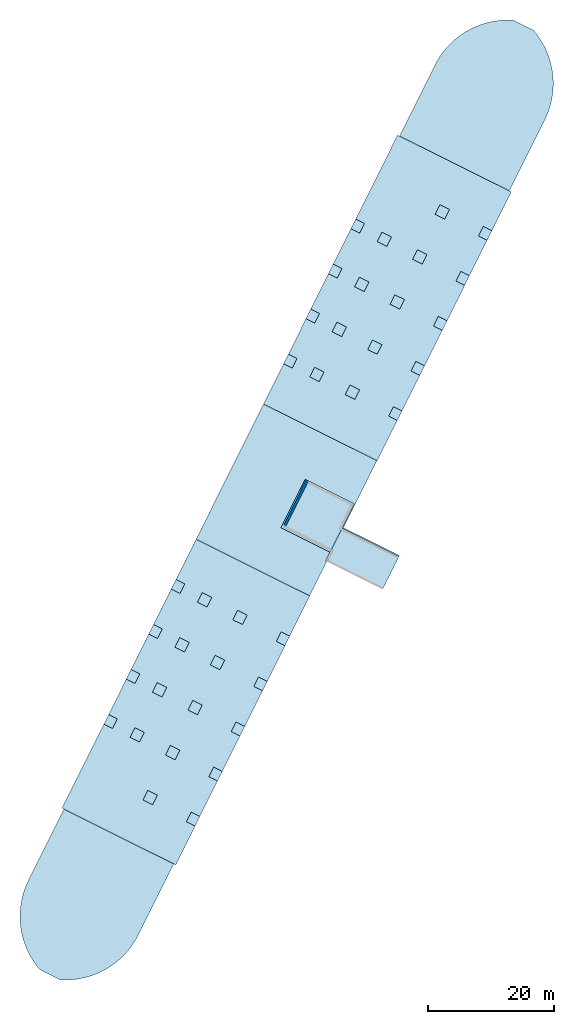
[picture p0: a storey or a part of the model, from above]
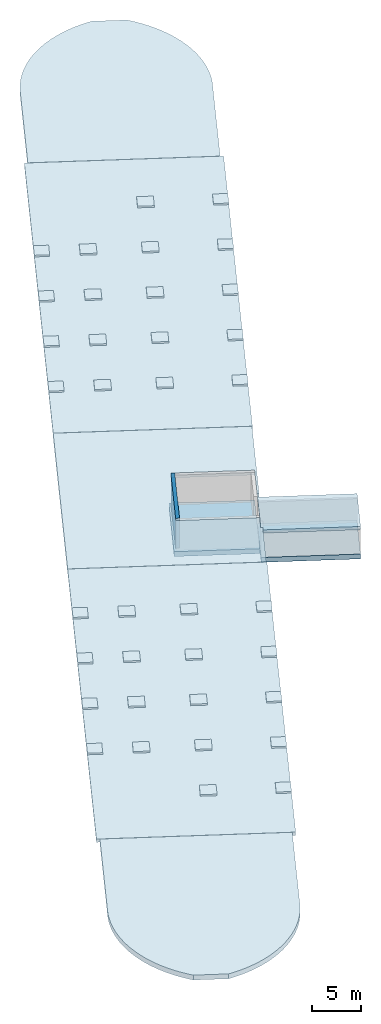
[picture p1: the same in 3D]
Properties of the parts of a building model (IFC2X3), part 1 of 7

# File
Description: ViewDefinition [CoordinationView]
Time: 2016-04-15T14:13:06
Written by: The EXPRESS Data Manager Version 5.02.0100.07 : 28 Aug 2013
Made in: 20140606_1530(x64) - Exporter 2015.0.2014.0606 - Default UI
Comment: STEP Physical File produced by: The EXPRESS Data Manager Version 5.02.0100.07 : 28 Aug 2013 * Module: EDMstepFileFactory/EDMstandAlone * Creation date: Fri Apr 15 14:13:06 2016 * Host: studiopc * Database: C:\Users\FRANCE~1\AppData\Local\Temp\{B8292BB7-F416-45F5-B67B-CA2B80A930D9}\ifc * Database version: 5507 * Database creation date: Fri Apr 15 14:12:46 2016 * Schema: IFC2X3 * Model: DataRepository.ifc * Model creation date: Fri Apr 15 14:12:46 2016 * Header model: DataRepository.ifc_HeaderModel * Header model creation date: Fri Apr 15 14:12:46 2016 * EDMuser: sdai-user * EDMgroup: sdai-group * License ID and type: 5605 : Permanent license. Expiry date: * EDMstepFileFactory options: 020000

# IfcProject
LongName: C:\Users\Francesco\Google Drive\GM Polito\04_APPALTO\IFC\000070_000_RVM_RIL.ifc

# IfcSite, Default
RefLatitude: 41, 53, 43, 677062; RefLongitude: 12, 28, 56, 368560; RefElevation: 250.6 m
Altro - Categoria: Informazioni sul progetto

# IfcBuilding
Pset_BuildingCommon - NumberOfStoreys: 5
Altro - Categoria: Informazioni sul progetto

# IfcBuildingStorey (5)
Altro - Categoria: Livelli; Famiglia: Livello: Livello; Famiglia e tipo: Livello: Livello; ID tipo: Livello: Livello; Tipo: Livello: Livello; Nome famiglia: Livello
Dati identità - Piano edificio: yes; Nome del tipo: Livello
Dimensioni - Altezza di calcolo: 0 m
Grafica - Colore: 0; Modello di linea: Tratto; Simbolo: Estremità Livello: Triangolo; Simbolo a estremità 1 per default: no; Simbolo a estremità 2 per default: yes; Spessore di linea: 1
Vincoli - Base quota altimetrica: Punto base progetto
Name | LongName = Nome | Elevation (m) = Quota altimetrica (m) | Strutturale
SF_STR_0100_XY- Fondazioni (-0,40) | SF_STR_0100_XY- Fondazioni (-0,40) | -0.4 | yes
0 - Piano Terra | 0 - Piano Terra | 0 | no
1 - Piano Primo | 1 - Piano Primo | 4.69 | no
2 - Piano Secondo | 2 - Piano Secondo | 8.61 | no
3 - Piano Copertura | 3 - Piano Copertura | 11.95 | no

# IfcSpace (42)
InteriorOrExteriorSpace: INTERNAL
Altro - Categoria: Locali; Id fase: Stato di Fatto
Analisi energetica - Area per persona: 28.5714 m2; Attiva carico di alimentazione di base: <Default>; Attiva carico luce di base: <Default>; Carico alimentazione effettivo: 0 W; Carico alimentazione effettivo per area: 0; Carico di alimentazione specificato: 0 W; Carico di alimentazione specificato per area: 13.9931; Carico luce effettivo: 0 W; Carico luce effettivo per area: 0; Carico luce specificato: 0 W; Carico luce specificato per area: 10.7639; Contributo di illuminazione vano tecnico: 0.2; Incremento calore latente per persona: 630.918; Incremento calore percepito per persona: 788.648; Incremento calore totale per persona: 1419.57; Numero di persone: 0; Unità carico di alimentazione: Densità alimentazione; Unità carico luce: Densità alimentazione; Valori carico di riscaldamento: <Default>
Dimensioni - Altezza di calcolo: 0 m
Fasi - Fase: Stato di Fatto
Name | In | LongName = Nome | GSA Space Areas (m2) = Area (m2) | Reference | Numero | Altezza non delimitata (m) | Perimetro (m) | Volume (m3) | Limite superiore | Livello | Offset base (m) | Offset limite (m)
3 | 0 - Piano Terra | Deposito oli | 36.2366 | Deposito oli 3 | 3 | 4.29 | 24.8514 | 155.455 | Livello: 0 - Piano Terra | Livello: 0 - Piano Terra | 0 | 4.29
4 | 0 - Piano Terra | Locale | 33.6215 | Locale 4 | 4 | 4.29 | 25.3135 | 143.98 | Livello: 0 - Piano Terra | Livello: 0 - Piano Terra | 0 | 4.29
5 | 0 - Piano Terra | Gruppo elettrogeno | 38.0065 | Gruppo elettrogeno 5 | 5 | 4.29 | 25.3081 | 163.048 | Livello: 0 - Piano Terra | Livello: 0 - Piano Terra | 0 | 4.29
6 | 0 - Piano Terra | Gruppo di pressurizzazione sprinkler-antincendio | 59.008 | Gruppo di pressurizzazione sprinkler-antincendio 6 | 6 | 4.29 | 31.8649 | 252.889 | Livello: 0 - Piano Terra | 0 - Piano Terra | 0 | 4.29
7 | 0 - Piano Terra | Centrale idrica | 48.9236 | Centrale idrica 7 | 7 | 4.29 | 29.2624 | 209.627 | Livello: 0 - Piano Terra | 0 - Piano Terra | 0 | 4.29
8 | 0 - Piano Terra | Consegna teleriscaldamento | 52.4322 | Consegna teleriscaldamento 8 | 8 | 4.29 | 30.1679 | 224.679 | Livello: 0 - Piano Terra | Livello: 0 - Piano Terra | 0 | 4.29
9 | 0 - Piano Terra | Carica batterie e deposito muletti | 45.5483 | Carica batterie e deposito muletti 9 | 9 | 4.29 | 28.3914 | 195.146 | Livello: 0 - Piano Terra | 0 - Piano Terra | 0 | 4.29
10 | 0 - Piano Terra | Barili diesel speciali | 36.6373 | Barili diesel speciali 10 | 10 | 4.29 | 24.9548 | 157.174 | Livello: 0 - Piano Terra | Livello: 0 - Piano Terra | 0 | 4.29
11 | 0 - Piano Terra | Locale quadri elettrici e apparecchiature di controllo autorimessa | 22.04 | Locale quadri elettrici e apparecchiature di controllo autorimessa 11 | 11 | 4.29 | 21 | 94.5516 | Livello: 0 - Piano Terra | 0 - Piano Terra | 0 | 4.29
12 | 0 - Piano Terra | Deposito | 11.0713 | Deposito 12 | 12 | 8.33 | 14.1212 | 92.2242 | Livello: 0 - Piano Terra | Livello: 0 - Piano Terra | 0 | 8.33
13 | 0 - Piano Terra | Locale bombole infiammabili | 11.7486 | Locale bombole infiammabili 13 | 13 | 10.85 | 14.6988 | 127.472 | Livello: 0 - Piano Terra | Livello: 0 - Piano Terra | 0 | 10.85
14 | 0 - Piano Terra | Locale | 10.7987 | Locale 14 | 14 | 8.33 | 14.3188 | 89.9532 | Livello: 0 - Piano Terra | 0 - Piano Terra | 0 | 8.33
15 | 0 - Piano Terra | Locale | 26.9342 | Locale 15 | 15 | 4.29 | 30.7972 | 115.263 | Livello: 0 - Piano Terra | Livello: 0 - Piano Terra | 0 | 4.29
21 | 0 - Piano Terra | Locale | 57.8451 | Locale 21 | 21 | 4.29 | 30.6352 | 248.029 | Livello: 0 - Piano Terra | Livello: 0 - Piano Terra | 0 | 4.29
17 | 0 - Piano Terra | Locale bombole gas di calibrazione | 48.9316 | Locale bombole gas di calibrazione 17 | 17 | 10.86 | 30.58 | 510.626 | Livello: 0 - Piano Terra | 0 - Piano Terra | 0 | 10.86
18 | 0 - Piano Terra | Locale | 8.6832 | Locale 18 | 18 | 8.33 | 12.36 | 72.3311 | Livello: 0 - Piano Terra | Livello: 0 - Piano Terra | 0 | 8.33
20 | 0 - Piano Terra | Locale biciclette | 62.6148 | Locale biciclette 20 | 20 | 4.29 | 31.5859 | 268.434 | Livello: 0 - Piano Terra | 0 - Piano Terra | 0 | 4.29
19 | 0 - Piano Terra | Deposito | 259.894 | Deposito 19 | 19 | 4.29 | 84.7233 | 1112.74 | Livello: 0 - Piano Terra | Livello: 0 - Piano Terra | 0 | 4.29
2 | 0 - Piano Terra | Deposito | 21.606 | Deposito 2 | 2 | 4.29 | 21.34 | 92.6898 | Livello: 0 - Piano Terra | 0 - Piano Terra | 0 | 4.29
1 | 0 - Piano Terra | Deposito | 12.9422 | Deposito 1 | 1 | 8.21 | 18.132 | 106.256 | Livello: 0 - Piano Terra | Livello: 0 - Piano Terra | 0 | 8.21
16 | 0 - Piano Terra | Locale tecnico analisi gas | 23.5989 | Locale tecnico analisi gas 16 | 16 | 4.29 | 19.8327 | 100.827 | Livello: 0 - Piano Terra | Livello: 0 - Piano Terra | 0 | 4.29
22 | 0 - Piano Terra | Garbage | 11.0261 | Garbage 22 | 22 | 8.95 | 15.0395 | 98.6767 | Livello: 0 - Piano Terra | 0 - Piano Terra | 0 | 8.95
23 | 0 - Piano Terra | Oli esausti | 11.4824 | Oli esausti 23 | 23 | 8.95 | 15.391 | 102.768 | Livello: 0 - Piano Terra | Livello: 0 - Piano Terra | 0 | 8.95
24 | 0 - Piano Terra | Deposito bombolo vuote | 11.1803 | Deposito bombolo vuote 24 | 24 | 8.95 | 15.2133 | 100.064 | Livello: 0 - Piano Terra | 0 - Piano Terra | 0 | 8.95
25 | 0 - Piano Terra | Deposito nitrogeno | 10.9086 | Deposito nitrogeno 25 | 25 | 12.2058 | 15.0733 | 97.8209 | Livello: 0 - Piano Terra | Livello: 0 - Piano Terra | -3.2558 | 8.95
26 | 0 - Piano Terra | Corpo scala | 34.0184 | Corpo scala 26 | 26 | 4.69635 | 31.47 | 153.895 | Livello: 0 - Piano Terra | 0 - Piano Terra | -0.00634704 | 4.69
27 | 0 - Piano Terra | Corpo scala | 36.312 | Corpo scala 27 | 27 | 4.69 | 32.41 | 163.528 | Livello: 0 - Piano Terra | 0 - Piano Terra | 0 | 4.69
28 | 0 - Piano Terra | Corpo scala | 34.0184 | Corpo scala 28 | 28 | 4.69 | 31.47 | 153.895 | Livello: 0 - Piano Terra | Livello: 0 - Piano Terra | 0 | 4.69
29 | 0 - Piano Terra | Locale tecnico | 66.511 | Locale tecnico 29 | 29 | 2 | 38.1145 | 132.968 | Livello: 0 - Piano Terra | 0 - Piano Terra | 0 | 2
30 | 0 - Piano Terra | Locale tecnico | 69.5618 | Locale tecnico 30 | 30 | 2 | 39.3326 | 139.124 | Livello: 0 - Piano Terra | 0 - Piano Terra | 0 | 2
31 | 0 - Piano Terra | Deposito gomme | 22.714 | Deposito gomme 31 | 31 | 4.29 | 22.14 | 97.3733 | Livello: 0 - Piano Terra | 0 - Piano Terra | 0 | 4.29
41 | 0 - Piano Terra | Vasca di accumulo sprinkler | 54.0422 | Vasca di accumulo sprinkler 41 | 41 | 11.26 | 27.3109 | 608.514 | Livello: 0 - Piano Terra | 0 - Piano Terra | 0 | 11.26
42 | 0 - Piano Terra | Vasca di accumulo sprinkler | 54.257 | Vasca di accumulo sprinkler 42 | 42 | 11.26 | 27.3699 | 610.564 | Livello: 0 - Piano Terra | 0 - Piano Terra | 0 | 11.26
32 | 1 - Piano Primo | Corpo scala | 35.1848 | Corpo scala 32 | 32 | 3.92 | 24.18 | 131.967 | Livello: 1 - Piano Primo | Livello: 1 - Piano Primo | 0 | 3.92
33 | 1 - Piano Primo | Corpo scala | 36.312 | Corpo scala 33 | 33 | 3.92 | 32.41 | 135.924 | Livello: 1 - Piano Primo | 1 - Piano Primo | 0 | 3.92
34 | 1 - Piano Primo | Corpo scala | 34.0184 | Corpo scala 34 | 34 | 3.92 | 31.47 | 127.873 | Livello: 1 - Piano Primo | Livello: 1 - Piano Primo | 0 | 3.92
35 | 2 - Piano Secondo | Locale | 35.1848 | Locale 35 | 35 | 2.7 | 24.18 | 94.999 | Livello: 2 - Piano Secondo | Livello: 2 - Piano Secondo | 0 | 2.7
36 | 2 - Piano Secondo | Locale | 37.4784 | Locale 36 | 36 | 2.7 | 25.12 | 101.192 | Livello: 2 - Piano Secondo | Livello: 2 - Piano Secondo | 0 | 2.7
37 | 2 - Piano Secondo | Locale | 35.1848 | Locale 37 | 37 | 2.7 | 24.18 | 94.999 | Livello: 2 - Piano Secondo | Livello: 2 - Piano Secondo | 0 | 2.7
38 | 2 - Piano Secondo | Locale | 15.656 | Locale 38 | 38 | 2.4384 | 19.32 | 38.1756 | Livello: 2 - Piano Secondo | Livello: 2 - Piano Secondo | 0 | 2.4384
39 | 2 - Piano Secondo | Locale | 15.4088 | Locale 39 | 39 | 2.4384 | 19.08 | 37.5728 | Livello: 2 - Piano Secondo | 2 - Piano Secondo | 0 | 2.4384
40 | 2 - Piano Secondo | Locale | 13.8422 | Locale 40 | 40 | 2.60145 | 16.5277 | 33.9135 | Livello: 2 - Piano Secondo | Livello: 2 - Piano Secondo | -0.05145 | 2.55

# IfcBeam: Prefabbricato - Trave rettangolare:TRave pref - 60 x 26:167918 (48)
Pset_BeamCommon - LoadBearing: yes; IsExternal: no; Reference: TRave pref - 60 x 26; Slope: 0 deg
Altro - Categoria: Telaio strutturale; Famiglia: Prefabbricato - Trave rettangolare: TRave pref - 60 x 26; Famiglia e tipo: Prefabbricato - Trave rettangolare: TRave pref - 60 x 26; ID tipo: Prefabbricato - Trave rettangolare: TRave pref - 60 x 26; Tipo: Prefabbricato - Trave rettangolare: TRave pref - 60 x 26; Nome famiglia: Prefabbricato - Trave rettangolare
Fasi - Fase di creazione: Stato di Fatto
Posizione geometrica - Giustificazione Y: Origine; Giustificazione YZ: Uniforme; Giustificazione Z: Parte superiore; Stato giunto: Entrambi i giunti attivati; Valore di offset Y: 0 m; Valore di offset Z: 0 m
Strutturale - Attiva modello analitico: yes; Copriferro armatura - Altre superfici: Impostazioni copriferro armatura: Copriferro armatura 1; Copriferro armatura - Superficie inferiore: Impostazioni copriferro armatura: Copriferro armatura 1; Copriferro armatura - Superficie superiore: Impostazioni copriferro armatura: Copriferro armatura 1; Forma sezione: 0
Vincoli - Offset livello finale: -0.4 m; Offset livello iniziale: -0.4 m; Rotazione trasversale: 0 deg
Dati identità - Nome del tipo: TRave pref - 60 x 26
Dimensioni - b: 0.6 m; h: 0.26 m
Name (Prefabbricato - Trave rettangolare:TRave pref - 60 x 26:...) | In | Span (m) = Lunghezza (m) | Area (m2) | Volume (m3) | Estensione finale (m) | Estensione iniziale (m) | Taglio giunto iniziale (m) | Lunghezza del taglio (m) | Utilizzo strutturale | Livello di riferimento
206021 | 1 - Piano Primo | 7.482 | 6.57332 | 1.16407 | 0 | 0 | -0.29 | 7.462 | Trave primaria | Livello: 1 - Piano Primo | Posizione geometrica - Taglio giunto terminale: -0.29 m; Strutturale - Tipo di associazione fine: Quota altimetrica estremità; Tipo di associazione inizio: Quota altimetrica estremità
206023 | 1 - Piano Primo | 8 | 6.67308 | 1.18217 | 0 | 0 | 0 | 7.578 | Trave primaria | Livello: 1 - Piano Primo | Posizione geometrica - Taglio giunto terminale: -0.29 m; Strutturale - Tipo di associazione fine: Quota altimetrica estremità
206025 | 1 - Piano Primo | 7.482 | 6.5759 | 1.16454 | 0 | 0 | -0.29 | 7.465 | Trave primaria | Livello: 1 - Piano Primo | Posizione geometrica - Taglio giunto terminale: -0.29 m; Strutturale - Tipo di associazione fine: Quota altimetrica estremità; Tipo di associazione inizio: Quota altimetrica estremità
206027 | 1 - Piano Primo | 7.482 | 6.57418 | 1.16423 | 0 | 0 | -0.29 | 7.463 | Trave primaria | Livello: 1 - Piano Primo | Posizione geometrica - Taglio giunto terminale: -0.29 m; Strutturale - Tipo di associazione fine: Quota altimetrica estremità; Tipo di associazione inizio: Quota altimetrica estremità
206029 | 1 - Piano Primo | 7.36 | 6.4899 | 1.14894 | 0 | 0 | -0.29 | 7.365 | Trave primaria | Livello: 1 - Piano Primo | Strutturale - Tipo di associazione inizio: Quota altimetrica estremità
206195 | 1 - Piano Primo | 7.482 | 6.57332 | 1.16407 | 0 | 0 | -0.29 | 7.462 | Trave primaria | Livello: 1 - Piano Primo | Posizione geometrica - Taglio giunto terminale: -0.29 m; Strutturale - Tipo di associazione fine: Quota altimetrica estremità; Tipo di associazione inizio: Quota altimetrica estremità
206197 | 1 - Piano Primo | 7.482 | 6.5759 | 1.16454 | 0 | 0 | -0.29 | 7.465 | Trave primaria | Livello: 1 - Piano Primo | Posizione geometrica - Taglio giunto terminale: -0.29 m; Strutturale - Tipo di associazione fine: Quota altimetrica estremità; Tipo di associazione inizio: Quota altimetrica estremità
206199 | 1 - Piano Primo | 7.482 | 6.57418 | 1.16423 | 0 | 0 | -0.29 | 7.463 | Trave primaria | Livello: 1 - Piano Primo | Posizione geometrica - Taglio giunto terminale: -0.29 m; Strutturale - Tipo di associazione fine: Quota altimetrica estremità; Tipo di associazione inizio: Quota altimetrica estremità
206201 | 1 - Piano Primo | 7.36 | 6.5071 | 1.15206 | 0 | 0 | -0.29 | 7.385 | Trave primaria | Livello: 1 - Piano Primo | Strutturale - Tipo di associazione inizio: Quota altimetrica estremità
206203 | 1 - Piano Primo | 8.183 | 6.56558 | 1.16267 | 0 | 0 | -0.29 | 7.453 | Trave primaria | Livello: 1 - Piano Primo | Posizione geometrica - Taglio giunto terminale: -0.29 m; Strutturale - Tipo di associazione fine: Quota altimetrica estremità; Tipo di associazione inizio: Quota altimetrica estremità
206205 | 1 - Piano Primo | 7.549 | 6.2749 | 1.10994 | 0 | 0 | -0.29 | 7.115 | Altro | Livello: 1 - Piano Primo | Strutturale - Tipo di associazione inizio: Quota altimetrica estremità
206209 | 1 - Piano Primo | 7.32 | 6.4512 | 1.14192 | 0 | 0 |  | 7.32 | Trave primaria | Livello: 1 - Piano Primo
206597 | 1 - Piano Primo | 7.4 | 6.53032 | 1.15627 | -0.4 | 0 |  | 7.412 | Altro | Livello: 1 - Piano Primo | Posizione geometrica - Taglio giunto terminale: -0.29 m; Strutturale - Tipo di associazione fine: Quota altimetrica estremità
206599 | 1 - Piano Primo | 7.473 | 6.56558 | 1.16267 | -0.4 | -0.4 | -0.29 | 7.453 | Trave primaria | Livello: 1 - Piano Primo | Posizione geometrica - Taglio giunto terminale: -0.29 m; Strutturale - Tipo di associazione fine: Quota altimetrica estremità; Tipo di associazione inizio: Quota altimetrica estremità
206601 | 1 - Piano Primo | 7.5 | 6.56902 | 1.16329 | -0.4 | -0.4 | -0.29 | 7.457 | Trave primaria | Livello: 1 - Piano Primo | Posizione geometrica - Taglio giunto terminale: -0.29 m; Strutturale - Tipo di associazione fine: Quota altimetrica estremità; Tipo di associazione inizio: Quota altimetrica estremità
206603 | 1 - Piano Primo | 7.473 | 6.56558 | 1.16267 | -0.4 | -0.4 | -0.29 | 7.453 | Trave primaria | Livello: 1 - Piano Primo | Posizione geometrica - Taglio giunto terminale: -0.29 m; Strutturale - Tipo di associazione fine: Quota altimetrica estremità; Tipo di associazione inizio: Quota altimetrica estremità
206605 | 1 - Piano Primo | 7.099 | 6.26028 | 1.10729 | -0.01 | -0.4 | -0.29 | 7.098 | Altro | Livello: 1 - Piano Primo | Strutturale - Tipo di associazione inizio: Quota altimetrica estremità
206607 | 1 - Piano Primo | 7.473 | 6.56988 | 1.16345 | -0.4 | -0.4 | -0.29 | 7.458 | Trave primaria | Livello: 1 - Piano Primo | Posizione geometrica - Taglio giunto terminale: -0.29 m; Strutturale - Tipo di associazione fine: Quota altimetrica estremità; Tipo di associazione inizio: Quota altimetrica estremità
206609 | 1 - Piano Primo | 7.4 | 6.53032 | 1.15627 | -0.4 | 0 |  | 7.412 | Altro | Livello: 1 - Piano Primo | Posizione geometrica - Taglio giunto terminale: -0.29 m; Strutturale - Tipo di associazione fine: Quota altimetrica estremità
206611 | 1 - Piano Primo | 7.473 | 6.56558 | 1.16267 | -0.4 | -0.4 | -0.29 | 7.453 | Trave primaria | Livello: 1 - Piano Primo | Posizione geometrica - Taglio giunto terminale: -0.29 m; Strutturale - Tipo di associazione fine: Quota altimetrica estremità; Tipo di associazione inizio: Quota altimetrica estremità
206613 | 1 - Piano Primo | 7.5 | 6.56816 | 1.16314 | -0.4 | -0.4 | -0.29 | 7.456 | Trave primaria | Livello: 1 - Piano Primo | Posizione geometrica - Taglio giunto terminale: -0.29 m; Strutturale - Tipo di associazione fine: Quota altimetrica estremità; Tipo di associazione inizio: Quota altimetrica estremità
206615 | 1 - Piano Primo | 7.473 | 6.56558 | 1.16267 | -0.4 | -0.4 | -0.29 | 7.453 | Trave primaria | Livello: 1 - Piano Primo | Posizione geometrica - Taglio giunto terminale: -0.29 m; Strutturale - Tipo di associazione fine: Quota altimetrica estremità; Tipo di associazione inizio: Quota altimetrica estremità
206617 | 1 - Piano Primo | 7.5 | 6.66276 | 1.1803 | -0.01 | -0.4 | -0.29 | 7.566 | Altro | Livello: 1 - Piano Primo | Strutturale - Tipo di associazione inizio: Quota altimetrica estremità
206763 | 2 - Piano Secondo | 8 | 6.90184 | 1.22366 | 0 | 0 | 0 | 7.844 | Trave primaria | Livello: 2 - Piano Secondo | Posizione geometrica - Taglio giunto terminale: 0 m
206765 | 1 - Piano Primo | 7.649 | 6.60084 | 1.16906 | 0 | 0 | 0 | 7.494 | Altro | Livello: 1 - Piano Primo
206767 | 2 - Piano Secondo | 7.746 | 7.04116 | 1.24894 | 0.26 | 0 | 0 | 8.006 | Trave primaria | Livello: 2 - Piano Secondo
206769 | 2 - Piano Secondo | 7.482 | 7.03772 | 1.24831 | 0.26 | 0.26 |  | 8.002 | Trave primaria | Livello: 2 - Piano Secondo
206771 | 2 - Piano Secondo | 7.482 | 7.03772 | 1.24831 | 0.26 | 0.26 |  | 8.002 | Trave primaria | Livello: 2 - Piano Secondo
206773 | 2 - Piano Secondo | 7.36 | 6.7092 | 1.18872 | 0 | 0.26 |  | 7.62 | Trave primaria | Livello: 2 - Piano Secondo
206835 | 2 - Piano Secondo | 7.4 | 6.7608 | 1.19808 | 0.28 | 0 |  | 7.68 | Altro | Livello: 2 - Piano Secondo
206837 | 2 - Piano Secondo | 7.473 | 7.02998 | 1.24691 | 0.26 | 0.26 |  | 7.993 | Trave primaria | Livello: 2 - Piano Secondo
206839 | 2 - Piano Secondo | 7.5 | 7.0446 | 1.24956 | 0.25 | 0.26 |  | 8.01 | Trave primaria | Livello: 2 - Piano Secondo
206841 | 2 - Piano Secondo | 7.473 | 7.01063 | 1.2434 | 0.25 | 0.25 |  | 7.9705 | Trave primaria | Livello: 2 - Piano Secondo
206843 | 2 - Piano Secondo | 7.584 | 6.90184 | 1.22366 | 0 | 0.26 |  | 7.844 | Altro | Livello: 2 - Piano Secondo
206845 | 2 - Piano Secondo | 7.649 | 6.60084 | 1.16906 | 0 | 0 | 0 | 7.494 | Altro | Livello: 2 - Piano Secondo
206873 | 2 - Piano Secondo | 7.679 | 6.75994 | 1.19792 | 0 | 0 |  | 7.679 | Altro | Livello: 2 - Piano Secondo | Posizione geometrica - Taglio giunto terminale: 0 m
206901 | 2 - Piano Secondo | 7.382 | 6.50452 | 1.15159 | 0 | 0 | 0 | 7.382 | Altro | Livello: 2 - Piano Secondo
206945 | 2 - Piano Secondo | 7.48 | 6.5888 | 1.16688 | 0 | 0 |  | 7.48 | Trave primaria | Livello: 2 - Piano Secondo
207009 | 2 - Piano Secondo | 7.399 | 6.74274 | 1.1948 | 0 | 0.26 |  | 7.659 | Altro | Livello: 2 - Piano Secondo
207083 | 2 - Piano Secondo | 8 | 7.03514 | 1.24784 | 0 | 0.26 | 0 | 7.999 | Altro | Livello: 2 - Piano Secondo
207085 | 2 - Piano Secondo | 8 | 7.036 | 1.248 | 0 | 0.26 | 0 | 8 | Altro | Livello: 2 - Piano Secondo
207087 | 2 - Piano Secondo | 8 | 7.036 | 1.248 | 0 | 0.26 | 0 | 8 | Altro | Livello: 2 - Piano Secondo
207089 | 2 - Piano Secondo | 7.999 | 7.03514 | 1.24784 | 0 | 0.26 | 0 | 7.999 | Altro | Livello: 2 - Piano Secondo
207091 | 2 - Piano Secondo | 7.1 | 6.5028 | 1.15128 | 0.28 | 0.26 | 0 | 7.38 | Altro | Livello: 2 - Piano Secondo
207101 | 2 - Piano Secondo | 7.999 | 7.03514 | 1.24784 | 0 | 0 |  | 7.999 | Altro | Livello: 2 - Piano Secondo | Posizione geometrica - Taglio giunto terminale: 0 m
207103 | 2 - Piano Secondo | 8 | 7.03514 | 1.24784 | 0 | 0 |  | 7.999 | Altro | Livello: 2 - Piano Secondo | Posizione geometrica - Taglio giunto terminale: 0 m
207105 | 2 - Piano Secondo | 8 | 7.03514 | 1.24784 | 0 | 0 |  | 7.999 | Altro | Livello: 2 - Piano Secondo | Posizione geometrica - Taglio giunto terminale: 0 m
207107 | 2 - Piano Secondo | 7.98 | 7.01794 | 1.24472 | 0 | 0 |  | 7.979 | Altro | Livello: 2 - Piano Secondo | Posizione geometrica - Taglio giunto terminale: 0 m

# IfcBeam: Prefabbricato - Trave rettangolare:TRave pref - 80 x 26:167920 (52)
Pset_BeamCommon - LoadBearing: yes; IsExternal: no; Slope: 0 deg; Reference: TRave pref - 80 x 26
Altro - Categoria: Telaio strutturale; Famiglia: Prefabbricato - Trave rettangolare: TRave pref - 80 x 26; Famiglia e tipo: Prefabbricato - Trave rettangolare: TRave pref - 80 x 26; ID tipo: Prefabbricato - Trave rettangolare: TRave pref - 80 x 26; Tipo: Prefabbricato - Trave rettangolare: TRave pref - 80 x 26; Nome famiglia: Prefabbricato - Trave rettangolare
Fasi - Fase di creazione: Stato di Fatto
Posizione geometrica - Giustificazione Y: Origine; Giustificazione YZ: Uniforme; Giustificazione Z: Parte superiore; Stato giunto: Entrambi i giunti attivati; Valore di offset Y: 0 m; Valore di offset Z: 0 m
Strutturale - Attiva modello analitico: yes; Copriferro armatura - Altre superfici: Impostazioni copriferro armatura: Copriferro armatura 1; Copriferro armatura - Superficie inferiore: Impostazioni copriferro armatura: Copriferro armatura 1; Copriferro armatura - Superficie superiore: Impostazioni copriferro armatura: Copriferro armatura 1; Forma sezione: 0
Vincoli - Rotazione trasversale: 0 deg; Offset livello finale: -0.4 m; Offset livello iniziale: -0.4 m
Dati identità - Nome del tipo: TRave pref - 80 x 26
Dimensioni - b: 0.8 m; h: 0.26 m
Name (Prefabbricato - Trave rettangolare:TRave pref - 80 x 26:...) | In | Span (m) = Lunghezza (m) | Area (m2) | Volume (m3) | Estensione finale (m) | Estensione iniziale (m) | Taglio giunto iniziale (m) | Taglio giunto terminale (m) | Utilizzo strutturale | Lunghezza del taglio (m) | Livello di riferimento
206175 | 1 - Piano Primo | 7.482 | 8.13892 | 1.55626 | 0 | 0 | -0.29 | -0.29 | Trave primaria | 7.482 | Livello: 1 - Piano Primo | Strutturale - Tipo di associazione fine: Quota altimetrica estremità; Tipo di associazione inizio: Quota altimetrica estremità
206177 | 1 - Piano Primo | 8.199 | 8.24916 | 1.57789 | 0 | 0 |  | -0.29 | Trave primaria | 7.586 | Livello: 1 - Piano Primo | Strutturale - Tipo di associazione fine: Quota altimetrica estremità
206179 | 1 - Piano Primo | 7.482 | 8.1421 | 1.55688 | 0 | 0 | -0.29 | -0.29 | Trave primaria | 7.485 | Livello: 1 - Piano Primo | Strutturale - Tipo di associazione fine: Quota altimetrica estremità; Tipo di associazione inizio: Quota altimetrica estremità
206181 | 1 - Piano Primo | 7.482 | 8.13998 | 1.55646 | 0 | 0 | -0.29 | -0.29 | Trave primaria | 7.483 | Livello: 1 - Piano Primo | Strutturale - Tipo di associazione fine: Quota altimetrica estremità; Tipo di associazione inizio: Quota altimetrica estremità
206183 | 1 - Piano Primo | 7.38 | 8.0467 | 1.53816 | 0 | 0 | -0.29 |  | Trave primaria | 7.395 | Livello: 1 - Piano Primo | Strutturale - Tipo di associazione inizio: Quota altimetrica estremità
206185 | 1 - Piano Primo | 7.482 | 8.13892 | 1.55626 | 0 | 0 | -0.29 | -0.29 | Trave primaria | 7.482 | Livello: 1 - Piano Primo | Strutturale - Tipo di associazione fine: Quota altimetrica estremità; Tipo di associazione inizio: Quota altimetrica estremità
206187 | 1 - Piano Primo | 8.183 | 8.12938 | 1.55438 | 0 | 0 | -0.29 | -0.29 | Trave primaria | 7.473 | Livello: 1 - Piano Primo | Strutturale - Tipo di associazione fine: Quota altimetrica estremità; Tipo di associazione inizio: Quota altimetrica estremità
206189 | 1 - Piano Primo | 8.525 | 8.1421 | 1.55688 | 0 | 0 | -0.29 | -0.29 | Trave primaria | 7.485 | Livello: 1 - Piano Primo | Strutturale - Tipo di associazione fine: Quota altimetrica estremità; Tipo di associazione inizio: Quota altimetrica estremità
206191 | 1 - Piano Primo | 7.482 | 8.14104 | 1.55667 | 0 | 0 | -0.29 | -0.29 | Trave primaria | 7.484 | Livello: 1 - Piano Primo | Strutturale - Tipo di associazione fine: Quota altimetrica estremità; Tipo di associazione inizio: Quota altimetrica estremità
206193 | 1 - Piano Primo | 7.36 | 8.0467 | 1.53816 | 0 | 0 | -0.29 |  | Trave primaria | 7.395 | Livello: 1 - Piano Primo | Strutturale - Tipo di associazione inizio: Quota altimetrica estremità
206207 | 1 - Piano Primo | 7.73 | 7.75096 | 1.48013 | 0 | 0 |  | -0.29 | Trave primaria | 7.116 | Livello: 1 - Piano Primo | Strutturale - Tipo di associazione fine: Quota altimetrica estremità
206211 | 1 - Piano Primo | 7.46 | 8.1156 | 1.55168 | 0 | 0 |  |  | Trave primaria | 7.46 | Livello: 1 - Piano Primo
206513 | 1 - Piano Primo | 7.898 | 8.26188 | 1.58038 | 0 | 0 | 0 | 0 | Trave primaria | 7.598 | Livello: 1 - Piano Primo
206515 | 1 - Piano Primo | 7.686 | 8.06896 | 1.54253 | -0.01 | -0.3 | -0.29 |  | Altro | 7.416 | Livello: 1 - Piano Primo | Strutturale - Tipo di associazione inizio: Quota altimetrica estremità
206517 | 1 - Piano Primo | 7.993 | 8.12938 | 1.55438 | -0.4 | -0.4 | -0.29 | -0.29 | Trave primaria | 7.473 | Livello: 1 - Piano Primo | Strutturale - Tipo di associazione fine: Quota altimetrica estremità; Tipo di associazione inizio: Quota altimetrica estremità
206519 | 1 - Piano Primo | 7.997 | 8.13362 | 1.55522 | -0.4 | -0.4 | -0.29 | -0.29 | Trave primaria | 7.477 | Livello: 1 - Piano Primo | Strutturale - Tipo di associazione fine: Quota altimetrica estremità; Tipo di associazione inizio: Quota altimetrica estremità
206521 | 1 - Piano Primo | 7.998 | 8.13468 | 1.55542 | -0.4 | -0.4 | -0.29 | -0.29 | Trave primaria | 7.478 | Livello: 1 - Piano Primo | Strutturale - Tipo di associazione fine: Quota altimetrica estremità; Tipo di associazione inizio: Quota altimetrica estremità
206523 | 1 - Piano Primo | 7.4 | 7.74354 | 1.47867 | -0.03 | -0.4 | -0.29 |  | Altro | 7.109 | Livello: 1 - Piano Primo | Strutturale - Tipo di associazione inizio: Quota altimetrica estremità
206525 | 1 - Piano Primo | 7.993 | 8.12938 | 1.55438 | -0.4 | -0.4 | -0.29 | -0.29 | Trave primaria | 7.473 | Livello: 1 - Piano Primo | Strutturale - Tipo di associazione fine: Quota altimetrica estremità; Tipo di associazione inizio: Quota altimetrica estremità
206563 | 1 - Piano Primo | 7.686 | 8.06896 | 1.54253 | -0.01 | -0.3 | -0.29 |  | Altro | 7.416 | Livello: 1 - Piano Primo | Strutturale - Tipo di associazione inizio: Quota altimetrica estremità
206565 | 1 - Piano Primo | 7.993 | 8.12938 | 1.55438 | -0.4 | -0.4 | -0.29 | -0.29 | Trave primaria | 7.473 | Livello: 1 - Piano Primo | Strutturale - Tipo di associazione fine: Quota altimetrica estremità; Tipo di associazione inizio: Quota altimetrica estremità
206567 | 1 - Piano Primo | 7.997 | 8.13362 | 1.55522 | -0.4 | -0.4 | -0.29 | -0.29 | Trave primaria | 7.477 | Livello: 1 - Piano Primo | Strutturale - Tipo di associazione fine: Quota altimetrica estremità; Tipo di associazione inizio: Quota altimetrica estremità
206569 | 1 - Piano Primo | 7.58 | 8.22796 | 1.57373 | -0.01 | -0.4 | -0.29 |  | Trave primaria | 7.566 | Livello: 1 - Piano Primo | Strutturale - Tipo di associazione inizio: Quota altimetrica estremità
206571 | 1 - Piano Primo | 7.993 | 8.12938 | 1.55438 | -0.4 | -0.4 | -0.29 | -0.29 | Trave primaria | 7.473 | Livello: 1 - Piano Primo | Strutturale - Tipo di associazione fine: Quota altimetrica estremità; Tipo di associazione inizio: Quota altimetrica estremità
206871 | 2 - Piano Secondo | 7.686 | 8.34456 | 1.59661 | -0.01 | 0 | 0 |  | Altro | 7.676 | Livello: 2 - Piano Secondo
206875 | 2 - Piano Secondo | 7.4 | 8.0272 | 1.53433 | -0.0224 | 0 | 0 |  | Altro | 7.3766 | Livello: 2 - Piano Secondo
206903 | 2 - Piano Secondo | 7.836 | 8.51416 | 1.62989 | 0 | 0 | 0 |  | Trave primaria | 7.836 | Livello: 2 - Piano Secondo
206917 | 2 - Piano Secondo | 7.654 | 8.32124 | 1.59203 | 0 | 0 | 0 |  | Trave primaria | 7.654 | Livello: 2 - Piano Secondo
206943 | 2 - Piano Secondo | 7.654 | 8.32124 | 1.59203 | 0 | 0 | 0 |  | Trave primaria | 7.654 | Livello: 2 - Piano Secondo
206947 | 2 - Piano Secondo | 7.5 | 8.15588 | 1.55958 | 0 | 0 |  | -0.153587 | Trave primaria | 7.498 | Livello: 2 - Piano Secondo
207011 | 2 - Piano Secondo | 7.38 | 8.02974 | 1.53483 | 0 | 0 |  | 0 | Trave primaria | 7.379 | Livello: 2 - Piano Secondo
207037 | 2 - Piano Secondo | 7.846 | 8.52476 | 1.63197 | 0 | 0 |  | 0 | Trave primaria | 7.846 | Livello: 2 - Piano Secondo
207051 | 2 - Piano Secondo | 7.6 | 8.2693 | 1.58184 | 0 | 0 |  | -0.155 | Trave primaria | 7.605 | Livello: 2 - Piano Secondo
207077 | 2 - Piano Secondo | 8.002 | 8.69012 | 1.66442 | 0 | 0 |  |  | Altro | 8.002 | Livello: 2 - Piano Secondo
207079 | 2 - Piano Secondo | 8.006 | 8.6933 | 1.66504 | 0 | -0.4 | 0 | 0 | Altro | 8.005 | Livello: 2 - Piano Secondo
207081 | 2 - Piano Secondo | 8.003 | 8.69118 | 1.66462 | 0 | 0 |  |  | Altro | 8.003 | Livello: 2 - Piano Secondo
207093 | 2 - Piano Secondo | 7.993 | 8.68058 | 1.66254 | 0 | 0 |  |  | Altro | 7.993 | Livello: 2 - Piano Secondo
207095 | 2 - Piano Secondo | 8.006 | 8.6933 | 1.66504 | -0.4 | 0 | 0 | 0 | Altro | 8.005 | Livello: 2 - Piano Secondo
207097 | 2 - Piano Secondo | 8.002 | 8.69012 | 1.66442 | 0 | 0 | 0 |  | Altro | 8.002 | Livello: 2 - Piano Secondo
207099 | 2 - Piano Secondo | 8.003 | 8.69118 | 1.66462 | 0 | 0 |  |  | Altro | 8.003 | Livello: 2 - Piano Secondo
207109 | 2 - Piano Secondo | 7.993 | 8.68058 | 1.66254 | 0 | 0 |  |  | Altro | 7.993 | Livello: 2 - Piano Secondo
207111 | 2 - Piano Secondo | 7.998 | 8.68482 | 1.66338 | 0 | 0 | 0 | 0 | Altro | 7.997 | Livello: 2 - Piano Secondo
207113 | 2 - Piano Secondo | 7.993 | 8.68058 | 1.66254 | 0 | 0 |  |  | Altro | 7.993 | Livello: 2 - Piano Secondo
207115 | 2 - Piano Secondo | 7.998 | 8.68588 | 1.66358 | 0 | 0 | 0 |  | Altro | 7.998 | Livello: 2 - Piano Secondo
207129 | 1 - Piano Primo | 7.649 | 8.15164 | 1.55875 | 0 | 0 | 0 |  | Altro | 7.494 | Livello: 1 - Piano Primo
207143 | 2 - Piano Secondo | 7.649 | 8.15164 | 1.55875 | 0 | 0 | 0 |  | Altro | 7.494 | Livello: 2 - Piano Secondo
207145 | 2 - Piano Secondo | 7.686 | 8.34456 | 1.59661 | -0.01 | 0 | 0 |  | Altro | 7.676 | Livello: 2 - Piano Secondo
207159 | 2 - Piano Secondo | 7.993 | 8.68058 | 1.66254 | 0 | 0 |  |  | Altro | 7.993 | Livello: 2 - Piano Secondo
207161 | 2 - Piano Secondo | 7.998 | 8.68482 | 1.66338 | 0 | -0.4 | 0 | 0 | Altro | 7.997 | Livello: 2 - Piano Secondo
207163 | 2 - Piano Secondo | 7.993 | 8.68058 | 1.66254 | 0 | 0 |  |  | Altro | 7.993 | Livello: 2 - Piano Secondo
207165 | 1 - Piano Primo | 7.899 | 8.26294 | 1.58059 | 0 | 0 | 0 | 0 | Trave primaria | 7.599 | Livello: 1 - Piano Primo
208148 | 2 - Piano Secondo | 7.898 | 8.26188 | 1.58038 | 0 | 0 | 0 | 0 | Trave primaria | 7.598 | Livello: 2 - Piano Secondo

# IfcBuildingElementProxy: Mensola C.A. (57)
Material: Calcestruzzo, gettato in opera
Pset_BuildingElementProxyCommon - Reference: Mensola C.A.
Altro - Categoria: Telaio strutturale
Fasi - Fase di creazione: Stato di Fatto
Strutturale - Copriferro armatura: Impostazioni copriferro armatura: Copriferro armatura 1; Utilizzo strutturale: Altro; Forma sezione: 0
Vincoli - Sposta con l'oggetto più vicino: no
Dati identità - Nome del tipo: Mensola C.A.
Name | In | Famiglia = Famiglia e tipo = ID tipo = Tipo | Area (m2) | Volume (m3) | Prospetto (m) | Nome famiglia
Mensola C.A.:Mensola C.A.:206224 | 0 - Piano Terra | Mensola C.A.: Mensola C.A. | 0.18 | 0.072 | 0 | Mensola C.A.
Mensola C.A.1:Mensola C.A.:206236 | 0 - Piano Terra | Mensola C.A.1: Mensola C.A. | 0.18 | 0.072 | 0 | Mensola C.A.1
Mensola C.A.2:Mensola C.A.:206248 | 0 - Piano Terra | Mensola C.A.2: Mensola C.A. | 0.18 | 0.072 | 0 | Mensola C.A.2
Mensola C.A.3:Mensola C.A.:206260 | 0 - Piano Terra | Mensola C.A.3: Mensola C.A. | 0.18 | 0.072 | 0 | Mensola C.A.3
Mensola C.A.4:Mensola C.A.:206272 | 0 - Piano Terra | Mensola C.A.4: Mensola C.A. | 0.18 | 0.072 | 0 | Mensola C.A.4
Mensola C.A.5:Mensola C.A.:206284 | 0 - Piano Terra | Mensola C.A.5: Mensola C.A. | 0.18 | 0.072 | 0 | Mensola C.A.5
Mensola C.A.6:Mensola C.A.:206296 | 0 - Piano Terra | Mensola C.A.6: Mensola C.A. | 0.17982 | 0.071928 | 0 | Mensola C.A.6
Mensola C.A.7:Mensola C.A.:206308 | 0 - Piano Terra | Mensola C.A.7: Mensola C.A. | 0.17982 | 0.071928 | 0 | Mensola C.A.7
Mensola C.A.8:Mensola C.A.:206320 | 0 - Piano Terra | Mensola C.A.8: Mensola C.A. | 0.18 | 0.072 | 0 | Mensola C.A.8
Mensola C.A.9:Mensola C.A.:206332 | 0 - Piano Terra | Mensola C.A.9: Mensola C.A. | 0.18 | 0.072 | 0 | Mensola C.A.9
Mensola C.A.10:Mensola C.A.:206344 | 0 - Piano Terra | Mensola C.A.10: Mensola C.A. | 0.18 | 0.072 |  | Mensola C.A.10
Mensola C.A.11:Mensola C.A.:206356 | 0 - Piano Terra | Mensola C.A.11: Mensola C.A. | 0.18 | 0.072 |  | Mensola C.A.11
Mensola C.A.12:Mensola C.A.:206368 | 0 - Piano Terra | Mensola C.A.12: Mensola C.A. | 0.18 | 0.072 |  | Mensola C.A.12
Mensola C.A.13:Mensola C.A.:206380 | 0 - Piano Terra | Mensola C.A.13: Mensola C.A. | 0.18 | 0.072 |  | Mensola C.A.13
Mensola C.A.14:Mensola C.A.:206392 | 0 - Piano Terra | Mensola C.A.14: Mensola C.A. | 0.18 | 0.072 | 0 | Mensola C.A.14
Mensola C.A.15:Mensola C.A.:206404 | 0 - Piano Terra | Mensola C.A.15: Mensola C.A. | 0.18 | 0.072 | 0 | Mensola C.A.15
Mensola C.A.16:Mensola C.A.:206416 | 0 - Piano Terra | Mensola C.A.16: Mensola C.A. | 0.18 | 0.072 | 0 | Mensola C.A.16
Mensola C.A.17:Mensola C.A.:206428 | 0 - Piano Terra | Mensola C.A.17: Mensola C.A. | 0.18 | 0.072 | 0 | Mensola C.A.17
Mensola C.A.18:Mensola C.A.:206440 | 0 - Piano Terra | Mensola C.A.18: Mensola C.A. | 0.18 | 0.072 | 0 | Mensola C.A.18
Mensola C.A.19:Mensola C.A.:206452 | 0 - Piano Terra | Mensola C.A.19: Mensola C.A. | 0.18 | 0.072 | 0 | Mensola C.A.19
Mensola C.A.20:Mensola C.A.:206464 | 0 - Piano Terra | Mensola C.A.20: Mensola C.A. | 0.18 | 0.072 | 0 | Mensola C.A.20
Mensola C.A.21:Mensola C.A.:206476 | 0 - Piano Terra | Mensola C.A.21: Mensola C.A. | 0.18 | 0.072 | 0 | Mensola C.A.21
Mensola C.A.22:Mensola C.A.:206488 | 0 - Piano Terra | Mensola C.A.22: Mensola C.A. | 0.18 | 0.072 | 0 | Mensola C.A.22
Mensola C.A.23:Mensola C.A.:206500 | 0 - Piano Terra | Mensola C.A.23: Mensola C.A. | 0.18 | 0.072 | 0 | Mensola C.A.23
Mensola C.A.24:Mensola C.A.:206512 | 0 - Piano Terra | Mensola C.A.24: Mensola C.A. | 2.28 | 0.912 | 0 | Mensola C.A.24
Mensola C.A.26:Mensola C.A.:206550 | 0 - Piano Terra | Mensola C.A.26: Mensola C.A. | 0.18 | 0.072 | 0 | Mensola C.A.26
Mensola C.A.27:Mensola C.A.:206562 | 0 - Piano Terra | Mensola C.A.27: Mensola C.A. | 0.18 | 0.072 | 0 | Mensola C.A.27
Mensola C.A.28:Mensola C.A.:206584 | 0 - Piano Terra | Mensola C.A.28: Mensola C.A. | 0.18 | 0.072 | 0 | Mensola C.A.28
Mensola C.A.29:Mensola C.A.:206596 | 0 - Piano Terra | Mensola C.A.29: Mensola C.A. | 0.18 | 0.072 | 0 | Mensola C.A.29
Mensola C.A.25:Mensola C.A.:206762 | 1 - Piano Primo | Mensola C.A.25: Mensola C.A. | 0.18 | 0.072 | 0 | Mensola C.A.25
Mensola C.A.30:Mensola C.A.:206786 | 1 - Piano Primo | Mensola C.A.30: Mensola C.A. | 0.18 | 0.072 | 0 | Mensola C.A.30
Mensola C.A.31:Mensola C.A.:206798 | 1 - Piano Primo | Mensola C.A.31: Mensola C.A. | 0.18 | 0.072 | 0 | Mensola C.A.31
Mensola C.A.32:Mensola C.A.:206810 | 1 - Piano Primo | Mensola C.A.32: Mensola C.A. | 0.18 | 0.072 | 0 | Mensola C.A.32
Mensola C.A.33:Mensola C.A.:206822 | 1 - Piano Primo | Mensola C.A.33: Mensola C.A. | 0.18 | 0.072 | 0 | Mensola C.A.33
Mensola C.A.34:Mensola C.A.:206834 | 1 - Piano Primo | Mensola C.A.34: Mensola C.A. | 0.18 | 0.072 | 0 | Mensola C.A.34
Mensola C.A.35:Mensola C.A.:206858 | 1 - Piano Primo | Mensola C.A.35: Mensola C.A. | 0.18 | 0.072 | 0 | Mensola C.A.35
Mensola C.A.36:Mensola C.A.:206870 | 1 - Piano Primo | Mensola C.A.36: Mensola C.A. | 0.18 | 0.072 | 0 | Mensola C.A.36
Mensola C.A.37:Mensola C.A.:206888 | 1 - Piano Primo | Mensola C.A.37: Mensola C.A. | 0.18 | 0.072 | 0 | Mensola C.A.37
Mensola C.A.38:Mensola C.A.:206900 | 1 - Piano Primo | Mensola C.A.38: Mensola C.A. | 0.18 | 0.072 | 0 | Mensola C.A.38
Mensola C.A.39:Mensola C.A.:206916 | 1 - Piano Primo | Mensola C.A.39: Mensola C.A. | 0.18 | 0.072 | 0 | Mensola C.A.39
Mensola C.A.40:Mensola C.A.:206930 | 1 - Piano Primo | Mensola C.A.40: Mensola C.A. | 0.18 | 0.072 | 0 | Mensola C.A.40
Mensola C.A.41:Mensola C.A.:206942 | 1 - Piano Primo | Mensola C.A.41: Mensola C.A. | 0.18 | 0.072 | 0 | Mensola C.A.41
Mensola C.A.42:Mensola C.A.:206960 | 1 - Piano Primo | Mensola C.A.42: Mensola C.A. | 0.18 | 0.072 | 0 | Mensola C.A.42
Mensola C.A.43:Mensola C.A.:206972 | 1 - Piano Primo | Mensola C.A.43: Mensola C.A. | 0.18 | 0.072 | 0 | Mensola C.A.43
Mensola C.A.44:Mensola C.A.:206984 | 1 - Piano Primo | Mensola C.A.44: Mensola C.A. | 0.18 | 0.072 | 0 | Mensola C.A.44
Mensola C.A.45:Mensola C.A.:206996 | 1 - Piano Primo | Mensola C.A.45: Mensola C.A. | 0.18 | 0.072 | 0 | Mensola C.A.45
Mensola C.A.46:Mensola C.A.:207008 | 1 - Piano Primo | Mensola C.A.46: Mensola C.A. | 0.18 | 0.072 | 0 | Mensola C.A.46
Mensola C.A.47:Mensola C.A.:207024 | 1 - Piano Primo | Mensola C.A.47: Mensola C.A. | 0.18 | 0.072 | 0 | Mensola C.A.47
Mensola C.A.48:Mensola C.A.:207036 | 1 - Piano Primo | Mensola C.A.48: Mensola C.A. | 0.18 | 0.072 | 0 | Mensola C.A.48
Mensola C.A.49:Mensola C.A.:207050 | 1 - Piano Primo | Mensola C.A.49: Mensola C.A. | 0.18 | 0.072 | 0 | Mensola C.A.49
Mensola C.A.50:Mensola C.A.:207064 | 1 - Piano Primo | Mensola C.A.50: Mensola C.A. | 0.18 | 0.072 | 0 | Mensola C.A.50
Mensola C.A.51:Mensola C.A.:207076 | 1 - Piano Primo | Mensola C.A.51: Mensola C.A. | 0.18 | 0.072 | 0 | Mensola C.A.51
Mensola C.A.52:Mensola C.A.:207128 | 1 - Piano Primo | Mensola C.A.52: Mensola C.A. | 0.18 | 0.072 | 0 | Mensola C.A.52
Mensola C.A.53:Mensola C.A.:207142 | 1 - Piano Primo | Mensola C.A.53: Mensola C.A. | 0.18 | 0.072 | 0 | Mensola C.A.53
Mensola C.A.54:Mensola C.A.:207158 | 1 - Piano Primo | Mensola C.A.54: Mensola C.A. | 0.18 | 0.072 | 0 | Mensola C.A.54
Mensola C.A.55:Mensola C.A.:208161 | 1 - Piano Primo | Mensola C.A.55: Mensola C.A. | 0.18 | 0.072 | 0 | Mensola C.A.55
Mensola C.A.56:Mensola C.A.:208173 | 1 - Piano Primo | Mensola C.A.56: Mensola C.A. | 0.18 | 0.072 | 0 | Mensola C.A.56

# IfcBuildingElementProxy: Mensola allungata (8)
Material: Calcestruzzo, gettato in opera
Pset_BuildingElementProxyCommon - Reference: Mensola allungata
Altro - Categoria: Telaio strutturale
Fasi - Fase di creazione: Stato di Fatto
Strutturale - Copriferro armatura: Impostazioni copriferro armatura: Copriferro armatura 1; Utilizzo strutturale: Altro; Forma sezione: 0
Vincoli - Sposta con l'oggetto più vicino: no
Dati identità - Nome del tipo: Mensola allungata
Name | In | Famiglia = Famiglia e tipo = ID tipo = Tipo | Area (m2) | Volume (m3) | Prospetto (m) | Nome famiglia
Mensola allungata:Mensola allungata:206538 | 0 - Piano Terra | Mensola allungata: Mensola allungata | 2.334 | 0.9336 | 0 | Mensola allungata
Mensola allungata1:Mensola allungata:206630 | 0 - Piano Terra | Mensola allungata1: Mensola allungata | 2.4673 | 0.986921 |  | Mensola allungata1
Mensola allungata2:Mensola allungata:206738 | 0 - Piano Terra | Mensola allungata2: Mensola allungata | 2.2363 | 0.894521 |  | Mensola allungata2
Mensola allungata3:Mensola allungata:206750 | 0 - Piano Terra | Mensola allungata3: Mensola allungata | 2.2333 | 0.893321 |  | Mensola allungata3
Mensola allungata4:Mensola allungata:207997 | 1 - Piano Primo | Mensola allungata4: Mensola allungata | 2.334 | 0.9336 | 0 | Mensola allungata4
Mensola allungata5:Mensola allungata:208009 | 1 - Piano Primo | Mensola allungata5: Mensola allungata | 2.46748 | 0.986991 | 0 | Mensola allungata5
Mensola allungata6:Mensola allungata:208141 | 1 - Piano Primo | Mensola allungata6: Mensola allungata | 2.2363 | 0.894521 | 0 | Mensola allungata6
Mensola allungata7:Mensola allungata:284225 | 1 - Piano Primo | Mensola allungata7: Mensola allungata | 2.2363 | 0.894521 | 0 | Mensola allungata7

# IfcBuildingElementProxy: Telaio strutturale 1 (2)
Material: Calcestruzzo, gettato in opera
Pset_BuildingElementProxyCommon - Reference: Telaio strutturale 1
Altro - Categoria: Telaio strutturale
Dimensioni - Area: 2.06832 m2; Volume: 0.827325 m3
Fasi - Fase di creazione: Stato di Fatto
Strutturale - Copriferro armatura: Impostazioni copriferro armatura: Copriferro armatura 1; Utilizzo strutturale: Altro; Forma sezione: 0
Vincoli - Prospetto: 0 m; Sposta con l'oggetto più vicino: no
Dati identità - Nome del tipo: Telaio strutturale 1
Name | In | Famiglia = Famiglia e tipo = ID tipo = Tipo | Nome famiglia
Telaio strutturale 1:Telaio strutturale 1:207485 | 0 - Piano Terra | Telaio strutturale 1: Telaio strutturale 1 | Telaio strutturale 1
Telaio strutturale 2:Telaio strutturale 1:207556 | 2 - Piano Secondo | Telaio strutturale 2: Telaio strutturale 1 | Telaio strutturale 2

# IfcBuildingElementProxy: Telaio strutturale 11 (2)
Material: Calcestruzzo, gettato in opera
Pset_BuildingElementProxyCommon - Reference: Telaio strutturale 11
Altro - Categoria: Telaio strutturale
Dimensioni - Area: 2.12002 m2; Volume: 0.84801 m3
Fasi - Fase di creazione: Stato di Fatto
Strutturale - Copriferro armatura: Impostazioni copriferro armatura: Copriferro armatura 1; Utilizzo strutturale: Altro; Forma sezione: 0
Vincoli - Sposta con l'oggetto più vicino: no
Dati identità - Nome del tipo: Telaio strutturale 11
Name | In | Famiglia = Famiglia e tipo = ID tipo = Tipo | Nome famiglia
Telaio strutturale 11:Telaio strutturale 11:207825 | 0 - Piano Terra | Telaio strutturale 11: Telaio strutturale 11 | Telaio strutturale 11
Telaio strutturale 13:Telaio strutturale 11:207855 | 2 - Piano Secondo | Telaio strutturale 13: Telaio strutturale 11 | Telaio strutturale 13 | Vincoli - Prospetto: 0 m

# IfcBuildingElementProxy: Telaio strutturale 12 (2)
Material: Calcestruzzo, gettato in opera
Pset_BuildingElementProxyCommon - Reference: Telaio strutturale 12
Altro - Categoria: Telaio strutturale
Dimensioni - Area: 2.09778 m2; Volume: 0.839112 m3
Fasi - Fase di creazione: Stato di Fatto
Strutturale - Copriferro armatura: Impostazioni copriferro armatura: Copriferro armatura 1; Utilizzo strutturale: Altro; Forma sezione: 0
Vincoli - Prospetto: 0 m; Sposta con l'oggetto più vicino: no
Dati identità - Nome del tipo: Telaio strutturale 12
Name | In | Famiglia = Famiglia e tipo = ID tipo = Tipo | Nome famiglia
Telaio strutturale 12:Telaio strutturale 12:207840 | 0 - Piano Terra | Telaio strutturale 12: Telaio strutturale 12 | Telaio strutturale 12
Telaio strutturale 14:Telaio strutturale 12:207870 | 2 - Piano Secondo | Telaio strutturale 14: Telaio strutturale 12 | Telaio strutturale 14

# IfcBuildingElementProxy: Telaio strutturale 16 (3)
Material: Calcestruzzo, gettato in opera
Pset_BuildingElementProxyCommon - Reference: Telaio strutturale 16
Altro - Categoria: Telaio strutturale
Fasi - Fase di creazione: Stato di Fatto
Strutturale - Copriferro armatura: Impostazioni copriferro armatura: Copriferro armatura 1; Utilizzo strutturale: Altro; Forma sezione: 0
Vincoli - Prospetto: 0 m; Sposta con l'oggetto più vicino: no
Dati identità - Nome del tipo: Telaio strutturale 16
Name | In | Famiglia = Famiglia e tipo = ID tipo = Tipo | Area (m2) | Volume (m3) | Nome famiglia
Telaio strutturale 16:Telaio strutturale 16:207949 | 0 - Piano Terra | Telaio strutturale 16: Telaio strutturale 16 | 1.108 | 0.4432 | Telaio strutturale 16
Telaio strutturale 20:Telaio strutturale 16:207973 | 1 - Piano Primo | Telaio strutturale 20: Telaio strutturale 16 | 1.108 | 0.4432 | Telaio strutturale 20
Telaio strutturale 3:Telaio strutturale 16:208201 | 0 - Piano Terra | Telaio strutturale 3: Telaio strutturale 16 | 0.640146 | 0.256058 | Telaio strutturale 3

# IfcBuildingElementProxy: Telaio strutturale 17 (4)
Material: Calcestruzzo, gettato in opera
Pset_BuildingElementProxyCommon - Reference: Telaio strutturale 17
Altro - Categoria: Telaio strutturale
Fasi - Fase di creazione: Stato di Fatto
Strutturale - Copriferro armatura: Impostazioni copriferro armatura: Copriferro armatura 1; Utilizzo strutturale: Altro; Forma sezione: 0
Vincoli - Prospetto: 0 m; Sposta con l'oggetto più vicino: no
Dati identità - Nome del tipo: Telaio strutturale 17
Name | In | Famiglia = Famiglia e tipo = ID tipo = Tipo | Area (m2) | Volume (m3) | Nome famiglia
Telaio strutturale 17:Telaio strutturale 17:207961 | 0 - Piano Terra | Telaio strutturale 17: Telaio strutturale 17 | 1.108 | 0.4432 | Telaio strutturale 17
Telaio strutturale 21:Telaio strutturale 17:207985 | 1 - Piano Primo | Telaio strutturale 21: Telaio strutturale 17 | 1.108 | 0.4432 | Telaio strutturale 21
Telaio strutturale 6:Telaio strutturale 17:208218 | 0 - Piano Terra | Telaio strutturale 6: Telaio strutturale 17 | 2.008 | 0.803199 | Telaio strutturale 6
Telaio strutturale 7:Telaio strutturale 17:208241 | 1 - Piano Primo | Telaio strutturale 7: Telaio strutturale 17 | 2.00805 | 0.80322 | Telaio strutturale 7

# IfcBuildingElementProxy: Telaio strutturale 4 (4)
Material: Calcestruzzo, gettato in opera
Pset_BuildingElementProxyCommon - Reference: Telaio strutturale 4
Altro - Categoria: Telaio strutturale
Fasi - Fase di creazione: Stato di Fatto
Strutturale - Copriferro armatura: Impostazioni copriferro armatura: Copriferro armatura 1; Utilizzo strutturale: Altro; Forma sezione: 0
Vincoli - Prospetto: 0 m; Sposta con l'oggetto più vicino: no
Dati identità - Nome del tipo: Telaio strutturale 4
Name | In | Famiglia = Famiglia e tipo = ID tipo = Tipo | Area (m2) | Volume (m3) | Nome famiglia
Telaio strutturale 4:Telaio strutturale 4:207628 | 0 - Piano Terra | Telaio strutturale 4: Telaio strutturale 4 | 1.108 | 0.4432 | Telaio strutturale 4
Telaio strutturale 8:Telaio strutturale 4:207652 | 1 - Piano Primo | Telaio strutturale 8: Telaio strutturale 4 | 1.108 | 0.4432 | Telaio strutturale 8
Telaio strutturale 10:Telaio strutturale 4:208264 | 0 - Piano Terra | Telaio strutturale 10: Telaio strutturale 4 | 0.799586 | 0.319835 | Telaio strutturale 10
Telaio strutturale 15:Telaio strutturale 4:208275 | 0 - Piano Terra | Telaio strutturale 15: Telaio strutturale 4 | 2.07559 | 0.830235 | Telaio strutturale 15

# IfcBuildingElementProxy: Telaio strutturale 5 (3)
Material: Calcestruzzo, gettato in opera
Pset_BuildingElementProxyCommon - Reference: Telaio strutturale 5
Altro - Categoria: Telaio strutturale
Fasi - Fase di creazione: Stato di Fatto
Strutturale - Copriferro armatura: Impostazioni copriferro armatura: Copriferro armatura 1; Utilizzo strutturale: Altro; Forma sezione: 0
Vincoli - Prospetto: 0 m; Sposta con l'oggetto più vicino: no
Dati identità - Nome del tipo: Telaio strutturale 5
Name | In | Famiglia = Famiglia e tipo = ID tipo = Tipo | Area (m2) | Volume (m3) | Nome famiglia
Telaio strutturale 5:Telaio strutturale 5:207640 | 0 - Piano Terra | Telaio strutturale 5: Telaio strutturale 5 | 1.108 | 0.4432 | Telaio strutturale 5
Telaio strutturale 9:Telaio strutturale 5:207664 | 1 - Piano Primo | Telaio strutturale 9: Telaio strutturale 5 | 1.108 | 0.4432 | Telaio strutturale 9
Telaio strutturale 18:Telaio strutturale 5:208294 | 1 - Piano Primo | Telaio strutturale 18: Telaio strutturale 5 | 2.076 | 0.830401 | Telaio strutturale 18

# IfcBuildingElementProxy: Trave curva (2)
Material: Calcestruzzo, gettato in opera
Pset_BuildingElementProxyCommon - Reference: Trave curva
Altro - Categoria: Telaio strutturale
Dimensioni - Area: 2.18276 m2
Fasi - Fase di creazione: Stato di Fatto
Strutturale - Copriferro armatura: Impostazioni copriferro armatura: Copriferro armatura 1; Utilizzo strutturale: Altro; Forma sezione: 0
Vincoli - Prospetto: 0 m; Sposta con l'oggetto più vicino: no
Dati identità - Nome del tipo: Trave curva
Name | In | Famiglia = Famiglia e tipo = ID tipo = Tipo | Volume (m3) | Nome famiglia
Trave curva:Trave curva:207528 | 0 - Piano Terra | Trave curva: Trave curva | 0.873103 | Trave curva
Trave curva1:Trave curva:207543 | 2 - Piano Secondo | Trave curva1: Trave curva | 0.873104 | Trave curva1

# IfcBuildingElementProxy: Trave in opera 1, Trave in opera 2:Trave in opera 1:208129
In: 1 - Piano Primo
Material: Calcestruzzo, gettato in opera
Pset_BuildingElementProxyCommon - Reference: Trave in opera 1
Altro - Categoria: Telaio strutturale; Famiglia: Trave in opera 2: Trave in opera 1; Famiglia e tipo: Trave in opera 2: Trave in opera 1; ID tipo: Trave in opera 2: Trave in opera 1; Tipo: Trave in opera 2: Trave in opera 1; Nome famiglia: Trave in opera 2
Dimensioni - Area: 2.34312 m2; Volume: 0.937249 m3
Fasi - Fase di creazione: Stato di Fatto
Strutturale - Copriferro armatura: Impostazioni copriferro armatura: Copriferro armatura 1; Utilizzo strutturale: Altro; Forma sezione: 0
Vincoli - Prospetto: 0 m; Sposta con l'oggetto più vicino: no
Dati identità - Nome del tipo: Trave in opera 1

# IfcBuildingElementProxy: Trave setto (16)
Material: Calcestruzzo, gettato in opera
Pset_BuildingElementProxyCommon - Reference: Trave setto
Altro - Categoria: Telaio strutturale
Dimensioni - Area: 1.74 m2
Fasi - Fase di creazione: Stato di Fatto
Strutturale - Copriferro armatura: Impostazioni copriferro armatura: Copriferro armatura 1; Utilizzo strutturale: Altro; Forma sezione: 0
Vincoli - Sposta con l'oggetto più vicino: no
Dati identità - Nome del tipo: Trave setto
Name | In | Famiglia = Famiglia e tipo = ID tipo = Tipo | Volume (m3) | Prospetto (m) | Nome famiglia
Trave setto:Trave setto:206642 | 0 - Piano Terra | Trave setto: Trave setto | 0.696 | 0 | Trave setto
Trave setto1:Trave setto:206654 | 0 - Piano Terra | Trave setto1: Trave setto | 0.696 | 0 | Trave setto1
Trave setto2:Trave setto:206666 | 0 - Piano Terra | Trave setto2: Trave setto | 0.696 | 0 | Trave setto2
Trave setto3:Trave setto:206678 | 0 - Piano Terra | Trave setto3: Trave setto | 0.696 | 0 | Trave setto3
Trave setto4:Trave setto:206690 | 0 - Piano Terra | Trave setto4: Trave setto | 0.695443 | 0 | Trave setto4
Trave setto5:Trave setto:206702 | 0 - Piano Terra | Trave setto5: Trave setto | 0.696 | 0 | Trave setto5
Trave setto6:Trave setto:206714 | 0 - Piano Terra | Trave setto6: Trave setto | 0.696 | 0 | Trave setto6
Trave setto7:Trave setto:206726 | 0 - Piano Terra | Trave setto7: Trave setto | 0.696 |  | Trave setto7
Trave setto8:Trave setto:208021 | 1 - Piano Primo | Trave setto8: Trave setto | 0.696 | 0 | Trave setto8
Trave setto9:Trave setto:208033 | 1 - Piano Primo | Trave setto9: Trave setto | 0.696 | 0 | Trave setto9
Trave setto10:Trave setto:208045 | 1 - Piano Primo | Trave setto10: Trave setto | 0.696 | 0 | Trave setto10
Trave setto11:Trave setto:208057 | 1 - Piano Primo | Trave setto11: Trave setto | 0.696 | 0 | Trave setto11
Trave setto12:Trave setto:208069 | 1 - Piano Primo | Trave setto12: Trave setto | 0.695443 | 0 | Trave setto12
Trave setto13:Trave setto:208081 | 1 - Piano Primo | Trave setto13: Trave setto | 0.696 | 0 | Trave setto13
Trave setto14:Trave setto:208093 | 1 - Piano Primo | Trave setto14: Trave setto | 0.696 | 0 | Trave setto14
Trave setto15:Trave setto:208105 | 1 - Piano Primo | Trave setto15: Trave setto | 0.696 | 0 | Trave setto15

# IfcBuildingElementProxy: Travi in opera 1, Travi in opera 2:Travi in opera 1:208117
In: 1 - Piano Primo
Material: Calcestruzzo, gettato in opera
Pset_BuildingElementProxyCommon - Reference: Travi in opera 1
Altro - Categoria: Telaio strutturale; Famiglia: Travi in opera 2: Travi in opera 1; Famiglia e tipo: Travi in opera 2: Travi in opera 1; ID tipo: Travi in opera 2: Travi in opera 1; Tipo: Travi in opera 2: Travi in opera 1; Nome famiglia: Travi in opera 2
Dimensioni - Area: 2.34048 m2; Volume: 0.936193 m3
Fasi - Fase di creazione: Stato di Fatto
Strutturale - Copriferro armatura: Impostazioni copriferro armatura: Copriferro armatura 1; Utilizzo strutturale: Altro; Forma sezione: 0
Vincoli - Prospetto: 0 m; Sposta con l'oggetto più vicino: no
Dati identità - Nome del tipo: Travi in opera 1

# IfcColumn: 500x500-1 livello centrale (18)
In: 0 - Piano Terra
Type - ElementType: 500x500-1 livello centrale; PredefinedType: COLUMN; Classification: B10 Superstructure (Uniformat); Material: Calcestruzzo - Calcestruzzo prefabbricato - 35 MPa
Type - Altro - Categoria: Pilastri strutturali; Est modiglione 1: yes; Est modiglione 2: no; Est modiglione 3: no; Est modiglione 4: no; Nome famiglia: Prefabbricati-Pilastro rettangolare con modiglioni a più strati; Nord modiglione 1: yes; Nord modiglione 2: no; Nord modiglione 3: no; Nord modiglione 4: no; Numero modiglioni est 1: 1; Numero modiglioni nord 1: 1; Numero modiglioni ovest 1: 1; Numero modiglioni sud 1: 1; Ovest modiglione 1: yes; Ovest modiglione 2: no; Ovest modiglione 3: no; Ovest modiglione 4: no; Sud modiglione 1: yes; Sud modiglione 2: no; Sud modiglione 3: no; Sud modiglione 4: no
Type - Costruzione - Numero modiglioni est: 1; Numero modiglioni nord: 1; Numero modiglioni ovest: 1; Numero modiglioni sud: 1; Tipo modiglione est: Modiglione rettangolare; Tipo modiglione nord: Modiglione rettangolare; Tipo modiglione ovest: Modiglione rettangolare; Tipo modiglione sud: Modiglione rettangolare
Type - Dati identità - Codice assieme: B10; Descrizione assieme: Superstructure; Nome del tipo: 500x500-1 livello centrale
Type - Dimensioni - b: 0.5 m; Est altezza modiglione: 0.4 m; Est larghezza modiglione: 0.47 m; Est profondità modiglione: 0.3 m; h: 0.5 m; Nord altezza modiglione: 0.26 m; Nord larghezza modiglione: 0.47 m; Nord profondità modiglione: 0.2 m; Ovest altezza modiglione: 0.4 m; Ovest larghezza modiglione: 0.47 m; Ovest profondità modiglione: 0.3 m; Smusso: 0.015 m; Sud altezza modiglione: 0.26 m; Sud larghezza modiglione: 0.47 m; Sud profondità modiglione: 0.2 m
Type - Strutturale - Forma sezione: 0
Pset_ColumnCommon - LoadBearing: yes; IsExternal: no; Reference: 500x500-1 livello centrale
Altro - Famiglia: Prefabbricati-Pilastro rettangolare con modiglioni a più strati: 500x500-1 livello centrale; Famiglia e tipo: Prefabbricati-Pilastro rettangolare con modiglioni a più strati: 500x500-1 livello centrale; ID tipo: Prefabbricati-Pilastro rettangolare con modiglioni a più strati: 500x500-1 livello centrale; S armatura singola: 0.49 kN; S asta di collegamento: 0.294 kN; S griglie armatura: 0.98 kN; Tipo: Prefabbricati-Pilastro rettangolare con modiglioni a più strati: 500x500-1 livello centrale
Dimensioni - Area: 13.9242 m2; Est distanza modiglione 1: 3.92 m; Est distanza modiglione 2: 0 m; Est distanza modiglione 3: 0 m; Est distanza modiglione 4: 0 m; Est offset modiglione: 0 m; Lunghezza: 8.15 m; Nord distanza modiglione 1: 3.66 m; Nord distanza modiglione 2: 0 m; Nord distanza modiglione 3: 0 m; Nord distanza modiglione 4: 0 m; Nord offset modiglione: 0 m; Ovest distanza modiglione 1: 3.92 m; Ovest distanza modiglione 2: 0 m; Ovest distanza modiglione 3: 0 m; Ovest distanza modiglione 4: 0 m; Ovest offset modiglione: 0 m; Smusso modiglione: 0.015 m; Sud distanza modiglione 1: 3.66 m; Sud distanza modiglione 2: 0 m; Sud distanza modiglione 3: 0 m; Sud distanza modiglione 4: 0 m; Sud offset modiglione: 0 m; Volume: 2.67886 m3
Fasi - Fase di creazione: Stato di Fatto
Materiali e finiture - Materiale strutturale: Calcestruzzo - Calcestruzzo prefabbricato - 35 MPa
Strutturale - Attiva modello analitico: yes; Copriferro armatura - Altre superfici: Impostazioni copriferro armatura: Copriferro armatura 1; Copriferro armatura - Superficie inferiore: Impostazioni copriferro armatura: Copriferro armatura 1; Copriferro armatura - Superficie superiore: Impostazioni copriferro armatura: Copriferro armatura 1; Spessore armatura singola: 50; Spessore asta di collegamento: 30; Spessore griglie armatura: 100
Vincoli - Delimita il locale: yes; Livello: Livello: 0 - Piano Terra; Livello di base: Livello: 0 - Piano Terra; Livello superiore: Livello: 2 - Piano Secondo; Offset base: -0.2 m; Offset superiore: -0.66 m; Sposta con griglie: yes; Stile pilastro: Verticale
Name (Prefabbricati-Pilastro rettangolare con modiglioni a più strati:500x500-1 livello centrale:...) | Contrassegno di posizione pilastro
205949 | XX(-4.82)-YY
205959 | XX(-11.12)-YY(-7.99)
205961 | XX(-4.82)-YY(8.00)
205967 | XX(-11.12)-YY(8.00)
205969 | XX(-4.82)-YY(16.01)
205975 | XX(-11.12)-YY(16.01)
205977 | XX(-4.82)-YY(24.01)
205983 | XX(-11.12)-YY(24.01)
205985 | XX(-4.82)-YY(64.03)
205991 | XX(-11.12)-YY(64.03)
205993 | XX(-4.82)-YY(72.02)
205999 | XX(-11.12)-YY(72.02)
206001 | XX(-4.82)-YY(80.02)
206007 | XX(-11.12)-YY(80.02)
206009 | XX(-4.82)-YY(88.01)
206015 | XX(-11.12)-YY(88.01)
206019 | XX(-11.12)-YY(96.01)
214301 | XX(-11.12)-YY

# IfcColumn: 520x500-1 livello laterale (18)
In: 0 - Piano Terra
Type - ElementType: 520x500-1 livello laterale; PredefinedType: COLUMN; Classification: B10 Superstructure (Uniformat); Material: Calcestruzzo - Calcestruzzo prefabbricato - 35 MPa
Type - Altro - Categoria: Pilastri strutturali; Est modiglione 1: yes; Est modiglione 2: no; Est modiglione 3: no; Est modiglione 4: no; Nord modiglione 1: yes; Nord modiglione 2: no; Nord modiglione 3: no; Nord modiglione 4: no; Numero modiglioni est 1: 1; Numero modiglioni nord 1: 1; Numero modiglioni ovest 1: 1; Ovest modiglione 1: yes; Ovest modiglione 2: no; Ovest modiglione 3: no; Ovest modiglione 4: no; Sud modiglione 2: no; Sud modiglione 3: no; Sud modiglione 4: no; Nome famiglia: Prefabbricati-Pilastro rettangolare con modiglioni a più strati; Numero modiglioni sud 1: 0; Sud modiglione 1: no
Type - Costruzione - Numero modiglioni est: 1; Numero modiglioni nord: 1; Numero modiglioni ovest: 1; Tipo modiglione est: Modiglione rettangolare; Tipo modiglione nord: Modiglione rettangolare; Tipo modiglione ovest: Modiglione rettangolare; Tipo modiglione sud: Modiglione rettangolare; Numero modiglioni sud: 0
Type - Dati identità - Codice assieme: B10; Descrizione assieme: Superstructure; Nome del tipo: 520x500-1 livello laterale
Type - Dimensioni - b: 0.52 m; Est altezza modiglione: 0.4 m; Est larghezza modiglione: 0.47 m; Est profondità modiglione: 0.3 m; h: 0.5 m; Nord altezza modiglione: 0.26 m; Nord larghezza modiglione: 0.49 m; Nord profondità modiglione: 0.2 m; Ovest altezza modiglione: 0.4 m; Ovest larghezza modiglione: 0.47 m; Ovest profondità modiglione: 0.3 m; Smusso: 0.015 m; Sud altezza modiglione: 0.4 m; Sud larghezza modiglione: 0.15 m; Sud profondità modiglione: 0.2 m
Type - Strutturale - Forma sezione: 0
Pset_ColumnCommon - LoadBearing: yes; IsExternal: no; Reference: 520x500-1 livello laterale
Altro - Famiglia: Prefabbricati-Pilastro rettangolare con modiglioni a più strati: 520x500-1 livello laterale; Famiglia e tipo: Prefabbricati-Pilastro rettangolare con modiglioni a più strati: 520x500-1 livello laterale; ID tipo: Prefabbricati-Pilastro rettangolare con modiglioni a più strati: 520x500-1 livello laterale; S armatura singola: 0.49 kN; S asta di collegamento: 0.294 kN; S griglie armatura: 0.98 kN; Tipo: Prefabbricati-Pilastro rettangolare con modiglioni a più strati: 520x500-1 livello laterale
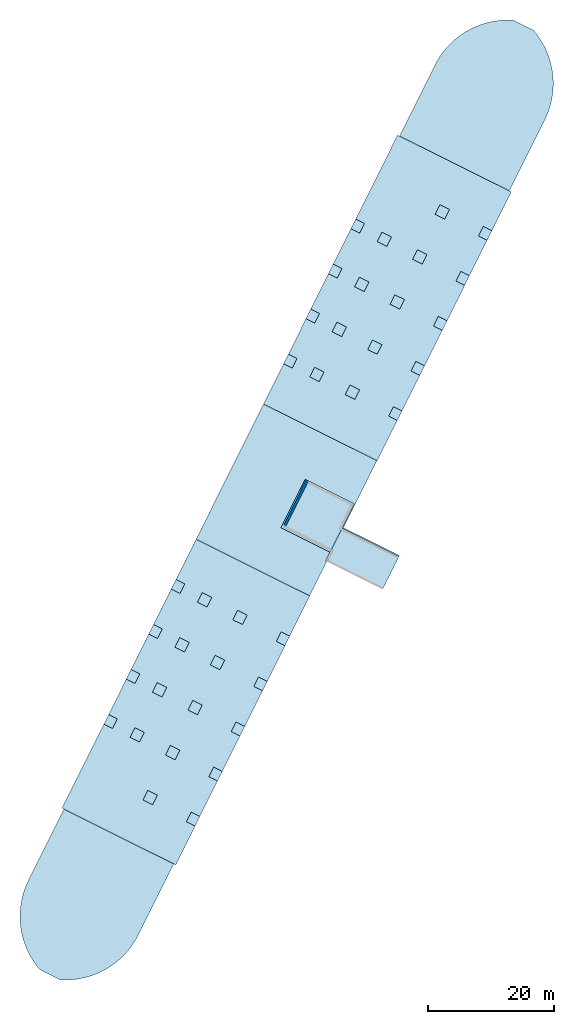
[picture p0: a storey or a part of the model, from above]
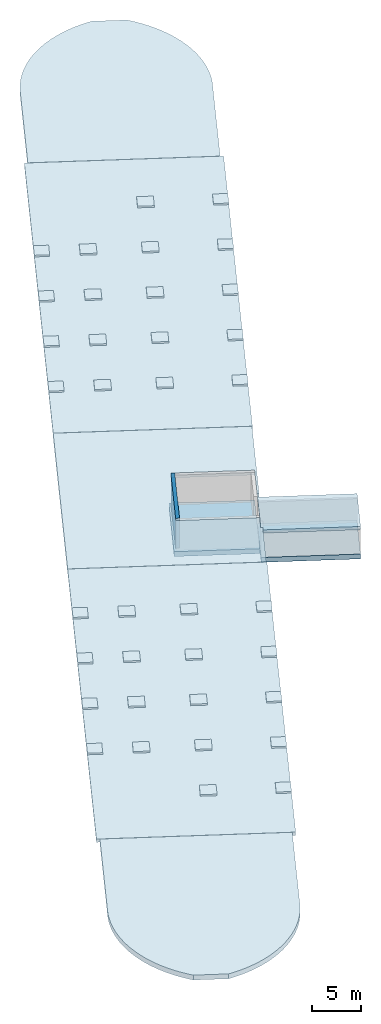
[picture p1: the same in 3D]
Properties of the parts of a building model (IFC2X3), part 2 of 7

# IfcColumn: 520x500-1 livello laterale (18)
Dimensioni - Est distanza modiglione 2: 0 m; Est distanza modiglione 3: 0 m; Est distanza modiglione 4: 0 m; Est offset modiglione: 0 m; Nord distanza modiglione 2: 0 m; Nord distanza modiglione 3: 0 m; Nord distanza modiglione 4: 0 m; Nord offset modiglione: 0 m; Ovest distanza modiglione 2: 0 m; Ovest distanza modiglione 3: 0 m; Ovest distanza modiglione 4: 0 m; Ovest offset modiglione: 0 m; Sud distanza modiglione 2: 0 m; Sud distanza modiglione 3: 0 m; Sud distanza modiglione 4: 0 m; Sud offset modiglione: 0 m; Est distanza modiglione 1: 3.92 m; Lunghezza: 8.15 m; Nord distanza modiglione 1: 3.66 m; Ovest distanza modiglione 1: 3.92 m; Smusso modiglione: 0.015 m; Sud distanza modiglione 1: 3.66 m
Fasi - Fase di creazione: Stato di Fatto
Materiali e finiture - Materiale strutturale: Calcestruzzo - Calcestruzzo prefabbricato - 35 MPa
Strutturale - Attiva modello analitico: yes; Copriferro armatura - Altre superfici: Impostazioni copriferro armatura: Copriferro armatura 1; Copriferro armatura - Superficie inferiore: Impostazioni copriferro armatura: Copriferro armatura 1; Copriferro armatura - Superficie superiore: Impostazioni copriferro armatura: Copriferro armatura 1; Spessore armatura singola: 50; Spessore asta di collegamento: 30; Spessore griglie armatura: 100
Vincoli - Delimita il locale: yes; Livello: Livello: 0 - Piano Terra; Sposta con griglie: yes; Stile pilastro: Verticale; Livello di base: Livello: 0 - Piano Terra; Livello superiore: Livello: 2 - Piano Secondo; Offset base: -0.2 m; Offset superiore: -0.66 m
Name (Prefabbricati-Pilastro rettangolare con modiglioni a più strati:520x500-1 livello laterale:...) | Area (m2) | Volume (m3) | Contrassegno di posizione pilastro
205951 | 13.7518 | 2.71503 | XX-YY
205953 | 13.7518 | 2.71503 | XX(-18.82)-YY
205957 | 13.7518 | 2.71503 | XX(-18.82)-YY(-7.99)
205963 | 13.7518 | 2.71503 | XX-YY(8.00)
205965 | 13.7518 | 2.71503 | XX(-18.82)-YY(8.00)
205971 | 13.7518 | 2.71503 | XX-YY(16.01)
205973 | 13.7518 | 2.71503 | XX(-18.82)-YY(16.01)
205979 | 13.7518 | 2.71503 | XX-YY(24.01)
205981 | 13.7518 | 2.71503 | XX(-18.82)-YY(24.01)
205987 | 13.7518 | 2.71503 | XX-YY(64.03)
205989 | 13.7518 | 2.71503 | XX(-18.82)-YY(64.03)
205995 | 9.59149 | 2.25329 | XX-YY(72.02)
205997 | 13.7518 | 2.71503 | XX(-18.82)-YY(72.02)
206003 | 13.7518 | 2.71503 | XX-YY(80.02)
206005 | 13.7518 | 2.71503 | XX(-18.82)-YY(80.02)
206011 | 13.7518 | 2.71503 | XX-YY(88.01)
206013 | 13.7518 | 2.71503 | XX(-18.82)-YY(88.01)
206017 | 13.7518 | 2.71503 | XX(-18.82)-YY(96.01)

# IfcCovering: Isolamento tubazione:Default (63)
PredefinedType: INSULATION
Pset_CoveringCommon - Reference: Default
Altro - Categoria: Isolamenti tubazioni; Famiglia: Isolamento tubazione: Default; Famiglia e tipo: Isolamento tubazione: Default; ID tipo: Isolamento tubazione: Default; Tipo: Isolamento tubazione: Default; Nome famiglia: Isolamento tubazione
Fasi - Fase di creazione: Stato di Fatto
Meccanica - Spessore isolamento: 0.05 m
Dati identità - Nome del tipo: Default
Name (Isolamento tubazione:...) | In | Contrassegno | Dimensione tubazione | Lunghezza (m) | Tipo di sistema | Area (m2) | Classificazione sistema | Nome sistema | Volume (m3)
Default | 0 - Piano Terra | 15 | 200 mmø | 0.334945 | Sistema di tubazioni: Mandata sistema idronico | 0.33575 | Mandata di sistema idronico | Mandata sistema idronico 30 | 0.0167875
Default | 0 - Piano Terra | 18 | 200 mmø | 2.17 | Sistema di tubazioni: Mandata sistema idronico | 2.17522 | Mandata di sistema idronico | Mandata sistema idronico 30 | 0.108761
Default | 0 - Piano Terra | 19 | 200 mmø | 10.5317 | Sistema di tubazioni: Mandata sistema idronico | 10.557 | Mandata di sistema idronico | Mandata sistema idronico 30 | 0.527849
Default | 0 - Piano Terra | 20 | 200 mmø | 0.3 | Sistema di tubazioni: Mandata sistema idronico | 0.300721 | Mandata di sistema idronico | Mandata sistema idronico 27 | 0.0150361
Default | 0 - Piano Terra | 24 | 200 mmø | 0.297 | Sistema di tubazioni: Mandata sistema idronico | 0.297714 | Mandata di sistema idronico | Mandata sistema idronico 30 | 0.0148857
Default | 0 - Piano Terra | 28 | 200 mmø-200 mmø |  | Sistema di tubazioni: Mandata sistema idronico |  | Mandata di sistema idronico | Mandata sistema idronico 30
Default | 0 - Piano Terra | 29 | 200 mmø-200 mmø |  | Sistema di tubazioni: Mandata sistema idronico |  | Mandata di sistema idronico | Mandata sistema idronico 30
Default | 0 - Piano Terra | 30 | 200 mmø-200 mmø |  | Sistema di tubazioni: Mandata sistema idronico |  | Mandata di sistema idronico | Mandata sistema idronico 30
Default | 0 - Piano Terra | 31 | 200 mmø-200 mmø |  |  |  | Non definito
Default | 0 - Piano Terra | 32 | 200 mmø-200 mmø |  |  |  | Non definito
Default | 0 - Piano Terra | 33 | 200 mmø | 2.17 |  | 2.17522 | Non definito |  | 0.108761
Default | 0 - Piano Terra | 34 | 200 mmø | 0.297 | Sistema di tubazioni: Mandata sistema idronico | 0.297714 | Mandata di sistema idronico | Mandata sistema idronico 26 | 0.0148857
Default | 0 - Piano Terra | 35 | 200 mmø-200 mmø |  | Sistema di tubazioni: Mandata sistema idronico |  | Mandata di sistema idronico | Mandata sistema idronico 26
Default | 0 - Piano Terra | 36 | 200 mmø | 0.334945 |  | 0.33575 | Non definito |  | 0.0167875
Default | 0 - Piano Terra | 37 | 200 mmø-200 mmø |  |  |  | Non definito
Default | 0 - Piano Terra | 38 | 200 mmø-200 mmø |  |  |  | Non definito
Default | 0 - Piano Terra | 39 | 200 mmø | 0.3 | Sistema di tubazioni: Mandata sistema idronico | 0.300721 | Mandata di sistema idronico | Mandata sistema idronico 28 | 0.0150361
Default | 0 - Piano Terra | 40 | 200 mmø-200 mmø |  |  |  | Non definito
Default | 0 - Piano Terra | 41 | 200 mmø-200 mmø |  |  |  | Non definito
Default | 0 - Piano Terra | 42 | 200 mmø | 10.5317 | Sistema di tubazioni: Mandata sistema idronico | 10.557 | Mandata di sistema idronico | Mandata sistema idronico 29 | 0.527849
Default | 0 - Piano Terra | 43 | 150 mmø | 3.5 | Sistema di tubazioni: Mandata sistema idronico | 2.94984 | Mandata di sistema idronico | Mandata sistema idronico 31 | 0.147492
Default | 0 - Piano Terra | 44 | 150 mmø | 22.3898 | Sistema di tubazioni: Mandata sistema idronico | 18.8703 | Mandata di sistema idronico | Mandata sistema idronico 32 | 0.943517
Default | 0 - Piano Terra | 46 | 150 mmø | 0.446147 | Sistema di tubazioni: Mandata sistema idronico | 0.376017 | Mandata di sistema idronico | Mandata sistema idronico 32 | 0.0188009
Default | 0 - Piano Terra | 47 | 150 mmø | 1.946 | Sistema di tubazioni: Mandata sistema idronico | 1.64011 | Mandata di sistema idronico | Mandata sistema idronico 32 | 0.0820055
Default | 0 - Piano Terra | 49 | 150 mmø | 0.296 | Sistema di tubazioni: Mandata sistema idronico | 0.249472 | Mandata di sistema idronico | Mandata sistema idronico 32 | 0.0124736
Default | 0 - Piano Terra | 50 | 150 mmø-150 mmø |  | Sistema di tubazioni: Mandata sistema idronico |  | Mandata di sistema idronico | Mandata sistema idronico 32
Default | 0 - Piano Terra | 51 | 150 mmø | 0.046 | Sistema di tubazioni: Mandata sistema idronico | 0.0387693 | Mandata di sistema idronico | Mandata sistema idronico 32 | 0.00193846
Default | 0 - Piano Terra | 52 | 150 mmø-150 mmø |  | Sistema di tubazioni: Mandata sistema idronico |  | Mandata di sistema idronico | Mandata sistema idronico 32
Default | 0 - Piano Terra | 53 | 150 mmø | 11.5324 | Sistema di tubazioni: Mandata sistema idronico | 9.71961 | Mandata di sistema idronico | Mandata sistema idronico 32 | 0.485981
Default | 0 - Piano Terra | 55 | 150 mmø | 0.046 | Sistema di tubazioni: Mandata sistema idronico | 0.0387693 | Mandata di sistema idronico | Mandata sistema idronico 32 | 0.00193846
Default | 0 - Piano Terra | 56 | 150 mmø-150 mmø |  | Sistema di tubazioni: Mandata sistema idronico |  | Mandata di sistema idronico | Mandata sistema idronico 32
Default | 0 - Piano Terra | 58 | 150 mmø | 0.296 | Sistema di tubazioni: Mandata sistema idronico | 0.249472 | Mandata di sistema idronico | Mandata sistema idronico 32 | 0.0124736
Default | 0 - Piano Terra | 59 | 150 mmø-150 mmø |  | Sistema di tubazioni: Mandata sistema idronico |  | Mandata di sistema idronico | Mandata sistema idronico 32
Default | 0 - Piano Terra | 60 | 150 mmø-150 mmø |  | Sistema di tubazioni: Mandata sistema idronico |  | Mandata di sistema idronico | Mandata sistema idronico 32
Default | 0 - Piano Terra | 61 | 150 mmø-150 mmø |  | Sistema di tubazioni: Mandata sistema idronico |  | Mandata di sistema idronico | Mandata sistema idronico 32
Default | 0 - Piano Terra | 62 | 150 mmø | 0.463862 | Sistema di tubazioni: Mandata sistema idronico | 0.390948 | Mandata di sistema idronico | Mandata sistema idronico 32 | 0.0195474
Default | 0 - Piano Terra | 63 | 150 mmø-150 mmø |  | Sistema di tubazioni: Mandata sistema idronico |  | Mandata di sistema idronico | Mandata sistema idronico 32
Default | 0 - Piano Terra | 64 | 150 mmø-150 mmø |  | Sistema di tubazioni: Mandata sistema idronico |  | Mandata di sistema idronico | Mandata sistema idronico 32
Default | 0 - Piano Terra | 69 | 32 mmø | 5.1438 | Sistema di tubazioni: Mandata sistema idronico | 2.29733 | Mandata di sistema idronico | Mandata sistema idronico 35 | 0.114866
Default | 0 - Piano Terra | 71 | 32 mmø | 0.401836 | Sistema di tubazioni: Mandata sistema idronico | 0.179469 | Mandata di sistema idronico | Mandata sistema idronico 35 | 0.00897344
Default | 0 - Piano Terra | 72 | 32 mmø | 0.17351 | Sistema di tubazioni: Mandata sistema idronico | 0.0774934 | Mandata di sistema idronico | Mandata sistema idronico 35 | 0.00387467
Default | 0 - Piano Terra | 74 | 32 mmø-32 mmø |  | Sistema di tubazioni: Mandata sistema idronico |  | Mandata di sistema idronico | Mandata sistema idronico 35
Default | 0 - Piano Terra | 76 | 50 mmø | 9.7 | Sistema di tubazioni: Mandata sistema idronico | 4.88566 | Mandata di sistema idronico | Mandata sistema idronico 36 | 0.244283
Default | 0 - Piano Terra | 77 | 50 mmø | 9.7 | Sistema di tubazioni: Mandata sistema idronico | 4.88566 | Mandata di sistema idronico | Mandata sistema idronico 37 | 0.244283
Default | 0 - Piano Terra | 81 | 32 mmø | 1.658 | Sistema di tubazioni: Mandata sistema idronico | 0.740498 | Mandata di sistema idronico | Mandata sistema idronico 35 | 0.0370249
Default | 0 - Piano Terra | 82 | 32 mmø-32 mmø |  | Sistema di tubazioni: Mandata sistema idronico |  | Mandata di sistema idronico | Mandata sistema idronico 35
Default | 0 - Piano Terra | 83 | 32 mmø-32 mmø |  | Sistema di tubazioni: Mandata sistema idronico |  | Mandata di sistema idronico | Mandata sistema idronico 35
Default | 0 - Piano Terra | 84 | 50 mmø | 6.136 | Sistema di tubazioni: Mandata sistema idronico | 3.09056 | Mandata di sistema idronico | Mandata sistema idronico 34 | 0.154528
Default | 0 - Piano Terra | 85 | 50 mmø | 3.436 | Sistema di tubazioni: Mandata sistema idronico | 1.73063 | Mandata di sistema idronico | Mandata sistema idronico 34 | 0.0865315
Default | 0 - Piano Terra | 86 | 50 mmø-50 mmø-50 mmø |  | Sistema di tubazioni: Mandata sistema idronico |  | Mandata di sistema idronico | Mandata sistema idronico 34
Default | 1 - Piano Primo | 88 | 32 mmø | 134.307 | Sistema di tubazioni: Mandata sistema idronico | 59.9845 | Mandata di sistema idronico | Mandata sistema idronico 41 | 2.99922
Default | 1 - Piano Primo | 89 | 32 mmø | 1.796 | Sistema di tubazioni: Mandata sistema idronico | 0.802132 | Mandata di sistema idronico | Mandata sistema idronico 41 | 0.0401066
Default | 2 - Piano Secondo | 90 | 32 mmø | 0.053 | Sistema di tubazioni: Mandata sistema idronico | 0.0236709 | Mandata di sistema idronico | Mandata sistema idronico 41 | 0.00118355
Default | 2 - Piano Secondo | 91 | 32 mmø-32 mmø |  | Sistema di tubazioni: Mandata sistema idronico |  | Mandata di sistema idronico | Mandata sistema idronico 41
Default | 1 - Piano Primo | 93 | 32 mmø | 2.32172 | Sistema di tubazioni: Mandata sistema idronico | 1.03693 | Mandata di sistema idronico | Mandata sistema idronico 41 | 0.0518465
Default | 1 - Piano Primo | 96 | 32 mmø-32 mmø |  | Sistema di tubazioni: Mandata sistema idronico |  | Mandata di sistema idronico | Mandata sistema idronico 41
Default | 1 - Piano Primo | 97 | 32 mmø | 0.839171 | Sistema di tubazioni: Mandata sistema idronico | 0.374792 | Mandata di sistema idronico | Mandata sistema idronico 41 | 0.0187396
Default | 1 - Piano Primo | 98 | 32 mmø-32 mmø |  | Sistema di tubazioni: Mandata sistema idronico |  | Mandata di sistema idronico | Mandata sistema idronico 41
Default | 1 - Piano Primo | 99 | 32 mmø-32 mmø |  | Sistema di tubazioni: Mandata sistema idronico |  | Mandata di sistema idronico | Mandata sistema idronico 41
Default | 1 - Piano Primo | 101 | 32 mmø | 2.096 | Sistema di tubazioni: Mandata sistema idronico | 0.936118 | Mandata di sistema idronico | Mandata sistema idronico 41 | 0.0468059
Default | 1 - Piano Primo | 102 | 32 mmø-32 mmø |  | Sistema di tubazioni: Mandata sistema idronico |  | Mandata di sistema idronico | Mandata sistema idronico 41
Default | 2 - Piano Secondo | 106 | 32 mmø | 0.075 | Sistema di tubazioni: Mandata sistema idronico | 0.0334966 | Mandata di sistema idronico | Mandata sistema idronico 41 | 0.00167483
Default | 2 - Piano Secondo | 107 | 32 mmø-32 mmø |  | Sistema di tubazioni: Mandata sistema idronico |  | Mandata di sistema idronico | Mandata sistema idronico 41

# IfcDistributionPort (298)
FlowDirection: SOURCEANDSINK
Name | Group
4 x  | Meccanica Aria di mandata 1
2 x  | Meccanica Aria di mandata 10
2 x  | Meccanica Aria di mandata 11
2 x  | Meccanica Aria di mandata 12
6 x  | Mandata sistema idronico 11
10 x  | Mandata sistema idronico 22
12 x  | Mandata sistema idronico 30
2 x  | Mandata sistema idronico 26
32 x  | Mandata sistema idronico 32
18 x 
12 x  | Mandata sistema idronico 35
4 x  | Mandata sistema idronico 34
8 x  | Mandata sistema idronico 38
16 x  | Mandata sistema idronico 39
20 x  | Mandata sistema idronico 40
24 x  | Mandata sistema idronico 41
44 x  | Mandata sistema idronico 50
14 x  | Mandata sistema idronico 54
22 x  | Mandata sistema idronico 51
12 x  | Mandata sistema idronico 46
8 x  | Mandata sistema idronico 55
4 x  | Mandata sistema idronico 56
4 x  | Mandata sistema idronico 57
8 x  | Mandata sistema idronico 58
8 x  | Mandata sistema idronico 59

# IfcDoor: 180x210 (3)
In: 0 - Piano Terra
Type - OperationType: DOUBLE_DOOR_SINGLE_SWING; ParameterTakesPrecedence: no; Sizeable: no; Material: Alluminio
Type - 120-180x210 Uscita di sicurezza doppia:180x210:209666 - PanelOperation: SWINGING
Type - Altro - Categoria: Porte; Nome famiglia: 120-180x210 Uscita di sicurezza doppia
Type - Costruzione - Funzione: Interno; Chiusura muro: Per host
Type - Dati identità - Contrassegno tipo: 13; Nome del tipo: 180x210
Type - Dimensioni - Altezza: 2.1 m; Elev. Poignée: 0.9 m; Larg. Feuillure: 0.04 m; Larghezza: 1.6 m; Prof. Feuillure: 0.05 m; Spessore: 0.04 m
Type - Materiali e finiture - Dormants: Alluminio; Panneau: Alluminio
Type - Proprietà analitiche - Costruzione analitica: <Nessuno>
Type - Vincoli - Sys: 0 m; Tiers Hauteur (Auto): 0.7 m
OverallHeight: 2.15 m; OverallWidth: 1.7 m
Pset_DoorCommon - IsExternal: yes; Reference: 180x210
Altro - Id host: Muro di base: Setto CA rivestito int-est 47 cm; Altezza estremità: 2.1 m; Famiglia: 120-180x210 Uscita di sicurezza doppia: 180x210; Famiglia e tipo: 120-180x210 Uscita di sicurezza doppia: 180x210; ID tipo: 120-180x210 Uscita di sicurezza doppia: 180x210; Tipo: 120-180x210 Uscita di sicurezza doppia: 180x210
Dimensioni - Area: 4.244 m2; Volume: 0.1521 m3
Fasi - Fase di creazione: Stato di Fatto
Vincoli - Livello: Livello: 0 - Piano Terra; Altezza soglia: 0 m; Déc. Vitre (Auto): 0.01 m
Name (120-180x210 Uscita di sicurezza doppia:180x210:...) | Contrassegno
209666 | 9
209673 | 12
209676 | 15

# IfcDoor: 180x210 (3)
In: 0 - Piano Terra
Type - OperationType: DOUBLE_DOOR_SINGLE_SWING; ParameterTakesPrecedence: no; Sizeable: no; Material: Alluminio
Type - Altro - Categoria: Porte; Nome famiglia: 120-180x210 Uscita di sicurezza doppia
Type - Costruzione - Funzione: Interno; Chiusura muro: Per host
Type - Dati identità - Contrassegno tipo: 13; Nome del tipo: 180x210
Type - Dimensioni - Altezza: 2.1 m; Elev. Poignée: 0.9 m; Larg. Feuillure: 0.04 m; Larghezza: 1.6 m; Prof. Feuillure: 0.05 m; Spessore: 0.04 m
Type - Materiali e finiture - Dormants: Alluminio; Panneau: Alluminio
Type - Proprietà analitiche - Costruzione analitica: <Nessuno>
Type - Vincoli - Sys: 0 m; Tiers Hauteur (Auto): 0.7 m
Type - 120-180x210 Uscita di sicurezza doppia:180x210:209679 - PanelOperation: SWINGING
OverallHeight: 2.15 m; OverallWidth: 1.7 m
Pset_DoorCommon - IsExternal: yes; Reference: 180x210
Altro - Id host: Muro di base: Setto CA rivestito int - 31 cm; Famiglia: 120-180x210 Uscita di sicurezza doppia: 180x210; Famiglia e tipo: 120-180x210 Uscita di sicurezza doppia: 180x210; ID tipo: 120-180x210 Uscita di sicurezza doppia: 180x210; Tipo: 120-180x210 Uscita di sicurezza doppia: 180x210; Altezza estremità: 2.1 m
Dimensioni - Area: 4.244 m2; Volume: 0.1521 m3
Fasi - Fase di creazione: Stato di Fatto
Vincoli - Livello: Livello: 0 - Piano Terra; Altezza soglia: 0 m; Déc. Vitre (Auto): 0.01 m
Name (120-180x210 Uscita di sicurezza doppia:180x210:...) | Contrassegno
209679 | 22
209682 | 25
209685 | 28

# IfcDoor: BarreAP (12)
In: 0 - Piano Terra
Type - ParameterTakesPrecedence: no; Sizeable: no; Material: Peinture - Gris fonçé, Peinture - Gris
Type - Altro - Categoria: Porte; Nome famiglia: BarreAP
Type - Dati identità - Contrassegno tipo: 1; Nome del tipo: BarreAP
Type - Dimensioni - Altezza: 0.9 m
Type - Materiali e finiture - Finition: Peinture - Gris fonçé
Type - Proprietà analitiche - Costruzione analitica: <Nessuno>
OverallHeight: 2.1 m; OverallWidth: 0.76 m
Pset_DoorCommon - IsExternal: no; Reference: BarreAP
Altro - Famiglia: BarreAP: BarreAP; Famiglia e tipo: BarreAP: BarreAP; ID tipo: BarreAP: BarreAP; Tipo: BarreAP: BarreAP
Dimensioni - Area: 0.127777 m2; HautBarre: 0.9 m; HautFerm: 2.1 m; LargPan: 0.735 m; Volume: 0.00141704 m3
Fasi - Fase di creazione: Stato di Fatto
Materiali e finiture - Barre Appui: Peinture - Gris clair; Support Barre: Peinture - Gris
Vincoli - Livello: Livello: 0 - Piano Terra; Sposta con l'oggetto più vicino: no; Offset: 0 m
Name (BarreAP:BarreAP:...) | Contrassegno | Host
209669 | 10 | Muro di base : Setto CA rivestito int-est 47 cm
209670 | 11 | Muro di base : Setto CA rivestito int-est 47 cm
209674 | 13 | Pavimento : Scala PT 40 cm
209675 | 14 | Pavimento : Scala PT 40 cm
209677 | 16 | Pavimento : Scala PT 40 cm
209678 | 17 | Pavimento : Scala PT 40 cm
209680 | 23 | Muro di base : Setto CA rivestito int - 31 cm
209681 | 24 | Muro di base : Setto CA rivestito int - 31 cm
209683 | 26 | Pavimento : Scala PT 40 cm
209684 | 27 | Pavimento : Scala PT 40 cm
209686 | 29 | Pavimento : Scala PT 40 cm
209687 | 30 | Pavimento : Scala PT 40 cm

# IfcFlowFitting: Raggio 300 mm, M_Raccordo a T orizzontale canale:Raggio 300 mm:276248
In: 0 - Piano Terra
Type - Altro - Categoria: Raccordi passerella; Nome famiglia: M_Raccordo a T orizzontale canale
Type - Dati identità - Nome del tipo: Raggio 300 mm; Numero OmniClass: 23.80.30.17.17; Titolo OmniClass: Cable Trays and Horizontal Racks
Type - Dimensioni - Raggio: 0.3 m
Pset_DistributionFlowElementCommon - Reference: Raggio 300 mm
Altro - Famiglia: M_Raccordo a T orizzontale canale: Raggio 300 mm; Famiglia e tipo: M_Raccordo a T orizzontale canale: Raggio 300 mm; ID tipo: M_Raccordo a T orizzontale canale: Raggio 300 mm; Testo etichetta raggio: 0.3 m; Testo etichetta raggio 1: 0.30254 m; Tipo: M_Raccordo a T orizzontale canale: Raggio 300 mm
Dati identità - Contrassegno: 15
Dimensioni - Altezza passerella: 0.075 m; Dimensioni: 300 mmx75 mmø-300 mmx75 mmø-100 mmx75 mmø; Larghezza passerella 1: 0.3 m; Larghezza passerella 3: 0.1 m; Lunghezza passerella: 0.075 m; Spessore: 0.00254 m; Volume: 0.0248348 m3
Fasi - Fase di creazione: Stato di Fatto
Grafica - Utilizza scala di annotazione: no
Vincoli - Livello: Livello: 0 - Piano Terra; Host: Livello : 0 - Piano Terra; Offset: 3.8 m

# IfcFlowFitting: Standard (8)
Type - Altro - Categoria: Raccordi condotto; Nome famiglia: M_Gomito ad angolo circolare - DTL
Type - Dati identità - Nome del tipo: Standard; Numero OmniClass: 23.75.70.14; Titolo OmniClass: Air Ductwork
Type - Dimensioni - Dritto - Esterno: 0.05 m
Pset_DistributionFlowElementCommon - Reference: Standard
Altro - Angolo 1: 90 deg; Famiglia: M_Gomito ad angolo circolare - DTL: Standard; Famiglia e tipo: M_Gomito ad angolo circolare - DTL: Standard; ID tipo: M_Gomito ad angolo circolare - DTL: Standard; Lunghezza 1: 0.125298 m; Numero di pieghe 2: 2; Raggio_1: 0.125298 m; Tipo: M_Gomito ad angolo circolare - DTL: Standard
Dimensioni - Angolo: 90 deg; Diametro interno: 0.25 m; Dimensioni: 250 mmø-250 mmø; Dritto - Interno: 0.05 m; Numero di pieghe: 2; Raggio interno: 0.125 m; Volume: 0.0172092 m3
Fasi - Fase di creazione: Stato di Fatto
Grafica - Utilizza scala di annotazione: no
Isolamento - Dimensione totale: 250 mmø-250 mmø; Spessore isolamento: 0 m
Meccanica - Classificazione sistema: Aria di mandata; Tipo di sistema: Sistema di condotti: Aria di mandata
Rivestimento - Dimensione libera: 250 mmø-250 mmø; Spessore rivestimento: 0 m
Name (M_Gomito ad angolo circolare - DTL:Standard:...) | In | Contrassegno | Nome sistema | Livello | Host | Offset (m) | Group
205909 | 2 - Piano Secondo | 1 | Meccanica Aria di mandata 1 | Livello: 2 - Piano Secondo | Livello : 2 - Piano Secondo | 0.725 | Meccanica Aria di mandata 1
205911 | 0 - Piano Terra | 3 | Meccanica Aria di mandata 1 | Livello: 0 - Piano Terra | Livello : 0 - Piano Terra | 3.05 | Meccanica Aria di mandata 1
205917 | 2 - Piano Secondo | 4 | Meccanica Aria di mandata 4 | Livello: 2 - Piano Secondo | Livello : 2 - Piano Secondo | 0.725
205919 | 2 - Piano Secondo | 5 | Meccanica Aria di mandata 5 | Livello: 2 - Piano Secondo | Livello : 2 - Piano Secondo | 0.725
205921 | 2 - Piano Secondo | 6 | Meccanica Aria di mandata 6 | Livello: 2 - Piano Secondo | Livello : 2 - Piano Secondo | 0.725
205937 | 0 - Piano Terra | 7 | Meccanica Aria di mandata 10 | Livello: 0 - Piano Terra | Livello : 0 - Piano Terra | 3.05 | Meccanica Aria di mandata 10
205939 | 0 - Piano Terra | 8 | Meccanica Aria di mandata 11 | Livello: 0 - Piano Terra | Livello : 0 - Piano Terra | 2.9 | Meccanica Aria di mandata 11
205941 | 0 - Piano Terra | 9 | Meccanica Aria di mandata 12 | Livello: 0 - Piano Terra | Livello : 0 - Piano Terra | 2.9 | Meccanica Aria di mandata 12

# IfcFlowFitting: Standard (26)
Type - Altro - Categoria: Raccordi passerella; Nome famiglia: M_Curvatura esterna verticale canale
Type - Dati identità - Nome del tipo: Standard; Numero OmniClass: 23.80.30.17.17; Titolo OmniClass: Cable Trays and Horizontal Racks
Pset_DistributionFlowElementCommon - Reference: Standard
Altro - Curvatura o raccordo: Raccordo; Famiglia: M_Curvatura esterna verticale canale: Standard; Famiglia e tipo: M_Curvatura esterna verticale canale: Standard; ID tipo: M_Curvatura esterna verticale canale: Standard; Tipo: M_Curvatura esterna verticale canale: Standard
Dimensioni - Altezza passerella: 0.075 m; Spessore: 0.00254 m
Fasi - Fase di creazione: Stato di Fatto
Grafica - Utilizza scala di annotazione: no
Name (M_Curvatura esterna verticale canale:Standard:...) | In | Da centro a estremità (m) | Testo etichetta raggio di curvatura (m) | Contrassegno | Angolo (deg) | Dimensioni | Larghezza passerella (m) | Lunghezza passerella (m) | Raggio di curvatura (m) | Volume (m3) | Livello | Host | Offset (m)
274067 | 0 - Piano Terra | 0.0858988 | 0.040675 | 8 | 30 | 100 mmx75 mmø-100 mmx75 mmø | 0.1 | 0.075 | 0.001 | 0.00128472 | Livello: 0 - Piano Terra | Livello : 0 - Piano Terra | 3.8
276945 | 0 - Piano Terra | 0.0858988 | 0.040675 | 17 | 30 | 300 mmx75 mmø-300 mmx75 mmø | 0.3 | 0.075 | 0.001 | 0.00385417 | Livello: 0 - Piano Terra | Livello : 0 - Piano Terra | 3.8
277689 | 0 - Piano Terra | 0.0858988 | 0.040675 | 19 | 30 | 300 mmx75 mmø-300 mmx75 mmø | 0.3 | 0.075 | 0.001 | 0.00385417 | Livello: 0 - Piano Terra | Livello : 0 - Piano Terra | 3.8
277738 | 0 - Piano Terra | 0.0858988 | 0.040675 | 21 | 30 | 300 mmx75 mmø-300 mmx75 mmø | 0.3 | 0.075 | 0.001 | 0.00385417 | Livello: 0 - Piano Terra | Livello : 0 - Piano Terra | 3.8
277742 | 0 - Piano Terra | 0.0858988 | 0.040675 | 23 | 30 | 300 mmx75 mmø-300 mmx75 mmø | 0.3 | 0.075 | 0.001 | 0.00385417 | Livello: 0 - Piano Terra | Livello : 0 - Piano Terra | 3.8
278030 | 0 - Piano Terra | 0.0858988 | 0.040675 | 25 | 30 | 450 mmx75 mmø-450 mmx75 mmø | 0.45 | 0.075 | 0.001 | 0.00578125 | Livello: 0 - Piano Terra | Livello : 0 - Piano Terra | 3.7
278035 | 0 - Piano Terra | 0.0858988 | 0.040675 | 27 | 30 | 450 mmx75 mmø-450 mmx75 mmø | 0.45 | 0.075 | 0.001 | 0.00578125 | Livello: 0 - Piano Terra | Livello : 0 - Piano Terra | 3.7
278038 | 0 - Piano Terra | 0.0858988 | 0.040675 | 29 | 30 | 450 mmx75 mmø-450 mmx75 mmø | 0.45 | 0.075 | 0.001 | 0.00578125 | Livello: 0 - Piano Terra | Livello : 0 - Piano Terra | 3.7
278042 | 0 - Piano Terra | 0.0858988 | 0.040675 | 31 | 30 | 450 mmx75 mmø-450 mmx75 mmø | 0.45 | 0.075 | 0.001 | 0.00578125 | Livello: 0 - Piano Terra | Livello : 0 - Piano Terra | 3.7
291916 | 1 - Piano Primo | 0.0858988 | 0.040675 | 34 | 30 | 300 mmx75 mmø-300 mmx75 mmø | 0.3 | 0.075 | 0.001 | 0.00385417 | Livello: 1 - Piano Primo | Livello : 1 - Piano Primo | 3.03
291921 | 1 - Piano Primo | 0.0858988 | 0.040675 | 36 | 30 | 300 mmx75 mmø-300 mmx75 mmø | 0.3 | 0.075 | 0.001 | 0.00385417 | Livello: 1 - Piano Primo | Livello : 1 - Piano Primo | 3.03
291924 | 1 - Piano Primo | 0.0858988 | 0.040675 | 38 | 30 | 300 mmx75 mmø-300 mmx75 mmø | 0.3 | 0.075 | 0.001 | 0.00385417 | Livello: 1 - Piano Primo | Livello : 1 - Piano Primo | 3.03
291928 | 1 - Piano Primo | 0.0858988 | 0.040675 | 40 | 30 | 300 mmx75 mmø-300 mmx75 mmø | 0.3 | 0.075 | 0.001 | 0.00385417 | Livello: 1 - Piano Primo | Livello : 1 - Piano Primo | 3.03
292150 | 1 - Piano Primo | 0.0858988 | 0.040675 | 44 | 30 | 450 mmx75 mmø-450 mmx75 mmø | 0.45 | 0.075 | 0.001 | 0.00578125 | Livello: 1 - Piano Primo | Livello : 1 - Piano Primo | 2.93
292155 | 1 - Piano Primo | 0.0858988 | 0.040675 | 46 | 30 | 450 mmx75 mmø-450 mmx75 mmø | 0.45 | 0.075 | 0.001 | 0.00578125 | Livello: 1 - Piano Primo | Livello : 1 - Piano Primo | 2.93
292158 | 1 - Piano Primo | 0.0858988 | 0.040675 | 48 | 30 | 450 mmx75 mmø-450 mmx75 mmø | 0.45 | 0.075 | 0.001 | 0.00578125 | Livello: 1 - Piano Primo | Livello : 1 - Piano Primo | 2.93
292162 | 1 - Piano Primo | 0.0858988 | 0.040675 | 50 | 30 | 450 mmx75 mmø-450 mmx75 mmø | 0.45 | 0.075 | 0.001 | 0.00578125 | Livello: 1 - Piano Primo | Livello : 1 - Piano Primo | 2.93
293985 | 2 - Piano Secondo | 0.1325 | 0.0575 | 55 | 90 | 150 mmx75 mmø-150 mmx75 mmø | 0.15 | 0.075 | 0.02 | 0.0027037 | Livello: 2 - Piano Secondo | Livello : 2 - Piano Secondo | 1.06
294376 | 2 - Piano Secondo | 0.1325 | 0.0575 | 56 | 90 | 150 mmx75 mmø-150 mmx75 mmø | 0.15 | 0.075 | 0.02 | 0.0027037 | Livello: 2 - Piano Secondo | Livello : 2 - Piano Secondo | -5.4375
295668 | 2 - Piano Secondo | 0.0825 | 0.0575 | 64 | 90 | 150 mmx75 mmø-150 mmx75 mmø | 0.15 | 0.025 | 0.02 | 0.0015787 | Livello: 2 - Piano Secondo | Livello : 2 - Piano Secondo | 2.35
295799 | 2 - Piano Secondo | 0.0488173 | 0.0575 | 65 | 45 | 150 mmx75 mmø-150 mmx75 mmø | 0.15 | 0.025 | 0.02 | 0.00107054 | Livello: 2 - Piano Secondo | Livello : 2 - Piano Secondo | 2.21868
300345 | 2 - Piano Secondo | 0.0825 | 0.0575 | 78 | 90 | 150 mmx75 mmø-150 mmx75 mmø | 0.15 | 0.025 | 0.02 | 0.0015787 | Livello: 2 - Piano Secondo | Livello : 2 - Piano Secondo | 2.35
300346 | 2 - Piano Secondo | 0.0488173 | 0.0575 | 79 | 45 | 150 mmx75 mmø-150 mmx75 mmø | 0.15 | 0.025 | 0.02 | 0.00107054 | Livello: 2 - Piano Secondo | Livello : 2 - Piano Secondo | 2.21868
300818 | 2 - Piano Secondo | 0.0488173 | 0.0575 | 82 | 45 | 150 mmx75 mmø-150 mmx75 mmø | 0.15 | 0.025 | 0.02 | 0.00107054 | Livello: 2 - Piano Secondo | Livello : 2 - Piano Secondo | 0.327249
301127 | 2 - Piano Secondo | 0.0825 | 0.0575 | 85 | 90 | 150 mmx75 mmø-150 mmx75 mmø | 0.15 | 0.025 | 0.02 | 0.0015787 | Livello: 2 - Piano Secondo | Livello : 2 - Piano Secondo | 0.985
301128 | 2 - Piano Secondo | 0.0488173 | 0.0575 | 86 | 45 | 150 mmx75 mmø-150 mmx75 mmø | 0.15 | 0.025 | 0.02 | 0.00107054 | Livello: 2 - Piano Secondo | Livello : 2 - Piano Secondo | 0.853683

# IfcFlowFitting: Standard (24)
Type - Altro - Categoria: Raccordi passerella; Nome famiglia: M_Curvatura interna verticale canale
Type - Dati identità - Nome del tipo: Standard; Numero OmniClass: 23.80.30.17.17; Titolo OmniClass: Cable Trays and Horizontal Racks
Pset_DistributionFlowElementCommon - Reference: Standard
Altro - Curvatura o raccordo: Raccordo; Famiglia: M_Curvatura interna verticale canale: Standard; Famiglia e tipo: M_Curvatura interna verticale canale: Standard; ID tipo: M_Curvatura interna verticale canale: Standard; Tipo: M_Curvatura interna verticale canale: Standard
Dimensioni - Altezza passerella: 0.075 m; Spessore: 0.00254 m
Fasi - Fase di creazione: Stato di Fatto
Grafica - Utilizza scala di annotazione: no
Name (M_Curvatura interna verticale canale:Standard:...) | In | Da centro a estremità (m) | Testo etichetta raggio di curvatura (m) | Contrassegno | Angolo (deg) | Dimensioni | Larghezza passerella (m) | Lunghezza passerella (m) | Raggio di curvatura (m) | Volume (m3) | Livello | Host | Offset (m)
273163 | 0 - Piano Terra | 0.0608988 | 0.040675 | 4 | 30 | 100 mmx75 mmø-100 mmx75 mmø | 0.1 | 0.05 | 0.001 | 0.000909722 | Livello: 0 - Piano Terra | Livello : 0 - Piano Terra | 3.7
276944 | 0 - Piano Terra | 0.0608988 | 0.040675 | 16 | 30 | 300 mmx75 mmø-300 mmx75 mmø | 0.3 | 0.05 | 0.001 | 0.00272917 | Livello: 0 - Piano Terra | Livello : 0 - Piano Terra | 3.70025
277688 | 0 - Piano Terra | 0.0608988 | 0.040675 | 18 | 30 | 300 mmx75 mmø-300 mmx75 mmø | 0.3 | 0.05 | 0.001 | 0.00272917 | Livello: 0 - Piano Terra | Livello : 0 - Piano Terra | 3.70025
277737 | 0 - Piano Terra | 0.0608988 | 0.040675 | 20 | 30 | 300 mmx75 mmø-300 mmx75 mmø | 0.3 | 0.05 | 0.001 | 0.00272917 | Livello: 0 - Piano Terra | Livello : 0 - Piano Terra | 3.70025
277741 | 0 - Piano Terra | 0.0608988 | 0.040675 | 22 | 30 | 300 mmx75 mmø-300 mmx75 mmø | 0.3 | 0.05 | 0.001 | 0.00272917 | Livello: 0 - Piano Terra | Livello : 0 - Piano Terra | 3.70025
278029 | 0 - Piano Terra | 0.0608988 | 0.040675 | 24 | 30 | 450 mmx75 mmø-450 mmx75 mmø | 0.45 | 0.05 | 0.001 | 0.00409375 | Livello: 0 - Piano Terra | Livello : 0 - Piano Terra | 3.60025
278034 | 0 - Piano Terra | 0.0608988 | 0.040675 | 26 | 30 | 450 mmx75 mmø-450 mmx75 mmø | 0.45 | 0.05 | 0.001 | 0.00409375 | Livello: 0 - Piano Terra | Livello : 0 - Piano Terra | 3.60025
278037 | 0 - Piano Terra | 0.0608988 | 0.040675 | 28 | 30 | 450 mmx75 mmø-450 mmx75 mmø | 0.45 | 0.05 | 0.001 | 0.00409375 | Livello: 0 - Piano Terra | Livello : 0 - Piano Terra | 3.60025
278041 | 0 - Piano Terra | 0.0608988 | 0.040675 | 30 | 30 | 450 mmx75 mmø-450 mmx75 mmø | 0.45 | 0.05 | 0.001 | 0.00409375 | Livello: 0 - Piano Terra | Livello : 0 - Piano Terra | 3.60025
291915 | 1 - Piano Primo | 0.0608988 | 0.040675 | 33 | 30 | 300 mmx75 mmø-300 mmx75 mmø | 0.3 | 0.05 | 0.001 | 0.00272917 | Livello: 1 - Piano Primo | Livello : 1 - Piano Primo | 2.93025
291920 | 1 - Piano Primo | 0.0608988 | 0.040675 | 35 | 30 | 300 mmx75 mmø-300 mmx75 mmø | 0.3 | 0.05 | 0.001 | 0.00272917 | Livello: 1 - Piano Primo | Livello : 1 - Piano Primo | 2.93025
291923 | 1 - Piano Primo | 0.0608988 | 0.040675 | 37 | 30 | 300 mmx75 mmø-300 mmx75 mmø | 0.3 | 0.05 | 0.001 | 0.00272917 | Livello: 1 - Piano Primo | Livello : 1 - Piano Primo | 2.93025
291927 | 1 - Piano Primo | 0.0608988 | 0.040675 | 39 | 30 | 300 mmx75 mmø-300 mmx75 mmø | 0.3 | 0.05 | 0.001 | 0.00272917 | Livello: 1 - Piano Primo | Livello : 1 - Piano Primo | 2.93025
292149 | 1 - Piano Primo | 0.0608988 | 0.040675 | 43 | 30 | 450 mmx75 mmø-450 mmx75 mmø | 0.45 | 0.05 | 0.001 | 0.00409375 | Livello: 1 - Piano Primo | Livello : 1 - Piano Primo | 2.83025
292154 | 1 - Piano Primo | 0.0608988 | 0.040675 | 45 | 30 | 450 mmx75 mmø-450 mmx75 mmø | 0.45 | 0.05 | 0.001 | 0.00409375 | Livello: 1 - Piano Primo | Livello : 1 - Piano Primo | 2.83025
292157 | 1 - Piano Primo | 0.0608988 | 0.040675 | 47 | 30 | 450 mmx75 mmø-450 mmx75 mmø | 0.45 | 0.05 | 0.001 | 0.00409375 | Livello: 1 - Piano Primo | Livello : 1 - Piano Primo | 2.83025
292161 | 1 - Piano Primo | 0.0608988 | 0.040675 | 49 | 30 | 450 mmx75 mmø-450 mmx75 mmø | 0.45 | 0.05 | 0.001 | 0.00409375 | Livello: 1 - Piano Primo | Livello : 1 - Piano Primo | 2.83025
295998 | 2 - Piano Secondo | 0.0488173 | 0.0575 | 66 | 45 | 150 mmx75 mmø-150 mmx75 mmø | 0.15 | 0.025 | 0.02 | 0.00107054 | Livello: 2 - Piano Secondo | Livello : 2 - Piano Secondo | 1.96868
299014 | 2 - Piano Secondo | 0.0825 | 0.0575 | 72 | 90 | 150 mmx75 mmø-150 mmx75 mmø | 0.15 | 0.025 | 0.02 | 0.0015787 | Livello: 2 - Piano Secondo | Livello : 2 - Piano Secondo | 1.06
300347 | 2 - Piano Secondo | 0.0488173 | 0.0575 | 80 | 45 | 150 mmx75 mmø-150 mmx75 mmø | 0.15 | 0.025 | 0.02 | 0.00107054 | Livello: 2 - Piano Secondo | Livello : 2 - Piano Secondo | 1.96868
300350 | 2 - Piano Secondo | 0.0825 | 0.0575 | 81 | 90 | 150 mmx75 mmø-150 mmx75 mmø | 0.15 | 0.025 | 0.02 | 0.0015787 | Livello: 2 - Piano Secondo | Livello : 2 - Piano Secondo | 0.985
300819 | 2 - Piano Secondo | 0.0488173 | 0.0575 | 83 | 45 | 150 mmx75 mmø-150 mmx75 mmø | 0.15 | 0.025 | 0.02 | 0.00107054 | Livello: 2 - Piano Secondo | Livello : 2 - Piano Secondo | 0.1875
301286 | 2 - Piano Secondo | 0.0488173 | 0.0575 | 87 | 45 | 150 mmx75 mmø-150 mmx75 mmø | 0.15 | 0.025 | 0.02 | 0.00107054 | Livello: 2 - Piano Secondo | Livello : 2 - Piano Secondo | 0.603683
301289 | 2 - Piano Secondo | 0.0825 | 0.0575 | 88 | 90 | 150 mmx75 mmø-150 mmx75 mmø | 0.15 | 0.025 | 0.02 | 0.0015787 | Livello: 2 - Piano Secondo | Livello : 2 - Piano Secondo | 0.1875

# IfcFlowFitting: Standard (6)
In: 2 - Piano Secondo
Type - Altro - Categoria: Raccordi passerella; Nome famiglia: M_Curvatura orizzontale canale
Type - Dati identità - Nome del tipo: Standard; Numero OmniClass: 23.80.30.17.17; Titolo OmniClass: Cable Trays and Horizontal Racks
Pset_DistributionFlowElementCommon - Reference: Standard
Altro - Curvatura o raccordo: Raccordo; Da centro a estremità: 0.17 m; Famiglia: M_Curvatura orizzontale canale: Standard; Famiglia e tipo: M_Curvatura orizzontale canale: Standard; ID tipo: M_Curvatura orizzontale canale: Standard; Testo etichetta raggio di curvatura: 0.095 m; Tipo: M_Curvatura orizzontale canale: Standard
Dimensioni - Angolo: 90 deg; Altezza passerella: 0.075 m; Dimensioni: 150 mmx75 mmø-150 mmx75 mmø; Larghezza passerella: 0.15 m; Lunghezza passerella: 0.075 m; Raggio di curvatura: 0.02 m; Spessore: 0.00254 m; Volume: 0.0033663 m3
Fasi - Fase di creazione: Stato di Fatto
Grafica - Utilizza scala di annotazione: no
Vincoli - Livello: Livello: 2 - Piano Secondo; Host: Livello : 2 - Piano Secondo
Name (M_Curvatura orizzontale canale:Standard:...) | Contrassegno | Offset (m)
294803 | 57 | 2.35
294805 | 58 | 1.06
295382 | 62 | 2.35
295383 | 63 | 2.35
300294 | 76 | 2.35
301126 | 84 | 0.985

# IfcFlowFitting: Standard (8)
Type - Altro - Categoria: Raccordi tubazione; Nome famiglia: M_Gomito - Generico; Nome tabella di ricerca: M_Pipe Fitting - Generic
Type - Dati identità - Nome del tipo: Standard; Numero OmniClass: 23.60.30.11.14; Titolo OmniClass: Pipework Fittings
Type - Meccanica - Metodo di perdita: Coefficiente K da tabella; Tabella di coefficienti K: Gomito FF 45, 90 e 180 gradi
Pset_DistributionFlowElementCommon - Reference: Standard
Altro - Famiglia: M_Gomito - Generico: Standard; Famiglia e tipo: M_Gomito - Generico: Standard; ID tipo: M_Gomito - Generico: Standard; Raggio centro: 0.0587375 m; Raggio esterno raccordo: 0.0523875 m; Tipo: M_Gomito - Generico: Standard
Dimensioni - Angolo: 90 deg; Da centro a estremità: 0.0587375 m; Diametro esterno raccordo: 0.104775 m; Diametro nominale: 0.1 m; Dimensione contrassegno: 0.04191 m; Dimensione massima: 0.1 m; Dimensione minima: 0.1 m; Dimensioni: 100 mmø-100 mmø; Raggio nominale: 0.05 m; Volume: 0.000795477 m3
Fasi - Fase di creazione: Stato di Fatto
Grafica - Utilizza scala di annotazione: no
Isolamento - Spessore isolamento: 0 m; Dimensione totale: 100 mmø-100 mmø
Meccanica - Tipo di sistema: Sistema di tubazioni: Mandata sistema idronico; Classificazione sistema: Mandata di sistema idronico
Name (M_Gomito - Generico:Standard:...) | In | Contrassegno | Nome sistema = Group | Livello | Host | Offset (m)
307224 | 3 - Piano Copertura | 106 | Mandata sistema idronico 55 | Livello: 3 - Piano Copertura | Livello : 3 - Piano Copertura | -0.09285
307226 | 2 - Piano Secondo | 105 | Mandata sistema idronico 55 | Livello: 2 - Piano Secondo | Livello : 2 - Piano Secondo | 0.10715
307554 | 2 - Piano Secondo | 107 | Mandata sistema idronico 56 | Livello: 2 - Piano Secondo | Livello : 2 - Piano Secondo | 0.10715
307690 | 2 - Piano Secondo | 108 | Mandata sistema idronico 57 | Livello: 2 - Piano Secondo | Livello : 2 - Piano Secondo | 0.10715
307884 | 3 - Piano Copertura | 109 | Mandata sistema idronico 58 | Livello: 3 - Piano Copertura | Livello : 3 - Piano Copertura | -0.09285
307886 | 2 - Piano Secondo | 110 | Mandata sistema idronico 58 | Livello: 2 - Piano Secondo | Livello : 2 - Piano Secondo | 0.10715
307929 | 3 - Piano Copertura | 111 | Mandata sistema idronico 59 | Livello: 3 - Piano Copertura | Livello : 3 - Piano Copertura | -0.09285
307931 | 2 - Piano Secondo | 112 | Mandata sistema idronico 59 | Livello: 2 - Piano Secondo | Livello : 2 - Piano Secondo | 0.10715

# IfcFlowFitting: Standard (5)
Type - Altro - Categoria: Raccordi tubazione; Nome famiglia: M_Gomito - PVC - Sch 40; Nome tabella di ricerca: M_Elbow - PVC - Sch 40
Type - Dati identità - Nome del tipo: Standard; Numero OmniClass: 23.60.30.11.14; Titolo OmniClass: Pipework Fittings
Type - Meccanica - Metodo di perdita: Coefficiente K da tabella; Tabella di coefficienti K: Gomito FF 45, 90 e 180 gradi
Pset_DistributionFlowElementCommon - Reference: Standard
Altro - Famiglia: M_Gomito - PVC - Sch 40: Standard; Famiglia e tipo: M_Gomito - PVC - Sch 40: Standard; ID tipo: M_Gomito - PVC - Sch 40: Standard; Tipo: M_Gomito - PVC - Sch 40: Standard
Dimensioni - Diametro nominale: 0.125 m; Dimensione massima: 0.125 m; Dimensione minima: 0.125 m; Dimensioni: 125 mmø-125 mmø; Raggio nominale: 0.0625 m
Fasi - Fase di creazione: Stato di Fatto
Grafica - Utilizza scala di annotazione: no
Isolamento - Spessore isolamento: 0 m; Dimensione totale: 125 mmø-125 mmø
Meccanica - Tipo di sistema: Sistema di tubazioni: Mandata sistema idronico; Classificazione sistema: Mandata di sistema idronico
Name (M_Gomito - PVC - Sch 40:Standard:...) | In | Angolo 1 (deg) | Da centro a estremità - Non trovato (m) = Da centro a estremità (m) | Diametro esterno manicotto - Non trovato (m) = Diametro esterno manicotto (m) | Lunghezza 1 (m) | Lunghezza manicotto - Non trovato (m) = Lunghezza manicotto (m) | Raggio centro (m) | Raggio esterno manicotto (m) | Testo etichetta da centro a estremità (m) | Contrassegno | Angolo (deg) | Dimensione contrassegno (m) | Volume (m3) | Nome sistema = Group | Livello | Host | Offset (m)
238543 | 0 - Piano Terra | 90 | 0.14276 | 0.152442 | 0.14493 | 0.0692477 | 0.0770148 | 0.0762211 | 0.14493 | 5 | 89 | 0.0609769 | 0.00471107 | Mandata sistema idronico 11 | Livello: 0 - Piano Terra | Livello : 0 - Piano Terra | 8.1225
238984 | 0 - Piano Terra | 90 | 0.14276 | 0.152442 | 0.146262 | 0.0692477 | 0.0770148 | 0.0762211 | 0.146262 | 6 | 90 | 0.0609769 | 0.00473561 | Mandata sistema idronico 11 | Livello: 0 - Piano Terra | Livello : 0 - Piano Terra | 9.81
244275 | 1 - Piano Primo | 45 | 0.110478 | 0.152938 | 0.0936271 | 0.07395 | 0.143429 | 0.0764691 | 0.110478 | 16 | 28.5764 | 0.0611753 | 0.00403097 | Mandata sistema idronico 22 | Livello: 1 - Piano Primo | Livello : 1 - Piano Primo | 3.30054
245193 | 1 - Piano Primo | 90 | 0.14276 | 0.152442 | 0.144885 | 0.0692477 | 0.0770148 | 0.0762211 | 0.144885 | 14 | 88.9662 | 0.0609769 | 0.00471024 | Mandata sistema idronico 22 | Livello: 1 - Piano Primo | Livello : 1 - Piano Primo | 3.43372
245195 | 1 - Piano Primo | 90 | 0.14276 | 0.152442 | 0.146259 | 0.0692477 | 0.0770148 | 0.0762211 | 0.146259 | 17 | 89.9971 | 0.0609769 | 0.00473554 | Mandata sistema idronico 22 | Livello: 1 - Piano Primo | Livello : 1 - Piano Primo | 4.9275

# IfcFlowFitting: Standard (63)
Type - Altro - Categoria: Raccordi tubazione; Nome famiglia: M_Gomito - Saldato - Generico; Nome tabella di ricerca: M_Elbow - Welded - Generic
Type - Dati identità - Nome del tipo: Standard; Numero OmniClass: 23.60.30.11.14; Titolo OmniClass: Pipework Fittings
Type - Meccanica - Metodo di perdita: Coefficiente K da tabella; Tabella di coefficienti K: Gomito FF 45, 90 e 180 gradi
Pset_DistributionFlowElementCommon - Reference: Standard
Altro - Famiglia: M_Gomito - Saldato - Generico: Standard; Famiglia e tipo: M_Gomito - Saldato - Generico: Standard; ID tipo: M_Gomito - Saldato - Generico: Standard; Tipo: M_Gomito - Saldato - Generico: Standard
Fasi - Fase di creazione: Stato di Fatto
Grafica - Utilizza scala di annotazione: no
Name (M_Gomito - Saldato - Generico:Standard:...) | In | Raggio centro (m) | Raggio esterno raccordo (m) | Testo etichetta da centro a estremità (m) = Da centro a estremità (m) | Contrassegno | Angolo (deg) | Diametro esterno raccordo (m) | Diametro nominale (m) = Dimensione massima (m) = Dimensione minima (m) | Dimensione contrassegno (m) | Dimensioni | Raggio nominale (m) | Volume (m3) | Dimensione totale | Spessore isolamento (m) | Tipo di sistema | Classificazione sistema | Nome sistema = Group | Livello | Host | Offset (m)
249259 | 0 - Piano Terra | 0.203 | 0.10955 | 0.203 | 30 | 90 | 0.2191 | 0.2 | 0.08764 | 200 mmø-200 mmø | 0.1 | 0.012022 | 300 mmø-300 mmø | 0.05 | Sistema di tubazioni: Mandata sistema idronico | Mandata di sistema idronico | Mandata sistema idronico 30 | Livello: 0 - Piano Terra | Livello : 0 - Piano Terra | 3.076 | Isolamento - Tipo di isolamento: Default
249262 | 0 - Piano Terra | 0.203 | 0.10955 | 0.203 | 31 | 90 | 0.2191 | 0.2 | 0.08764 | 200 mmø-200 mmø | 0.1 | 0.012022 | 300 mmø-300 mmø | 0.05 | Sistema di tubazioni: Mandata sistema idronico | Mandata di sistema idronico | Mandata sistema idronico 30 | Livello: 0 - Piano Terra | Livello : 0 - Piano Terra | 0.5 | Isolamento - Tipo di isolamento: Default
249265 | 0 - Piano Terra | 0.203 | 0.10955 | 0.203 | 32 | 90 | 0.2191 | 0.2 | 0.08764 | 200 mmø-200 mmø | 0.1 | 0.012022 | 300 mmø-300 mmø | 0.05 | Sistema di tubazioni: Mandata sistema idronico | Mandata di sistema idronico | Mandata sistema idronico 30 | Livello: 0 - Piano Terra | Livello : 0 - Piano Terra | 0.5 | Isolamento - Tipo di isolamento: Default
249286 | 0 - Piano Terra | 0.203 | 0.10955 | 0.203 | 33 | 90 | 0.2191 | 0.2 | 0.08764 | 200 mmø-200 mmø | 0.1 | 0.012022 | 300 mmø-300 mmø | 0.05 |  | Non definito |  | Livello: 0 - Piano Terra | Livello : 0 - Piano Terra | 3.076 | Isolamento - Tipo di isolamento: Default
249320 | 0 - Piano Terra | 0.203 | 0.10955 | 0.203 | 34 | 90 | 0.2191 | 0.2 | 0.08764 | 200 mmø-200 mmø | 0.1 | 0.012022 | 300 mmø-300 mmø | 0.05 |  | Non definito |  | Livello: 0 - Piano Terra | Livello : 0 - Piano Terra | 2.67 | Isolamento - Tipo di isolamento: Default
249613 | 0 - Piano Terra | 0.203 | 0.10955 | 0.203 | 35 | 90 | 0.2191 | 0.2 | 0.08764 | 200 mmø-200 mmø | 0.1 | 0.012022 | 300 mmø-300 mmø | 0.05 | Sistema di tubazioni: Mandata sistema idronico | Mandata di sistema idronico | Mandata sistema idronico 26 | Livello: 0 - Piano Terra | Livello : 0 - Piano Terra | 0.5 | Isolamento - Tipo di isolamento: Default
249690 | 0 - Piano Terra | 0.203 | 0.10955 | 0.203 | 36 | 90 | 0.2191 | 0.2 | 0.08764 | 200 mmø-200 mmø | 0.1 | 0.012022 | 300 mmø-300 mmø | 0.05 |  | Non definito |  | Livello: 0 - Piano Terra | Livello : 0 - Piano Terra | 0.5 | Isolamento - Tipo di isolamento: Default
249724 | 0 - Piano Terra | 0.203 | 0.10955 | 0.203 | 37 | 90 | 0.2191 | 0.2 | 0.08764 | 200 mmø-200 mmø | 0.1 | 0.012022 | 300 mmø-300 mmø | 0.05 |  | Non definito |  | Livello: 0 - Piano Terra | Livello : 0 - Piano Terra | 3.076 | Isolamento - Tipo di isolamento: Default
249787 | 0 - Piano Terra | 0.203 | 0.10955 | 0.203 | 38 | 90 | 0.2191 | 0.2 | 0.08764 | 200 mmø-200 mmø | 0.1 | 0.012022 | 300 mmø-300 mmø | 0.05 |  | Non definito |  | Livello: 0 - Piano Terra | Livello : 0 - Piano Terra | 3.076 | Isolamento - Tipo di isolamento: Default
249866 | 0 - Piano Terra | 0.203 | 0.10955 | 0.203 | 39 | 90 | 0.2191 | 0.2 | 0.08764 | 200 mmø-200 mmø | 0.1 | 0.012022 | 300 mmø-300 mmø | 0.05 |  | Non definito |  | Livello: 0 - Piano Terra | Livello : 0 - Piano Terra | 2.67 | Isolamento - Tipo di isolamento: Default
250950 | 0 - Piano Terra | 0.152 | 0.08415 | 0.152 | 40 | 90 | 0.1683 | 0.15 | 0.06732 | 150 mmø-150 mmø | 0.075 | 0.00531139 | 250 mmø-250 mmø | 0.05 | Sistema di tubazioni: Mandata sistema idronico | Mandata di sistema idronico | Mandata sistema idronico 32 | Livello: 0 - Piano Terra | Livello : 0 - Piano Terra | 3.55 | Isolamento - Tipo di isolamento: Default
250953 | 0 - Piano Terra | 0.152 | 0.08415 | 0.152 | 41 | 90 | 0.1683 | 0.15 | 0.06732 | 150 mmø-150 mmø | 0.075 | 0.00531139 | 250 mmø-250 mmø | 0.05 | Sistema di tubazioni: Mandata sistema idronico | Mandata di sistema idronico | Mandata sistema idronico 32 | Livello: 0 - Piano Terra | Livello : 0 - Piano Terra | 3.9 | Isolamento - Tipo di isolamento: Default
251519 | 0 - Piano Terra | 0.152 | 0.08415 | 0.152 | 42 | 90 | 0.1683 | 0.15 | 0.06732 | 150 mmø-150 mmø | 0.075 | 0.00531139 | 250 mmø-250 mmø | 0.05 | Sistema di tubazioni: Mandata sistema idronico | Mandata di sistema idronico | Mandata sistema idronico 32 | Livello: 0 - Piano Terra | Livello : 0 - Piano Terra | 3.55 | Isolamento - Tipo di isolamento: Default
251594 | 0 - Piano Terra | 0.152 | 0.08415 | 0.152 | 45 | 90 | 0.1683 | 0.15 | 0.06732 | 150 mmø-150 mmø | 0.075 | 0.00531139 | 250 mmø-250 mmø | 0.05 | Sistema di tubazioni: Mandata sistema idronico | Mandata di sistema idronico | Mandata sistema idronico 32 | Livello: 0 - Piano Terra | Livello : 0 - Piano Terra | 3.9 | Isolamento - Tipo di isolamento: Default
251626 | 0 - Piano Terra | 0.152 | 0.08415 | 0.152 | 46 | 90 | 0.1683 | 0.15 | 0.06732 | 150 mmø-150 mmø | 0.075 | 0.00531139 | 250 mmø-250 mmø | 0.05 | Sistema di tubazioni: Mandata sistema idronico | Mandata di sistema idronico | Mandata sistema idronico 32 | Livello: 0 - Piano Terra | Livello : 0 - Piano Terra | 3.3 | Isolamento - Tipo di isolamento: Default
251629 | 0 - Piano Terra | 0.152 | 0.08415 | 0.152 | 44 | 90 | 0.1683 | 0.15 | 0.06732 | 150 mmø-150 mmø | 0.075 | 0.00531139 | 250 mmø-250 mmø | 0.05 | Sistema di tubazioni: Mandata sistema idronico | Mandata di sistema idronico | Mandata sistema idronico 32 | Livello: 0 - Piano Terra | Livello : 0 - Piano Terra | 3.9 | Isolamento - Tipo di isolamento: Default
251736 | 0 - Piano Terra | 0.152 | 0.08415 | 0.152 | 47 | 90 | 0.1683 | 0.15 | 0.06732 | 150 mmø-150 mmø | 0.075 | 0.00531139 | 250 mmø-250 mmø | 0.05 | Sistema di tubazioni: Mandata sistema idronico | Mandata di sistema idronico | Mandata sistema idronico 32 | Livello: 0 - Piano Terra | Livello : 0 - Piano Terra | 3.3 | Isolamento - Tipo di isolamento: Default
251739 | 0 - Piano Terra | 0.152 | 0.08415 | 0.152 | 43 | 90 | 0.1683 | 0.15 | 0.06732 | 150 mmø-150 mmø | 0.075 | 0.00531139 | 250 mmø-250 mmø | 0.05 | Sistema di tubazioni: Mandata sistema idronico | Mandata di sistema idronico | Mandata sistema idronico 32 | Livello: 0 - Piano Terra | Livello : 0 - Piano Terra | 3.9 | Isolamento - Tipo di isolamento: Default
281056 | 0 - Piano Terra | 0.032 | 0.0211 | 0.032 | 53 | 90 | 0.0422 | 0.032 | 0.01688 | 32 mmø-32 mmø | 0.016 | 0.0000703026 | 132 mmø-132 mmø | 0.05 | Sistema di tubazioni: Mandata sistema idronico | Mandata di sistema idronico | Mandata sistema idronico 35 | Livello: 0 - Piano Terra | Livello : 0 - Piano Terra | 3.2625 | Isolamento - Tipo di isolamento: Default
282835 | 0 - Piano Terra | 0.032 | 0.0211 | 0.032 | 62 | 90 | 0.0422 | 0.032 | 0.01688 | 32 mmø-32 mmø | 0.016 | 0.0000703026 | 132 mmø-132 mmø | 0.05 | Sistema di tubazioni: Mandata sistema idronico | Mandata di sistema idronico | Mandata sistema idronico 35 | Livello: 0 - Piano Terra | Livello : 0 - Piano Terra | 3.5 | Isolamento - Tipo di isolamento: Default
282838 | 0 - Piano Terra | 0.0319999 | 0.0211 | 0.032 | 52 | 90.0001 | 0.0422 | 0.032 | 0.01688 | 32 mmø-32 mmø | 0.016 | 0.0000703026 | 132 mmø-132 mmø | 0.05 | Sistema di tubazioni: Mandata sistema idronico | Mandata di sistema idronico | Mandata sistema idronico 35 | Livello: 0 - Piano Terra | Livello : 0 - Piano Terra | 3.50001 | Isolamento - Tipo di isolamento: Default
285141 | 0 - Piano Terra | 0.076 | 0.04445 | 0.076 | 56 | 90 | 0.0889 | 0.08 | 0.03556 | 80 mmø-80 mmø | 0.04 | 0.000740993 | 80 mmø-80 mmø | 0 | Sistema di tubazioni: Mandata sistema idronico | Mandata di sistema idronico | Mandata sistema idronico 38 | Livello: 0 - Piano Terra | Livello : 0 - Piano Terra | 3.5
285143 | 0 - Piano Terra | 0.076 | 0.04445 | 0.076 | 55 | 90 | 0.0889 | 0.08 | 0.03556 | 80 mmø-80 mmø | 0.04 | 0.000740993 | 80 mmø-80 mmø | 0 | Sistema di tubazioni: Mandata sistema idronico | Mandata di sistema idronico | Mandata sistema idronico 38 | Livello: 0 - Piano Terra | Livello : 0 - Piano Terra | 3.5
286788 | 1 - Piano Primo | 0.032 | 0.0211 | 0.032 | 57 | 90 | 0.0422 | 0.032 | 0.01688 | 32 mmø-32 mmø | 0.016 | 0.0000703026 | 132 mmø-132 mmø | 0.05 | Sistema di tubazioni: Mandata sistema idronico | Mandata di sistema idronico | Mandata sistema idronico 41 | Livello: 1 - Piano Primo | Livello : 1 - Piano Primo | 4.82 | Isolamento - Tipo di isolamento: Default
286979 | 1 - Piano Primo | 0.032 | 0.0211 | 0.032 | 58 | 90 | 0.0422 | 0.032 | 0.01688 | 32 mmø-32 mmø | 0.016 | 0.0000703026 | 132 mmø-132 mmø | 0.05 | Sistema di tubazioni: Mandata sistema idronico | Mandata di sistema idronico | Mandata sistema idronico 41 | Livello: 1 - Piano Primo | Livello : 1 - Piano Primo | 2.96 | Isolamento - Tipo di isolamento: Default
287053 | 1 - Piano Primo | 0.0348258 | 0.0211 | 0.032 | 59 | 85.1572 | 0.0422 | 0.032 | 0.01688 | 32 mmø-32 mmø | 0.016 | 0.0000723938 | 132 mmø-132 mmø | 0.05 | Sistema di tubazioni: Mandata sistema idronico | Mandata di sistema idronico | Mandata sistema idronico 41 | Livello: 1 - Piano Primo | Livello : 1 - Piano Primo | 2.96 | Isolamento - Tipo di isolamento: Default
287056 | 1 - Piano Primo | 0.0348258 | 0.0211 | 0.032 | 60 | 85.1572 | 0.0422 | 0.032 | 0.01688 | 32 mmø-32 mmø | 0.016 | 0.0000723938 | 132 mmø-132 mmø | 0.05 | Sistema di tubazioni: Mandata sistema idronico | Mandata di sistema idronico | Mandata sistema idronico 41 | Livello: 1 - Piano Primo | Livello : 1 - Piano Primo | 2.96 | Isolamento - Tipo di isolamento: Default
287813 | 1 - Piano Primo | 0.076 | 0.04445 | 0.076 | 67 | 90 | 0.0889 | 0.08 | 0.03556 | 80 mmø-80 mmø | 0.04 | 0.000740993 | 80 mmø-80 mmø | 0 | Sistema di tubazioni: Mandata sistema idronico | Mandata di sistema idronico | Mandata sistema idronico 40 | Livello: 1 - Piano Primo | Livello : 1 - Piano Primo | 2.96
287817 | 1 - Piano Primo | 0.076 | 0.04445 | 0.076 | 69 | 90 | 0.0889 | 0.08 | 0.03556 | 80 mmø-80 mmø | 0.04 | 0.000740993 | 80 mmø-80 mmø | 0 | Sistema di tubazioni: Mandata sistema idronico | Mandata di sistema idronico | Mandata sistema idronico 40 | Livello: 1 - Piano Primo | Livello : 1 - Piano Primo | 3.16
288770 | 1 - Piano Primo | 0.165423 | 0.08415 | 0.152 | 73 | 85.1572 | 0.1683 | 0.15 | 0.06732 | 150 mmø-150 mmø | 0.075 | 0.00546938 | 150 mmø-150 mmø | 0 | Sistema di tubazioni: Mandata sistema idronico | Mandata di sistema idronico | Mandata sistema idronico 39 | Livello: 1 - Piano Primo | Livello : 1 - Piano Primo | 2.96
288901 | 1 - Piano Primo | 0.0320004 | 0.0211 | 0.032 | 74 | 89.9992 | 0.0422 | 0.032 | 0.01688 | 32 mmø-32 mmø | 0.016 | 0.000070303 | 132 mmø-132 mmø | 0.05 | Sistema di tubazioni: Mandata sistema idronico | Mandata di sistema idronico | Mandata sistema idronico 41 | Livello: 1 - Piano Primo | Livello : 1 - Piano Primo | 2.96 | Isolamento - Tipo di isolamento: Default
289926 | 1 - Piano Primo | 0.032 | 0.0211 | 0.032 | 76 | 90 | 0.0422 | 0.032 | 0.01688 | 32 mmø-32 mmø | 0.016 | 0.0000703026 | 132 mmø-132 mmø | 0.05 | Sistema di tubazioni: Mandata sistema idronico | Mandata di sistema idronico | Mandata sistema idronico 41 | Livello: 1 - Piano Primo | Livello : 1 - Piano Primo | 5.12 | Isolamento - Tipo di isolamento: Default
290280 | 1 - Piano Primo | 0.076 | 0.04445 | 0.076 | 68 | 90 | 0.0889 | 0.08 | 0.03556 | 80 mmø-80 mmø | 0.04 | 0.000740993 | 80 mmø-80 mmø | 0 | Sistema di tubazioni: Mandata sistema idronico | Mandata di sistema idronico | Mandata sistema idronico 40 | Livello: 1 - Piano Primo | Livello : 1 - Piano Primo | 3.16
290293 | 1 - Piano Primo | 0.151951 | 0.08415 | 0.152 | 71 | 90.0185 | 0.1683 | 0.15 | 0.06732 | 150 mmø-150 mmø | 0.075 | 0.00531077 | 150 mmø-150 mmø | 0 | Sistema di tubazioni: Mandata sistema idronico | Mandata di sistema idronico | Mandata sistema idronico 39 | Livello: 1 - Piano Primo | Livello : 1 - Piano Primo | 2.96
290733 | 1 - Piano Primo | 0.152 | 0.08415 | 0.152 | 75 | 90 | 0.1683 | 0.15 | 0.06732 | 150 mmø-150 mmø | 0.075 | 0.00531139 | 150 mmø-150 mmø | 0 | Sistema di tubazioni: Mandata sistema idronico | Mandata di sistema idronico | Mandata sistema idronico 39 | Livello: 1 - Piano Primo | Livello : 1 - Piano Primo | 2.96
290735 | 1 - Piano Primo | 0.165423 | 0.08415 | 0.152 | 65 | 85.1572 | 0.1683 | 0.15 | 0.06732 | 150 mmø-150 mmø | 0.075 | 0.00546938 | 150 mmø-150 mmø | 0 | Sistema di tubazioni: Mandata sistema idronico | Mandata di sistema idronico | Mandata sistema idronico 39 | Livello: 1 - Piano Primo | Livello : 1 - Piano Primo | 2.96
290737 | 1 - Piano Primo | 0.076 | 0.04445 | 0.076 | 66 | 90 | 0.0889 | 0.08 | 0.03556 | 80 mmø-80 mmø | 0.04 | 0.000740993 | 80 mmø-80 mmø | 0 | Sistema di tubazioni: Mandata sistema idronico | Mandata di sistema idronico | Mandata sistema idronico 40 | Livello: 1 - Piano Primo | Livello : 1 - Piano Primo | 2.96
290739 | 1 - Piano Primo | 0.0827113 | 0.04445 | 0.076 | 63 | 85.1572 | 0.0889 | 0.08 | 0.03556 | 80 mmø-80 mmø | 0.04 | 0.000763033 | 80 mmø-80 mmø | 0 | Sistema di tubazioni: Mandata sistema idronico | Mandata di sistema idronico | Mandata sistema idronico 40 | Livello: 1 - Piano Primo | Livello : 1 - Piano Primo | 2.96
302307 | 2 - Piano Secondo | 0.0340625 | 0.0211 | 0.032 | 78 | 86.4236 | 0.0422 | 0.032 | 0.01688 | 32 mmø-32 mmø | 0.016 | 0.00007186 | 32 mmø-32 mmø | 0 | Sistema di tubazioni: Mandata sistema idronico | Mandata di sistema idronico | Mandata sistema idronico 50 | Livello: 2 - Piano Secondo | Livello : 2 - Piano Secondo | 0.85
302318 | 2 - Piano Secondo | 0.260619 | 0.0211 | 0.032 | 79 | 14 | 0.0422 | 0.032 | 0.01688 | 32 mmø-32 mmø | 0.016 | 0.0000890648 | 32 mmø-32 mmø | 0 | Sistema di tubazioni: Mandata sistema idronico | Mandata di sistema idronico | Mandata sistema idronico 50 | Livello: 2 - Piano Secondo | Livello : 2 - Piano Secondo | 0.85
302329 | 2 - Piano Secondo | 0.260619 | 0.0211 | 0.032 | 80 | 14 | 0.0422 | 0.032 | 0.01688 | 32 mmø-32 mmø | 0.016 | 0.0000890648 | 32 mmø-32 mmø | 0 | Sistema di tubazioni: Mandata sistema idronico | Mandata di sistema idronico | Mandata sistema idronico 50 | Livello: 2 - Piano Secondo | Livello : 2 - Piano Secondo | 0.85
302343 | 2 - Piano Secondo | 0.227692 | 0.0211 | 0.032 | 81 | 16 | 0.0422 | 0.032 | 0.01688 | 32 mmø-32 mmø | 0.016 | 0.0000889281 | 32 mmø-32 mmø | 0 | Sistema di tubazioni: Mandata sistema idronico | Mandata di sistema idronico | Mandata sistema idronico 50 | Livello: 2 - Piano Secondo | Livello : 2 - Piano Secondo | 0.85
302356 | 2 - Piano Secondo | 0.578786 | 0.0211 | 0.032 | 82 | 6.32911 | 0.0422 | 0.032 | 0.01688 | 32 mmø-32 mmø | 0.016 | 0.0000894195 | 32 mmø-32 mmø | 0 | Sistema di tubazioni: Mandata sistema idronico | Mandata di sistema idronico | Mandata sistema idronico 50 | Livello: 2 - Piano Secondo | Livello : 2 - Piano Secondo | 0.85
302370 | 2 - Piano Secondo | 0.320578 | 0.0211 | 0.032 | 84 | 11.4007 | 0.0422 | 0.032 | 0.01688 | 32 mmø-32 mmø | 0.016 | 0.000089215 | 32 mmø-32 mmø | 0 | Sistema di tubazioni: Mandata sistema idronico | Mandata di sistema idronico | Mandata sistema idronico 50 | Livello: 2 - Piano Secondo | Livello : 2 - Piano Secondo | 0.85
304076 | 2 - Piano Secondo | 0.032 | 0.0211 | 0.032 | 86 | 90 | 0.0422 | 0.032 | 0.01688 | 32 mmø-32 mmø | 0.016 | 0.0000703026 | 32 mmø-32 mmø | 0 | Sistema di tubazioni: Mandata sistema idronico | Mandata di sistema idronico | Mandata sistema idronico 51 | Livello: 2 - Piano Secondo | Livello : 2 - Piano Secondo | 0.7
304086 | 2 - Piano Secondo | 0.032 | 0.0211 | 0.032 | 87 | 90 | 0.0422 | 0.032 | 0.01688 | 32 mmø-32 mmø | 0.016 | 0.0000703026 | 32 mmø-32 mmø | 0 | Sistema di tubazioni: Mandata sistema idronico | Mandata di sistema idronico | Mandata sistema idronico 51 | Livello: 2 - Piano Secondo | Livello : 2 - Piano Secondo | 0.7
304098 | 2 - Piano Secondo | 0.032 | 0.0211 | 0.032 | 88 | 90 | 0.0422 | 0.032 | 0.01688 | 32 mmø-32 mmø | 0.016 | 0.0000703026 | 32 mmø-32 mmø | 0 | Sistema di tubazioni: Mandata sistema idronico | Mandata di sistema idronico | Mandata sistema idronico 51 | Livello: 2 - Piano Secondo | Livello : 2 - Piano Secondo | 0.7
304110 | 2 - Piano Secondo | 0.032 | 0.0211 | 0.032 | 89 | 90 | 0.0422 | 0.032 | 0.01688 | 32 mmø-32 mmø | 0.016 | 0.0000703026 | 32 mmø-32 mmø | 0 | Sistema di tubazioni: Mandata sistema idronico | Mandata di sistema idronico | Mandata sistema idronico 51 | Livello: 2 - Piano Secondo | Livello : 2 - Piano Secondo | 0.7
304462 | 2 - Piano Secondo | 0.032 | 0.0211 | 0.032 | 77 | 90 | 0.0422 | 0.032 | 0.01688 | 32 mmø-32 mmø | 0.016 | 0.0000703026 | 32 mmø-32 mmø | 0 | Sistema di tubazioni: Mandata sistema idronico | Mandata di sistema idronico | Mandata sistema idronico 50 | Livello: 2 - Piano Secondo | Livello : 2 - Piano Secondo | 0.85
304528 | 2 - Piano Secondo | 0.032 | 0.0211 | 0.032 | 90 | 90 | 0.0422 | 0.032 | 0.01688 | 32 mmø-32 mmø | 0.016 | 0.0000703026 | 32 mmø-32 mmø | 0 | Sistema di tubazioni: Mandata sistema idronico | Mandata di sistema idronico | Mandata sistema idronico 50 | Livello: 2 - Piano Secondo | Livello : 2 - Piano Secondo | 0.85
304530 | 2 - Piano Secondo | 0.032 | 0.0211 | 0.032 | 91 | 90 | 0.0422 | 0.032 | 0.01688 | 32 mmø-32 mmø | 0.016 | 0.0000703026 | 32 mmø-32 mmø | 0 | Sistema di tubazioni: Mandata sistema idronico | Mandata di sistema idronico | Mandata sistema idronico 51 | Livello: 2 - Piano Secondo | Livello : 2 - Piano Secondo | 0.7
304532 | 2 - Piano Secondo | 0.032 | 0.0211 | 0.032 | 85 | 90 | 0.0422 | 0.032 | 0.01688 | 32 mmø-32 mmø | 0.016 | 0.0000703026 | 32 mmø-32 mmø | 0 | Sistema di tubazioni: Mandata sistema idronico | Mandata di sistema idronico | Mandata sistema idronico 51 | Livello: 2 - Piano Secondo | Livello : 2 - Piano Secondo | 0.85
304654 | 2 - Piano Secondo | 0.032 | 0.0211 | 0.032 | 93 | 90 | 0.0422 | 0.032 | 0.01688 | 32 mmø-32 mmø | 0.016 | 0.0000703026 | 32 mmø-32 mmø | 0 | Sistema di tubazioni: Mandata sistema idronico | Mandata di sistema idronico | Mandata sistema idronico 54 | Livello: 2 - Piano Secondo | Livello : 2 - Piano Secondo | 2
304991 | 1 - Piano Primo | 0.032 | 0.0211 | 0.032 | 94 | 90 | 0.0422 | 0.032 | 0.01688 | 32 mmø-32 mmø | 0.016 | 0.0000703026 | 32 mmø-32 mmø | 0 | Sistema di tubazioni: Mandata sistema idronico | Mandata di sistema idronico | Mandata sistema idronico 46 | Livello: 1 - Piano Primo | Livello : 1 - Piano Primo | 5.77
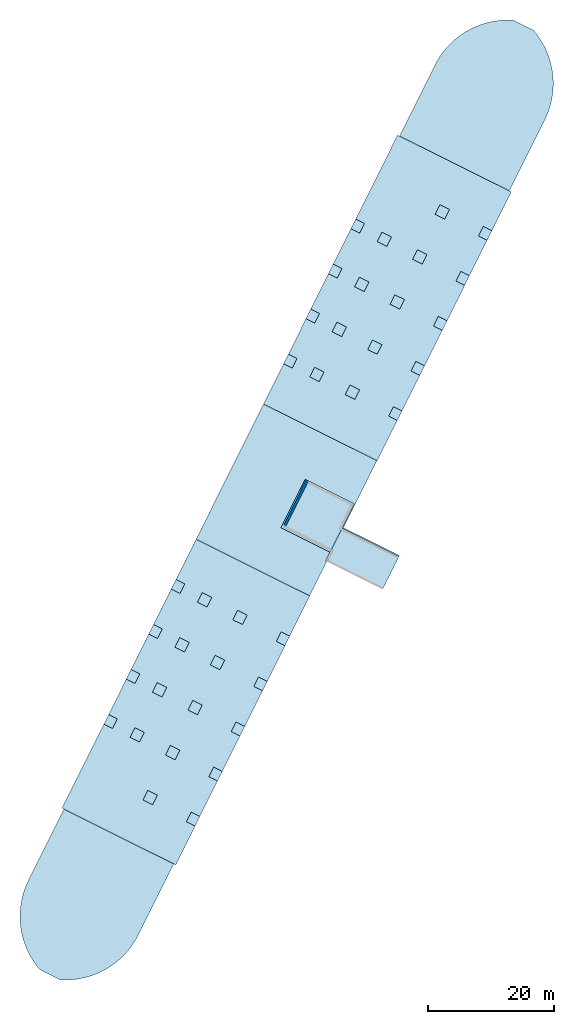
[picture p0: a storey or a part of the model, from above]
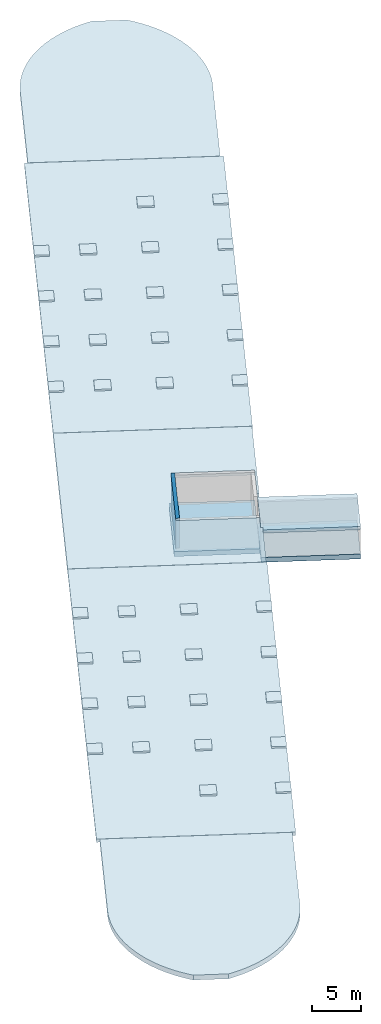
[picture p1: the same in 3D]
Properties of the parts of a building model (IFC2X3), part 3 of 7

# IfcFlowFitting: Standard (63)
Name (M_Gomito - Saldato - Generico:Standard:...) | In | Raggio centro (m) | Raggio esterno raccordo (m) | Testo etichetta da centro a estremità (m) = Da centro a estremità (m) | Contrassegno | Angolo (deg) | Diametro esterno raccordo (m) | Diametro nominale (m) = Dimensione massima (m) = Dimensione minima (m) | Dimensione contrassegno (m) | Dimensioni | Raggio nominale (m) | Volume (m3) | Dimensione totale | Spessore isolamento (m) | Tipo di sistema | Classificazione sistema | Nome sistema = Group | Livello | Host | Offset (m)
304993 | 1 - Piano Primo | 0.032 | 0.0211 | 0.032 | 95 | 90 | 0.0422 | 0.032 | 0.01688 | 32 mmø-32 mmø | 0.016 | 0.0000703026 | 32 mmø-32 mmø | 0 | Sistema di tubazioni: Mandata sistema idronico | Mandata di sistema idronico | Mandata sistema idronico 46 | Livello: 1 - Piano Primo | Livello : 1 - Piano Primo | 4.77
305468 | 2 - Piano Secondo | 0.032 | 0.0211 | 0.032 | 98 | 90 | 0.0422 | 0.032 | 0.01688 | 32 mmø-32 mmø | 0.016 | 0.0000703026 | 32 mmø-32 mmø | 0 | Sistema di tubazioni: Mandata sistema idronico | Mandata di sistema idronico | Mandata sistema idronico 54 | Livello: 2 - Piano Secondo | Livello : 2 - Piano Secondo | 0.7
305504 | 1 - Piano Primo | 0.032 | 0.0211 | 0.032 | 99 | 90 | 0.0422 | 0.032 | 0.01688 | 32 mmø-32 mmø | 0.016 | 0.0000703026 | 32 mmø-32 mmø | 0 | Sistema di tubazioni: Mandata sistema idronico | Mandata di sistema idronico | Mandata sistema idronico 54 | Livello: 1 - Piano Primo | Livello : 1 - Piano Primo | 4.62
305506 | 2 - Piano Secondo | 0.032 | 0.0211 | 0.032 | 97 | 90 | 0.0422 | 0.032 | 0.01688 | 32 mmø-32 mmø | 0.016 | 0.0000703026 | 32 mmø-32 mmø | 0 | Sistema di tubazioni: Mandata sistema idronico | Mandata di sistema idronico | Mandata sistema idronico 54 | Livello: 2 - Piano Secondo | Livello : 2 - Piano Secondo | 0.7
305893 | 2 - Piano Secondo | 0.032 | 0.0211 | 0.032 | 100 | 90 | 0.0422 | 0.032 | 0.01688 | 32 mmø-32 mmø | 0.016 | 0.0000703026 | 32 mmø-32 mmø | 0 | Sistema di tubazioni: Mandata sistema idronico | Mandata di sistema idronico | Mandata sistema idronico 50 | Livello: 2 - Piano Secondo | Livello : 2 - Piano Secondo | 0.85
305897 | 2 - Piano Secondo | 0.032 | 0.0211 | 0.032 | 102 | 90 | 0.0422 | 0.032 | 0.01688 | 32 mmø-32 mmø | 0.016 | 0.0000703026 | 32 mmø-32 mmø | 0 | Sistema di tubazioni: Mandata sistema idronico | Mandata di sistema idronico | Mandata sistema idronico 50 | Livello: 2 - Piano Secondo | Livello : 2 - Piano Secondo | 1.15
305899 | 2 - Piano Secondo | 0.032 | 0.0211 | 0.032 | 103 | 90 | 0.0422 | 0.032 | 0.01688 | 32 mmø-32 mmø | 0.016 | 0.0000703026 | 32 mmø-32 mmø | 0 | Sistema di tubazioni: Mandata sistema idronico | Mandata di sistema idronico | Mandata sistema idronico 50 | Livello: 2 - Piano Secondo | Livello : 2 - Piano Secondo | 0.85
305901 | 2 - Piano Secondo | 0.032 | 0.0211 | 0.032 | 101 | 90 | 0.0422 | 0.032 | 0.01688 | 32 mmø-32 mmø | 0.016 | 0.0000703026 | 32 mmø-32 mmø | 0 | Sistema di tubazioni: Mandata sistema idronico | Mandata di sistema idronico | Mandata sistema idronico 50 | Livello: 2 - Piano Secondo | Livello : 2 - Piano Secondo | 1.15
306248 | 2 - Piano Secondo | 0.032 | 0.0211 | 0.032 | 96 | 90 | 0.0422 | 0.032 | 0.01688 | 32 mmø-32 mmø | 0.016 | 0.0000703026 | 32 mmø-32 mmø | 0 | Sistema di tubazioni: Mandata sistema idronico | Mandata di sistema idronico | Mandata sistema idronico 46 | Livello: 2 - Piano Secondo | Livello : 2 - Piano Secondo | 0.85

# IfcFlowFitting: Standard, M_Raccordo a T - Saldato - Generico:Standard:283164
In: 0 - Piano Terra
Type - Altro - Categoria: Raccordi tubazione; Nome famiglia: M_Raccordo a T - Saldato - Generico; Nome tabella di ricerca: M_Tee - Welded - Generic
Type - Dati identità - Nome del tipo: Standard; Numero OmniClass: 23.60.30.11.14; Titolo OmniClass: Pipework Fittings
Type - Meccanica - Metodo di perdita: Coefficiente K da tabella; Tabella di coefficienti K: Raccordo a T
Pset_DistributionFlowElementCommon - Reference: Standard
Altro - Angolo 1: 90 deg; Famiglia: M_Raccordo a T - Saldato - Generico: Standard; Famiglia e tipo: M_Raccordo a T - Saldato - Generico: Standard; ID tipo: M_Raccordo a T - Saldato - Generico: Standard; Raggio esterno raccordo: 0.03015 m; Testo etichetta da centro a estremità: 0.064 m; Tipo: M_Raccordo a T - Saldato - Generico: Standard
Dati identità - Contrassegno: 54
Dimensioni - Angolo: 90 deg; Da centro a estremità: 0.064 m; Diametro esterno raccordo: 0.0603 m; Diametro nominale: 0.05 m; Dimensione contrassegno: 0.02412 m; Dimensione massima: 0.05 m; Dimensione minima: 0.05 m; Dimensioni: 50 mmø-50 mmø-50 mmø; Raggio nominale: 0.025 m; Volume: 0.000475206 m3
Fasi - Fase di creazione: Stato di Fatto
Grafica - Utilizza scala di annotazione: no
Isolamento - Dimensione totale: 150 mmø-150 mmø-150 mmø; Spessore isolamento: 0.05 m; Tipo di isolamento: Default
Meccanica - Tipo di sistema: Sistema di tubazioni: Mandata sistema idronico; Classificazione sistema: Mandata di sistema idronico; Nome sistema: Mandata sistema idronico 34
Vincoli - Livello: Livello: 0 - Piano Terra; Host: Livello : 0 - Piano Terra; Offset: 3.5 m
Group: Mandata sistema idronico 34

# IfcFlowSegment: Condotto circolare:Canna fumaria (12)
Type - Altro - Categoria: Condotto; Nome famiglia: Condotto circolare
Type - Costruzione - Ruvidità: 0.00009144 m
Type - Dati identità - Nome del tipo: Canna fumaria
Pset_DistributionFlowElementCommon - Reference: Canna fumaria
Altro - Famiglia: Condotto circolare: Canna fumaria; Famiglia e tipo: Condotto circolare: Canna fumaria; ID tipo: Condotto circolare: Canna fumaria; Tipo: Condotto circolare: Canna fumaria
Dimensioni - Diametro: 0.25 m; Dimensioni: 250 mmø
Fasi - Fase di creazione: Stato di Fatto
Isolamento - Spessore isolamento: 0 m; Dimensione totale: 250 mmø
Meccanica - Tipo di sistema: Sistema di condotti: Aria di mandata; Blocco dimensione: no; Classificazione sistema: Aria di mandata; Coefficiente di perdita: 0; Diametro equivalente: 0.25 m; Diametro idraulico: 0.25 m
Meccanico - Flusso - Caduta pressione: 0 Pa; Flusso: 0 m3/s; Flusso aggiuntivo: 0 m3/s; Frizione: 0; Numero di Reynolds: 0; Pressione velocità: 0 Pa; Velocità: 0
Rivestimento - Spessore rivestimento: 0 m; Dimensione libera: 250 mmø
Vincoli - Giustificazione orizzontale: Al centro; Giustificazione verticale: Al centro
Name (Condotto circolare:Canna fumaria:...) | In | Contrassegno | Lunghezza (m) | Area (m2) | Nome sistema | Quota altimetrica inferiore (m) | Quota altimetrica superiore (m) | Sezione | Livello di riferimento | Offset (m) = Offset iniziale (m) | Offset finale (m) | Inclinazione
205913 | 0 - Piano Terra | 1 | 5.9344 | 4.66087 | Meccanica Aria di mandata 1 | -5.3847 | 0.549702 | 2 | Livello: 2 - Piano Secondo | 0.549702 | -5.3847 | Group: Meccanica Aria di mandata 1
205915 | 2 - Piano Secondo | 2 | 0.25 | 0.19635 | Meccanica Aria di mandata 3 | 0.6 | 0.85 | 1 | Livello: 2 - Piano Secondo | 0.725 | 0.725 | 0
205923 | 2 - Piano Secondo | 4 | 0.25 | 0.19635 | Meccanica Aria di mandata 7 | 0.6 | 0.85 | 1 | Livello: 2 - Piano Secondo | 0.725 | 0.725 | 0
205925 | 2 - Piano Secondo | 5 | 0.25 | 0.19635 | Meccanica Aria di mandata 8 | 0.6 | 0.85 | 1 | Livello: 2 - Piano Secondo | 0.725 | 0.725 | 0
205927 | 2 - Piano Secondo | 6 | 0.25 | 0.19635 | Meccanica Aria di mandata 9 | 0.6 | 0.85 | 1 | Livello: 2 - Piano Secondo | 0.725 | 0.725 | 0
205929 | 0 - Piano Terra | 7 | 5.9344 | 4.66087 | Meccanica Aria di mandata 10 | -5.3847 | 0.549702 | 2 | Livello: 2 - Piano Secondo | -5.3847 | 0.549702 | Group: Meccanica Aria di mandata 10
205931 | 0 - Piano Terra | 8 | 6.0844 | 4.77868 | Meccanica Aria di mandata 11 | -5.5347 | 0.549702 | 2 | Livello: 2 - Piano Secondo | -5.5347 | 0.549702 | Group: Meccanica Aria di mandata 11
205933 | 0 - Piano Terra | 9 | 6.0844 | 4.77868 | Meccanica Aria di mandata 12 | -5.5347 | 0.549702 | 2 | Livello: 2 - Piano Secondo | -5.5347 | 0.549702 | Group: Meccanica Aria di mandata 12
205935 | 0 - Piano Terra | 12 | 1.3 | 1.02102 | Meccanica Aria di mandata 13 | 2.775 | 3.025 | 1 | Livello: 0 - Piano Terra | 2.9 | 2.9 | 0
205943 | 0 - Piano Terra | 13 | 1.3 | 1.02102 | Meccanica Aria di mandata 17 | 2.775 | 3.025 | 1 | Livello: 0 - Piano Terra | 2.9 | 2.9 | 0
205945 | 0 - Piano Terra | 14 | 1.3 | 1.02102 | Meccanica Aria di mandata 18 | 2.925 | 3.175 | 1 | Livello: 0 - Piano Terra | 3.05 | 3.05 | 0
205947 | 0 - Piano Terra | 15 | 1.3 | 1.02102 | Meccanica Aria di mandata 19 | 2.925 | 3.175 | 1 | Livello: 0 - Piano Terra | 3.05 | 3.05 | 0

# IfcFlowSegment: Passerella con raccordi:Passerella canale (55)
Type - Altro - Categoria: Passerelle; Nome famiglia: Passerella con raccordi
Type - Dati identità - Nome del tipo: Passerella canale
Type - Elettrico - Moltiplicatore raggio di curvatura: 1
Type - Raccordi - Curvatura esterna verticale: M_Curvatura esterna verticale canale: Standard; Curvatura interna verticale: M_Curvatura interna verticale canale: Standard; Curvatura orizzontale: M_Curvatura orizzontale canale: Standard
Pset_DistributionFlowElementCommon - Reference: Passerella canale
Altro - Famiglia: Passerella con raccordi: Passerella canale; Famiglia e tipo: Passerella con raccordi: Passerella canale; ID tipo: Passerella con raccordi: Passerella canale; Tipo: Passerella con raccordi: Passerella canale
Dimensioni - Altezza: 0.075 m
Fasi - Fase di creazione: Stato di Fatto
Vincoli - Giustificazione orizzontale: Al centro; Giustificazione verticale: Al centro
Name (Passerella con raccordi:Passerella canale:...) | In | Contrassegno | Dimensioni | Larghezza (m) | Lunghezza (m) | Quota altimetrica inferiore (m) | Quota altimetrica superiore (m) | Livello di riferimento | Offset (m) = Offset iniziale (m) | Offset finale (m)
252470 | 0 - Piano Terra | 1 | 100 mmx75 mmø | 0.1 | 1.08 | 3.6625 | 3.7375 | Livello: 0 - Piano Terra | 3.7 | 3.7
252807 | 0 - Piano Terra | 5 | 300 mmx75 mmø | 0.3 | 41.3248 | 3.7625 | 3.8375 | Livello: 0 - Piano Terra | 3.8 | 3.8
272608 | 0 - Piano Terra | 7 | 100 mmx75 mmø | 0.1 | 0.698292 | 3.7625 | 3.8375 | Livello: 0 - Piano Terra | 3.8 | 3.8
273001 | 0 - Piano Terra | 17 | 100 mmx75 mmø | 0.1 | 0.0527003 | 3.69822 | 3.78953 | Livello: 0 - Piano Terra | 3.7307 | 3.75705
275845 | 0 - Piano Terra | 20 | 300 mmx75 mmø | 0.3 | 1.975 | 3.7625 | 3.8375 | Livello: 0 - Piano Terra | 3.8 | 3.8
276943 | 0 - Piano Terra | 24 | 300 mmx75 mmø | 0.3 | 0.0527003 | 3.69822 | 3.78953 | Livello: 0 - Piano Terra | 3.7307 | 3.75705
277025 | 0 - Piano Terra | 25 | 300 mmx75 mmø | 0.3 | 0.7 | 3.66275 | 3.73775 | Livello: 0 - Piano Terra | 3.70025 | 3.70025
277680 | 0 - Piano Terra | 26 | 300 mmx75 mmø | 0.3 | 22.6395 | 3.7625 | 3.8375 | Livello: 0 - Piano Terra | 3.8 | 3.8
277687 | 0 - Piano Terra | 27 | 300 mmx75 mmø | 0.3 | 0.0527003 | 3.69822 | 3.78953 | Livello: 0 - Piano Terra | 3.7307 | 3.75705
277736 | 0 - Piano Terra | 28 | 300 mmx75 mmø | 0.3 | 0.0527003 | 3.69822 | 3.78953 | Livello: 0 - Piano Terra | 3.7307 | 3.75705
277739 | 0 - Piano Terra | 29 | 300 mmx75 mmø | 0.3 | 0.7 | 3.66275 | 3.73775 | Livello: 0 - Piano Terra | 3.70025 | 3.70025
277740 | 0 - Piano Terra | 30 | 300 mmx75 mmø | 0.3 | 0.0527003 | 3.69822 | 3.78953 | Livello: 0 - Piano Terra | 3.7307 | 3.75705
277906 | 0 - Piano Terra | 31 | 300 mmx75 mmø | 0.3 | 45.7222 | 3.7625 | 3.8375 | Livello: 0 - Piano Terra | 3.8 | 3.8
278027 | 0 - Piano Terra | 32 | 450 mmx75 mmø | 0.45 | 44.1498 | 3.6625 | 3.7375 | Livello: 0 - Piano Terra | 3.7 | 3.7
278028 | 0 - Piano Terra | 33 | 450 mmx75 mmø | 0.45 | 0.0527003 | 3.59822 | 3.68953 | Livello: 0 - Piano Terra | 3.6307 | 3.65705
278031 | 0 - Piano Terra | 34 | 450 mmx75 mmø | 0.45 | 0.7 | 3.56275 | 3.63775 | Livello: 0 - Piano Terra | 3.60025 | 3.60025
278032 | 0 - Piano Terra | 35 | 450 mmx75 mmø | 0.45 | 22.6395 | 3.6625 | 3.7375 | Livello: 0 - Piano Terra | 3.7 | 3.7
278033 | 0 - Piano Terra | 36 | 450 mmx75 mmø | 0.45 | 0.0527003 | 3.59822 | 3.68953 | Livello: 0 - Piano Terra | 3.6307 | 3.65705
278036 | 0 - Piano Terra | 37 | 450 mmx75 mmø | 0.45 | 0.0527003 | 3.59822 | 3.68953 | Livello: 0 - Piano Terra | 3.6307 | 3.65705
278039 | 0 - Piano Terra | 38 | 450 mmx75 mmø | 0.45 | 0.7 | 3.56275 | 3.63775 | Livello: 0 - Piano Terra | 3.60025 | 3.60025
278040 | 0 - Piano Terra | 39 | 450 mmx75 mmø | 0.45 | 0.0527003 | 3.59822 | 3.68953 | Livello: 0 - Piano Terra | 3.6307 | 3.65705
278043 | 0 - Piano Terra | 40 | 450 mmx75 mmø | 0.45 | 45.7222 | 3.6625 | 3.7375 | Livello: 0 - Piano Terra | 3.7 | 3.7
291911 | 1 - Piano Primo | 41 | 300 mmx75 mmø | 0.3 | 44.1498 | 2.9925 | 3.0675 | Livello: 1 - Piano Primo | 3.03 | 3.03
291914 | 1 - Piano Primo | 43 | 300 mmx75 mmø | 0.3 | 0.0527003 | 2.92822 | 3.01953 | Livello: 1 - Piano Primo | 2.9607 | 2.98705
291917 | 1 - Piano Primo | 44 | 300 mmx75 mmø | 0.3 | 0.7 | 2.89275 | 2.96775 | Livello: 1 - Piano Primo | 2.93025 | 2.93025
291918 | 1 - Piano Primo | 45 | 300 mmx75 mmø | 0.3 | 22.6395 | 2.9925 | 3.0675 | Livello: 1 - Piano Primo | 3.03 | 3.03
291919 | 1 - Piano Primo | 46 | 300 mmx75 mmø | 0.3 | 0.0527003 | 2.92822 | 3.01953 | Livello: 1 - Piano Primo | 2.9607 | 2.98705
291922 | 1 - Piano Primo | 47 | 300 mmx75 mmø | 0.3 | 0.0527003 | 2.92822 | 3.01953 | Livello: 1 - Piano Primo | 2.9607 | 2.98705
291925 | 1 - Piano Primo | 48 | 300 mmx75 mmø | 0.3 | 0.7 | 2.89275 | 2.96775 | Livello: 1 - Piano Primo | 2.93025 | 2.93025
291926 | 1 - Piano Primo | 49 | 300 mmx75 mmø | 0.3 | 0.0527003 | 2.92822 | 3.01953 | Livello: 1 - Piano Primo | 2.9607 | 2.98705
291929 | 1 - Piano Primo | 50 | 300 mmx75 mmø | 0.3 | 45.7222 | 2.9925 | 3.0675 | Livello: 1 - Piano Primo | 3.03 | 3.03
292147 | 1 - Piano Primo | 54 | 450 mmx75 mmø | 0.45 | 44.1498 | 2.8925 | 2.9675 | Livello: 1 - Piano Primo | 2.93 | 2.93
292148 | 1 - Piano Primo | 55 | 450 mmx75 mmø | 0.45 | 0.0527003 | 2.82822 | 2.91953 | Livello: 1 - Piano Primo | 2.8607 | 2.88705
292151 | 1 - Piano Primo | 56 | 450 mmx75 mmø | 0.45 | 0.7 | 2.79275 | 2.86775 | Livello: 1 - Piano Primo | 2.83025 | 2.83025
292152 | 1 - Piano Primo | 57 | 450 mmx75 mmø | 0.45 | 22.6395 | 2.8925 | 2.9675 | Livello: 1 - Piano Primo | 2.93 | 2.93
292153 | 1 - Piano Primo | 58 | 450 mmx75 mmø | 0.45 | 0.0527003 | 2.82822 | 2.91953 | Livello: 1 - Piano Primo | 2.8607 | 2.88705
292156 | 1 - Piano Primo | 59 | 450 mmx75 mmø | 0.45 | 0.0527003 | 2.82822 | 2.91953 | Livello: 1 - Piano Primo | 2.8607 | 2.88705
292159 | 1 - Piano Primo | 60 | 450 mmx75 mmø | 0.45 | 0.7 | 2.79275 | 2.86775 | Livello: 1 - Piano Primo | 2.83025 | 2.83025
292160 | 1 - Piano Primo | 61 | 450 mmx75 mmø | 0.45 | 0.0527003 | 2.82822 | 2.91953 | Livello: 1 - Piano Primo | 2.8607 | 2.88705
292163 | 1 - Piano Primo | 62 | 450 mmx75 mmø | 0.45 | 45.7222 | 2.8925 | 2.9675 | Livello: 1 - Piano Primo | 2.93 | 2.93
292725 | 2 - Piano Secondo | 66 | 150 mmx75 mmø | 0.15 | 36.0673 | 1.0225 | 1.0975 | Livello: 2 - Piano Secondo | 1.06 | 1.06
293003 | 2 - Piano Secondo | 67 | 150 mmx75 mmø | 0.15 | 4.77 | 2.3125 | 2.3875 | Livello: 2 - Piano Secondo | 2.35 | 2.35
293844 | 0 - Piano Terra | 68 | 150 mmx75 mmø | 0.15 | 6.2325 | -5.305 | 0.9275 | Livello: 2 - Piano Secondo | 0.9275 | -5.305
294956 | 2 - Piano Secondo | 69 | 150 mmx75 mmø | 0.15 | 8.03 | 2.3125 | 2.3875 | Livello: 2 - Piano Secondo | 2.35 | 2.35
296225 | 2 - Piano Secondo | 72 | 150 mmx75 mmø | 0.15 | 0.777365 | 1.1425 | 1.91987 | Livello: 2 - Piano Secondo | 1.1425 | 1.91987
296338 | 2 - Piano Secondo | 73 | 150 mmx75 mmø | 0.15 | 0.255919 | 1.97669 | 2.21068 | Livello: 2 - Piano Secondo | 2.0032 | 2.18416
300293 | 2 - Piano Secondo | 82 | 150 mmx75 mmø | 0.15 | 4.77 | 2.3125 | 2.3875 | Livello: 2 - Piano Secondo | 2.35 | 2.35
300344 | 2 - Piano Secondo | 83 | 150 mmx75 mmø | 0.15 | 3.18194 | 0.9475 | 1.0225 | Livello: 2 - Piano Secondo | 0.985 | 0.985
300348 | 2 - Piano Secondo | 84 | 150 mmx75 mmø | 0.15 | 0.852365 | 1.0675 | 1.91987 | Livello: 2 - Piano Secondo | 1.0675 | 1.91987
300349 | 2 - Piano Secondo | 85 | 150 mmx75 mmø | 0.15 | 0.255919 | 1.97669 | 2.21068 | Livello: 2 - Piano Secondo | 2.0032 | 2.18416
300820 | 2 - Piano Secondo | 87 | 150 mmx75 mmø | 0.15 | 0.976824 | 0.15 | 0.225 | Livello: 2 - Piano Secondo | 0.1875 | 0.1875
300821 | 2 - Piano Secondo | 88 | 150 mmx75 mmø | 0.15 | 0.1 | 0.195503 | 0.319246 | Livello: 2 - Piano Secondo | 0.222019 | 0.29273
300907 | 2 - Piano Secondo | 89 | 150 mmx75 mmø | 0.15 | 0.08 | 0.289749 | 0.364749 | Livello: 2 - Piano Secondo | 0.327249 | 0.327249
301287 | 2 - Piano Secondo | 90 | 150 mmx75 mmø | 0.15 | 0.284865 | 0.27 | 0.554865 | Livello: 2 - Piano Secondo | 0.27 | 0.554865
301288 | 2 - Piano Secondo | 91 | 150 mmx75 mmø | 0.15 | 0.255919 | 0.611685 | 0.84568 | Livello: 2 - Piano Secondo | 0.638202 | 0.819164

# IfcFlowSegment: Tubazione:Antincendio-Tubazione (59)
Type - Altro - Categoria: Tubazione; Nome famiglia: Tubazione
Type - Dati identità - Nome del tipo: Antincendio-Tubazione
Pset_DistributionFlowElementCommon - Reference: Antincendio-Tubazione
Altro - Famiglia: Tubazione: Antincendio-Tubazione; Famiglia e tipo: Tubazione: Antincendio-Tubazione; ID tipo: Tubazione: Antincendio-Tubazione; Tipo: Tubazione: Antincendio-Tubazione
Fasi - Fase di creazione: Stato di Fatto
Meccanica - Tipo di sistema: Sistema di tubazioni: Mandata sistema idronico; Abaco/Tipo: Tipi di abaco delle tubazioni: 10S; Materiale: Acciaio inossidabile; Segmento di tubazione: Acciaio inossidabile - 10S; Classificazione sistema: Mandata di sistema idronico; Ruvidità: 0.00054864 m; Tipo di connessione: Generico
Meccanico - Flusso - Frizione: 0; Numero di Reynolds: 0; Velocità: 0; Fattore di frizione: 0; Stato flusso: Laminare; Caduta pressione: 0 Pa; Flusso: 0 m3/s; Flusso aggiuntivo: 0 m3/s
Vincoli - Giustificazione orizzontale: Al centro; Giustificazione verticale: Al centro
Name (Tubazione:Antincendio-Tubazione:...) | In | Contrassegno | Diametro esterno (m) | Diametro interno (m) | Dimensioni | Lunghezza (m) | Dimensione totale | Spessore isolamento (m) | Sezione | Area (m2) | Diametro (m) | Nome sistema | Quota altimetrica fondo (m) | Ruvidità relativa | Inclinazione | Livello di riferimento | Offset (m) = Offset iniziale (m) | Offset finale (m) | Group
280359 | 0 - Piano Terra | 72 | 0.042164 | 0.0366268 | 32 mmø | 5.1438 | 132 mmø | 0.05 | 1 | 0.517111 | 0.032 | Mandata sistema idronico 35 | 3.48169 | 0.0149792 | 0 | Livello: 0 - Piano Terra | 3.5 | 3.50001 | Mandata sistema idronico 35 | Isolamento - Tipo di isolamento: Default
280916 | 0 - Piano Terra | 73 | 0.042164 | 0.0366268 | 32 mmø | 0.401836 | 132 mmø | 0.05 | 1 | 0.040397 | 0.032 | Mandata sistema idronico 35 | 3.24419 | 0.0149792 | 0 | Livello: 0 - Piano Terra | 3.2625 | 3.2625 | Mandata sistema idronico 35 | Isolamento - Tipo di isolamento: Default
280969 | 0 - Piano Terra | 74 | 0.042164 | 0.0366268 | 32 mmø | 0.17351 | 132 mmø | 0.05 | 1 | 0.0174432 | 0.032 | Mandata sistema idronico 35 | 3.2945 | 0.0149792 |  | Livello: 0 - Piano Terra | 3.2945 | 3.46801 | Mandata sistema idronico 35 | Isolamento - Tipo di isolamento: Default
281130 | 0 - Piano Terra | 75 | 0.060325 | 0.0547878 | 50 mmø | 9.7 | 150 mmø | 0.05 | 2 | 1.52367 | 0.05 | Mandata sistema idronico 36 | 0 | 0.0100139 |  | Livello: 0 - Piano Terra | 9.7 | 0 | Isolamento - Tipo di isolamento: Default
281235 | 0 - Piano Terra | 76 | 0.060325 | 0.0547878 | 50 mmø | 9.7 | 150 mmø | 0.05 | 2 | 1.52367 | 0.05 | Mandata sistema idronico 37 | 0 | 0.0100139 |  | Livello: 0 - Piano Terra | 9.7 | 0 | Isolamento - Tipo di isolamento: Default
282630 | 0 - Piano Terra | 80 | 0.042164 | 0.0366268 | 32 mmø | 1.658 | 132 mmø | 0.05 | 1 | 0.16668 | 0.032 | Mandata sistema idronico 35 | 3.48169 | 0.0149792 | 0 | Livello: 0 - Piano Terra | 3.5 | 3.5 | Mandata sistema idronico 35 | Isolamento - Tipo di isolamento: Default
282931 | 0 - Piano Terra | 81 | 0.060325 | 0.0547878 | 50 mmø | 3.436 | 150 mmø | 0.05 | 2 | 0.539726 | 0.05 | Mandata sistema idronico 34 | 0 | 0.0100139 |  | Livello: 0 - Piano Terra | 3.436 | 0 | Mandata sistema idronico 34 | Isolamento - Tipo di isolamento: Default
283168 | 0 - Piano Terra | 82 | 0.060325 | 0.0547878 | 50 mmø | 6.136 | 150 mmø | 0.05 | 3 | 0.963841 | 0.05 | Mandata sistema idronico 34 | 3.564 | 0.0100139 |  | Livello: 0 - Piano Terra | 3.564 | 9.7 | Mandata sistema idronico 34 | Isolamento - Tipo di isolamento: Default
284694 | 0 - Piano Terra | 84 | 0.0889 | 0.082804 | 80 mmø | 0.874 | 80 mmø | 0 | 1 | 0.21966 | 0.08 | Mandata sistema idronico 38 | 3.4586 | 0.00662577 | 0 | Livello: 0 - Piano Terra | 3.5 | 3.5 | Mandata sistema idronico 38
284987 | 0 - Piano Terra | 85 | 0.0889 | 0.082804 | 80 mmø | 13.7191 | 80 mmø | 0 | 1 | 3.44797 | 0.08 | Mandata sistema idronico 38 | 3.4586 | 0.00662577 | 0 | Livello: 0 - Piano Terra | 3.5 | 3.5 | Mandata sistema idronico 38
285095 | 0 - Piano Terra | 86 | 0.0889 | 0.082804 | 80 mmø | 1.674 | 80 mmø | 0 | 1 | 0.420722 | 0.08 | Mandata sistema idronico 38 | 3.4586 | 0.00662577 | 0 | Livello: 0 - Piano Terra | 3.5 | 3.5 | Mandata sistema idronico 38
285606 | 1 - Piano Primo | 88 | 0.0889 | 0.082804 | 80 mmø | 134.497 | 80 mmø | 0 | 1 | 33.8028 | 0.08 | Mandata sistema idronico 40 | 7.6086 | 0.00662577 | 0 | Livello: 1 - Piano Primo | 2.96 | 2.96 | Mandata sistema idronico 40
285633 | 1 - Piano Primo | 89 | 0.042164 | 0.0366268 | 32 mmø | 134.307 | 132 mmø | 0.05 | 2 | 13.502 | 0.032 | Mandata sistema idronico 41 | 7.63169 | 0.0149792 | 0 | Livello: 1 - Piano Primo | 2.96 | 2.96 | Mandata sistema idronico 41 | Isolamento - Tipo di isolamento: Default
286688 | 1 - Piano Primo | 90 | 0.042164 | 0.0366268 | 32 mmø | 1.796 | 132 mmø | 0.05 | 2 | 0.180554 | 0.032 | Mandata sistema idronico 41 | 7.682 | 0.0149792 |  | Livello: 1 - Piano Primo | 4.788 | 2.992 | Mandata sistema idronico 41 | Isolamento - Tipo di isolamento: Default
286755 | 2 - Piano Secondo | 91 | 0.042164 | 0.0366268 | 32 mmø | 0.053 | 132 mmø | 0.05 | 2 | 0.00532814 | 0.032 | Mandata sistema idronico 41 | 9.49169 | 0.0149792 | 0 | Livello: 1 - Piano Primo | 4.82 | 4.82 | Mandata sistema idronico 41 | Isolamento - Tipo di isolamento: Default
286861 | 1 - Piano Primo | 92 | 0.042164 | 0.0366268 | 32 mmø | 2.32172 | 132 mmø | 0.05 | 2 | 0.233405 | 0.032 | Mandata sistema idronico 41 | 7.63169 | 0.0149792 | 0 | Livello: 1 - Piano Primo | 2.96 | 2.96 | Mandata sistema idronico 41 | Isolamento - Tipo di isolamento: Default
287001 | 1 - Piano Primo | 94 | 0.042164 | 0.0366268 | 32 mmø | 0.839171 | 132 mmø | 0.05 | 2 | 0.0843627 | 0.032 | Mandata sistema idronico 41 | 7.63169 | 0.0149792 | 0 | Livello: 1 - Piano Primo | 2.96 | 2.96 | Mandata sistema idronico 41 | Isolamento - Tipo di isolamento: Default
287086 | 1 - Piano Primo | 96 | 0.0889 | 0.082804 | 80 mmø | 2.00817 | 80 mmø | 0 | 1 | 0.504708 | 0.08 | Mandata sistema idronico 40 | 7.6086 | 0.00662577 | 0 | Livello: 1 - Piano Primo | 2.96 | 2.96 | Mandata sistema idronico 40
287246 | 1 - Piano Primo | 97 | 0.0889 | 0.082804 | 80 mmø | 0.048 | 80 mmø | 0 | 1 | 0.0120637 | 0.08 | Mandata sistema idronico 40 | 7.726 | 0.00662577 |  | Livello: 1 - Piano Primo | 3.084 | 3.036 | Mandata sistema idronico 40
287327 | 1 - Piano Primo | 98 | 0.0889 | 0.082804 | 80 mmø | 0.443 | 80 mmø | 0 | 1 | 0.111338 | 0.08 | Mandata sistema idronico 40 | 7.8086 | 0.00662577 | 0 | Livello: 1 - Piano Primo | 3.16 | 3.16 | Mandata sistema idronico 40
287722 | 1 - Piano Primo | 100 | 0.0889 | 0.082804 | 80 mmø | 1.749 | 80 mmø | 0 | 1 | 0.439572 | 0.08 | Mandata sistema idronico 40 | 7.926 | 0.00662577 |  | Livello: 1 - Piano Primo | 3.236 | 4.985 | Mandata sistema idronico 40
287933 | 1 - Piano Primo | 101 | 0.168275 | 0.161468 | 150 mmø | 1.873 | 150 mmø | 0 | 2 | 0.882631 | 0.15 | Mandata sistema idronico 39 | 7.80197 | 0.00339783 | 2682.9 | Livello: 1 - Piano Primo | 3.112 | 4.985 | Mandata sistema idronico 39
288051 | 1 - Piano Primo | 102 | 0.042164 | 0.0366268 | 32 mmø | 2.096 | 132 mmø | 0.05 | 2 | 0.210713 | 0.032 | Mandata sistema idronico 41 | 7.682 | 0.0149792 | 6230.22 | Livello: 1 - Piano Primo | 2.992 | 5.088 | Mandata sistema idronico 41 | Isolamento - Tipo di isolamento: Default
288235 | 1 - Piano Primo | 103 | 0.168275 | 0.161468 | 150 mmø | 0.0316834 | 150 mmø | 0 | 2 | 0.0149305 | 0.15 | Mandata sistema idronico 39 | 7.56927 | 0.00339783 | 0 | Livello: 1 - Piano Primo | 2.96 | 2.96 | Mandata sistema idronico 39
290448 | 1 - Piano Primo | 112 | 0.168275 | 0.161468 | 150 mmø | 1.905 | 150 mmø | 0 | 2 | 0.89771 | 0.15 | Mandata sistema idronico 39 | 7.802 | 0.00339783 |  | Livello: 1 - Piano Primo | 3.112 | 5.017 | Mandata sistema idronico 39
290513 | 1 - Piano Primo | 113 | 0.0889 | 0.082804 | 80 mmø | 1.885 | 80 mmø | 0 | 1 | 0.473752 | 0.08 | Mandata sistema idronico 40 | 7.726 | 0.00662577 |  | Livello: 1 - Piano Primo | 3.036 | 4.921 | Mandata sistema idronico 40
291440 | 0 - Piano Terra | 119 | 0.0889 | 0.082804 | 80 mmø | 3.9 | 80 mmø | 0 | 1 | 0.980177 | 0.08 | Mandata sistema idronico 45 | 3.3 | 0.00662577 |  | Livello: 2 - Piano Secondo | -1.41 | -5.31
291640 | 0 - Piano Terra | 120 | 0.0889 | 0.082804 | 80 mmø | 3.9 | 80 mmø | 0 | 1 | 0.980177 | 0.08 | Mandata sistema idronico 44 | 3.3 | 0.00662577 |  | Livello: 2 - Piano Secondo | -1.41 | -5.31
291742 | 0 - Piano Terra | 122 | 0.042164 | 0.0366268 | 32 mmø | 2.8 | 32 mmø | 0 | 1 | 0.281487 | 0.032 | Mandata sistema idronico 47 | 4.4 | 0.0149792 |  | Livello: 2 - Piano Secondo | -1.41 | -4.21
291765 | 0 - Piano Terra | 123 | 0.042164 | 0.0366268 | 32 mmø | 0.6 | 32 mmø | 0 | 1 | 0.0603186 | 0.032 | Mandata sistema idronico 48 | 3.3 | 0.0149792 |  | Livello: 2 - Piano Secondo | -4.71 | -5.31
302279 | 2 - Piano Secondo | 131 | 0.042164 | 0.0366268 | 32 mmø | 0.14108 | 32 mmø | 0 | 2 | 0.014183 | 0.032 | Mandata sistema idronico 50 | 9.44169 | 0.0149792 | 0 | Livello: 2 - Piano Secondo | 0.85 | 0.85 | Mandata sistema idronico 50
302291 | 2 - Piano Secondo | 132 | 0.042164 | 0.0366268 | 32 mmø | 0.138369 | 32 mmø | 0 | 2 | 0.0139103 | 0.032 | Mandata sistema idronico 50 | 9.44169 | 0.0149792 | 0 | Livello: 2 - Piano Secondo | 0.85 | 0.85 | Mandata sistema idronico 50
302301 | 2 - Piano Secondo | 133 | 0.042164 | 0.0366268 | 32 mmø | 0.878027 | 32 mmø | 0 | 2 | 0.0882689 | 0.032 | Mandata sistema idronico 50 | 9.44169 | 0.0149792 | 0 | Livello: 2 - Piano Secondo | 0.85 | 0.85 | Mandata sistema idronico 50
302312 | 2 - Piano Secondo | 134 | 0.042164 | 0.0366268 | 32 mmø | 0.896 | 32 mmø | 0 | 2 | 0.0900757 | 0.032 | Mandata sistema idronico 50 | 9.44169 | 0.0149792 | 0 | Livello: 2 - Piano Secondo | 0.85 | 0.85 | Mandata sistema idronico 50
302323 | 2 - Piano Secondo | 135 | 0.042164 | 0.0366268 | 32 mmø | 0.936 | 32 mmø | 0 | 2 | 0.094097 | 0.032 | Mandata sistema idronico 50 | 9.44169 | 0.0149792 | 0 | Livello: 2 - Piano Secondo | 0.85 | 0.85 | Mandata sistema idronico 50
302333 | 2 - Piano Secondo | 136 | 0.042164 | 0.0366268 | 32 mmø | 1.216 | 32 mmø | 0 | 2 | 0.122246 | 0.032 | Mandata sistema idronico 50 | 9.44169 | 0.0149792 | 0 | Livello: 2 - Piano Secondo | 0.85 | 0.85 | Mandata sistema idronico 50
302348 | 2 - Piano Secondo | 137 | 0.042164 | 0.0366268 | 32 mmø | 1.39184 | 32 mmø | 0 | 2 | 0.139923 | 0.032 | Mandata sistema idronico 50 | 9.44169 | 0.0149792 | 0 | Livello: 2 - Piano Secondo | 0.85 | 0.85 | Mandata sistema idronico 50
302361 | 2 - Piano Secondo | 138 | 0.042164 | 0.0366268 | 32 mmø | 0.052 | 32 mmø | 0 | 2 | 0.00522761 | 0.032 | Mandata sistema idronico 50 | 9.44169 | 0.0149792 | 0 | Livello: 2 - Piano Secondo | 0.85 | 0.85 | Mandata sistema idronico 50
304046 | 2 - Piano Secondo | 139 | 0.042164 | 0.0366268 | 32 mmø | 0.628 | 32 mmø | 0 | 5 | 0.0631334 | 0.032 | Mandata sistema idronico 54 | 10.5917 | 0.0149792 | 0 | Livello: 2 - Piano Secondo | 2 | 2 | Mandata sistema idronico 54
304058 | 2 - Piano Secondo | 140 | 0.042164 | 0.0366268 | 32 mmø | 7.42 | 32 mmø | 0 | 6 | 0.74594 | 0.032 | Mandata sistema idronico 42 | 9.29169 | 0.0149792 | 0 | Livello: 2 - Piano Secondo | 0.7 | 0.7
304068 | 2 - Piano Secondo | 141 | 0.042164 | 0.0366268 | 32 mmø | 0.036 | 32 mmø | 0 | 4 | 0.00361911 | 0.032 | Mandata sistema idronico 51 | 9.29169 | 0.0149792 | 0 | Livello: 2 - Piano Secondo | 0.7 | 0.7 | Mandata sistema idronico 51
304080 | 2 - Piano Secondo | 142 | 0.042164 | 0.0366268 | 32 mmø | 47.6077 | 32 mmø | 0 | 4 | 4.78605 | 0.032 | Mandata sistema idronico 51 | 9.29169 | 0.0149792 | 0 | Livello: 2 - Piano Secondo | 0.7 | 0.7 | Mandata sistema idronico 51
304090 | 2 - Piano Secondo | 143 | 0.042164 | 0.0366268 | 32 mmø | 0.346 | 32 mmø | 0 | 4 | 0.0347837 | 0.032 | Mandata sistema idronico 51 | 9.29169 | 0.0149792 | 0 | Livello: 2 - Piano Secondo | 0.7 | 0.7 | Mandata sistema idronico 51
304102 | 2 - Piano Secondo | 144 | 0.042164 | 0.0366268 | 32 mmø | 6.88684 | 32 mmø | 0 | 4 | 0.69234 | 0.032 | Mandata sistema idronico 51 | 9.29169 | 0.0149792 | 0 | Livello: 2 - Piano Secondo | 0.7 | 0.7 | Mandata sistema idronico 51
304381 | 2 - Piano Secondo | 145 | 0.042164 | 0.0366268 | 32 mmø | 0.968 | 32 mmø | 0 | 4 | 0.097314 | 0.032 | Mandata sistema idronico 51 | 9.44169 | 0.0149792 | 0 | Livello: 2 - Piano Secondo | 0.85 | 0.85 | Mandata sistema idronico 51
304515 | 2 - Piano Secondo | 146 | 0.042164 | 0.0366268 | 32 mmø | 0.086 | 32 mmø | 0 | 4 | 0.00864566 | 0.032 | Mandata sistema idronico 51 | 9.342 | 0.0149792 |  | Livello: 1 - Piano Primo | 4.652 | 4.738 | Mandata sistema idronico 51
304569 | 2 - Piano Secondo | 147 | 0.042164 | 0.0366268 | 32 mmø | 1.236 | 32 mmø | 0 | 5 | 0.124256 | 0.032 | Mandata sistema idronico 54 | 9.342 | 0.0149792 |  | Livello: 1 - Piano Primo | 5.888 | 4.652 | Mandata sistema idronico 54
304686 | 2 - Piano Secondo | 148 | 0.042164 | 0.0366268 | 32 mmø | 3.16378 | 32 mmø | 0 | 2 | 0.318058 | 0.032 | Mandata sistema idronico 46 | 9.44169 | 0.0149792 | 0 | Livello: 2 - Piano Secondo | 0.85 | 0.85 | Mandata sistema idronico 46
304786 | 2 - Piano Secondo | 149 | 0.042164 | 0.0366268 | 32 mmø | 0.628 | 32 mmø | 0 | 2 | 0.0631334 | 0.032 | Mandata sistema idronico 46 | 10.4417 | 0.0149792 | 0 | Livello: 2 - Piano Secondo | 1.85 | 1.85 | Mandata sistema idronico 46
304856 | 2 - Piano Secondo | 150 | 0.042164 | 0.0366268 | 32 mmø | 0.936 | 32 mmø | 0 | 2 | 0.094097 | 0.032 | Mandata sistema idronico 46 | 9.492 | 0.0149792 |  | Livello: 1 - Piano Primo | 5.738 | 4.802 | Mandata sistema idronico 46
304937 | 2 - Piano Secondo | 151 | 0.042164 | 0.0366268 | 32 mmø | 0.818 | 32 mmø | 0 | 2 | 0.0822343 | 0.032 | Mandata sistema idronico 46 | 8.61 | 0.0149792 |  | Livello: 2 - Piano Secondo | 0.818 | 0 | Mandata sistema idronico 46
305179 | 2 - Piano Secondo | 152 | 0.042164 | 0.0366268 | 32 mmø | 0.531 | 32 mmø | 0 | 5 | 0.0533819 | 0.032 | Mandata sistema idronico 54 | 9.29169 | 0.0149792 | 0 | Livello: 2 - Piano Secondo | 0.7 | 0.7 | Mandata sistema idronico 54
305377 | 2 - Piano Secondo | 153 | 0.042164 | 0.0366268 | 32 mmø | 3.21378 | 32 mmø | 0 | 5 | 0.323085 | 0.032 | Mandata sistema idronico 54 | 9.29169 | 0.0149792 | 0 | Livello: 2 - Piano Secondo | 0.7 | 0.7 | Mandata sistema idronico 54
305785 | 2 - Piano Secondo | 154 | 0.042164 | 0.0366268 | 32 mmø | 0.236 | 32 mmø | 0 | 2 | 0.0237253 | 0.032 | Mandata sistema idronico 50 | 9.492 | 0.0149792 |  | Livello: 2 - Piano Secondo | 0.882 | 1.118 | Mandata sistema idronico 50
305830 | 2 - Piano Secondo | 155 | 0.042164 | 0.0366268 | 32 mmø | 0.216 | 32 mmø | 0 | 2 | 0.0217147 | 0.032 | Mandata sistema idronico 50 | 9.74169 | 0.0149792 | 0 | Livello: 2 - Piano Secondo | 1.15 | 1.15 | Mandata sistema idronico 50
305851 | 2 - Piano Secondo | 156 | 0.042164 | 0.0366268 | 32 mmø | 0.236 | 32 mmø | 0 | 2 | 0.0237253 | 0.032 | Mandata sistema idronico 50 | 9.492 | 0.0149792 |  | Livello: 2 - Piano Secondo | 1.118 | 0.882 | Mandata sistema idronico 50
305928 | 2 - Piano Secondo | 158 | 0.042164 | 0.0366268 | 32 mmø | 4.2 | 32 mmø | 0 | 2 | 0.42223 | 0.032 | Mandata sistema idronico 49 | 9.44169 | 0.0149792 | 0 | Livello: 2 - Piano Secondo | 0.85 | 0.85
306104 | 2 - Piano Secondo | 159 | 0.042164 | 0.0366268 | 32 mmø | 0.036 | 32 mmø | 0 | 4 | 0.00361911 | 0.032 | Mandata sistema idronico 52 | 9.29169 | 0.0149792 | 0 | Livello: 2 - Piano Secondo | 0.7 | 0.7
306169 | 2 - Piano Secondo | 160 | 0.042164 | 0.0366268 | 32 mmø | 0.14 | 32 mmø | 0 | 4 | 0.0140743 | 0.032 | Mandata sistema idronico 53 | 9.29169 | 0.0149792 | 0 | Livello: 2 - Piano Secondo | 0.7 | 0.7

# IfcFlowSegment: Tubazione:Pluviale-Tubazione (28)
Type - Altro - Categoria: Tubazione; Nome famiglia: Tubazione
Type - Dati identità - Nome del tipo: Pluviale-Tubazione
Pset_DistributionFlowElementCommon - Reference: Pluviale-Tubazione
Altro - Famiglia: Tubazione: Pluviale-Tubazione; Famiglia e tipo: Tubazione: Pluviale-Tubazione; ID tipo: Tubazione: Pluviale-Tubazione; Tipo: Tubazione: Pluviale-Tubazione
Fasi - Fase di creazione: Stato di Fatto
Isolamento - Spessore isolamento: 0 m
Meccanica - Abaco/Tipo: Tipi di abaco delle tubazioni: Abaco 40; Classificazione sistema: Mandata di sistema idronico; Materiale: Plastica; Ruvidità: 0.000774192 m; Segmento di tubazione: Plastica - Schedula 40; Tipo di connessione: Generico; Tipo di sistema: Sistema di tubazioni: Mandata sistema idronico
Meccanico - Flusso - Frizione: 0; Numero di Reynolds: 0; Velocità: 0; Caduta pressione: 0 Pa; Fattore di frizione: 0; Flusso: 0 m3/s; Flusso aggiuntivo: 0 m3/s; Stato flusso: Laminare
Vincoli - Giustificazione orizzontale: Al centro; Giustificazione verticale: Al centro
Name (Tubazione:Pluviale-Tubazione:...) | In | Contrassegno | Diametro esterno (m) | Diametro interno (m) | Dimensioni = Dimensione totale | Lunghezza (m) | Sezione | Area (m2) | Diametro (m) | Nome sistema | Quota altimetrica fondo (m) | Ruvidità relativa | Livello di riferimento | Offset (m) = Offset iniziale (m) | Offset finale (m)
219724 | 0 - Piano Terra | 3 | 0.1143 | 0.10226 | 100 mmø | 8.6 | 1 | 2.70177 | 0.1 | Mandata sistema idronico 1 | 0 | 0.00757079 | Livello: 0 - Piano Terra | 8.6 | 0
219821 | 0 - Piano Terra | 4 | 0.1143 | 0.10226 | 100 mmø | 8.61 | 1 | 2.70491 | 0.1 | Mandata sistema idronico 3 | 0 | 0.00757079 | Livello: 0 - Piano Terra | 8.61 | 0
219947 | 0 - Piano Terra | 5 | 0.1143 | 0.10226 | 100 mmø | 8.61 | 1 | 2.70491 | 0.1 | Mandata sistema idronico 4 | 0 | 0.00757079 | Livello: 0 - Piano Terra | 8.61 | 0
219969 | 0 - Piano Terra | 6 | 0.1143 | 0.10226 | 100 mmø | 8.61 | 1 | 2.70491 | 0.1 | Mandata sistema idronico 5 | 0 | 0.00757079 | Livello: 0 - Piano Terra | 8.61 | 0
219997 | 0 - Piano Terra | 7 | 0.1143 | 0.10226 | 100 mmø | 8.61 | 1 | 2.70491 | 0.1 | Mandata sistema idronico 6 | 0 | 0.00757079 | Livello: 0 - Piano Terra | 8.61 | 0
220023 | 0 - Piano Terra | 8 | 0.1143 | 0.10226 | 100 mmø | 8.61 | 1 | 2.70491 | 0.1 | Mandata sistema idronico 7 | 0 | 0.00757079 | Livello: 0 - Piano Terra | 8.61 | 0
220058 | 0 - Piano Terra | 9 | 0.1143 | 0.10226 | 100 mmø | 8.61 | 1 | 2.70491 | 0.1 | Mandata sistema idronico 8 | 0 | 0.00757079 | Livello: 0 - Piano Terra | 8.61 | 0
220079 | 0 - Piano Terra | 10 | 0.1143 | 0.10226 | 100 mmø | 8.61 | 1 | 2.70491 | 0.1 | Mandata sistema idronico 9 | 0 | 0.00757079 | Livello: 0 - Piano Terra | 8.61 | 0
220104 | 0 - Piano Terra | 11 | 0.1143 | 0.10226 | 100 mmø | 8.61 | 1 | 2.70491 | 0.1 | Mandata sistema idronico 10 | 0 | 0.00757079 | Livello: 0 - Piano Terra | 8.61 | 0
220442 | 0 - Piano Terra | 12 | 0.1143 | 0.10226 | 100 mmø | 8.61 | 1 | 2.70491 | 0.1 | Mandata sistema idronico 2 | 0 | 0.00757079 | Livello: 0 - Piano Terra | 8.61 | 0
238334 | 1 - Piano Primo | 15 | 0.1413 | 0.128194 | 125 mmø | 7.41574 | 1 | 2.91215 | 0.125 | Mandata sistema idronico 11 | 7.92646 | 0.00603923 | Livello: 0 - Piano Terra | 8.11997 | 7.99055 | Vincoli - Inclinazione: 0.0174551; Group: Mandata sistema idronico 11
238497 | 1 - Piano Primo | 16 | 0.1413 | 0.128194 | 125 mmø | 1.39631 | 1 | 0.548329 | 0.125 | Mandata sistema idronico 11 | 8.26743 | 0.00603923 | Livello: 0 - Piano Terra | 8.26743 | 9.66374 | Group: Mandata sistema idronico 11
240497 | 0 - Piano Terra | 18 | 0.1143 | 0.10226 | 100 mmø | 8.6 | 1 | 2.70177 | 0.1 | Mandata sistema idronico 12 | 0 | 0.00757079 | Livello: 0 - Piano Terra | 8.6 | 0
240543 | 0 - Piano Terra | 19 | 0.1143 | 0.10226 | 100 mmø | 8.6 | 1 | 2.70177 | 0.1 | Mandata sistema idronico 13 | 0 | 0.00757079 | Livello: 0 - Piano Terra | 8.6 | 0
240573 | 0 - Piano Terra | 20 | 0.1143 | 0.10226 | 100 mmø | 8.6 | 1 | 2.70177 | 0.1 | Mandata sistema idronico 14 | 0 | 0.00757079 | Livello: 0 - Piano Terra | 8.6 | 0
240605 | 0 - Piano Terra | 21 | 0.1143 | 0.10226 | 100 mmø | 8.6 | 1 | 2.70177 | 0.1 | Mandata sistema idronico 15 | 0 | 0.00757079 | Livello: 0 - Piano Terra | 8.6 | 0
240637 | 0 - Piano Terra | 22 | 0.1143 | 0.10226 | 100 mmø | 8.6 | 1 | 2.70177 | 0.1 | Mandata sistema idronico 16 | 0 | 0.00757079 | Livello: 0 - Piano Terra | 8.6 | 0
240691 | 0 - Piano Terra | 23 | 0.1143 | 0.10226 | 100 mmø | 8.6 | 1 | 2.70177 | 0.1 | Mandata sistema idronico 17 | 0 | 0.00757079 | Livello: 0 - Piano Terra | 8.6 | 0
240742 | 0 - Piano Terra | 24 | 0.1143 | 0.10226 | 100 mmø | 8.6 | 1 | 2.70177 | 0.1 | Mandata sistema idronico 18 | 0 | 0.00757079 | Livello: 0 - Piano Terra | 8.6 | 0
240770 | 0 - Piano Terra | 25 | 0.1143 | 0.10226 | 100 mmø | 8.6 | 1 | 2.70177 | 0.1 | Mandata sistema idronico 19 | 0 | 0.00757079 | Livello: 0 - Piano Terra | 8.6 | 0
240804 | 0 - Piano Terra | 26 | 0.1143 | 0.10226 | 100 mmø | 8.6 | 1 | 2.70177 | 0.1 | Mandata sistema idronico 20 | 0 | 0.00757079 | Livello: 0 - Piano Terra | 8.6 | 0
240930 | 0 - Piano Terra | 28 | 0.1413 | 0.128194 | 125 mmø | 8.6 | 1 | 3.37721 | 0.125 | Mandata sistema idronico 21 | 0 | 0.00603923 | Livello: 0 - Piano Terra | 8.6 | 0
242831 | 1 - Piano Primo | 30 | 0.1413 | 0.128194 | 125 mmø | 7.37547 | 2 | 2.89634 | 0.125 | Mandata sistema idronico 22 | 7.92838 | 0.00603923 | Livello: 1 - Piano Primo | 3.30247 | 3.43119 | Vincoli - Inclinazione: 0.0174551; Group: Mandata sistema idronico 22
243247 | 1 - Piano Primo | 31 | 0.1413 | 0.128194 | 125 mmø | 1.20264 | 2 | 0.472276 | 0.125 | Mandata sistema idronico 22 | 8.26856 | 0.00603923 | Livello: 1 - Piano Primo | 3.5786 | 4.78124 | Vincoli - Inclinazione: 1696.8; Group: Mandata sistema idronico 22
244200 | 1 - Piano Primo | 35 | 0.1413 | 0.128194 | 125 mmø | 0.789522 | 2 | 0.310045 | 0.125 | Mandata sistema idronico 22 | 7.91075 | 0.00603923 | Livello: 1 - Piano Primo | 3.29861 | 3.28483 | Vincoli - Inclinazione: 0.0174551; Group: Mandata sistema idronico 22
244601 | 1 - Piano Primo | 36 | 0.1413 | 0.128194 | 125 mmø | 1.32 | 2 | 0.518363 | 0.125 | Mandata sistema idronico 23 | 7.87793 | 0.00603923 | Livello: 1 - Piano Primo | 3.27506 | 3.25202 | Vincoli - Inclinazione: 0.0174551
246059 | 0 - Piano Terra | 38 | 0.1143 | 0.10226 | 100 mmø | 9.49 | 1 | 2.98137 | 0.1 | Mandata sistema idronico 24 | 0 | 0.00757079 | Livello: 0 - Piano Terra | 9.49 | 0
246180 | 0 - Piano Terra | 39 | 0.1143 | 0.10226 | 100 mmø | 9.49 | 1 | 2.98137 | 0.1 | Mandata sistema idronico 25 | 0 | 0.00757079 | Livello: 0 - Piano Terra | 9.49 | 0

# IfcFlowSegment: Tubazione:Pluviale-Tubazione Inox (13)
In: 2 - Piano Secondo
Type - Altro - Categoria: Tubazione; Nome famiglia: Tubazione
Type - Dati identità - Nome del tipo: Pluviale-Tubazione Inox
Pset_DistributionFlowElementCommon - Reference: Pluviale-Tubazione Inox
Altro - Famiglia: Tubazione: Pluviale-Tubazione Inox; Famiglia e tipo: Tubazione: Pluviale-Tubazione Inox; ID tipo: Tubazione: Pluviale-Tubazione Inox; Tipo: Tubazione: Pluviale-Tubazione Inox
Dimensioni - Diametro esterno: 0.1143 m; Diametro interno: 0.110084 m; Dimensioni: 100 mmø
Fasi - Fase di creazione: Stato di Fatto
Isolamento - Spessore isolamento: 0 m; Dimensione totale: 100 mmø
Meccanica - Sezione: 1; Tipo di sistema: Sistema di tubazioni: Mandata sistema idronico; Materiale: Acciaio inossidabile; Abaco/Tipo: Tipi di abaco delle tubazioni: 5S; Classificazione sistema: Mandata di sistema idronico; Diametro: 0.1 m; Ruvidità: 0.00054864 m; Segmento di tubazione: Acciaio inossidabile - 5S; Tipo di connessione: Generico
Meccanico - Flusso - Frizione: 0; Numero di Reynolds: 0; Velocità: 0; Fattore di frizione: 0; Stato flusso: Laminare; Caduta pressione: 0 Pa; Flusso: 0 m3/s; Flusso aggiuntivo: 0 m3/s; Ruvidità relativa: 0.00498385
Vincoli - Giustificazione orizzontale: Al centro; Giustificazione verticale: Al centro
Name (Tubazione:Pluviale-Tubazione Inox:...) | Contrassegno | Lunghezza (m) | Area (m2) | Nome sistema = Group | Quota altimetrica fondo (m) | Livello di riferimento | Offset (m) = Offset iniziale (m) | Offset finale (m) | Inclinazione
306791 | 161 | 3.02253 | 0.949554 | Mandata sistema idronico 55 | 8.77589 | Livello: 2 - Piano Secondo | 3.18841 | 0.165887
307052 | 162 | 0.05 | 0.015708 | Mandata sistema idronico 55 | 8.66211 | Livello: 2 - Piano Secondo | 0.10715 | 0.10715 | 0
307162 | 163 | 0.0462625 | 0.0145338 | Mandata sistema idronico 55 | 11.8021 | Livello: 3 - Piano Copertura | -0.09285 | -0.09285 | 0
307542 | 164 | 3.02253 | 0.949554 | Mandata sistema idronico 56 | 8.77589 | Livello: 2 - Piano Secondo | 3.18841 | 0.165887
307552 | 165 | 0.05 | 0.015708 | Mandata sistema idronico 56 | 8.66211 | Livello: 2 - Piano Secondo | 0.10715 | 0.10715 | 0
307678 | 166 | 3.02253 | 0.949554 | Mandata sistema idronico 57 | 8.77589 | Livello: 2 - Piano Secondo | 3.18841 | 0.165887
307688 | 167 | 0.05 | 0.015708 | Mandata sistema idronico 57 | 8.66211 | Livello: 2 - Piano Secondo | 0.10715 | 0.10715 | 0
307878 | 168 | 3.02253 | 0.949554 | Mandata sistema idronico 58 | 8.77589 | Livello: 2 - Piano Secondo | 3.18841 | 0.165887
307880 | 169 | 0.05 | 0.015708 | Mandata sistema idronico 58 | 8.66211 | Livello: 2 - Piano Secondo | 0.10715 | 0.10715 | 0
307882 | 170 | 0.0462625 | 0.0145338 | Mandata sistema idronico 58 | 11.8021 | Livello: 3 - Piano Copertura | -0.09285 | -0.09285 | 0
307923 | 171 | 3.02253 | 0.949554 | Mandata sistema idronico 59 | 8.77589 | Livello: 2 - Piano Secondo | 3.18841 | 0.165887
307925 | 172 | 0.05 | 0.015708 | Mandata sistema idronico 59 | 8.66211 | Livello: 2 - Piano Secondo | 0.10715 | 0.10715 | 0
307927 | 173 | 0.0462625 | 0.0145338 | Mandata sistema idronico 59 | 11.8021 | Livello: 3 - Piano Copertura | -0.09285 | -0.09285 | 0

# IfcFlowSegment: Tubazione:Riscaldamento-Tubazione (15)
Type - Altro - Categoria: Tubazione; Nome famiglia: Tubazione
Type - Dati identità - Nome del tipo: Riscaldamento-Tubazione
Pset_DistributionFlowElementCommon - Reference: Riscaldamento-Tubazione
Altro - Famiglia: Tubazione: Riscaldamento-Tubazione; Famiglia e tipo: Tubazione: Riscaldamento-Tubazione; ID tipo: Tubazione: Riscaldamento-Tubazione; Tipo: Tubazione: Riscaldamento-Tubazione
Fasi - Fase di creazione: Stato di Fatto
Meccanica - Tipo di sistema: Sistema di tubazioni: Mandata sistema idronico; Abaco/Tipo: Tipi di abaco delle tubazioni: 10S; Materiale: Acciaio inossidabile; Segmento di tubazione: Acciaio inossidabile - 10S; Classificazione sistema: Mandata di sistema idronico; Ruvidità: 0.00054864 m; Tipo di connessione: Generico
Meccanico - Flusso - Frizione: 0; Numero di Reynolds: 0; Velocità: 0; Fattore di frizione: 0; Stato flusso: Laminare; Caduta pressione: 0 Pa; Flusso: 0 m3/s; Flusso aggiuntivo: 0 m3/s
Vincoli - Giustificazione orizzontale: Al centro; Giustificazione verticale: Al centro
Name (Tubazione:Riscaldamento-Tubazione:...) | In | Contrassegno | Diametro esterno (m) | Diametro interno (m) | Dimensioni | Lunghezza (m) | Dimensione totale | Spessore isolamento (m) | Tipo di isolamento | Sezione | Area (m2) | Diametro (m) | Nome sistema | Quota altimetrica fondo (m) | Ruvidità relativa | Inclinazione | Livello di riferimento | Offset (m) = Offset iniziale (m) | Offset finale (m) | Group
250107 | 0 - Piano Terra | 57 | 0.168275 | 0.161468 | 150 mmø | 3.5 | 250 mmø | 0.05 | Default | 1 | 1.64934 | 0.15 | Mandata sistema idronico 31 | 3.21927 | 0.00339783 | 0 | Livello: 0 - Piano Terra | 3.3 | 3.3
250214 | 0 - Piano Terra | 58 | 0.168275 | 0.161468 | 150 mmø | 22.3898 | 250 mmø | 0.05 | Default | 1 | 10.5509 | 0.15 | Mandata sistema idronico 32 | 3.81927 | 0.00339783 | 0 | Livello: 0 - Piano Terra | 3.9 | 3.9 | Mandata sistema idronico 32
250471 | 0 - Piano Terra | 59 | 0.168275 | 0.161468 | 150 mmø | 1.62 | 150 mmø | 0 |  | 1 | 0.763407 | 0.15 | Mandata sistema idronico 33 | 3.21927 | 0.00339783 | 0 | Livello: 0 - Piano Terra | 3.3 | 3.3
250755 | 0 - Piano Terra | 60 | 0.168275 | 0.161468 | 150 mmø | 0.446147 | 250 mmø | 0.05 | Default | 1 | 0.210242 | 0.15 | Mandata sistema idronico 32 | 3.21927 | 0.00339783 | 0 | Livello: 0 - Piano Terra | 3.3 | 3.3 | Mandata sistema idronico 32
250828 | 0 - Piano Terra | 61 | 0.168275 | 0.161468 | 150 mmø | 1.946 | 250 mmø | 0.05 | Default | 1 | 0.917031 | 0.15 | Mandata sistema idronico 32 | 3.46927 | 0.00339783 | 0 | Livello: 0 - Piano Terra | 3.55 | 3.55 | Mandata sistema idronico 32
250948 | 0 - Piano Terra | 62 | 0.168275 | 0.161468 | 150 mmø | 0.046 | 250 mmø | 0.05 | Default | 1 | 0.021677 | 0.15 | Mandata sistema idronico 32 | 3.702 | 0.00339783 |  | Livello: 0 - Piano Terra | 3.702 | 3.748 | Mandata sistema idronico 32
251267 | 0 - Piano Terra | 63 | 0.168275 | 0.161468 | 150 mmø | 0.046 | 250 mmø | 0.05 | Default | 1 | 0.021677 | 0.15 | Mandata sistema idronico 32 | 3.702 | 0.00339783 |  | Livello: 0 - Piano Terra | 3.748 | 3.702 | Mandata sistema idronico 32
251372 | 0 - Piano Terra | 65 | 0.168275 | 0.161468 | 150 mmø | 0.296 | 250 mmø | 0.05 | Default | 1 | 0.139487 | 0.15 | Mandata sistema idronico 32 | 3.452 | 0.00339783 |  | Livello: 0 - Piano Terra | 3.452 | 3.748 | Mandata sistema idronico 32
251499 | 0 - Piano Terra | 66 | 0.168275 | 0.161468 | 150 mmø | 11.5324 | 250 mmø | 0.05 | Default | 1 | 5.4345 | 0.15 | Mandata sistema idronico 32 | 3.81927 | 0.00339783 | 0 | Livello: 0 - Piano Terra | 3.9 | 3.9 | Mandata sistema idronico 32
251529 | 0 - Piano Terra | 67 | 0.168275 | 0.161468 | 150 mmø | 0.296 | 250 mmø | 0.05 | Default | 1 | 0.139487 | 0.15 | Mandata sistema idronico 32 | 3.452 | 0.00339783 |  | Livello: 0 - Piano Terra | 3.452 | 3.748 | Mandata sistema idronico 32
251687 | 0 - Piano Terra | 68 | 0.168275 | 0.161468 | 150 mmø | 0.463862 | 250 mmø | 0.05 | Default | 1 | 0.21859 | 0.15 | Mandata sistema idronico 32 | 3.21927 | 0.00339783 | 0 | Livello: 0 - Piano Terra | 3.3 | 3.3 | Mandata sistema idronico 32
285392 | 1 - Piano Primo | 87 | 0.168275 | 0.161468 | 150 mmø | 134.603 | 150 mmø | 0 |  | 2 | 63.4303 | 0.15 | Mandata sistema idronico 39 | 7.56927 | 0.00339783 | 0 | Livello: 1 - Piano Primo | 2.96 | 2.96 | Mandata sistema idronico 39
287084 | 1 - Piano Primo | 95 | 0.168275 | 0.161468 | 150 mmø | 2.38274 | 150 mmø | 0 |  | 2 | 1.12284 | 0.15 | Mandata sistema idronico 39 | 7.56927 | 0.00339783 | 0 | Livello: 1 - Piano Primo | 2.96 | 2.96 | Mandata sistema idronico 39
289886 | 2 - Piano Secondo | 107 | 0.042164 | 0.0366268 | 32 mmø | 0.075 | 132 mmø | 0.05 | Default | 2 | 0.00753982 | 0.032 | Mandata sistema idronico 41 | 9.79169 | 0.0149792 | 0 | Livello: 2 - Piano Secondo | 1.2 | 1.2 | Mandata sistema idronico 41
291345 | 0 - Piano Terra | 116 | 0.042164 | 0.0366268 | 32 mmø | 3.9 | 32 mmø | 0 |  | 1 | 0.392071 | 0.032 | Mandata sistema idronico 43 | 3.3 | 0.0149792 |  | Livello: 2 - Piano Secondo | -1.41 | -5.31

# IfcFlowSegment: Tubazione:Teleriscaldamento-Tubazione (10)
In: 0 - Piano Terra
Type - Altro - Categoria: Tubazione; Nome famiglia: Tubazione
Type - Dati identità - Nome del tipo: Teleriscaldamento-Tubazione
Pset_DistributionFlowElementCommon - Reference: Teleriscaldamento-Tubazione
Altro - Famiglia: Tubazione: Teleriscaldamento-Tubazione; Famiglia e tipo: Tubazione: Teleriscaldamento-Tubazione; ID tipo: Tubazione: Teleriscaldamento-Tubazione; Tipo: Tubazione: Teleriscaldamento-Tubazione
Dimensioni - Diametro esterno: 0.219075 m; Diametro interno: 0.211557 m; Dimensioni: 200 mmø
Fasi - Fase di creazione: Stato di Fatto
Isolamento - Dimensione totale: 300 mmø; Spessore isolamento: 0.05 m; Tipo di isolamento: Default
Meccanica - Sezione: 1; Abaco/Tipo: Tipi di abaco delle tubazioni: 10S; Diametro: 0.2 m; Materiale: Acciaio inossidabile; Ruvidità: 0.00054864 m; Segmento di tubazione: Acciaio inossidabile - 10S; Tipo di connessione: Generico
Meccanico - Flusso - Frizione: 0; Numero di Reynolds: 0; Velocità: 0; Fattore di frizione: 0; Stato flusso: Laminare; Caduta pressione: 0 Pa; Flusso: 0 m3/s; Flusso aggiuntivo: 0 m3/s; Ruvidità relativa: 0.00259335
Vincoli - Giustificazione orizzontale: Al centro; Giustificazione verticale: Al centro; Livello di riferimento: Livello: 0 - Piano Terra
Name (Tubazione:Teleriscaldamento-Tubazione:...) | Contrassegno | Lunghezza (m) | Tipo di sistema | Area (m2) | Classificazione sistema | Nome sistema | Quota altimetrica fondo (m) | Inclinazione | Offset (m) = Offset iniziale (m) | Offset finale (m)
247706 | 46 | 0.334945 | Sistema di tubazioni: Mandata sistema idronico | 0.210452 | Mandata di sistema idronico | Mandata sistema idronico 30 | 0.394222 | 0 | 0.5 | 0.5 | Group: Mandata sistema idronico 30
247933 | 48 | 2.17 | Sistema di tubazioni: Mandata sistema idronico | 1.36345 | Mandata di sistema idronico | Mandata sistema idronico 30 | 0.703 |  | 0.703 | 2.873 | Group: Mandata sistema idronico 30
247987 | 49 | 10.5317 | Sistema di tubazioni: Mandata sistema idronico | 6.61724 | Mandata di sistema idronico | Mandata sistema idronico 30 | 2.97022 | 0 | 3.076 | 3.076 | Group: Mandata sistema idronico 30
248164 | 50 | 0.3 | Sistema di tubazioni: Mandata sistema idronico | 0.188496 | Mandata di sistema idronico | Mandata sistema idronico 27 | 2.56422 | 0 | 2.67 | 2.67
248335 | 51 | 0.297 | Sistema di tubazioni: Mandata sistema idronico | 0.186611 | Mandata di sistema idronico | Mandata sistema idronico 30 | 0 |  | 0.297 | 0 | Group: Mandata sistema idronico 30
249607 | 52 | 2.17 |  | 1.36345 | Non definito |  | 0.703 |  | 0.703 | 2.873 | Meccanico - Flusso - Unità apparecchio: 0
249610 | 53 | 0.297 | Sistema di tubazioni: Mandata sistema idronico | 0.186611 | Mandata di sistema idronico | Mandata sistema idronico 26 | 0 |  | 0.297 | 0 | Group: Mandata sistema idronico 26
249663 | 54 | 0.334945 |  | 0.210452 | Non definito |  | 0.394222 | 0 | 0.5 | 0.5 | Meccanico - Flusso - Unità apparecchio: 0
249754 | 55 | 0.3 | Sistema di tubazioni: Mandata sistema idronico | 0.188496 | Mandata di sistema idronico | Mandata sistema idronico 28 | 2.56422 | 0 | 2.67 | 2.67
249899 | 56 | 10.5317 | Sistema di tubazioni: Mandata sistema idronico | 6.61724 | Mandata di sistema idronico | Mandata sistema idronico 29 | 2.97022 | 0 | 3.076 | 3.076

# IfcFooting: Platea:Platea 20 cm (36)
In: SF_STR_0100_XY- Fondazioni (-0,40)
Material: Calcestruzzo - Calcestruzzo gettato in opera 0.2 m
Altro - Categoria: Fondazioni strutturali; Famiglia: Platea: Platea 20 cm; Famiglia e tipo: Platea: Platea 20 cm; ID tipo: Platea: Platea 20 cm; Tipo: Platea: Platea 20 cm; Nome famiglia: Platea
Dimensioni - Larghezza: 1.7 m; Quota altimetrica alla base: -0.4 m; Quota altimetrica superiore: -0.2 m; Spessore: 0.2 m
Fasi - Fase di creazione: Stato di Fatto
Strutturale - Attiva modello analitico: yes; Copriferro armatura - Altre superfici: Impostazioni copriferro armatura: Copriferro armatura 1; Strutturale: yes; Copriferro armatura - Superficie superiore: Impostazioni copriferro armatura: Copriferro armatura 1
Vincoli - Relativo a massa: no; Livello: Livello: SF_STR_0100_XY- Fondazioni (-0,40); Offset di altezza da livello: 0.2 m
Costruzione - Spessore di default: 0.2 m
Dati identità - Nome del tipo: Platea 20 cm; Nota chiave: Fo/5
Grafica - Colore del retino a dettaglio basso: 0
Materiali e finiture - Materiale strutturale: Calcestruzzo - Calcestruzzo gettato in opera
Proprietà analitiche - Ruvidità: 3; Assorbimento: 0.7
Name (Platea:Platea 20 cm:...) | Area (m2) | Lunghezza (m) | Perimetro (m) | Volume (m3)
311176 | 2.89 | 1.7 | 6.8 | 0.578
311185 | 2.89 | 1.7 | 6.8 | 0.578
311194 | 2.89 | 1.7 | 6.8 | 0.578
311203 | 2.89 | 1.7 | 6.8 | 0.578
311212 | 2.89 | 1.7 | 6.8 | 0.578
311221 | 2.89 | 1.7 | 6.8 | 0.578
311230 | 2.89 | 1.7 | 6.8 | 0.578
311239 | 2.89 | 1.7 | 6.8 | 0.578
311248 | 2.89 | 1.7 | 6.8 | 0.578
311257 | 2.635 | 1.55 | 6.5 | 0.527
311266 | 2.635 | 1.55 | 6.5 | 0.527
311275 | 2.635 | 1.55 | 6.5 | 0.527
311284 | 2.635 | 1.55 | 6.5 | 0.527
311293 | 2.635 | 1.55 | 6.5 | 0.527
311302 | 2.635 | 1.55 | 6.5 | 0.527
311311 | 2.635 | 1.55 | 6.5 | 0.527
311320 | 2.635 | 1.55 | 6.5 | 0.527
311329 | 2.635 | 1.55 | 6.5 | 0.527
311338 | 2.89 | 1.7 | 6.8 | 0.578
311347 | 2.89 | 1.7 | 6.8 | 0.578
311356 | 2.89 | 1.7 | 6.8 | 0.578
311365 | 2.89 | 1.7 | 6.8 | 0.578
311374 | 2.89 | 1.7 | 6.8 | 0.578
311383 | 2.89 | 1.7 | 6.8 | 0.578
311392 | 2.89 | 1.7 | 6.8 | 0.578
311401 | 2.89 | 1.7 | 6.8 | 0.578
311410 | 2.89 | 1.7 | 6.8 | 0.578
311419 | 2.635 | 1.55 | 6.5 | 0.527
311428 | 2.635 | 1.55 | 6.5 | 0.527
311437 | 2.635 | 1.55 | 6.5 | 0.527
311446 | 2.635 | 1.55 | 6.5 | 0.527
311455 | 2.635 | 1.55 | 6.5 | 0.527
311464 | 2.635 | 1.55 | 6.5 | 0.527
311473 | 2.635 | 1.55 | 6.5 | 0.527
311482 | 2.635 | 1.55 | 6.5 | 0.527
311491 | 2.635 | 1.55 | 6.5 | 0.527

# IfcFooting: Platea:Platea 40 cm (3)
In: SF_STR_0100_XY- Fondazioni (-0,40)
Material: Calcestruzzo - Calcestruzzo gettato in opera 0.4 m
Altro - Categoria: Fondazioni strutturali; Famiglia: Platea: Platea 40 cm; Famiglia e tipo: Platea: Platea 40 cm; ID tipo: Platea: Platea 40 cm; Tipo: Platea: Platea 40 cm; Nome famiglia: Platea
Dimensioni - Spessore: 0.4 m
Fasi - Fase di creazione: Stato di Fatto
Strutturale - Attiva modello analitico: yes; Copriferro armatura - Altre superfici: Impostazioni copriferro armatura: Copriferro armatura 1; Strutturale: yes; Copriferro armatura - Superficie inferiore: Impostazioni copriferro armatura: Copriferro armatura 1; Copriferro armatura - Superficie superiore: Impostazioni copriferro armatura: Copriferro armatura 1
Vincoli - Relativo a massa: no; Livello: Livello: SF_STR_0100_XY- Fondazioni (-0,40)
Costruzione - Spessore di default: 0.4 m
Dati identità - Nome del tipo: Platea 40 cm; Nota chiave: Fo/5
Grafica - Colore del retino a dettaglio basso: 0
Materiali e finiture - Materiale strutturale: Calcestruzzo - Calcestruzzo gettato in opera
Proprietà analitiche - Ruvidità: 3; Assorbimento: 0.7
Name (Platea:Platea 40 cm:...) | Area (m2) | Larghezza (m) | Lunghezza (m) | Perimetro (m) | Quota altimetrica alla base (m) | Quota altimetrica superiore (m) | Volume (m3) | Offset di altezza da livello (m)
311132 | 964.156 | 20.2002 | 47.73 | 135.86 | -0.8 | -0.4 | 385.663 | 0
311154 | 964.159 | 20.2002 | 47.7301 | 135.861 | -0.8 | -0.4 | 385.664 | 0
315058 | 58.522 | 10.09 | 5.8 | 31.78 | -1.1 | -0.7 | 23.4088 | -0.3

# IfcFooting: Platea:Platea 60 cm (5)
In: SF_STR_0100_XY- Fondazioni (-0,40)
Material: Calcestruzzo - Calcestruzzo gettato in opera 0.6 m
Altro - Categoria: Fondazioni strutturali; Famiglia: Platea: Platea 60 cm; Famiglia e tipo: Platea: Platea 60 cm; ID tipo: Platea: Platea 60 cm; Tipo: Platea: Platea 60 cm; Nome famiglia: Platea
Dimensioni - Spessore: 0.6 m
Fasi - Fase di creazione: Stato di Fatto
Strutturale - Attiva modello analitico: yes; Copriferro armatura - Altre superfici: Impostazioni copriferro armatura: Copriferro armatura 1; Strutturale: yes; Copriferro armatura - Superficie inferiore: Impostazioni copriferro armatura: Copriferro armatura 1; Copriferro armatura - Superficie superiore: Impostazioni copriferro armatura: Copriferro armatura 1
Vincoli - Relativo a massa: no; Livello: Livello: SF_STR_0100_XY- Fondazioni (-0,40)
Costruzione - Spessore di default: 0.6 m
Dati identità - Nome del tipo: Platea 60 cm; Nota chiave: Fo/5
Grafica - Colore del retino a dettaglio basso: 0
Materiali e finiture - Materiale strutturale: Calcestruzzo - Calcestruzzo gettato in opera
Proprietà analitiche - Ruvidità: 3; Assorbimento: 0.7
Name (Platea:Platea 60 cm:...) | Area (m2) | Larghezza (m) | Lunghezza (m) | Perimetro (m) | Quota altimetrica alla base (m) | Quota altimetrica superiore (m) | Volume (m3) | Offset di altezza da livello (m)
311118 | 425.667 | 24.54 | 19.5 | 78.6916 | -1 | -0.4 | 255.398 | 0
311141 | 410.6 | 20.1501 | 23.98 | 113.96 | -1 | -0.4 | 246.36 | 0
311163 | 425.757 | 19.5044 | 24.54 | 78.6988 | -1 | -0.4 | 255.453 | 0
313132 | 60.54 | 6 | 10.09 | 32.18 | -4.7 | -4.1 | 36.324 | -3.7
313267 | 74.821 | 8.69996 | 8.60016 | 34.6002 | -4.7 | -4.1 | 44.8926 | -3.7

# IfcOpeningElement: Opening (223)
Name | In
Muro di base:Setto CA - 30 cm:204045 | 0 - Piano Terra | Altro - Categoria: Modelli generici; Famiglia: Apertura-Porta: 100 x 225 mm; Famiglia e tipo: Apertura-Porta: 100 x 225 mm; Id host: Muro di base: Setto CA - 30 cm; ID tipo: Apertura-Porta: 100 x 225 mm; Tipo: Apertura-Porta: 100 x 225 mm; Nome famiglia: Apertura-Porta; Fasi - Fase di creazione: Stato di Fatto; Vincoli - Livello: Livello: 0 - Piano Terra; Prospetto: 0 m; Dati identità - Nome del tipo: 100 x 225 mm; Dimensioni - Altezza approssimativa: 2.25 m; Larghezza approssimativa: 1 m
Muro di base:Setto CA - 30 cm:204049 | 0 - Piano Terra | Altro - Categoria: Modelli generici; Famiglia: Apertura-Porta: 100 x 220 mm; Famiglia e tipo: Apertura-Porta: 100 x 220 mm; Id host: Muro di base: Setto CA - 30 cm; ID tipo: Apertura-Porta: 100 x 220 mm; Tipo: Apertura-Porta: 100 x 220 mm; Nome famiglia: Apertura-Porta; Fasi - Fase di creazione: Stato di Fatto; Vincoli - Livello: Livello: 0 - Piano Terra; Prospetto: 0 m; Dati identità - Nome del tipo: 100 x 220 mm; Dimensioni - Altezza approssimativa: 2.2 m; Larghezza approssimativa: 1 m
Muro di base:Setto CA rivestito int - 31 cm:204039 | 0 - Piano Terra
Muro di base:Setto CA rivestito est 45:204051 | 0 - Piano Terra | Altro - Categoria: Modelli generici; Famiglia: Apertura-Porta: 210 x 380 mm; Famiglia e tipo: Apertura-Porta: 210 x 380 mm; Id host: Muro di base: Setto CA rivestito est 45; ID tipo: Apertura-Porta: 210 x 380 mm; Tipo: Apertura-Porta: 210 x 380 mm; Nome famiglia: Apertura-Porta; Fasi - Fase di creazione: Stato di Fatto; Vincoli - Livello: Livello: 0 - Piano Terra; Prospetto: 0 m; Dati identità - Nome del tipo: 210 x 380 mm; Dimensioni - Altezza approssimativa: 3.8 m; Larghezza approssimativa: 2.1 m
Muro di base:Setto CA rivestito est 45:204051 | 0 - Piano Terra | Altro - Categoria: Modelli generici; Famiglia: Apertura-Porta: 210 x 380 mm; Famiglia e tipo: Apertura-Porta: 210 x 380 mm; Id host: Muro di base: Setto CA rivestito est 45; ID tipo: Apertura-Porta: 210 x 380 mm; Tipo: Apertura-Porta: 210 x 380 mm; Nome famiglia: Apertura-Porta; Fasi - Fase di creazione: Stato di Fatto; Vincoli - Livello: Livello: 1 - Piano Primo; Prospetto: -0.21 m; Dati identità - Nome del tipo: 210 x 380 mm; Dimensioni - Altezza approssimativa: 3.8 m; Larghezza approssimativa: 2.1 m
Pavimento:In opera Cementizio - 40 cm:204105:2 | 2 - Piano Secondo
Pavimento:In opera Cementizio - 40 cm:204105:3 | 2 - Piano Secondo
Pavimento:In opera Cementizio - 40 cm:204105:4 | 2 - Piano Secondo
Pavimento:In opera Cementizio - 40 cm:204105:5 | 2 - Piano Secondo
Pavimento:In opera Cementizio - 40 cm:204105:6 | 2 - Piano Secondo
Pavimento:In opera Cementizio - 40 cm:204105:7 | 2 - Piano Secondo
Muro di base:Setto CA rivestito int-est 47 cm:204106 | 2 - Piano Secondo | Altro - Categoria: Modelli generici; Famiglia: Apertura-Porta: 180 x 247 mm; Famiglia e tipo: Apertura-Porta: 180 x 247 mm; Id host: Muro di base: Setto CA rivestito int-est 47 cm; ID tipo: Apertura-Porta: 180 x 247 mm; Tipo: Apertura-Porta: 180 x 247 mm; Nome famiglia: Apertura-Porta; Fasi - Fase di creazione: Stato di Fatto; Vincoli - Livello: Livello: 2 - Piano Secondo; Prospetto: 0.2 m; Dati identità - Nome del tipo: 180 x 247 mm; Dimensioni - Altezza approssimativa: 2.47 m; Larghezza approssimativa: 1.8 m
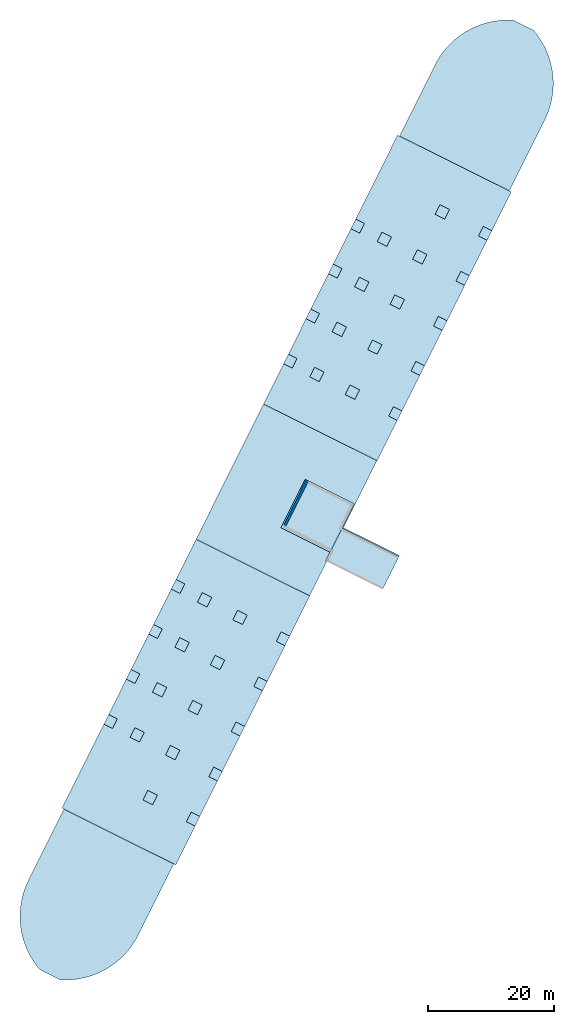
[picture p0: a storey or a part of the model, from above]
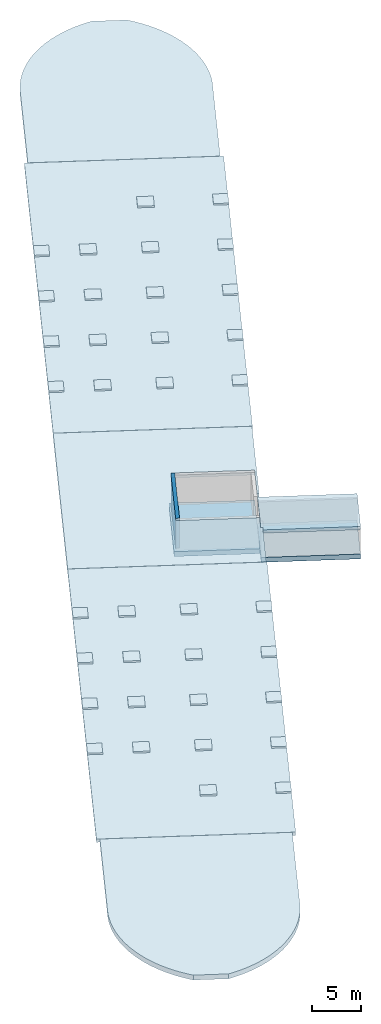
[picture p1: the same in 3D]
Properties of the parts of a building model (IFC2X3), part 4 of 7

# IfcOpeningElement: Opening (223)
Name | In
Muro di base:Setto CA rivestito int - 31 cm:204112 | 2 - Piano Secondo | Altro - Categoria: Modelli generici; Famiglia: Apertura-Porta: 160 x 215 mm; Famiglia e tipo: Apertura-Porta: 160 x 215 mm; Id host: Muro di base: Setto CA rivestito int - 31 cm; ID tipo: Apertura-Porta: 160 x 215 mm; Tipo: Apertura-Porta: 160 x 215 mm; Nome famiglia: Apertura-Porta; Fasi - Fase di creazione: Stato di Fatto; Vincoli - Livello: Livello: 2 - Piano Secondo; Prospetto: 0 m; Dati identità - Nome del tipo: 160 x 215 mm; Dimensioni - Altezza approssimativa: 2.15 m; Larghezza approssimativa: 1.6 m
Muro di base:Setto CA rivestito int-est 47 cm:204114 | 2 - Piano Secondo | Altro - Categoria: Modelli generici; Famiglia: Apertura-Porta: 180 x 247 mm; Famiglia e tipo: Apertura-Porta: 180 x 247 mm; Id host: Muro di base: Setto CA rivestito int-est 47 cm; ID tipo: Apertura-Porta: 180 x 247 mm; Tipo: Apertura-Porta: 180 x 247 mm; Nome famiglia: Apertura-Porta; Fasi - Fase di creazione: Stato di Fatto; Vincoli - Livello: Livello: 2 - Piano Secondo; Prospetto: 0.2 m; Dati identità - Nome del tipo: 180 x 247 mm; Dimensioni - Altezza approssimativa: 2.47 m; Larghezza approssimativa: 1.8 m
Muro di base:Setto CA rivestito int - 31 cm:204120 | 2 - Piano Secondo | Altro - Categoria: Modelli generici; Famiglia: Apertura-Porta: 160 x 215 mm; Famiglia e tipo: Apertura-Porta: 160 x 215 mm; Id host: Muro di base: Setto CA rivestito int - 31 cm; ID tipo: Apertura-Porta: 160 x 215 mm; Tipo: Apertura-Porta: 160 x 215 mm; Nome famiglia: Apertura-Porta; Fasi - Fase di creazione: Stato di Fatto; Vincoli - Livello: Livello: 2 - Piano Secondo; Prospetto: 0 m; Dati identità - Nome del tipo: 160 x 215 mm; Dimensioni - Altezza approssimativa: 2.15 m; Larghezza approssimativa: 1.6 m
19 x Muro di base:Blocchetti - 20 cm:167829 | 0 - Piano Terra
Muro di base:Pannello coibentato - 6 cm:204133 | 0 - Piano Terra | Altro - Categoria: Modelli generici; Famiglia: Apertura-Porta: 120 x 215 mm; Famiglia e tipo: Apertura-Porta: 120 x 215 mm; Id host: Muro di base: Pannello coibentato - 6 cm; ID tipo: Apertura-Porta: 120 x 215 mm; Tipo: Apertura-Porta: 120 x 215 mm; Nome famiglia: Apertura-Porta; Fasi - Fase di creazione: Stato di Fatto; Vincoli - Livello: Livello: 0 - Piano Terra; Prospetto: 0 m; Dati identità - Nome del tipo: 120 x 215 mm; Dimensioni - Altezza approssimativa: 2.15 m; Larghezza approssimativa: 1.2 m
5 x Muro di base:Pannello coibentato - 6 cm:167830 | 0 - Piano Terra
Muro di base:Blocchetti - 25 cm:204137 | 0 - Piano Terra | Altro - Categoria: Modelli generici; Famiglia: Apertura-Porta: 212 x 310 mm; Famiglia e tipo: Apertura-Porta: 212 x 310 mm; Id host: Muro di base: Blocchetti - 25 cm; ID tipo: Apertura-Porta: 212 x 310 mm; Tipo: Apertura-Porta: 212 x 310 mm; Nome famiglia: Apertura-Porta; Fasi - Fase di creazione: Stato di Fatto; Vincoli - Livello: Livello: 0 - Piano Terra; Prospetto: 0 m; Dati identità - Nome del tipo: 212 x 310 mm; Dimensioni - Altezza approssimativa: 3.1 m; Larghezza approssimativa: 2.12 m
Muro di base:Blocchetti - 25 cm:204137 | 0 - Piano Terra | Altro - Categoria: Modelli generici; Famiglia: Apertura-Porta: 102 x 246 mm; Famiglia e tipo: Apertura-Porta: 102 x 246 mm; Id host: Muro di base: Blocchetti - 25 cm; ID tipo: Apertura-Porta: 102 x 246 mm; Tipo: Apertura-Porta: 102 x 246 mm; Nome famiglia: Apertura-Porta; Fasi - Fase di creazione: Stato di Fatto; Vincoli - Livello: Livello: 0 - Piano Terra; Prospetto: 0 m; Dati identità - Nome del tipo: 102 x 246 mm; Dimensioni - Altezza approssimativa: 2.46 m; Larghezza approssimativa: 1.02 m
15 x Muro di base:Blocchetti - 25 cm:167832 | 0 - Piano Terra
Muro di base:Blocchetti - 25 cm:204138 | 0 - Piano Terra | Altro - Categoria: Modelli generici; Famiglia: Apertura-Porta: 208 x 325 mm; Famiglia e tipo: Apertura-Porta: 208 x 325 mm; Id host: Muro di base: Blocchetti - 25 cm; ID tipo: Apertura-Porta: 208 x 325 mm; Tipo: Apertura-Porta: 208 x 325 mm; Nome famiglia: Apertura-Porta; Fasi - Fase di creazione: Stato di Fatto; Vincoli - Livello: Livello: 0 - Piano Terra; Prospetto: 0 m; Dati identità - Nome del tipo: 208 x 325 mm; Dimensioni - Altezza approssimativa: 3.25 m; Larghezza approssimativa: 2.08 m
Muro di base:Blocchetti - 25 cm:204138 | 0 - Piano Terra | Altro - Categoria: Modelli generici; Famiglia: Apertura-Porta: 310 x 325 mm; Famiglia e tipo: Apertura-Porta: 310 x 325 mm; Id host: Muro di base: Blocchetti - 25 cm; ID tipo: Apertura-Porta: 310 x 325 mm; Tipo: Apertura-Porta: 310 x 325 mm; Nome famiglia: Apertura-Porta; Fasi - Fase di creazione: Stato di Fatto; Vincoli - Livello: Livello: 0 - Piano Terra; Prospetto: 0 m; Dati identità - Nome del tipo: 310 x 325 mm; Dimensioni - Altezza approssimativa: 3.25 m; Larghezza approssimativa: 3.1 m
2 x Muro di base:Blocchetti - 25 cm:204139 | 0 - Piano Terra | Altro - Categoria: Modelli generici; Famiglia: Apertura-Porta: 208 x 325 mm; Famiglia e tipo: Apertura-Porta: 208 x 325 mm; Id host: Muro di base: Blocchetti - 25 cm; ID tipo: Apertura-Porta: 208 x 325 mm; Tipo: Apertura-Porta: 208 x 325 mm; Nome famiglia: Apertura-Porta; Fasi - Fase di creazione: Stato di Fatto; Vincoli - Livello: Livello: 0 - Piano Terra; Prospetto: 0 m; Dati identità - Nome del tipo: 208 x 325 mm; Dimensioni - Altezza approssimativa: 3.25 m; Larghezza approssimativa: 2.08 m
Muro di base:Blocchetti - 25 cm:204140 | 0 - Piano Terra | Altro - Categoria: Modelli generici; Famiglia: Apertura-Porta: 260 x 325 mm; Famiglia e tipo: Apertura-Porta: 260 x 325 mm; Id host: Muro di base: Blocchetti - 25 cm; ID tipo: Apertura-Porta: 260 x 325 mm; Tipo: Apertura-Porta: 260 x 325 mm; Nome famiglia: Apertura-Porta; Fasi - Fase di creazione: Stato di Fatto; Vincoli - Livello: Livello: 0 - Piano Terra; Prospetto: 0 m; Dati identità - Nome del tipo: 260 x 325 mm; Dimensioni - Altezza approssimativa: 2.35 m; Larghezza approssimativa: 2.6 m
Muro di base:Blocchetti - 25 cm:204141 | 0 - Piano Terra | Altro - Categoria: Apertura rettangolare su muro diritto; Fasi - Fase di creazione: Stato di Fatto; Vincoli - Vincolo di base: Livello: 0 - Piano Terra; Vincolo parte superiore: Livello: 1 - Piano Primo; Altezza non collegata: 2.89793 m; Offset base: 0.17145 m; Offset superiore: -1.62062 m
Muro di base:Blocchetti - 25 cm:204142 | 0 - Piano Terra | Altro - Categoria: Apertura rettangolare su muro diritto; Fasi - Fase di creazione: Stato di Fatto; Vincoli - Vincolo di base: Livello: 0 - Piano Terra; Vincolo parte superiore: Livello: 1 - Piano Primo; Altezza non collegata: 1.02 m; Offset base: 2.04 m; Offset superiore: -1.63 m
Muro di base:Blocchetti - 25 cm:204142 | 0 - Piano Terra | Altro - Categoria: Modelli generici; Famiglia: Apertura-Porta: 102 x 246 mm; Famiglia e tipo: Apertura-Porta: 102 x 246 mm; Id host: Muro di base: Blocchetti - 25 cm; ID tipo: Apertura-Porta: 102 x 246 mm; Tipo: Apertura-Porta: 102 x 246 mm; Nome famiglia: Apertura-Porta; Fasi - Fase di creazione: Stato di Fatto; Vincoli - Livello: Livello: 0 - Piano Terra; Prospetto: 0 m; Dati identità - Nome del tipo: 102 x 246 mm; Dimensioni - Altezza approssimativa: 2.46 m; Larghezza approssimativa: 1.02 m
Muro di base:Blocchetti - 25 cm:204142 | 0 - Piano Terra | Altro - Categoria: Modelli generici; Famiglia: Apertura-Porta: 100 x 225 mm; Famiglia e tipo: Apertura-Porta: 100 x 225 mm; Id host: Muro di base: Blocchetti - 25 cm; ID tipo: Apertura-Porta: 100 x 225 mm; Tipo: Apertura-Porta: 100 x 225 mm; Nome famiglia: Apertura-Porta; Fasi - Fase di creazione: Stato di Fatto; Vincoli - Livello: Livello: 0 - Piano Terra; Prospetto: 0 m; Dati identità - Nome del tipo: 100 x 225 mm; Dimensioni - Altezza approssimativa: 2.25 m; Larghezza approssimativa: 1 m
Muro di base:Blocchetti - 25 cm:204142 | 0 - Piano Terra | Altro - Categoria: Modelli generici; Famiglia: Apertura-Porta: 177 x 194 mm bis; Famiglia e tipo: Apertura-Porta: 177 x 194 mm bis; Id host: Muro di base: Blocchetti - 25 cm; ID tipo: Apertura-Porta: 177 x 194 mm bis; Tipo: Apertura-Porta: 177 x 194 mm bis; Nome famiglia: Apertura-Porta; Fasi - Fase di creazione: Stato di Fatto; Vincoli - Livello: Livello: 0 - Piano Terra; Prospetto: 0.1 m; Dati identità - Nome del tipo: 177 x 194 mm bis; Dimensioni - Altezza approssimativa: 1.94 m; Larghezza approssimativa: 1.77 m
Muro di base:Blocchetti - 25 cm:204142 | 0 - Piano Terra | Altro - Categoria: Modelli generici; Famiglia: Apertura-Finestra-Quadrata: 100 x 107 mm; Famiglia e tipo: Apertura-Finestra-Quadrata: 100 x 107 mm; Id host: Muro di base: Blocchetti - 25 cm; ID tipo: Apertura-Finestra-Quadrata: 100 x 107 mm; Tipo: Apertura-Finestra-Quadrata: 100 x 107 mm; Nome famiglia: Apertura-Finestra-Quadrata; Fasi - Fase di creazione: Stato di Fatto; Vincoli - Livello: Livello: 0 - Piano Terra; Prospetto: 2.44 m; Dati identità - Nome del tipo: 100 x 107 mm; Dimensioni - Altezza approssimativa: 1.07 m; Larghezza approssimativa: 1 m; Altezza davanzale: 2.44 m
Muro di base:Blocchetti - 20 cm:204150 | 0 - Piano Terra | Altro - Categoria: Modelli generici; Famiglia: Apertura-Porta: 312 x 200 mm; Famiglia e tipo: Apertura-Porta: 312 x 200 mm; Id host: Muro di base: Blocchetti - 20 cm; ID tipo: Apertura-Porta: 312 x 200 mm; Tipo: Apertura-Porta: 312 x 200 mm; Nome famiglia: Apertura-Porta; Fasi - Fase di creazione: Stato di Fatto; Vincoli - Livello: Livello: 0 - Piano Terra; Prospetto: 0 m; Dati identità - Nome del tipo: 312 x 200 mm; Dimensioni - Altezza approssimativa: 3.2 m; Larghezza approssimativa: 2 m
Muro di base:Blocchetti - 20 cm:204157 | 0 - Piano Terra | Altro - Categoria: Modelli generici; Famiglia: Apertura-Porta: 200 x 220 mm; Famiglia e tipo: Apertura-Porta: 200 x 220 mm; Id host: Muro di base: Blocchetti - 20 cm; ID tipo: Apertura-Porta: 200 x 220 mm; Tipo: Apertura-Porta: 200 x 220 mm; Nome famiglia: Apertura-Porta; Fasi - Fase di creazione: Stato di Fatto; Vincoli - Livello: Livello: 0 - Piano Terra; Prospetto: 0 m; Dati identità - Nome del tipo: 200 x 220 mm; Dimensioni - Altezza approssimativa: 2.2 m; Larghezza approssimativa: 2 m
Muro di base:Blocchetti - 20 cm:204157 | 0 - Piano Terra | Altro - Categoria: Modelli generici; Famiglia: Apertura-Porta: 210 x 230 mm; Famiglia e tipo: Apertura-Porta: 210 x 230 mm; Id host: Muro di base: Blocchetti - 20 cm; ID tipo: Apertura-Porta: 210 x 230 mm; Tipo: Apertura-Porta: 210 x 230 mm; Nome famiglia: Apertura-Porta; Fasi - Fase di creazione: Stato di Fatto; Vincoli - Livello: Livello: 0 - Piano Terra; Prospetto: 0 m; Dati identità - Nome del tipo: 210 x 230 mm; Dimensioni - Altezza approssimativa: 2.3 m; Larghezza approssimativa: 2.1 m
Muro di base:Blocchetti - 20 cm:204160 | 0 - Piano Terra | Altro - Categoria: Modelli generici; Famiglia: Apertura-Porta: 130 x 220 mm; Famiglia e tipo: Apertura-Porta: 130 x 220 mm; Id host: Muro di base: Blocchetti - 20 cm; ID tipo: Apertura-Porta: 130 x 220 mm; Tipo: Apertura-Porta: 130 x 220 mm; Nome famiglia: Apertura-Porta; Fasi - Fase di creazione: Stato di Fatto; Vincoli - Livello: Livello: 0 - Piano Terra; Prospetto: 0 m; Dati identità - Nome del tipo: 130 x 220 mm; Dimensioni - Altezza approssimativa: 2.2 m; Larghezza approssimativa: 1.3 m
Muro di base:Rivestimento 15 cm:204162 | 0 - Piano Terra | Altro - Categoria: Apertura rettangolare su muro diritto; Fasi - Fase di creazione: Stato di Fatto; Vincoli - Vincolo di base: Livello: 0 - Piano Terra; Vincolo parte superiore: Livello: 1 - Piano Primo; Altezza non collegata: 0.09 m; Offset base: 0 m; Offset superiore: -4.6 m
Muro di base:Rivestimento 15 cm:204162 | 0 - Piano Terra | Altro - Categoria: Modelli generici; Famiglia: Apertura-Porta: 275 x 313 mm; Famiglia e tipo: Apertura-Porta: 275 x 313 mm; Id host: Muro di base: Rivestimento 15 cm; ID tipo: Apertura-Porta: 275 x 313 mm; Tipo: Apertura-Porta: 275 x 313 mm; Nome famiglia: Apertura-Porta; Fasi - Fase di creazione: Stato di Fatto; Vincoli - Livello: Livello: 0 - Piano Terra; Prospetto: 0.09 m; Dati identità - Nome del tipo: 275 x 313 mm; Dimensioni - Altezza approssimativa: 3.13 m; Larghezza approssimativa: 2.75 m
Muro di base:Setto CA rivestito int - 31 cm:204184 | 1 - Piano Primo | Altro - Categoria: Modelli generici; Famiglia: Apertura-Porta: 160 x 215 mm; Famiglia e tipo: Apertura-Porta: 160 x 215 mm; Id host: Muro di base: Setto CA rivestito int - 31 cm; ID tipo: Apertura-Porta: 160 x 215 mm; Tipo: Apertura-Porta: 160 x 215 mm; Nome famiglia: Apertura-Porta; Fasi - Fase di creazione: Stato di Fatto; Vincoli - Livello: Livello: 1 - Piano Primo; Prospetto: 0 m; Dati identità - Nome del tipo: 160 x 215 mm; Dimensioni - Altezza approssimativa: 2.15 m; Larghezza approssimativa: 1.6 m
Muro di base:Setto CA rivestito int - 31 cm:204190 | 1 - Piano Primo | Altro - Categoria: Modelli generici; Famiglia: Apertura-Porta: 160 x 215 mm; Famiglia e tipo: Apertura-Porta: 160 x 215 mm; Id host: Muro di base: Setto CA rivestito int - 31 cm; ID tipo: Apertura-Porta: 160 x 215 mm; Tipo: Apertura-Porta: 160 x 215 mm; Nome famiglia: Apertura-Porta; Fasi - Fase di creazione: Stato di Fatto; Vincoli - Livello: Livello: 1 - Piano Primo; Prospetto: 0 m; Dati identità - Nome del tipo: 160 x 215 mm; Dimensioni - Altezza approssimativa: 2.15 m; Larghezza approssimativa: 1.6 m
Muro di base:Setto CA rivestito int-est 47 cm:204192 | 1 - Piano Primo | Altro - Categoria: Modelli generici; Famiglia: Apertura-Porta: 230 x 335 mm; Famiglia e tipo: Apertura-Porta: 230 x 335 mm; Id host: Muro di base: Setto CA rivestito int-est 47 cm; ID tipo: Apertura-Porta: 230 x 335 mm; Tipo: Apertura-Porta: 230 x 335 mm; Nome famiglia: Apertura-Porta; Fasi - Fase di creazione: Stato di Fatto; Vincoli - Livello: Livello: 1 - Piano Primo; Prospetto: 0.16 m; Dati identità - Nome del tipo: 230 x 335 mm; Dimensioni - Altezza approssimativa: 3.35 m; Larghezza approssimativa: 2.3 m
Muro di base:Setto CA rivestito int-est 47 cm:204194 | 1 - Piano Primo | Altro - Categoria: Modelli generici; Famiglia: Apertura-Porta: 180 x 335 mm; Famiglia e tipo: Apertura-Porta: 180 x 335 mm; Id host: Muro di base: Setto CA rivestito int-est 47 cm; ID tipo: Apertura-Porta: 180 x 335 mm; Tipo: Apertura-Porta: 180 x 335 mm; Nome famiglia: Apertura-Porta; Fasi - Fase di creazione: Stato di Fatto; Vincoli - Livello: Livello: 1 - Piano Primo; Prospetto: 0.16 m; Dati identità - Nome del tipo: 180 x 335 mm; Dimensioni - Altezza approssimativa: 3.35 m; Larghezza approssimativa: 1.8 m
Muro di base:Setto CA rivestito est 45:204202 | 1 - Piano Primo | Altro - Categoria: Modelli generici; Famiglia: Apertura-Porta: 210 x 380 mm; Famiglia e tipo: Apertura-Porta: 210 x 380 mm; Id host: Muro di base: Setto CA rivestito est 45; ID tipo: Apertura-Porta: 210 x 380 mm; Tipo: Apertura-Porta: 210 x 380 mm; Nome famiglia: Apertura-Porta; Fasi - Fase di creazione: Stato di Fatto; Vincoli - Livello: Livello: 1 - Piano Primo; Prospetto: -0.21 m; Dati identità - Nome del tipo: 210 x 380 mm; Dimensioni - Altezza approssimativa: 3.8 m; Larghezza approssimativa: 2.1 m
Muro di base:Setto CA rivestito est 45:204212 | 1 - Piano Primo | Altro - Categoria: Modelli generici; Famiglia: Apertura-Porta: 210 x 380 mm; Famiglia e tipo: Apertura-Porta: 210 x 380 mm; Id host: Muro di base: Setto CA rivestito est 45; ID tipo: Apertura-Porta: 210 x 380 mm; Tipo: Apertura-Porta: 210 x 380 mm; Nome famiglia: Apertura-Porta; Fasi - Fase di creazione: Stato di Fatto; Vincoli - Livello: Livello: 1 - Piano Primo; Prospetto: -0.21 m; Dati identità - Nome del tipo: 210 x 380 mm; Dimensioni - Altezza approssimativa: 3.8 m; Larghezza approssimativa: 2.1 m
Muro di base:Pannelli Pref - 17 cm:204243:1 | 1 - Piano Primo
Muro di base:Setto CA rivestito int - 31 cm:204248 | 2 - Piano Secondo | Altro - Categoria: Modelli generici; Famiglia: Apertura-Porta: 160 x 215 mm; Famiglia e tipo: Apertura-Porta: 160 x 215 mm; Id host: Muro di base: Setto CA rivestito int - 31 cm; ID tipo: Apertura-Porta: 160 x 215 mm; Tipo: Apertura-Porta: 160 x 215 mm; Nome famiglia: Apertura-Porta; Fasi - Fase di creazione: Stato di Fatto; Vincoli - Livello: Livello: 2 - Piano Secondo; Prospetto: 0 m; Dati identità - Nome del tipo: 160 x 215 mm; Dimensioni - Altezza approssimativa: 2.15 m; Larghezza approssimativa: 1.6 m
Muro di base:Setto CA rivestito int-est 47 cm:204250 | 2 - Piano Secondo | Altro - Categoria: Modelli generici; Famiglia: Apertura-Porta: 230 x 247 mm; Famiglia e tipo: Apertura-Porta: 230 x 247 mm; Id host: Muro di base: Setto CA rivestito int-est 47 cm; ID tipo: Apertura-Porta: 230 x 247 mm; Tipo: Apertura-Porta: 230 x 247 mm; Nome famiglia: Apertura-Porta; Fasi - Fase di creazione: Stato di Fatto; Vincoli - Livello: Livello: 2 - Piano Secondo; Prospetto: 0.2 m; Dati identità - Nome del tipo: 230 x 247 mm; Dimensioni - Altezza approssimativa: 2.47 m; Larghezza approssimativa: 2.3 m
Pavimento:Predal Cementizio - 40 cm:204366:2 | 2 - Piano Secondo
Pavimento:Predal Cementizio - 40 cm:204366:3 | 2 - Piano Secondo
Pavimento:Predal Cementizio - 40 cm:204366:4 | 2 - Piano Secondo
Pavimento:Predal Cementizio - 40 cm:204366:5 | 2 - Piano Secondo
Pavimento:Predal Cementizio - 40 cm:204366:6 | 2 - Piano Secondo
Pavimento:Predal Cementizio - 40 cm:204366:7 | 2 - Piano Secondo
Pavimento:Predal Cementizio - 40 cm:204366:8 | 2 - Piano Secondo
Pavimento:Predal Cementizio - 40 cm:204375:2 | 2 - Piano Secondo
Pavimento:Predal Cementizio - 40 cm:204375:3 | 2 - Piano Secondo
Pavimento:Predal Cementizio - 40 cm:204375:4 | 2 - Piano Secondo
Pavimento:Predal Cementizio - 40 cm:204389:2 | 2 - Piano Secondo
Pavimento:Predal Cementizio - 40 cm:204389:3 | 2 - Piano Secondo
Pavimento:Predal Cementizio - 40 cm:204389:4 | 2 - Piano Secondo
Pavimento:Predal Cementizio - 40 cm:204389:5 | 2 - Piano Secondo
Pavimento:Predal Cementizio - 40 cm:204389:6 | 2 - Piano Secondo
Pavimento:Predal Cementizio - 40 cm:204389:7 | 2 - Piano Secondo
Pavimento:Predal Cementizio - 40 cm:204389:8 | 2 - Piano Secondo
Muro di base:Setto CA - 30 cm:204485 | 2 - Piano Secondo | Altro - Categoria: Modelli generici; Famiglia: Apertura-Porta: 0915 x 2134 mm; Famiglia e tipo: Apertura-Porta: 0915 x 2134 mm; Id host: Muro di base: Setto CA - 30 cm; ID tipo: Apertura-Porta: 0915 x 2134 mm; Tipo: Apertura-Porta: 0915 x 2134 mm; Nome famiglia: Apertura-Porta; Fasi - Fase di creazione: Stato di Fatto; Vincoli - Livello: Livello: 2 - Piano Secondo; Prospetto: 0 m; Dati identità - Nome del tipo: 0915 x 2134 mm; Dimensioni - Altezza approssimativa: 2.134 m; Larghezza approssimativa: 0.915 m
Muro di base:Setto CA - 30 cm:204489 | 2 - Piano Secondo | Altro - Categoria: Modelli generici; Famiglia: Apertura-Porta: 0915 x 2134 mm; Famiglia e tipo: Apertura-Porta: 0915 x 2134 mm; Id host: Muro di base: Setto CA - 30 cm; ID tipo: Apertura-Porta: 0915 x 2134 mm; Tipo: Apertura-Porta: 0915 x 2134 mm; Nome famiglia: Apertura-Porta; Fasi - Fase di creazione: Stato di Fatto; Vincoli - Livello: Livello: 2 - Piano Secondo; Prospetto: 0 m; Dati identità - Nome del tipo: 0915 x 2134 mm; Dimensioni - Altezza approssimativa: 2.134 m; Larghezza approssimativa: 0.915 m
2 x Tetto di base:Lamierino - 1 cm:167844 | 3 - Piano Copertura | Altro - Categoria: Tetti; Famiglia: Tetto di base: Lamierino - 1 cm; Famiglia e tipo: Tetto di base: Lamierino - 1 cm; ID tipo: Tetto di base: Lamierino - 1 cm; Tipo: Tetto di base: Lamierino - 1 cm; Nome famiglia: Tetto di base; Fasi - Fase di creazione: Stato di Fatto; Dati identità - Nome del tipo: Lamierino - 1 cm; Nota chiave: T/1; Costruzione - Profondità fascia: 0 m; Taglio trave: Taglio a piombo; Altezza massima del colmo: 11.8952 m; Spessore di default: 0.005 m; Dimensioni - Area: 11.3089 m2; Inclinazione: 0.0971; Spessore: 0.005 m; Volume: 0.0565447 m3; Vincoli - Delimita il locale: yes; Relativo a massa: no; Offset livello di taglio: 0 m; Livello di base: Livello: 3 - Piano Copertura; Offset della base dal livello: 0 m; Grafica - Colore del retino a dettaglio basso: 0; Proprietà analitiche - Ruvidità: 3; Assorbimento: 0.7; Coefficiente di scambio termico (U): 46000; Massa termica: 12109.5; Resistenza termica (R): 0.0000217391
Pavimento:CA-caldana - 28 cm:204511:2 | 2 - Piano Secondo
2 x Tetto di base:Lamierino - 1 cm:167844 | 3 - Piano Copertura | Altro - Categoria: Tetti; Famiglia: Tetto di base: Lamierino - 1 cm; Famiglia e tipo: Tetto di base: Lamierino - 1 cm; ID tipo: Tetto di base: Lamierino - 1 cm; Tipo: Tetto di base: Lamierino - 1 cm; Nome famiglia: Tetto di base; Fasi - Fase di creazione: Stato di Fatto; Dati identità - Nome del tipo: Lamierino - 1 cm; Nota chiave: T/1; Costruzione - Profondità fascia: 0 m; Taglio trave: Taglio a piombo; Altezza massima del colmo: 11.8851 m; Spessore di default: 0.005 m; Dimensioni - Area: 13.0837 m2; Inclinazione: 0.12033; Spessore: 0.005 m; Volume: 0.0654185 m3; Vincoli - Delimita il locale: yes; Relativo a massa: no; Offset livello di taglio: 0 m; Livello di base: Livello: 3 - Piano Copertura; Offset della base dal livello: 0 m; Grafica - Colore del retino a dettaglio basso: 0; Proprietà analitiche - Ruvidità: 3; Assorbimento: 0.7; Coefficiente di scambio termico (U): 46000; Massa termica: 12109.5; Resistenza termica (R): 0.0000217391
Pavimento:CA-caldana - 28 cm:204564:2 | 2 - Piano Secondo
Pavimento:In opera Cementizio - 40 cm:204783:2 | 0 - Piano Terra
Pavimento:In opera Cementizio - 40 cm:204783:3 | 0 - Piano Terra
Pavimento:In opera Cementizio - 40 cm:204783:4 | 0 - Piano Terra
Pavimento:In opera Cementizio - 40 cm:204783:5 | 0 - Piano Terra
Pavimento:In opera Cementizio - 40 cm:204783:6 | 0 - Piano Terra
Pavimento:In opera Cementizio - 40 cm:204783:7 | 0 - Piano Terra
Pavimento:In opera Cementizio - 40 cm:204783:8 | 0 - Piano Terra
Pavimento:In opera Cementizio - 40 cm:204783:9 | 0 - Piano Terra
Pavimento:In opera Cementizio - 40 cm:204783:10 | 0 - Piano Terra
Pavimento:In opera Cementizio - 40 cm:204783:11 | 0 - Piano Terra
Pavimento:In opera Cementizio - 40 cm:204802:2 | 0 - Piano Terra
Pavimento:In opera Cementizio - 40 cm:204802:3 | 0 - Piano Terra
Pavimento:In opera Cementizio - 40 cm:204802:4 | 0 - Piano Terra
Pavimento:In opera Cementizio - 40 cm:204802:5 | 0 - Piano Terra
Pavimento:In opera Cementizio - 40 cm:204802:6 | 0 - Piano Terra
Pavimento:In opera Cementizio - 40 cm:204802:7 | 0 - Piano Terra
Pavimento:In opera Cementizio - 40 cm:204802:8 | 0 - Piano Terra
Pavimento:In opera Cementizio - 40 cm:204802:9 | 0 - Piano Terra
Pavimento:In opera Cementizio - 40 cm:204802:10 | 0 - Piano Terra
Pavimento:In opera Cementizio - 40 cm:204809:2 | 0 - Piano Terra
Pavimento:CA-caldana - 54 cm:204835:2 | 2 - Piano Secondo
Muro di base:Rivestimento 15 cm:204861 | 1 - Piano Primo | Altro - Categoria: Apertura rettangolare su muro diritto; Fasi - Fase di creazione: Stato di Fatto; Vincoli - Vincolo di base: Livello: 1 - Piano Primo; Vincolo parte superiore: Livello: 1 - Piano Primo; Altezza non collegata: 3.22 m; Offset base: -4.69 m; Offset superiore: -1.47 m
Muro di base:Blocchetti - 20 cm:204862 | 0 - Piano Terra | Altro - Categoria: Modelli generici; Famiglia: Apertura-Porta: 208 x 325 mm; Famiglia e tipo: Apertura-Porta: 208 x 325 mm; Id host: Muro di base: Blocchetti - 20 cm; ID tipo: Apertura-Porta: 208 x 325 mm; Tipo: Apertura-Porta: 208 x 325 mm; Nome famiglia: Apertura-Porta; Fasi - Fase di creazione: Stato di Fatto; Vincoli - Livello: Livello: 0 - Piano Terra; Prospetto: 0 m; Dati identità - Nome del tipo: 208 x 325 mm; Dimensioni - Altezza approssimativa: 3.25 m; Larghezza approssimativa: 2.08 m
Muro di base:Blocchetti - 20 cm:204870 | 0 - Piano Terra | Altro - Categoria: Modelli generici; Famiglia: Apertura-Porta: 125 x 220 mm; Famiglia e tipo: Apertura-Porta: 125 x 220 mm; Id host: Muro di base: Rivestimento 15 cm; ID tipo: Apertura-Porta: 125 x 220 mm; Tipo: Apertura-Porta: 125 x 220 mm; Nome famiglia: Apertura-Porta; Fasi - Fase di creazione: Stato di Fatto; Vincoli - Livello: Livello: 0 - Piano Terra; Prospetto: 0 m; Dati identità - Nome del tipo: 125 x 220 mm; Dimensioni - Altezza approssimativa: 2.2 m; Larghezza approssimativa: 1.25 m
Muro di base:Blocchetti - 20 cm:204871 | 0 - Piano Terra | Altro - Categoria: Modelli generici; Famiglia: Apertura-Porta: 125 x 220 mm; Famiglia e tipo: Apertura-Porta: 125 x 220 mm; Id host: Muro di base: Rivestimento 15 cm; ID tipo: Apertura-Porta: 125 x 220 mm; Tipo: Apertura-Porta: 125 x 220 mm; Nome famiglia: Apertura-Porta; Fasi - Fase di creazione: Stato di Fatto; Vincoli - Livello: Livello: 0 - Piano Terra; Prospetto: 0 m; Dati identità - Nome del tipo: 125 x 220 mm; Dimensioni - Altezza approssimativa: 2.2 m; Larghezza approssimativa: 1.25 m
Pavimento:CA-caldana - 54 cm:204888:2 | 0 - Piano Terra
Muro di base:Rivestimento 15 cm:204915 | 0 - Piano Terra | Altro - Categoria: Apertura rettangolare su muro diritto; Fasi - Fase di creazione: Stato di Fatto; Vincoli - Vincolo di base: Livello: 0 - Piano Terra; Vincolo parte superiore: Livello: 1 - Piano Primo; Altezza non collegata: 0.0574853 m; Offset base: -0.0574853 m; Offset superiore: -4.69 m
Muro di base:Rivestimento 15 cm:204915 | 0 - Piano Terra | Altro - Categoria: Apertura rettangolare su muro diritto; Fasi - Fase di creazione: Stato di Fatto; Vincoli - Vincolo di base: Livello: 0 - Piano Terra; Vincolo parte superiore: Livello: 1 - Piano Primo; Altezza non collegata: 0.09 m; Offset base: 0 m; Offset superiore: -4.6 m
Muro di base:Rivestimento 15 cm:204915 | 0 - Piano Terra | Altro - Categoria: Modelli generici; Famiglia: Apertura-Porta: 275 x 313 mm; Famiglia e tipo: Apertura-Porta: 275 x 313 mm; Id host: Muro di base: Rivestimento 15 cm; ID tipo: Apertura-Porta: 275 x 313 mm; Tipo: Apertura-Porta: 275 x 313 mm; Nome famiglia: Apertura-Porta; Fasi - Fase di creazione: Stato di Fatto; Vincoli - Livello: Livello: 0 - Piano Terra; Prospetto: 0.09 m; Dati identità - Nome del tipo: 275 x 313 mm; Dimensioni - Altezza approssimativa: 3.13 m; Larghezza approssimativa: 2.75 m
Muro di base:Rivestimento 15 cm:204920 | 0 - Piano Terra | Altro - Categoria: Apertura rettangolare su un muro ad arco; Fasi - Fase di creazione: Stato di Fatto; Vincoli - Vincolo di base: Livello: 0 - Piano Terra; Vincolo parte superiore: Livello: 1 - Piano Primo; Altezza non collegata: 2.2 m; Offset base: 0 m; Offset superiore: -2.49 m
Muro di base:Rivestimento 15 cm:204920 | 0 - Piano Terra | Altro - Categoria: Modelli generici; Famiglia: Apertura-Porta: 125 x 220 mm; Famiglia e tipo: Apertura-Porta: 125 x 220 mm; Id host: Muro di base: Rivestimento 15 cm; ID tipo: Apertura-Porta: 125 x 220 mm; Tipo: Apertura-Porta: 125 x 220 mm; Nome famiglia: Apertura-Porta; Fasi - Fase di creazione: Stato di Fatto; Vincoli - Livello: Livello: 0 - Piano Terra; Prospetto: 0 m; Dati identità - Nome del tipo: 125 x 220 mm; Dimensioni - Altezza approssimativa: 2.2 m; Larghezza approssimativa: 1.25 m
Muro di base:Rivestimento 15 cm:204922 | 0 - Piano Terra | Altro - Categoria: Modelli generici; Famiglia: Apertura-Porta: 125 x 220 mm; Famiglia e tipo: Apertura-Porta: 125 x 220 mm; Id host: Muro di base: Rivestimento 15 cm; ID tipo: Apertura-Porta: 125 x 220 mm; Tipo: Apertura-Porta: 125 x 220 mm; Nome famiglia: Apertura-Porta; Fasi - Fase di creazione: Stato di Fatto; Vincoli - Livello: Livello: 0 - Piano Terra; Prospetto: 0 m; Dati identità - Nome del tipo: 125 x 220 mm; Dimensioni - Altezza approssimativa: 2.2 m; Larghezza approssimativa: 1.25 m
Muro di base:Rivestimento 15 cm:204928 | 0 - Piano Terra | Altro - Categoria: Apertura rettangolare su muro diritto; Fasi - Fase di creazione: Stato di Fatto; Vincoli - Vincolo di base: Livello: 0 - Piano Terra; Vincolo parte superiore: Livello: 1 - Piano Primo; Altezza non collegata: 0.085 m; Offset base: 0.005 m; Offset superiore: -4.6 m
Muro di base:Rivestimento 15 cm:204928 | 0 - Piano Terra | Altro - Categoria: Modelli generici; Famiglia: Apertura-Porta: 275 x 313 mm; Famiglia e tipo: Apertura-Porta: 275 x 313 mm; Id host: Muro di base: Rivestimento 15 cm; ID tipo: Apertura-Porta: 275 x 313 mm; Tipo: Apertura-Porta: 275 x 313 mm; Nome famiglia: Apertura-Porta; Fasi - Fase di creazione: Stato di Fatto; Vincoli - Livello: Livello: 0 - Piano Terra; Prospetto: 0.09 m; Dati identità - Nome del tipo: 275 x 313 mm; Dimensioni - Altezza approssimativa: 3.13 m; Larghezza approssimativa: 2.75 m
Pavimento:In opera Cementizio - 40 cm:204934:2 | 2 - Piano Secondo
Pavimento:In opera Cementizio - 40 cm:204934:3 | 2 - Piano Secondo
Pavimento:In opera Cementizio - 40 cm:204934:4 | 2 - Piano Secondo
Pavimento:In opera Cementizio - 40 cm:204934:5 | 2 - Piano Secondo
Pavimento:In opera Cementizio - 40 cm:204934:6 | 2 - Piano Secondo
Pavimento:In opera Cementizio - 40 cm:204934:7 | 2 - Piano Secondo
Muro di base:Blocchetti - 20 cm:205052 | 0 - Piano Terra | Altro - Categoria: Modelli generici; Famiglia: Apertura-Porta: 120 x 215 mm; Famiglia e tipo: Apertura-Porta: 120 x 215 mm; Id host: Muro di base: Blocchetti - 20 cm; ID tipo: Apertura-Porta: 120 x 215 mm; Tipo: Apertura-Porta: 120 x 215 mm; Nome famiglia: Apertura-Porta; Fasi - Fase di creazione: Stato di Fatto; Vincoli - Livello: Livello: 0 - Piano Terra; Prospetto: 0 m; Dati identità - Nome del tipo: 120 x 215 mm; Dimensioni - Altezza approssimativa: 2.15 m; Larghezza approssimativa: 1.2 m
Pavimento:Predal Cementizio - 40 cm:205063:2 | 1 - Piano Primo
Pavimento:Predal Cementizio - 40 cm:205063:3 | 1 - Piano Primo
Pavimento:Predal Cementizio - 40 cm:205063:4 | 1 - Piano Primo
Pavimento:Predal Cementizio - 40 cm:205063:5 | 1 - Piano Primo
Pavimento:Predal Cementizio - 40 cm:205063:6 | 1 - Piano Primo
Pavimento:Predal Cementizio - 40 cm:205063:7 | 1 - Piano Primo
Pavimento:Predal Cementizio - 40 cm:205063:8 | 1 - Piano Primo
Pavimento:Predal Cementizio - 40 cm:205063:9 | 1 - Piano Primo
Pavimento:Predal Cementizio - 40 cm:205063:10 | 1 - Piano Primo
Pavimento:Predal Cementizio - 40 cm:205063:11 | 1 - Piano Primo
Pavimento:Predal Cementizio - 40 cm:205063:12 | 1 - Piano Primo
Pavimento:Predal Cementizio - 40 cm:205063:13 | 1 - Piano Primo
Pavimento:Predal Cementizio - 40 cm:205063:14 | 1 - Piano Primo
Pavimento:Predal Cementizio - 40 cm:205063:15 | 1 - Piano Primo
Pavimento:Predal Cementizio - 40 cm:205063:16 | 1 - Piano Primo
Pavimento:Predal Cementizio - 40 cm:205063:17 | 1 - Piano Primo
Pavimento:Predal Cementizio - 40 cm:205063:18 | 1 - Piano Primo
Pavimento:Predal Cementizio - 40 cm:205063:19 | 1 - Piano Primo
Pavimento:Predal Cementizio - 40 cm:205063:20 | 1 - Piano Primo
Pavimento:Predal Cementizio - 40 cm:205063:21 | 1 - Piano Primo
Pavimento:Predal Cementizio - 40 cm:205070:2 | 1 - Piano Primo
Pavimento:Predal Cementizio - 40 cm:205070:3 | 1 - Piano Primo
Pavimento:Predal Cementizio - 40 cm:205070:4 | 1 - Piano Primo
Pavimento:Predal Cementizio - 40 cm:205084:2 | 1 - Piano Primo
Pavimento:Predal Cementizio - 40 cm:205084:3 | 1 - Piano Primo
Pavimento:Predal Cementizio - 40 cm:205084:4 | 1 - Piano Primo
Pavimento:Predal Cementizio - 40 cm:205084:5 | 1 - Piano Primo
Pavimento:Predal Cementizio - 40 cm:205084:6 | 1 - Piano Primo
Pavimento:Predal Cementizio - 40 cm:205084:7 | 1 - Piano Primo
Pavimento:Predal Cementizio - 40 cm:205084:8 | 1 - Piano Primo
Pavimento:Predal Cementizio - 40 cm:205084:9 | 1 - Piano Primo
Pavimento:Predal Cementizio - 40 cm:205084:10 | 1 - Piano Primo
Pavimento:Predal Cementizio - 40 cm:205084:11 | 1 - Piano Primo
Pavimento:Predal Cementizio - 40 cm:205084:12 | 1 - Piano Primo
Pavimento:Predal Cementizio - 40 cm:205084:13 | 1 - Piano Primo
Pavimento:Predal Cementizio - 40 cm:205084:14 | 1 - Piano Primo
Pavimento:Predal Cementizio - 40 cm:205084:15 | 1 - Piano Primo
Pavimento:Predal Cementizio - 40 cm:205084:16 | 1 - Piano Primo
Pavimento:Predal Cementizio - 40 cm:205084:17 | 1 - Piano Primo
Muro di base:Pannello coibentato - 6 cm:205730 | 0 - Piano Terra | Altro - Categoria: Modelli generici; Famiglia: Apertura-Porta: 190 x 295 mm; Famiglia e tipo: Apertura-Porta: 190 x 295 mm; Id host: Muro di base: Pannello coibentato - 6 cm; ID tipo: Apertura-Porta: 190 x 295 mm; Tipo: Apertura-Porta: 190 x 295 mm; Nome famiglia: Apertura-Porta; Fasi - Fase di creazione: Stato di Fatto; Vincoli - Livello: Livello: 0 - Piano Terra; Prospetto: 0 m; Dati identità - Nome del tipo: 190 x 295 mm; Dimensioni - Altezza approssimativa: 2.95 m; Larghezza approssimativa: 1.9 m
Muro di base:Pannello coibentato - 6 cm:205735 | 0 - Piano Terra | Altro - Categoria: Modelli generici; Famiglia: Apertura-Porta: 190 x 295 mm; Famiglia e tipo: Apertura-Porta: 190 x 295 mm; Id host: Muro di base: Pannello coibentato - 6 cm; ID tipo: Apertura-Porta: 190 x 295 mm; Tipo: Apertura-Porta: 190 x 295 mm; Nome famiglia: Apertura-Porta; Fasi - Fase di creazione: Stato di Fatto; Vincoli - Livello: Livello: 0 - Piano Terra; Prospetto: 0 m; Dati identità - Nome del tipo: 190 x 295 mm; Dimensioni - Altezza approssimativa: 2.95 m; Larghezza approssimativa: 1.9 m
Muro di base:Pannello coibentato - 6 cm:205735 | 0 - Piano Terra | Altro - Categoria: Modelli generici; Famiglia: Apertura-Porta: 110 x 231 mm; Famiglia e tipo: Apertura-Porta: 110 x 231 mm; Id host: Muro di base: Pannello coibentato - 6 cm; ID tipo: Apertura-Porta: 110 x 231 mm; Tipo: Apertura-Porta: 110 x 231 mm; Nome famiglia: Apertura-Porta; Fasi - Fase di creazione: Stato di Fatto; Vincoli - Livello: Livello: 0 - Piano Terra; Prospetto: 0.09 m; Dati identità - Nome del tipo: 110 x 231 mm; Dimensioni - Altezza approssimativa: 2.31 m; Larghezza approssimativa: 1.1 m
Muro di base:Setto CA rivestito int-est 47 cm:204033 | 0 - Piano Terra
Muro di base:Setto CA rivestito int-est 47 cm:204031 | 0 - Piano Terra
Setto Sx:Setto Sx:207356:1 | 1 - Piano Primo
Setto Sx:Setto Sx:207356:2 | 1 - Piano Primo
Setto Sx:Setto Sx:207356:3 | 1 - Piano Primo
Setto sx p2:Setto sx p2:207391:1 | 1 - Piano Primo
Setto sx p2:Setto sx p2:207391:2 | 1 - Piano Primo
Setto Sx1:Setto Sx:207442:1 | 0 - Piano Terra
Setto Sx1:Setto Sx:207442:2 | 0 - Piano Terra
Muro di base:Rivestimento 15 cm:207486 | 1 - Piano Primo | Altro - Categoria: Modelli generici; Famiglia: Apertura-Finestra-Quadrata: 275 x 160; Famiglia e tipo: Apertura-Finestra-Quadrata: 275 x 160; Id host: Muro di base: Rivestimento 15 cm; ID tipo: Apertura-Finestra-Quadrata: 275 x 160; Tipo: Apertura-Finestra-Quadrata: 275 x 160; Nome famiglia: Apertura-Finestra-Quadrata; Fasi - Fase di creazione: Stato di Fatto; Vincoli - Livello: Livello: 1 - Piano Primo; Prospetto: 1 m; Dati identità - Nome del tipo: 275 x 160; Dimensioni - Altezza approssimativa: 1.6 m; Larghezza approssimativa: 2.75 m; Altezza davanzale: 1 m
Muro di base:Rivestimento 15 cm:207489 | 0 - Piano Terra | Altro - Categoria: Modelli generici; Famiglia: Apertura-Porta: 125 x 220 mm; Famiglia e tipo: Apertura-Porta: 125 x 220 mm; Id host: Muro di base: Rivestimento 15 cm; ID tipo: Apertura-Porta: 125 x 220 mm; Tipo: Apertura-Porta: 125 x 220 mm; Nome famiglia: Apertura-Porta; Fasi - Fase di creazione: Stato di Fatto; Vincoli - Livello: Livello: 0 - Piano Terra; Prospetto: 0 m; Dati identità - Nome del tipo: 125 x 220 mm; Dimensioni - Altezza approssimativa: 2.2 m; Larghezza approssimativa: 1.25 m
Muro di base:Blocchetti - 20 cm:207490 | 0 - Piano Terra | Altro - Categoria: Modelli generici; Famiglia: Apertura-Porta: 125 x 220 mm; Famiglia e tipo: Apertura-Porta: 125 x 220 mm; Id host: Muro di base: Rivestimento 15 cm; ID tipo: Apertura-Porta: 125 x 220 mm; Tipo: Apertura-Porta: 125 x 220 mm; Nome famiglia: Apertura-Porta; Fasi - Fase di creazione: Stato di Fatto; Vincoli - Livello: Livello: 0 - Piano Terra; Prospetto: 0 m; Dati identità - Nome del tipo: 125 x 220 mm; Dimensioni - Altezza approssimativa: 2.2 m; Larghezza approssimativa: 1.25 m
Muro di base:Rivestimento 15 cm:207510 | 0 - Piano Terra | Altro - Categoria: Modelli generici; Famiglia: Apertura-Porta: 125 x 220 mm; Famiglia e tipo: Apertura-Porta: 125 x 220 mm; Id host: Muro di base: Rivestimento 15 cm; ID tipo: Apertura-Porta: 125 x 220 mm; Tipo: Apertura-Porta: 125 x 220 mm; Nome famiglia: Apertura-Porta; Fasi - Fase di creazione: Stato di Fatto; Vincoli - Livello: Livello: 0 - Piano Terra; Prospetto: 0 m; Dati identità - Nome del tipo: 125 x 220 mm; Dimensioni - Altezza approssimativa: 2.2 m; Larghezza approssimativa: 1.25 m
Muro di base:Blocchetti - 20 cm:207512 | 0 - Piano Terra | Altro - Categoria: Modelli generici; Famiglia: Apertura-Porta: 125 x 220 mm; Famiglia e tipo: Apertura-Porta: 125 x 220 mm; Id host: Muro di base: Rivestimento 15 cm; ID tipo: Apertura-Porta: 125 x 220 mm; Tipo: Apertura-Porta: 125 x 220 mm; Nome famiglia: Apertura-Porta; Fasi - Fase di creazione: Stato di Fatto; Vincoli - Livello: Livello: 0 - Piano Terra; Prospetto: 0 m; Dati identità - Nome del tipo: 125 x 220 mm; Dimensioni - Altezza approssimativa: 2.2 m; Larghezza approssimativa: 1.25 m
Muro di base:Rivestimento 15 cm:207574 | 1 - Piano Primo | Altro - Categoria: Modelli generici; Famiglia: Apertura-Finestra-Quadrata: 275 x 160; Famiglia e tipo: Apertura-Finestra-Quadrata: 275 x 160; Id host: Muro di base: Rivestimento 15 cm; ID tipo: Apertura-Finestra-Quadrata: 275 x 160; Tipo: Apertura-Finestra-Quadrata: 275 x 160; Nome famiglia: Apertura-Finestra-Quadrata; Fasi - Fase di creazione: Stato di Fatto; Vincoli - Livello: Livello: 1 - Piano Primo; Prospetto: 1 m; Dati identità - Nome del tipo: 275 x 160; Dimensioni - Altezza approssimativa: 1.6 m; Larghezza approssimativa: 2.75 m; Altezza davanzale: 1 m
Muri 7:Muri 7:207758:1 | 1 - Piano Primo
Muri 7:Muri 7:207758:2 | 1 - Piano Primo
Muri 7:Muri 7:207758:3 | 1 - Piano Primo
Muro di base:Rivestimento 15 cm:207871 | 1 - Piano Primo | Altro - Categoria: Modelli generici; Famiglia: Apertura-Finestra-Quadrata: 275 x 160; Famiglia e tipo: Apertura-Finestra-Quadrata: 275 x 160; Id host: Muro di base: Rivestimento 15 cm; ID tipo: Apertura-Finestra-Quadrata: 275 x 160; Tipo: Apertura-Finestra-Quadrata: 275 x 160; Nome famiglia: Apertura-Finestra-Quadrata; Fasi - Fase di creazione: Stato di Fatto; Vincoli - Livello: Livello: 1 - Piano Primo; Prospetto: 1 m; Dati identità - Nome del tipo: 275 x 160; Dimensioni - Altezza approssimativa: 1.6 m; Larghezza approssimativa: 2.75 m; Altezza davanzale: 1 m
Muro di base:Rivestimento 15 cm:207902 | 1 - Piano Primo | Altro - Categoria: Modelli generici; Famiglia: Apertura-Finestra-Quadrata: 275 x 160; Famiglia e tipo: Apertura-Finestra-Quadrata: 275 x 160; Id host: Muro di base: Rivestimento 15 cm; ID tipo: Apertura-Finestra-Quadrata: 275 x 160; Tipo: Apertura-Finestra-Quadrata: 275 x 160; Nome famiglia: Apertura-Finestra-Quadrata; Fasi - Fase di creazione: Stato di Fatto; Vincoli - Livello: Livello: 1 - Piano Primo; Prospetto: 1 m; Dati identità - Nome del tipo: 275 x 160; Dimensioni - Altezza approssimativa: 1.6 m; Larghezza approssimativa: 2.75 m; Altezza davanzale: 1 m
Muro di base:Blocchetti - 20 cm:208487 | 0 - Piano Terra | Altro - Categoria: Modelli generici; Famiglia: Apertura-Porta: 110 x 220 mm; Famiglia e tipo: Apertura-Porta: 110 x 220 mm; Id host: Muro di base: Blocchetti - 20 cm; ID tipo: Apertura-Porta: 110 x 220 mm; Tipo: Apertura-Porta: 110 x 220 mm; Nome famiglia: Apertura-Porta; Fasi - Fase di creazione: Stato di Fatto; Vincoli - Livello: Livello: 0 - Piano Terra; Prospetto: 0 m; Dati identità - Nome del tipo: 110 x 220 mm; Dimensioni - Altezza approssimativa: 2.2 m; Larghezza approssimativa: 1.1 m
Pavimento:Marciapiede - 10 cm:208501:2 | 2 - Piano Secondo
Pavimento:Marciapiede - 10 cm:208501:3 | 2 - Piano Secondo
Pavimento:Marciapiede - 10 cm:208501:4 | 2 - Piano Secondo
Pavimento:Marciapiede - 10 cm:208501:5 | 2 - Piano Secondo
Pavimento:Marciapiede - 10 cm:208508:2 | 2 - Piano Secondo
Pavimento:Marciapiede - 10 cm:208508:3 | 2 - Piano Secondo
Pavimento:Marciapiede - 10 cm:208508:4 | 2 - Piano Secondo
Pavimento:Marciapiede - 10 cm:208508:5 | 2 - Piano Secondo
Muro di base:Setto CA rivestito int - 31 cm:204029 | 0 - Piano Terra
Muro di base:Setto CA rivestito int-est 47 cm:204017 | 0 - Piano Terra
Muro di base:Setto CA rivestito int - 31 cm:204023 | 0 - Piano Terra

# IfcOpeningElement: Recess (2)
In: 2 - Piano Secondo
Altro - Categoria: Apertura rettangolare su un muro ad arco
Fasi - Fase di creazione: Stato di Fatto
Vincoli - Vincolo di base: Livello: 2 - Piano Secondo; Vincolo parte superiore: Livello: 3 - Piano Copertura
Name (Muro di base:Setto CA intonacato int - 41 cm:...) | Altezza non collegata (m) | Offset base (m) | Offset superiore (m)
204298 | 0.172232 | 1.11 | -2.05777
204354 | 0.185827 | 0.905 | -2.24917

# IfcRoof: Tetto di base:Container - 5 cm, Tetto di base:Container - 5 cm:205898
In: 2 - Piano Secondo
Pset_RoofCommon - IsExternal: yes; Reference: Container - 5 cm; TotalArea: 14.6786 m2; ProjectedArea: 14.6786 m2
Altro - Categoria: Tetti; Famiglia: Tetto di base: Container - 5 cm; Famiglia e tipo: Tetto di base: Container - 5 cm; ID tipo: Tetto di base: Container - 5 cm; Tipo: Tetto di base: Container - 5 cm; Nome famiglia: Tetto di base
Costruzione - Profondità fascia: 0 m; Taglio trave: Taglio a piombo; Altezza massima del colmo: 11.21 m; Spessore di default: 0.05 m
Dimensioni - Area: 14.6786 m2; Spessore: 0.05 m; Volume: 0.733931 m3
Fasi - Fase di creazione: Stato di Fatto
Vincoli - Delimita il locale: yes; Relativo a massa: no; Livello di base: Livello: 2 - Piano Secondo; Offset livello di taglio: 0 m; Offset della base dal livello: 2.55 m
Dati identità - Nome del tipo: Container - 5 cm; Nota chiave: T/1
Grafica - Colore del retino a dettaglio basso: 0
Proprietà analitiche - Ruvidità: 3; Assorbimento: 0.7; Coefficiente di scambio termico (U): 900; Massa termica: 188400; Resistenza termica (R): 0.00111111

# IfcRoof: Tetto di base:Finitura Cementizio - 15 cm, Tetto di base:Finitura Cementizio - 15 cm:204404
In: 2 - Piano Secondo
Pset_RoofCommon - IsExternal: yes; Reference: Finitura Cementizio - 15 cm; TotalArea: 0.85237 m2; ProjectedArea: 0.852108 m2
Altro - Categoria: Tetti; Famiglia: Tetto di base: Finitura Cementizio - 15 cm; Famiglia e tipo: Tetto di base: Finitura Cementizio - 15 cm; ID tipo: Tetto di base: Finitura Cementizio - 15 cm; Tipo: Tetto di base: Finitura Cementizio - 15 cm; Nome famiglia: Tetto di base
Costruzione - Altezza massima del colmo: 8.36 m; Profondità fascia: 0 m; Taglio trave: Taglio a piombo; Spessore di default: 0.15 m
Dimensioni - Area: 0.85237 m2; Spessore: 0.15 m; Volume: 0.127844 m3
Fasi - Fase di creazione: Stato di Fatto
Vincoli - Delimita il locale: yes; Relativo a massa: no; Livello di base: Livello: 2 - Piano Secondo; Offset della base dal livello: -0.4 m; Offset livello di taglio: 0 m
Dati identità - Nome del tipo: Finitura Cementizio - 15 cm; Nota chiave: T/1
Grafica - Colore del retino a dettaglio basso: 0
Proprietà analitiche - Ruvidità: 3; Assorbimento: 0.7; Coefficiente di scambio termico (U): 6.97333; Massa termica: 226665; Resistenza termica (R): 0.143403

# IfcRoof: Tetto di base:Lamierino - 1 cm (3)
Pset_RoofCommon - IsExternal: yes; Reference: Lamierino - 1 cm
Altro - Categoria: Tetti; Famiglia: Tetto di base: Lamierino - 1 cm; Famiglia e tipo: Tetto di base: Lamierino - 1 cm; ID tipo: Tetto di base: Lamierino - 1 cm; Tipo: Tetto di base: Lamierino - 1 cm; Nome famiglia: Tetto di base
Costruzione - Profondità fascia: 0 m; Taglio trave: Taglio a piombo; Spessore di default: 0.005 m
Dimensioni - Spessore: 0.005 m
Fasi - Fase di creazione: Stato di Fatto
Vincoli - Delimita il locale: yes; Relativo a massa: no; Offset livello di taglio: 0 m
Dati identità - Nome del tipo: Lamierino - 1 cm; Nota chiave: T/1
Grafica - Colore del retino a dettaglio basso: 0
Proprietà analitiche - Ruvidità: 3; Assorbimento: 0.7; Coefficiente di scambio termico (U): 46000; Massa termica: 12109.5; Resistenza termica (R): 0.0000217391
Name (Tetto di base:Lamierino - 1 cm:...) | In | TotalArea (m2) = Area (m2) | ProjectedArea (m2) | Altezza massima del colmo (m) | Inclinazione | Volume (m3) | Livello di base | Offset della base dal livello (m)
204499 | 3 - Piano Copertura | 11.3089 | 44.772 | 11.8952 | 0.0971 | 0.0565447 | Livello: 3 - Piano Copertura | 0
204534 | 3 - Piano Copertura | 13.0837 | 69.1648 | 11.8851 | 0.12033 | 0.0654185 | Livello: 3 - Piano Copertura | 0
205833 | 0 - Piano Terra | 2950.31 | 2950.31 | 8.455 |  | 14.7515 | Livello: 0 - Piano Terra | 8.45

# IfcRoof: Tetto di base:Ondulina - 6 cm (2)
In: 3 - Piano Copertura
Pset_RoofCommon - IsExternal: yes; Reference: Ondulina - 6 cm
Altro - Categoria: Tetti; Famiglia: Tetto di base: Ondulina - 6 cm; Famiglia e tipo: Tetto di base: Ondulina - 6 cm; ID tipo: Tetto di base: Ondulina - 6 cm; Tipo: Tetto di base: Ondulina - 6 cm; Nome famiglia: Tetto di base
Costruzione - Profondità fascia: 0 m; Taglio trave: Taglio a piombo; Spessore di default: 0.06 m
Dimensioni - Spessore: 0.06 m
Fasi - Fase di creazione: Stato di Fatto
Vincoli - Delimita il locale: yes; Relativo a massa: no; Offset livello di taglio: 0 m; Livello di base: Livello: 3 - Piano Copertura
Dati identità - Nome del tipo: Ondulina - 6 cm; Nota chiave: T/1
Grafica - Colore del retino a dettaglio basso: 0
Proprietà analitiche - Ruvidità: 3; Assorbimento: 0.7; Coefficiente di scambio termico (U): 8.36667; Massa termica: 131157; Resistenza termica (R): 0.119522
Name (Tetto di base:Ondulina - 6 cm:...) | TotalArea (m2) = Area (m2) | ProjectedArea (m2) | Altezza massima del colmo (m) | Inclinazione | Volume (m3) | Offset della base dal livello (m)
205753 | 17.9441 | 17.86 | 11.5886 | 0.0971699 | 1.07665 | -0.65
205764 | 41.0599 | 40.766 | 11.5161 | 0.120305 | 2.4636 | -1.15

# IfcSlab: Pavimento:CA-caldana - 28 cm (2)
In: 2 - Piano Secondo
PredefinedType: FLOOR; Material: Sabbia e Calcestruzzo 0.08 m, Calcestruzzo 0.2 m
Pset_SlabCommon - LoadBearing: yes; IsExternal: no; Reference: CA-caldana - 28 cm; ThermalTransmittance: 5.23 kg/K/s3
Altro - Categoria: Pavimenti; Famiglia: Pavimento: CA-caldana - 28 cm; Famiglia e tipo: Pavimento: CA-caldana - 28 cm; ID tipo: Pavimento: CA-caldana - 28 cm; Tipo: Pavimento: CA-caldana - 28 cm; Nome famiglia: Pavimento
Dimensioni - Spessore: 0.28 m
Fasi - Fase di creazione: Stato di Fatto
Strutturale - Attiva modello analitico: no; Strutturale: no
Vincoli - Delimita il locale: yes; Relativo a massa: no; Offset di altezza da livello: 0 m; Livello: Livello: 2 - Piano Secondo
Costruzione - Funzione: Interno; Spessore di default: 0.28 m
Dati identità - Nome del tipo: CA-caldana - 28 cm; Nota chiave: S/3
Grafica - Colore del retino a dettaglio basso: 0
Proprietà analitiche - Ruvidità: 3; Assorbimento: 0.7; Coefficiente di scambio termico (U): 5.23; Massa termica: 302220; Resistenza termica (R): 0.191205
Name (Pavimento:CA-caldana - 28 cm:...) | Area (m2) | Perimetro (m) | Volume (m3)
204511 | 17.9247 | 20.297 | 5.01891
204564 | 17.6415 | 20.057 | 4.93962

# IfcSlab: Pavimento:CA-caldana - 54 cm (6)
PredefinedType: FLOOR; Material: Asfalto, bitume 0.01 m, Sabbia e Calcestruzzo 0.18 m, Calcestruzzo 0.35 m
Pset_SlabCommon - LoadBearing: yes; IsExternal: no; Reference: CA-caldana - 54 cm; ThermalTransmittance: 2.91287 kg/K/s3
Altro - Categoria: Pavimenti; Famiglia: Pavimento: CA-caldana - 54 cm; Famiglia e tipo: Pavimento: CA-caldana - 54 cm; ID tipo: Pavimento: CA-caldana - 54 cm; Tipo: Pavimento: CA-caldana - 54 cm; Nome famiglia: Pavimento
Dimensioni - Spessore: 0.54 m
Fasi - Fase di creazione: Stato di Fatto
Strutturale - Attiva modello analitico: no; Strutturale: no
Vincoli - Delimita il locale: yes; Relativo a massa: no
Costruzione - Funzione: Interno; Spessore di default: 0.54 m
Dati identità - Nome del tipo: CA-caldana - 54 cm; Nota chiave: S/3
Grafica - Colore del retino a dettaglio basso: 0
Proprietà analitiche - Ruvidità: 3; Assorbimento: 0.7; Coefficiente di scambio termico (U): 2.91287; Massa termica: 548457; Resistenza termica (R): 0.343304
Name (Pavimento:CA-caldana - 54 cm:...) | In | PitchAngle (deg) | Area (m2) | Perimetro (m) | Volume (m3) | Livello | Offset di altezza da livello (m)
204420 | 3 - Piano Copertura | 0 | 54.0419 | 26.1441 | 29.1827 | Livello: 3 - Piano Copertura | -0.15
204449 | 3 - Piano Copertura | 0 | 54.2242 | 26.1993 | 29.281 | Livello: 3 - Piano Copertura | -0.15
204835 | 2 - Piano Secondo |  | 11.4713 | 15.7092 | 6.19464 | Livello: 2 - Piano Secondo | 0.88
204839 | 0 - Piano Terra | 0 | 11.0267 | 14.9957 | 5.95446 | Livello: 0 - Piano Terra | 9.49
204888 | 0 - Piano Terra |  | 10.9193 | 15.398 | 5.89645 | Livello: 0 - Piano Terra | 9.49
204897 | 0 - Piano Terra | 0 | 11.181 | 15.1699 | 6.03777 | Livello: 0 - Piano Terra | 9.49

# IfcSlab: Pavimento:CA-caldana e contr- 49 cm (3)
In: 3 - Piano Copertura
PredefinedType: FLOOR; Material: Asfalto, bitume 0.01 m, Sabbia e Calcestruzzo 0.08 m, Calcestruzzo 0.35 m, Isolamento 0.05 m
Pset_SlabCommon - LoadBearing: yes; IsExternal: no; Reference: CA-caldana e contr- 49 cm; ThermalTransmittance: 2.91287 kg/K/s3; PitchAngle: 0 deg
Altro - Categoria: Pavimenti; Famiglia: Pavimento: CA-caldana e contr- 49 cm; Famiglia e tipo: Pavimento: CA-caldana e contr- 49 cm; ID tipo: Pavimento: CA-caldana e contr- 49 cm; Tipo: Pavimento: CA-caldana e contr- 49 cm; Nome famiglia: Pavimento
Dimensioni - Spessore: 0.49 m
Fasi - Fase di creazione: Stato di Fatto
Strutturale - Attiva modello analitico: no; Strutturale: no
Vincoli - Delimita il locale: yes; Relativo a massa: no; Livello: Livello: 3 - Piano Copertura; Offset di altezza da livello: -0.15 m
Costruzione - Funzione: Interno; Spessore di default: 0.49 m
Dati identità - Nome del tipo: CA-caldana e contr- 49 cm; Nota chiave: S/3
Grafica - Colore del retino a dettaglio basso: 0
Proprietà analitiche - Ruvidità: 3; Assorbimento: 0.7; Coefficiente di scambio termico (U): 2.91287; Massa termica: 548457; Resistenza termica (R): 0.343304
Name (Pavimento:CA-caldana e contr- 49 cm:...) | Area (m2) | Perimetro (m) | Volume (m3)
204255 | 35.1848 | 24.18 | 17.2406
204258 | 35.1848 | 24.18 | 17.2406
204261 | 37.4784 | 25.12 | 18.3644

# IfcSlab: Pavimento:Cordolo esterno - 9 cm (22)
In: 0 - Piano Terra
PredefinedType: FLOOR; Material: Ceramica bianca 0.03 m, Sabbia e Calcestruzzo 0.06 m
Pset_SlabCommon - LoadBearing: yes; IsExternal: no; PitchAngle: 0 deg; Reference: Cordolo esterno - 9 cm
Altro - Categoria: Pavimenti; Famiglia: Pavimento: Cordolo esterno - 9 cm; Famiglia e tipo: Pavimento: Cordolo esterno - 9 cm; ID tipo: Pavimento: Cordolo esterno - 9 cm; Tipo: Pavimento: Cordolo esterno - 9 cm; Nome famiglia: Pavimento
Dimensioni - Spessore: 0.09 m
Fasi - Fase di creazione: Stato di Fatto
Strutturale - Attiva modello analitico: no; Strutturale: no
Vincoli - Delimita il locale: yes; Relativo a massa: no; Livello: Livello: 0 - Piano Terra; Offset di altezza da livello: 0.09 m
Costruzione - Funzione: Interno; Spessore di default: 0.09 m
Dati identità - Nome del tipo: Cordolo esterno - 9 cm; Nota chiave: S/3
Grafica - Colore del retino a dettaglio basso: 0
Proprietà analitiche - Ruvidità: 3; Assorbimento: 0.7
Name (Pavimento:Cordolo esterno - 9 cm:...) | Area (m2) | Perimetro (m) | Volume (m3)
208763 | 2.5043 | 15.8376 | 0.225387
208771 | 0.912953 | 6.20007 | 0.0821658
208778 | 2.46933 | 15.6256 | 0.22224
208784 | 2.47026 | 15.6313 | 0.222323
208789 | 2.46959 | 15.6272 | 0.222263
208795 | 2.4401 | 15.4485 | 0.219609
208800 | 2.47453 | 15.6572 | 0.222708
208806 | 2.4684 | 15.62 | 0.222156
208812 | 2.44913 | 15.5032 | 0.220422
208818 | 2.46616 | 15.6064 | 0.221955
208824 | 2.46756 | 15.6149 | 0.22208
208830 | 2.46613 | 15.6062 | 0.221951
208836 | 2.50349 | 15.8327 | 0.225314
208842 | 0.912972 | 6.20004 | 0.0821675
208863 | 1.77923 | 11.4432 | 0.160131
208869 | 2.46616 | 15.6064 | 0.221955
208875 | 2.46756 | 15.6149 | 0.22208
208881 | 2.46613 | 15.6062 | 0.221951
208887 | 2.46798 | 15.6175 | 0.222119
208893 | 0.9131 | 6.2 | 0.082179
208905 | 0.9735 | 6.56 | 0.087615
208913 | 0.688906 | 4.83519 | 0.0620015

# IfcSlab: Pavimento:In opera Cementizio - 30 cm (4)
In: 0 - Piano Terra
PredefinedType: FLOOR; Material: Calcestruzzo 0.3 m
Pset_SlabCommon - LoadBearing: yes; IsExternal: no; PitchAngle: 0 deg; Reference: In opera Cementizio - 30 cm; ThermalTransmittance: 3.48667 kg/K/s3
Altro - Categoria: Pavimenti; Famiglia: Pavimento: In opera Cementizio - 30 cm; Famiglia e tipo: Pavimento: In opera Cementizio - 30 cm; ID tipo: Pavimento: In opera Cementizio - 30 cm; Tipo: Pavimento: In opera Cementizio - 30 cm; Nome famiglia: Pavimento
Dimensioni - Spessore: 0.3 m
Fasi - Fase di creazione: Stato di Fatto
Strutturale - Attiva modello analitico: no; Strutturale: no
Vincoli - Delimita il locale: yes; Relativo a massa: no; Livello: Livello: 0 - Piano Terra; Offset di altezza da livello: 9.64 m
Costruzione - Funzione: Interno; Spessore di default: 0.3 m
Dati identità - Nome del tipo: In opera Cementizio - 30 cm; Nota chiave: S/3
Grafica - Colore del retino a dettaglio basso: 0
Proprietà analitiche - Ruvidità: 3; Assorbimento: 0.7; Coefficiente di scambio termico (U): 3.48667; Massa termica: 453330; Resistenza termica (R): 0.286807
Name (Pavimento:In opera Cementizio - 30 cm:...) | Area (m2) | Perimetro (m) | Volume (m3)
204850 | 3.38989 | 14.8999 | 1.01691
204853 | 3.34967 | 14.43 | 1.0047
204882 | 3.30292 | 14.6017 | 0.990884
204885 | 3.00472 | 13.5801 | 0.901421

# IfcSlab: Pavimento:In opera Cementizio - 40 cm (14)
PredefinedType: FLOOR
Pset_SlabCommon - LoadBearing: yes; Reference: In opera Cementizio - 40 cm; IsExternal: no; ThermalTransmittance: 3.48667 kg/K/s3
Altro - Categoria: Pavimenti; Famiglia: Pavimento: In opera Cementizio - 40 cm; Famiglia e tipo: Pavimento: In opera Cementizio - 40 cm; ID tipo: Pavimento: In opera Cementizio - 40 cm; Tipo: Pavimento: In opera Cementizio - 40 cm; Nome famiglia: Pavimento
Dimensioni - Spessore: 0.4 m
Fasi - Fase di creazione: Stato di Fatto
Strutturale - Attiva modello analitico: no; Strutturale: no
Vincoli - Delimita il locale: yes; Relativo a massa: no; Offset di altezza da livello: 0 m
Costruzione - Funzione: Interno; Spessore di default: 0.4 m
Dati identità - Nome del tipo: In opera Cementizio - 40 cm; Nota chiave: S/3
Grafica - Colore del retino a dettaglio basso: 0
Proprietà analitiche - Ruvidità: 3; Assorbimento: 0.7; Coefficiente di scambio termico (U): 3.48667; Massa termica: 453330; Resistenza termica (R): 0.286807
Name (Pavimento:In opera Cementizio - 40 cm:...) | In | Material | Area (m2) | Perimetro (m) | Volume (m3) | Livello
204105 | 2 - Piano Secondo | Default - Calcestruzzo 0.1 m, Calcestruzzo 0.3 m | 166.675 | 68.2764 | 66.6701 | Livello: 2 - Piano Secondo
204415 | 2 - Piano Secondo |  | 158.474 | 79.0805 | 63.3896 | Livello: 2 - Piano Secondo | Modifica forma solaio - Condizione del bordo curvo: 1
204768 | 0 - Piano Terra | Default - Calcestruzzo 0.1 m, Calcestruzzo 0.3 m | 418.231 | 78.0468 | 167.292 | Livello: 0 - Piano Terra | Pset_SlabCommon - PitchAngle: 0 deg
204783 | 0 - Piano Terra | Default - Calcestruzzo 0.1 m, Calcestruzzo 0.3 m | 874.249 | 161.244 | 349.7 | Livello: 0 - Piano Terra
204789 | 0 - Piano Terra | Default - Calcestruzzo 0.1 m, Calcestruzzo 0.3 m | 418.395 | 78.0152 | 167.36 | Livello: 0 - Piano Terra | Pset_SlabCommon - PitchAngle: 0 deg
204802 | 0 - Piano Terra | Default - Calcestruzzo 0.1 m, Calcestruzzo 0.3 m | 874.192 | 160.923 | 349.677 | Livello: 0 - Piano Terra
204809 | 0 - Piano Terra | Default - Calcestruzzo 0.1 m, Calcestruzzo 0.3 m | 398.557 | 118.877 | 159.423 | Livello: 0 - Piano Terra
204828 | 0 - Piano Terra | Default - Calcestruzzo 0.1 m, Calcestruzzo 0.3 m | 22.04 | 21 | 8.816 | Livello: 0 - Piano Terra | Pset_SlabCommon - PitchAngle: 0 deg
204934 | 2 - Piano Secondo | Default - Calcestruzzo 0.1 m, Calcestruzzo 0.3 m | 149.671 | 87.3417 | 59.8685 | Livello: 2 - Piano Secondo
205018 | 2 - Piano Secondo |  | 162.702 | 80.42 | 65.0809 | Livello: 2 - Piano Secondo | Modifica forma solaio - Condizione del bordo curvo: 1
205033 | 0 - Piano Terra |  | 173.72 | 85.2647 | 69.488 | Livello: 0 - Piano Terra | Modifica forma solaio - Condizione del bordo curvo: 1
205049 | 0 - Piano Terra |  | 172.271 | 85.0212 | 68.9084 | Livello: 0 - Piano Terra | Modifica forma solaio - Condizione del bordo curvo: 1
205060 | 1 - Piano Primo |  | 86.6793 | 54.3874 | 34.6717 | Livello: 1 - Piano Primo | Modifica forma solaio - Condizione del bordo curvo: 1
205095 | 1 - Piano Primo |  | 87.0488 | 54.5623 | 34.8195 | Livello: 1 - Piano Primo | Modifica forma solaio - Condizione del bordo curvo: 1

# IfcSlab: Pavimento:Marciapiede - 10 cm (11)
In: 2 - Piano Secondo
PredefinedType: FLOOR; Material: Asfalto, bitume 0.01 m, Sabbia e Calcestruzzo 0.09 m
Pset_SlabCommon - LoadBearing: yes; IsExternal: no; Reference: Marciapiede - 10 cm; ThermalTransmittance: 115 kg/K/s3
Altro - Categoria: Pavimenti; Famiglia: Pavimento: Marciapiede - 10 cm; Famiglia e tipo: Pavimento: Marciapiede - 10 cm; ID tipo: Pavimento: Marciapiede - 10 cm; Tipo: Pavimento: Marciapiede - 10 cm; Nome famiglia: Pavimento
Dimensioni - Spessore: 0.1 m
Fasi - Fase di creazione: Stato di Fatto
Strutturale - Attiva modello analitico: no; Strutturale: no
Vincoli - Delimita il locale: yes; Relativo a massa: no; Livello: Livello: 2 - Piano Secondo; Offset di altezza da livello: 0.1 m
Costruzione - Funzione: Interno; Spessore di default: 0.1 m
Dati identità - Nome del tipo: Marciapiede - 10 cm; Nota chiave: S/3
Grafica - Colore del retino a dettaglio basso: 0
Proprietà analitiche - Ruvidità: 3; Assorbimento: 0.7; Coefficiente di scambio termico (U): 115; Massa termica: 19572; Resistenza termica (R): 0.00869565
Name (Pavimento:Marciapiede - 10 cm:...) | PitchAngle (deg) | Area (m2) | Perimetro (m) | Volume (m3)
204464 | 0 | 4.10602 | 13.0903 | 0.410601
204471 | 0 | 3.70888 | 12.9903 | 0.370888
204956 | 0 | 3.53248 | 11.8585 | 0.353248
204962 | 0 | 3.74255 | 12.3675 | 0.374255
204971 | 0 | 30.5367 | 96.7073 | 3.05367
204981 | 0 | 31.1188 | 97.0502 | 3.11188
204989 | 0 | 4.93908 | 16.4972 | 0.493908
204999 | 0 | 31.1166 | 97.0434 | 3.11166
205008 | 0 | 31.4765 | 96.7034 | 3.14765
208501 |  | 0.379905 | 5.37809 | 0.0379892
208508 |  | 0.336855 | 5.22918 | 0.0336855

# IfcSlab: Pavimento:Pavimento container, Pavimento:Pavimento container:205889
In: 2 - Piano Secondo
PredefinedType: FLOOR; Material: Acciaio 0.1 m
Pset_SlabCommon - LoadBearing: yes; IsExternal: no; PitchAngle: 0 deg; Reference: Pavimento container; ThermalTransmittance: 450 kg/K/s3
Altro - Categoria: Pavimenti; Famiglia: Pavimento: Pavimento container; Famiglia e tipo: Pavimento: Pavimento container; ID tipo: Pavimento: Pavimento container; Tipo: Pavimento: Pavimento container; Nome famiglia: Pavimento
Dimensioni - Area: 14.6786 m2; Perimetro: 16.9277 m; Spessore: 0.1 m; Volume: 1.46786 m3
Fasi - Fase di creazione: Stato di Fatto
Strutturale - Attiva modello analitico: no; Strutturale: no
Vincoli - Delimita il locale: yes; Relativo a massa: no; Livello: Livello: 2 - Piano Secondo; Offset di altezza da livello: 0.1 m
Costruzione - Funzione: Interno; Spessore di default: 0.1 m
Dati identità - Nome del tipo: Pavimento container; Nota chiave: S/3
Grafica - Colore del retino a dettaglio basso: 0
Proprietà analitiche - Ruvidità: 3; Assorbimento: 0.7; Coefficiente di scambio termico (U): 450; Massa termica: 376800; Resistenza termica (R): 0.00222222

# IfcSlab: Pavimento:Predal Cementizio - 40 cm (6)
PredefinedType: FLOOR; Material: Default - Calcestruzzo 0.1 m, Calcestruzzo 0.3 m
Pset_SlabCommon - LoadBearing: yes; IsExternal: no; Reference: Predal Cementizio - 40 cm; ThermalTransmittance: 3.48667 kg/K/s3
Altro - Categoria: Pavimenti; Famiglia: Pavimento: Predal Cementizio - 40 cm; Famiglia e tipo: Pavimento: Predal Cementizio - 40 cm; ID tipo: Pavimento: Predal Cementizio - 40 cm; Tipo: Pavimento: Predal Cementizio - 40 cm; Nome famiglia: Pavimento
Dimensioni - Spessore: 0.4 m
Fasi - Fase di creazione: Stato di Fatto
Strutturale - Attiva modello analitico: no; Strutturale: no
Vincoli - Delimita il locale: yes; Relativo a massa: no; Offset di altezza da livello: 0 m
Costruzione - Funzione: Interno; Spessore di default: 0.4 m
Dati identità - Nome del tipo: Predal Cementizio - 40 cm; Nota chiave: S/3
Grafica - Colore del retino a dettaglio basso: 0
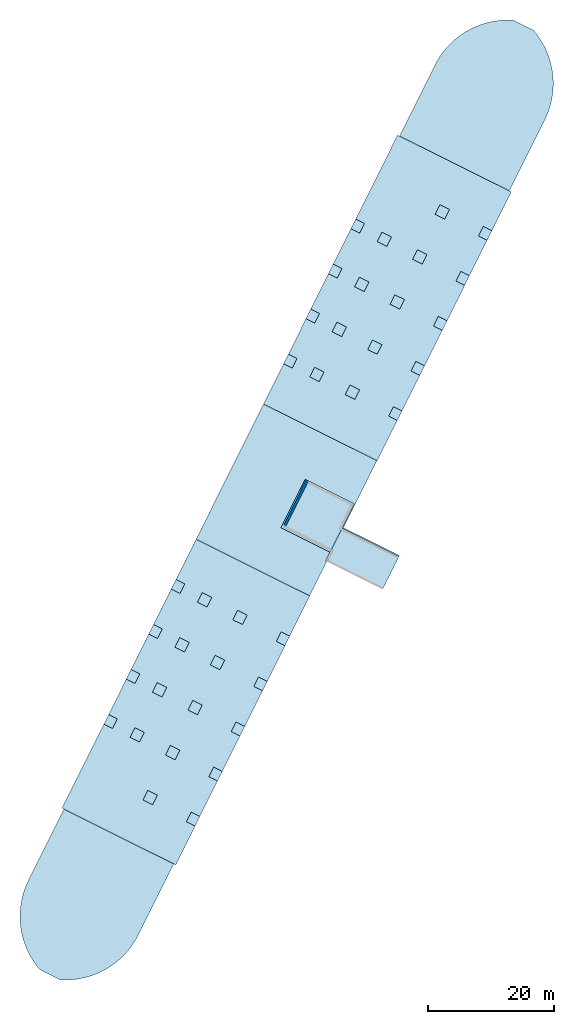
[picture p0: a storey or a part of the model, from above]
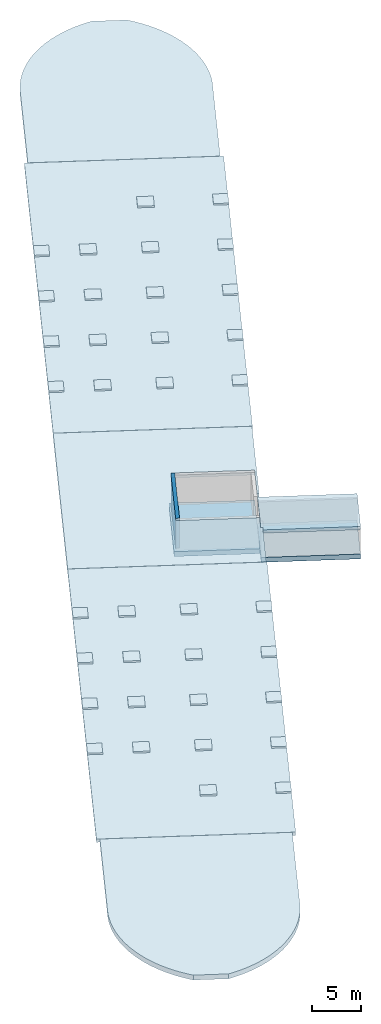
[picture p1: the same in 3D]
Properties of the parts of a building model (IFC2X3), part 5 of 7

# IfcSlab: Pavimento:Predal Cementizio - 40 cm (6)
Proprietà analitiche - Ruvidità: 3; Assorbimento: 0.7; Coefficiente di scambio termico (U): 3.48667; Massa termica: 453330; Resistenza termica (R): 0.286807
Name (Pavimento:Predal Cementizio - 40 cm:...) | In | Area (m2) | Perimetro (m) | Volume (m3) | Livello
204366 | 2 - Piano Secondo | 879.631 | 136.766 | 351.853 | Livello: 2 - Piano Secondo
204375 | 2 - Piano Secondo | 309.213 | 98.3652 | 123.685 | Livello: 2 - Piano Secondo
204389 | 2 - Piano Secondo | 879.566 | 136.759 | 351.827 | Livello: 2 - Piano Secondo
205063 | 1 - Piano Primo | 874.895 | 166.051 | 349.958 | Livello: 1 - Piano Primo
205070 | 1 - Piano Primo | 312.219 | 108.385 | 124.888 | Livello: 1 - Piano Primo | Modifica forma solaio - Condizione del bordo curvo: 1
205084 | 1 - Piano Primo | 874.93 | 163.939 | 349.972 | Livello: 1 - Piano Primo

# IfcSlab: Pavimento:Scala PT 40 cm (3)
In: 0 - Piano Terra
PredefinedType: FLOOR; Material: Asfalto, bitume 0.01 m, Sabbia e Calcestruzzo 0.09 m, Calcestruzzo 0.3 m
Pset_SlabCommon - LoadBearing: yes; IsExternal: no; PitchAngle: 0 deg; Reference: Scala PT 40 cm; ThermalTransmittance: 3.38407 kg/K/s3
Altro - Categoria: Pavimenti; Famiglia: Pavimento: Scala PT 40 cm; Famiglia e tipo: Pavimento: Scala PT 40 cm; ID tipo: Pavimento: Scala PT 40 cm; Tipo: Pavimento: Scala PT 40 cm; Nome famiglia: Pavimento
Dimensioni - Spessore: 0.4 m
Fasi - Fase di creazione: Stato di Fatto
Strutturale - Attiva modello analitico: no; Strutturale: no
Vincoli - Delimita il locale: yes; Relativo a massa: no; Livello: Livello: 0 - Piano Terra; Offset di altezza da livello: 0 m
Costruzione - Funzione: Interno; Spessore di default: 0.4 m
Dati identità - Nome del tipo: Scala PT 40 cm; Nota chiave: S/3
Grafica - Colore del retino a dettaglio basso: 0
Proprietà analitiche - Ruvidità: 3; Assorbimento: 0.7; Coefficiente di scambio termico (U): 3.38407; Massa termica: 472902; Resistenza termica (R): 0.295503
Name (Pavimento:Scala PT 40 cm:...) | Area (m2) | Perimetro (m) | Volume (m3)
204571 | 43.065 | 26.66 | 17.226
205681 | 43.065 | 26.66 | 17.226
205690 | 45.65 | 27.6 | 18.26

# IfcSlab: Pavimento:Scala PT 41 cm (3)
In: 1 - Piano Primo
PredefinedType: FLOOR; Material: Asfalto, bitume 0.01 m, Sabbia e Calcestruzzo 0.08 m, Calcestruzzo 0.4 m
Pset_SlabCommon - LoadBearing: yes; IsExternal: no; PitchAngle: 0 deg; Reference: Scala PT 41 cm; ThermalTransmittance: 2.55686 kg/K/s3
Altro - Categoria: Pavimenti; Famiglia: Pavimento: Scala PT 41 cm; Famiglia e tipo: Pavimento: Scala PT 41 cm; ID tipo: Pavimento: Scala PT 41 cm; Tipo: Pavimento: Scala PT 41 cm; Nome famiglia: Pavimento
Dimensioni - Spessore: 0.49 m
Fasi - Fase di creazione: Stato di Fatto
Strutturale - Attiva modello analitico: no; Strutturale: no
Vincoli - Delimita il locale: yes; Relativo a massa: no; Offset di altezza da livello: 0 m; Livello: Livello: 1 - Piano Primo
Costruzione - Funzione: Interno; Spessore di default: 0.49 m
Dati identità - Nome del tipo: Scala PT 41 cm; Nota chiave: S/3
Grafica - Colore del retino a dettaglio basso: 0
Proprietà analitiche - Ruvidità: 3; Assorbimento: 0.7; Coefficiente di scambio termico (U): 2.55686; Massa termica: 624012; Resistenza termica (R): 0.391105
Name (Pavimento:Scala PT 41 cm:...) | Area (m2) | Perimetro (m) | Volume (m3)
204586 | 12.6989 | 17.0803 | 6.22246
205388 | 12.6989 | 17.0803 | 6.22246
205699 | 14.9925 | 18.0203 | 7.34633

# IfcSlab: Pavimento:Solaio scala P2 41 cm (3)
In: 2 - Piano Secondo
PredefinedType: FLOOR; Material: Asfalto, bitume 0.01 m, Sabbia e Calcestruzzo 0.05 m, Calcestruzzo 0.35 m
Pset_SlabCommon - LoadBearing: yes; IsExternal: no; PitchAngle: 0 deg; Reference: Solaio scala P2 41 cm; ThermalTransmittance: 2.91287 kg/K/s3
Altro - Categoria: Pavimenti; Famiglia: Pavimento: Solaio scala P2 41 cm; Famiglia e tipo: Pavimento: Solaio scala P2 41 cm; ID tipo: Pavimento: Solaio scala P2 41 cm; Tipo: Pavimento: Solaio scala P2 41 cm; Nome famiglia: Pavimento
Dimensioni - Spessore: 0.41 m
Fasi - Fase di creazione: Stato di Fatto
Strutturale - Attiva modello analitico: no; Strutturale: no
Vincoli - Delimita il locale: yes; Relativo a massa: no; Offset di altezza da livello: 0 m; Livello: Livello: 2 - Piano Secondo
Costruzione - Funzione: Interno; Spessore di default: 0.41 m
Dati identità - Nome del tipo: Solaio scala P2 41 cm; Nota chiave: S/3
Grafica - Colore del retino a dettaglio basso: 0
Proprietà analitiche - Ruvidità: 3; Assorbimento: 0.7; Coefficiente di scambio termico (U): 2.91287; Massa termica: 548457; Resistenza termica (R): 0.343304
Name (Pavimento:Solaio scala P2 41 cm:...) | Area (m2) | Perimetro (m) | Volume (m3)
204581 | 14.56 | 15.74 | 5.9696
205398 | 14.56 | 15.7603 | 5.9696
205446 | 16.8238 | 16.66 | 6.89776

# IfcSlab: Pavimento:TRavi prefabbricate - 26 cm (2)
PredefinedType: FLOOR; Material: Default - Calcestruzzo 0.26 m
Pset_SlabCommon - LoadBearing: yes; IsExternal: no; PitchAngle: 0 deg; Reference: TRavi prefabbricate - 26 cm
Altro - Categoria: Pavimenti; Famiglia: Pavimento: TRavi prefabbricate - 26 cm; Famiglia e tipo: Pavimento: TRavi prefabbricate - 26 cm; ID tipo: Pavimento: TRavi prefabbricate - 26 cm; Tipo: Pavimento: TRavi prefabbricate - 26 cm; Nome famiglia: Pavimento
Dimensioni - Area: 4.55915 m2; Perimetro: 16.3972 m; Spessore: 0.26 m; Volume: 1.18538 m3
Fasi - Fase di creazione: Stato di Fatto
Strutturale - Attiva modello analitico: no; Strutturale: no
Vincoli - Delimita il locale: yes; Relativo a massa: no
Costruzione - Funzione: Interno; Spessore di default: 0.26 m
Dati identità - Nome del tipo: TRavi prefabbricate - 26 cm; Nota chiave: S/3
Grafica - Colore del retino a dettaglio basso: 0
Proprietà analitiche - Ruvidità: 3; Assorbimento: 0.7
Name (Pavimento:TRavi prefabbricate - 26 cm:...) | In | Livello | Offset di altezza da livello (m)
205783 | 0 - Piano Terra | Livello: 0 - Piano Terra | 4.29
205800 | 1 - Piano Primo | Livello: 1 - Piano Primo | 3.52

# IfcSlab: Pavimento:Travi in opera - 40 cm (2)
In: 0 - Piano Terra
PredefinedType: FLOOR; Material: Calcestruzzo 0.4 m
Pset_SlabCommon - LoadBearing: yes; IsExternal: no; PitchAngle: 0 deg; Reference: Travi in opera - 40 cm; ThermalTransmittance: 2.615 kg/K/s3
Altro - Categoria: Pavimenti; Famiglia: Pavimento: Travi in opera - 40 cm; Famiglia e tipo: Pavimento: Travi in opera - 40 cm; ID tipo: Pavimento: Travi in opera - 40 cm; Tipo: Pavimento: Travi in opera - 40 cm; Nome famiglia: Pavimento
Dimensioni - Spessore: 0.4 m
Fasi - Fase di creazione: Stato di Fatto
Strutturale - Attiva modello analitico: no; Strutturale: no
Vincoli - Delimita il locale: yes; Relativo a massa: no; Livello: Livello: 0 - Piano Terra; Offset di altezza da livello: 4.29 m
Costruzione - Funzione: Interno; Spessore di default: 0.4 m
Dati identità - Nome del tipo: Travi in opera - 40 cm; Nota chiave: S/3
Grafica - Colore del retino a dettaglio basso: 0
Proprietà analitiche - Ruvidità: 3; Assorbimento: 0.7; Coefficiente di scambio termico (U): 2.615; Massa termica: 604440; Resistenza termica (R): 0.382409
Name (Pavimento:Travi in opera - 40 cm:...) | Area (m2) | Perimetro (m) | Volume (m3)
205776 | 2.34312 | 12.5236 | 0.937249
205793 | 2.34048 | 12.5095 | 0.936193

# IfcSlab: Tetto di base:Container - 5 cm, Tetto di base:Container - 5 cm:205898
In: 2 - Piano Secondo
PredefinedType: ROOF; Material: Acciaio 0.05 m
Pset_SlabCommon - LoadBearing: yes; IsExternal: yes; PitchAngle: 0 deg; Reference: Container - 5 cm; ThermalTransmittance: 900 kg/K/s3

# IfcSlab: Tetto di base:Finitura Cementizio - 15 cm, Tetto di base:Finitura Cementizio - 15 cm:204404
In: 2 - Piano Secondo
PredefinedType: ROOF; Material: Calcestruzzo 0.15 m
Pset_SlabCommon - LoadBearing: yes; IsExternal: yes; PitchAngle: 0 deg; Reference: Finitura Cementizio - 15 cm; ThermalTransmittance: 6.97333 kg/K/s3

# IfcSlab: Tetto di base:Lamierino - 1 cm (3)
PredefinedType: ROOF; Material: Alluminio 0.005 m
Pset_SlabCommon - LoadBearing: yes; IsExternal: yes; Reference: Lamierino - 1 cm; ThermalTransmittance: 46000 kg/K/s3
Name (Tetto di base:Lamierino - 1 cm:...) | In | PitchAngle (deg)
204499 | 3 - Piano Copertura | 5.54603
204534 | 3 - Piano Copertura | 6.86141
205833 | 0 - Piano Terra | 0

# IfcSlab: Tetto di base:Ondulina - 6 cm (2)
In: 3 - Piano Copertura
PredefinedType: ROOF; Material: Plastica 0.06 m
Pset_SlabCommon - LoadBearing: yes; IsExternal: yes; Reference: Ondulina - 6 cm; ThermalTransmittance: 8.36667 kg/K/s3
Name (Tetto di base:Ondulina - 6 cm:...) | PitchAngle (deg)
205753 | 5.55
205764 | 6.86

# IfcStair: Scala:Cls - Rivertita di gomma:167849 (12)
Name (Scala:Cls - Rivertita di gomma:...) | In
204595 | 1 - Piano Primo | Material: Default - Calcestruzzo, <Unnamed>
204595 | 1 - Piano Primo | Pset_StairCommon - IsExternal: no; Reference: Cls - Rivertita di gomma; NumberOfRiser: 25; NumberOfTreads: 24; RiserHeight: 0.1568 m; TreadLength: 0.3 m; Altro - Categoria: Scale; Famiglia: Scala: Cls - Rivertita di gomma; Famiglia e tipo: Scala: Cls - Rivertita di gomma; ID tipo: Scala: Cls - Rivertita di gomma; Tipo: Scala: Cls - Rivertita di gomma; Nome famiglia: Scala; Dimensioni - Altezza effettiva alzata: 0.1568 m; Larghezza: 1 m; Numero di alzate desiderato: 25; Numero di alzate effettivamente presenti: 25; Profondità effettiva pedata: 0.3 m; Fasi - Fase di creazione: Stato di Fatto; Grafica - Etichetta GIÙ: yes; Etichetta SU: yes; Freccia GIÙ: yes; Freccia SU: yes; Mostra freccia SU in tutte le viste: no; Testo GIÙ: GIÙ; Testo SU: SU; Dimensione del testo: 0.0082021; Simbolo di interruzione in pianta: yes; Tipo di carattere del testo: Arial; Strutturale - Copriferro armatura: Impostazioni copriferro armatura: Copriferro armatura 1; Vincoli - Offset base: 0 m; Livello di base: Livello: 1 - Piano Primo; Livello superiore: Livello: 1 - Piano Primo; Offset superiore: 3.92 m; Alzate - Connessione alzata-pedata: Estendi alzata oltre la pedata; Inizia con alzata: yes; Spessore alzata: 0.005 m; Termina con alzata: yes; Tipo di alzata: Obliquo; Costruzione - Funzione: Interno; Estendi sotto la base: 0 m; Parte inferiore del montante: Liscio; Raccordo pianerottolo: 0.075 m; Scale monolitiche: yes; Dati identità - Nome del tipo: Cls - Rivertita di gomma; Nota chiave: Sc/1; Materiali e finiture - Materiale alzata: Asfalto, bitume; Materiale della scala monolitica: Default - Calcestruzzo; Materiale montante scala: Acciaio; Materiale pedata: Asfalto, bitume; Montanti scala - Altezza montante intradosso scala: 0.15 m; Altezza montante pianerottolo: 0.301412 m; Altezza montante scala: 0.4 m; Montante destro: Aperto; Montante sinistro: Aperto; Montanti centrali: 0; Offset montante scala aperto: 0 m; Spessore montante scala: 0.05 m; Taglia montanti alla sommità: Non tagliare; Pedate - Applica profilo di aggetto: Solo davanti; Lunghezza dell'aggetto: 0.005 m; Spessore della pedata: 0.005 m; Regole di calcolo - Altezza massima alzata: 0.175 m; Profondità minima pedata: 0.3 m
204675 | 0 - Piano Terra | Material: Default - Calcestruzzo, <Unnamed>
204675 | 0 - Piano Terra | Pset_StairCommon - IsExternal: no; Reference: Cls - Rivertita di gomma; NumberOfRiser: 29; NumberOfTreads: 28; RiserHeight: 0.161724 m; TreadLength: 0.3 m; Altro - Categoria: Scale; Famiglia: Scala: Cls - Rivertita di gomma; Famiglia e tipo: Scala: Cls - Rivertita di gomma; ID tipo: Scala: Cls - Rivertita di gomma; Tipo: Scala: Cls - Rivertita di gomma; Nome famiglia: Scala; Dimensioni - Altezza effettiva alzata: 0.161724 m; Larghezza: 1 m; Numero di alzate desiderato: 29; Numero di alzate effettivamente presenti: 29; Profondità effettiva pedata: 0.3 m; Fasi - Fase di creazione: Stato di Fatto; Grafica - Etichetta GIÙ: yes; Etichetta SU: yes; Freccia GIÙ: yes; Freccia SU: yes; Mostra freccia SU in tutte le viste: no; Testo GIÙ: GIÙ; Testo SU: SU; Dimensione del testo: 0.0082021; Simbolo di interruzione in pianta: yes; Tipo di carattere del testo: Arial; Strutturale - Copriferro armatura: Impostazioni copriferro armatura: Copriferro armatura 1; Vincoli - Offset base: 0 m; Livello di base: Livello: 0 - Piano Terra; Livello superiore: Livello: 0 - Piano Terra; Offset superiore: 4.69 m; Alzate - Connessione alzata-pedata: Estendi alzata oltre la pedata; Inizia con alzata: yes; Spessore alzata: 0.005 m; Termina con alzata: yes; Tipo di alzata: Obliquo; Costruzione - Funzione: Interno; Estendi sotto la base: 0 m; Parte inferiore del montante: Liscio; Raccordo pianerottolo: 0.075 m; Scale monolitiche: yes; Dati identità - Nome del tipo: Cls - Rivertita di gomma; Nota chiave: Sc/1; Materiali e finiture - Materiale alzata: Asfalto, bitume; Materiale della scala monolitica: Default - Calcestruzzo; Materiale montante scala: Acciaio; Materiale pedata: Asfalto, bitume; Montanti scala - Altezza montante intradosso scala: 0.15 m; Altezza montante pianerottolo: 0.301412 m; Altezza montante scala: 0.4 m; Montante destro: Aperto; Montante sinistro: Aperto; Montanti centrali: 0; Offset montante scala aperto: 0 m; Spessore montante scala: 0.05 m; Taglia montanti alla sommità: Non tagliare; Pedate - Applica profilo di aggetto: Solo davanti; Lunghezza dell'aggetto: 0.005 m; Spessore della pedata: 0.005 m; Regole di calcolo - Altezza massima alzata: 0.175 m; Profondità minima pedata: 0.3 m
205115 | 0 - Piano Terra | Material: Default - Calcestruzzo, <Unnamed>
205115 | 0 - Piano Terra | Pset_StairCommon - IsExternal: no; Reference: Cls - Rivertita di gomma; NumberOfRiser: 29; NumberOfTreads: 28; RiserHeight: 0.161724 m; TreadLength: 0.3 m; Altro - Categoria: Scale; Famiglia: Scala: Cls - Rivertita di gomma; Famiglia e tipo: Scala: Cls - Rivertita di gomma; ID tipo: Scala: Cls - Rivertita di gomma; Tipo: Scala: Cls - Rivertita di gomma; Nome famiglia: Scala; Dimensioni - Altezza effettiva alzata: 0.161724 m; Larghezza: 1 m; Numero di alzate desiderato: 29; Numero di alzate effettivamente presenti: 29; Profondità effettiva pedata: 0.3 m; Fasi - Fase di creazione: Stato di Fatto; Grafica - Etichetta GIÙ: yes; Etichetta SU: yes; Freccia GIÙ: yes; Freccia SU: yes; Mostra freccia SU in tutte le viste: no; Testo GIÙ: GIÙ; Testo SU: SU; Dimensione del testo: 0.0082021; Simbolo di interruzione in pianta: yes; Tipo di carattere del testo: Arial; Strutturale - Copriferro armatura: Impostazioni copriferro armatura: Copriferro armatura 1; Vincoli - Offset base: 0 m; Livello di base: Livello: 0 - Piano Terra; Livello superiore: Livello: 0 - Piano Terra; Offset superiore: 4.69 m; Alzate - Connessione alzata-pedata: Estendi alzata oltre la pedata; Inizia con alzata: yes; Spessore alzata: 0.005 m; Termina con alzata: yes; Tipo di alzata: Obliquo; Costruzione - Funzione: Interno; Estendi sotto la base: 0 m; Parte inferiore del montante: Liscio; Raccordo pianerottolo: 0.075 m; Scale monolitiche: yes; Dati identità - Nome del tipo: Cls - Rivertita di gomma; Nota chiave: Sc/1; Materiali e finiture - Materiale alzata: Asfalto, bitume; Materiale della scala monolitica: Default - Calcestruzzo; Materiale montante scala: Acciaio; Materiale pedata: Asfalto, bitume; Montanti scala - Altezza montante intradosso scala: 0.15 m; Altezza montante pianerottolo: 0.301412 m; Altezza montante scala: 0.4 m; Montante destro: Aperto; Montante sinistro: Aperto; Montanti centrali: 0; Offset montante scala aperto: 0 m; Spessore montante scala: 0.05 m; Taglia montanti alla sommità: Non tagliare; Pedate - Applica profilo di aggetto: Solo davanti; Lunghezza dell'aggetto: 0.005 m; Spessore della pedata: 0.005 m; Regole di calcolo - Altezza massima alzata: 0.175 m; Profondità minima pedata: 0.3 m
205262 | 1 - Piano Primo | Material: Default - Calcestruzzo, <Unnamed>
205262 | 1 - Piano Primo | Pset_StairCommon - IsExternal: no; Reference: Cls - Rivertita di gomma; NumberOfRiser: 25; NumberOfTreads: 24; RiserHeight: 0.1568 m; TreadLength: 0.3 m; Altro - Categoria: Scale; Famiglia: Scala: Cls - Rivertita di gomma; Famiglia e tipo: Scala: Cls - Rivertita di gomma; ID tipo: Scala: Cls - Rivertita di gomma; Tipo: Scala: Cls - Rivertita di gomma; Nome famiglia: Scala; Dimensioni - Altezza effettiva alzata: 0.1568 m; Larghezza: 1 m; Numero di alzate desiderato: 25; Numero di alzate effettivamente presenti: 25; Profondità effettiva pedata: 0.3 m; Fasi - Fase di creazione: Stato di Fatto; Grafica - Etichetta GIÙ: yes; Etichetta SU: yes; Freccia GIÙ: yes; Freccia SU: yes; Mostra freccia SU in tutte le viste: no; Testo GIÙ: GIÙ; Testo SU: SU; Dimensione del testo: 0.0082021; Simbolo di interruzione in pianta: yes; Tipo di carattere del testo: Arial; Strutturale - Copriferro armatura: Impostazioni copriferro armatura: Copriferro armatura 1; Vincoli - Offset base: 0 m; Livello di base: Livello: 1 - Piano Primo; Livello superiore: Livello: 1 - Piano Primo; Offset superiore: 3.92 m; Alzate - Connessione alzata-pedata: Estendi alzata oltre la pedata; Inizia con alzata: yes; Spessore alzata: 0.005 m; Termina con alzata: yes; Tipo di alzata: Obliquo; Costruzione - Funzione: Interno; Estendi sotto la base: 0 m; Parte inferiore del montante: Liscio; Raccordo pianerottolo: 0.075 m; Scale monolitiche: yes; Dati identità - Nome del tipo: Cls - Rivertita di gomma; Nota chiave: Sc/1; Materiali e finiture - Materiale alzata: Asfalto, bitume; Materiale della scala monolitica: Default - Calcestruzzo; Materiale montante scala: Acciaio; Materiale pedata: Asfalto, bitume; Montanti scala - Altezza montante intradosso scala: 0.15 m; Altezza montante pianerottolo: 0.301412 m; Altezza montante scala: 0.4 m; Montante destro: Aperto; Montante sinistro: Aperto; Montanti centrali: 0; Offset montante scala aperto: 0 m; Spessore montante scala: 0.05 m; Taglia montanti alla sommità: Non tagliare; Pedate - Applica profilo di aggetto: Solo davanti; Lunghezza dell'aggetto: 0.005 m; Spessore della pedata: 0.005 m; Regole di calcolo - Altezza massima alzata: 0.175 m; Profondità minima pedata: 0.3 m
205404 | 1 - Piano Primo | Material: Default - Calcestruzzo, <Unnamed>
205404 | 1 - Piano Primo | Pset_StairCommon - IsExternal: no; Reference: Cls - Rivertita di gomma; NumberOfRiser: 25; NumberOfTreads: 24; RiserHeight: 0.1568 m; TreadLength: 0.3 m; Altro - Categoria: Scale; Famiglia: Scala: Cls - Rivertita di gomma; Famiglia e tipo: Scala: Cls - Rivertita di gomma; ID tipo: Scala: Cls - Rivertita di gomma; Tipo: Scala: Cls - Rivertita di gomma; Nome famiglia: Scala; Dimensioni - Altezza effettiva alzata: 0.1568 m; Larghezza: 1 m; Numero di alzate desiderato: 25; Numero di alzate effettivamente presenti: 25; Profondità effettiva pedata: 0.3 m; Fasi - Fase di creazione: Stato di Fatto; Grafica - Etichetta GIÙ: yes; Etichetta SU: yes; Freccia GIÙ: yes; Freccia SU: yes; Mostra freccia SU in tutte le viste: no; Testo GIÙ: GIÙ; Testo SU: SU; Dimensione del testo: 0.0082021; Simbolo di interruzione in pianta: yes; Tipo di carattere del testo: Arial; Strutturale - Copriferro armatura: Impostazioni copriferro armatura: Copriferro armatura 1; Vincoli - Offset base: 0 m; Livello di base: Livello: 1 - Piano Primo; Livello superiore: Livello: 1 - Piano Primo; Offset superiore: 3.92 m; Alzate - Connessione alzata-pedata: Estendi alzata oltre la pedata; Inizia con alzata: yes; Spessore alzata: 0.005 m; Termina con alzata: yes; Tipo di alzata: Obliquo; Costruzione - Funzione: Interno; Estendi sotto la base: 0 m; Parte inferiore del montante: Liscio; Raccordo pianerottolo: 0.075 m; Scale monolitiche: yes; Dati identità - Nome del tipo: Cls - Rivertita di gomma; Nota chiave: Sc/1; Materiali e finiture - Materiale alzata: Asfalto, bitume; Materiale della scala monolitica: Default - Calcestruzzo; Materiale montante scala: Acciaio; Materiale pedata: Asfalto, bitume; Montanti scala - Altezza montante intradosso scala: 0.15 m; Altezza montante pianerottolo: 0.301412 m; Altezza montante scala: 0.4 m; Montante destro: Aperto; Montante sinistro: Aperto; Montanti centrali: 0; Offset montante scala aperto: 0 m; Spessore montante scala: 0.05 m; Taglia montanti alla sommità: Non tagliare; Pedate - Applica profilo di aggetto: Solo davanti; Lunghezza dell'aggetto: 0.005 m; Spessore della pedata: 0.005 m; Regole di calcolo - Altezza massima alzata: 0.175 m; Profondità minima pedata: 0.3 m
205535 | 0 - Piano Terra | Material: Default - Calcestruzzo, <Unnamed>
205535 | 0 - Piano Terra | Pset_StairCommon - IsExternal: no; Reference: Cls - Rivertita di gomma; NumberOfRiser: 29; NumberOfTreads: 28; RiserHeight: 0.161724 m; TreadLength: 0.3 m; Altro - Categoria: Scale; Famiglia: Scala: Cls - Rivertita di gomma; Famiglia e tipo: Scala: Cls - Rivertita di gomma; ID tipo: Scala: Cls - Rivertita di gomma; Tipo: Scala: Cls - Rivertita di gomma; Nome famiglia: Scala; Dimensioni - Altezza effettiva alzata: 0.161724 m; Larghezza: 1 m; Numero di alzate desiderato: 29; Numero di alzate effettivamente presenti: 29; Profondità effettiva pedata: 0.3 m; Fasi - Fase di creazione: Stato di Fatto; Grafica - Etichetta GIÙ: yes; Etichetta SU: yes; Freccia GIÙ: yes; Freccia SU: yes; Mostra freccia SU in tutte le viste: no; Testo GIÙ: GIÙ; Testo SU: SU; Dimensione del testo: 0.0082021; Simbolo di interruzione in pianta: yes; Tipo di carattere del testo: Arial; Strutturale - Copriferro armatura: Impostazioni copriferro armatura: Copriferro armatura 1; Vincoli - Offset base: 0 m; Livello di base: Livello: 0 - Piano Terra; Livello superiore: Livello: 0 - Piano Terra; Offset superiore: 4.69 m; Alzate - Connessione alzata-pedata: Estendi alzata oltre la pedata; Inizia con alzata: yes; Spessore alzata: 0.005 m; Termina con alzata: yes; Tipo di alzata: Obliquo; Costruzione - Funzione: Interno; Estendi sotto la base: 0 m; Parte inferiore del montante: Liscio; Raccordo pianerottolo: 0.075 m; Scale monolitiche: yes; Dati identità - Nome del tipo: Cls - Rivertita di gomma; Nota chiave: Sc/1; Materiali e finiture - Materiale alzata: Asfalto, bitume; Materiale della scala monolitica: Default - Calcestruzzo; Materiale montante scala: Acciaio; Materiale pedata: Asfalto, bitume; Montanti scala - Altezza montante intradosso scala: 0.15 m; Altezza montante pianerottolo: 0.301412 m; Altezza montante scala: 0.4 m; Montante destro: Aperto; Montante sinistro: Aperto; Montanti centrali: 0; Offset montante scala aperto: 0 m; Spessore montante scala: 0.05 m; Taglia montanti alla sommità: Non tagliare; Pedate - Applica profilo di aggetto: Solo davanti; Lunghezza dell'aggetto: 0.005 m; Spessore della pedata: 0.005 m; Regole di calcolo - Altezza massima alzata: 0.175 m; Profondità minima pedata: 0.3 m

# IfcSystem: Aria di mandata (4)
Altro - Categoria: Sistema di condotti; Famiglia: Sistema di condotti: Aria di mandata; Famiglia e tipo: Sistema di condotti: Aria di mandata; ID tipo: Sistema di condotti: Aria di mandata; Tipo: Sistema di condotti: Aria di mandata
Meccanica - Numero di elementi: 0
Meccanico - Flusso - Flusso: 0 m3/s
Name | Nome sistema
Meccanica Aria di mandata 1 | Meccanica Aria di mandata 1
Meccanica Aria di mandata 10 | Meccanica Aria di mandata 10
Meccanica Aria di mandata 11 | Meccanica Aria di mandata 11
Meccanica Aria di mandata 12 | Meccanica Aria di mandata 12

# IfcSystem: Mandata sistema idronico (20)
Altro - Categoria: Sistema di tubazioni; Famiglia: Sistema di tubazioni: Mandata sistema idronico; Famiglia e tipo: Sistema di tubazioni: Mandata sistema idronico; ID tipo: Sistema di tubazioni: Mandata sistema idronico; Tipo: Sistema di tubazioni: Mandata sistema idronico
Meccanica - Numero di elementi: 0
Meccanico - Flusso - Flusso: 0 m3/s
Name | Nome sistema | Volume (m3)
Mandata sistema idronico 11 | Mandata sistema idronico 11 | 0.121254
Mandata sistema idronico 22 | Mandata sistema idronico 22 | 0.131275
Mandata sistema idronico 30 | Mandata sistema idronico 30 | 0.51151
Mandata sistema idronico 26 | Mandata sistema idronico 26 | 0.0247115
Mandata sistema idronico 32 | Mandata sistema idronico 32 | 0.816904
Mandata sistema idronico 35 | Mandata sistema idronico 35 | 0.00797507
Mandata sistema idronico 34 | Mandata sistema idronico 34 | 0.0230189
Mandata sistema idronico 38 | Mandata sistema idronico 38 | 0.0892365
Mandata sistema idronico 39 | Mandata sistema idronico 39 | 2.90794
Mandata sistema idronico 40 | Mandata sistema idronico 40 | 0.761399
Mandata sistema idronico 41 | Mandata sistema idronico 41 | 0.149481
Mandata sistema idronico 50 | Mandata sistema idronico 50 | 0.00748637
Mandata sistema idronico 54 | Mandata sistema idronico 54 | 0.00617931
Mandata sistema idronico 51 | Mandata sistema idronico 51 | 0.0593347
Mandata sistema idronico 46 | Mandata sistema idronico 46 | 0.0060455
Mandata sistema idronico 55 | Mandata sistema idronico 55 | 0.0319201
Mandata sistema idronico 56 | Mandata sistema idronico 56 | 0.0303617
Mandata sistema idronico 57 | Mandata sistema idronico 57 | 0.0303617
Mandata sistema idronico 58 | Mandata sistema idronico 58 | 0.0319201
Mandata sistema idronico 59 | Mandata sistema idronico 59 | 0.0319201

# IfcWall: Muri 10:Muri 10, Muri 10:Muri 10:207934
In: 2 - Piano Secondo
Type - Material: Calcestruzzo, gettato in opera
Type - Altro - Categoria: Muri; Nome famiglia: Muri 10
Type - Dati identità - Nome del tipo: Muri 10
Altro - Famiglia: Muri 10: Muri 10; Famiglia e tipo: Muri 10: Muri 10; ID tipo: Muri 10: Muri 10; Tipo: Muri 10: Muri 10
Dimensioni - Area: 1.09106 m2; Volume: 0.752808 m3
Fasi - Fase di creazione: Stato di Fatto
Vincoli - Delimita il locale: yes; Prospetto: 0 m; Sposta con l'oggetto più vicino: no
Pset_WallCommon - ExtendToStructure: no; IsExternal: no; LoadBearing: no; Reference: Muri 10

# IfcWall: Muri 1:Muri 1, Muri 1:Muri 1:207406
In: 2 - Piano Secondo
Type - Material: Calcestruzzo, gettato in opera
Type - Altro - Categoria: Muri; Nome famiglia: Muri 1
Type - Dati identità - Nome del tipo: Muri 1
Altro - Famiglia: Muri 1: Muri 1; Famiglia e tipo: Muri 1: Muri 1; ID tipo: Muri 1: Muri 1; Tipo: Muri 1: Muri 1
Dimensioni - Area: 2.44384 m2; Volume: 2.51715 m3
Fasi - Fase di creazione: Stato di Fatto
Vincoli - Delimita il locale: yes; Prospetto: 0 m; Sposta con l'oggetto più vicino: no
Pset_WallCommon - LoadBearing: yes; ExtendToStructure: no; IsExternal: no; Reference: Muri 1

# IfcWall: Muri 2:Muri 2, Muri 2:Muri 2:207602
In: 2 - Piano Secondo
Type - Material: Calcestruzzo, gettato in opera
Type - Altro - Categoria: Muri; Nome famiglia: Muri 2
Type - Dati identità - Nome del tipo: Muri 2
Altro - Famiglia: Muri 2: Muri 2; Famiglia e tipo: Muri 2: Muri 2; ID tipo: Muri 2: Muri 2; Tipo: Muri 2: Muri 2
Dimensioni - Area: 1.06574 m2; Volume: 0.735329 m3
Fasi - Fase di creazione: Stato di Fatto
Vincoli - Delimita il locale: yes; Prospetto: 0 m; Sposta con l'oggetto più vicino: no
Pset_WallCommon - ExtendToStructure: no; IsExternal: no; LoadBearing: no; Reference: Muri 2

# IfcWall: Muri 3:Muri 3, Muri 3:Muri 3:207616
In: 2 - Piano Secondo
Type - Material: Calcestruzzo, gettato in opera
Type - Altro - Categoria: Muri; Nome famiglia: Muri 3
Type - Dati identità - Nome del tipo: Muri 3
Altro - Famiglia: Muri 3: Muri 3; Famiglia e tipo: Muri 3: Muri 3; ID tipo: Muri 3: Muri 3; Tipo: Muri 3: Muri 3
Dimensioni - Area: 1.12261 m2; Volume: 0.774514 m3
Fasi - Fase di creazione: Stato di Fatto
Vincoli - Delimita il locale: yes; Prospetto: 0 m; Sposta con l'oggetto più vicino: no
Pset_WallCommon - ExtendToStructure: no; IsExternal: no; LoadBearing: no; Reference: Muri 3

# IfcWall: Muri 4:Muri 4, Muri 4:Muri 4:207679
In: 0 - Piano Terra
Type - Material: Calcestruzzo, gettato in opera
Type - Altro - Categoria: Muri; Nome famiglia: Muri 4
Type - Dati identità - Nome del tipo: Muri 4
Altro - Famiglia: Muri 4: Muri 4; Famiglia e tipo: Muri 4: Muri 4; ID tipo: Muri 4: Muri 4; Tipo: Muri 4: Muri 4
Dimensioni - Area: 7.31009 m2; Volume: 34.2846 m3
Fasi - Fase di creazione: Stato di Fatto
Vincoli - Delimita il locale: yes; Prospetto: 0 m; Sposta con l'oggetto più vicino: no
Pset_WallCommon - ExtendToStructure: no; IsExternal: no; LoadBearing: no; Reference: Muri 4

# IfcWall: Muri 5:Muri 5, Muri 5:Muri 5:207717
In: 0 - Piano Terra
Type - Material: Calcestruzzo, gettato in opera
Type - Altro - Categoria: Muri; Nome famiglia: Muri 5
Type - Dati identità - Nome del tipo: Muri 5
Altro - Famiglia: Muri 5: Muri 5; Famiglia e tipo: Muri 5: Muri 5; ID tipo: Muri 5: Muri 5; Tipo: Muri 5: Muri 5
Dimensioni - Area: 29.5844 m2; Volume: 138.753 m3
Fasi - Fase di creazione: Stato di Fatto
Vincoli - Delimita il locale: yes; Prospetto: 0 m; Sposta con l'oggetto più vicino: no
Pset_WallCommon - ExtendToStructure: no; IsExternal: no; LoadBearing: no; Reference: Muri 5

# IfcWall: Muri 7:Muri 7, Muri 7:Muri 7:207758
In: 1 - Piano Primo
Type - Material: Calcestruzzo, gettato in opera
Type - Altro - Categoria: Muri; Nome famiglia: Muri 7
Type - Dati identità - Nome del tipo: Muri 7
Altro - Famiglia: Muri 7: Muri 7; Famiglia e tipo: Muri 7: Muri 7; ID tipo: Muri 7: Muri 7; Tipo: Muri 7: Muri 7
Dimensioni - Area: 40.2114 m2; Volume: 141.553 m3
Fasi - Fase di creazione: Stato di Fatto
Vincoli - Delimita il locale: yes; Prospetto: 0 m; Sposta con l'oggetto più vicino: no
Pset_WallCommon - ExtendToStructure: no; IsExternal: no; LoadBearing: no; Reference: Muri 7

# IfcWall: Muri 8:Muri 8, Muri 8:Muri 8:207810
In: 1 - Piano Primo
Type - Material: Calcestruzzo, gettato in opera
Type - Altro - Categoria: Muri; Nome famiglia: Muri 8
Type - Dati identità - Nome del tipo: Muri 8
Altro - Famiglia: Muri 8: Muri 8; Famiglia e tipo: Muri 8: Muri 8; ID tipo: Muri 8: Muri 8; Tipo: Muri 8: Muri 8
Dimensioni - Area: 40.1497 m2; Volume: 57.4042 m3
Fasi - Fase di creazione: Stato di Fatto
Vincoli - Delimita il locale: yes; Sposta con l'oggetto più vicino: no
Pset_WallCommon - ExtendToStructure: no; IsExternal: no; LoadBearing: no; Reference: Muri 8

# IfcWall: Muri 9:Muri 9, Muri 9:Muri 9:207920
In: 2 - Piano Secondo
Type - Material: Calcestruzzo, gettato in opera
Type - Altro - Categoria: Muri; Nome famiglia: Muri 9
Type - Dati identità - Nome del tipo: Muri 9
Altro - Famiglia: Muri 9: Muri 9; Famiglia e tipo: Muri 9: Muri 9; ID tipo: Muri 9: Muri 9; Tipo: Muri 9: Muri 9
Dimensioni - Area: 1.0803 m2; Volume: 0.745407 m3
Fasi - Fase di creazione: Stato di Fatto
Vincoli - Delimita il locale: yes; Prospetto: 0 m; Sposta con l'oggetto più vicino: no
Pset_WallCommon - ExtendToStructure: no; IsExternal: no; LoadBearing: no; Reference: Muri 9

# IfcWall: Muro di base:Blocchetti - 20 cm (3)
In: 0 - Piano Terra
Type - PredefinedType: STANDARD; Material: Sabbia e Calcestruzzo 0.2 m
Type - Altro - Categoria: Muri; Nome famiglia: Muro di base
Type - Costruzione - Funzione: Esterno; Ripiegatura agli inserti: Non ripiegare; Ripiegatura alle estremità: Nessuno; Larghezza: 0.2 m
Type - Dati identità - Nome del tipo: Blocchetti - 20 cm; Nota chiave: Mb/3
Type - Grafica - Colore del retino a dettaglio basso: 0
Type - Proprietà analitiche - Ruvidità: 3; Assorbimento: 0.7
Altro - Famiglia: Muro di base: Blocchetti - 20 cm; Famiglia e tipo: Muro di base: Blocchetti - 20 cm; ID tipo: Muro di base: Blocchetti - 20 cm; Tipo: Muro di base: Blocchetti - 20 cm
Fasi - Fase di creazione: Stato di Fatto
Strutturale - Attiva modello analitico: no; Strutturale: no; Utilizzo strutturale: Non portante
Vincoli - Offset base: 0 m; Delimita il locale: yes; Distanza estensione base: 0 m; Distanza estensione superiore: 0 m; La base è associata: no; Relativo a massa: no; Vincolo di base: Livello: 0 - Piano Terra; La parte superiore è associata: yes; Linea di ubicazione: Superficie di finitura: interno
Pset_WallCommon - IsExternal: yes; ExtendToStructure: yes; Reference: Blocchetti - 20 cm; LoadBearing: no
Name (Muro di base:Blocchetti - 20 cm:...) | Area (m2) | Lunghezza (m) | Volume (m3) | Offset superiore (m) | Altezza non collegata (m) | Vincolo parte superiore
205053 | 8.01512 | 4.725 | 1.59133 | 0 | 1.03
208964 | 4.97545 | 4.7357 | 0.992264 | 0 | 4.69 | Livello: 1 - Piano Primo
208965 | 5.51408 | 4.8 | 1.09322 | -3.29442 | 1.39558 | Livello: 1 - Piano Primo

# IfcWall: Muro di base:Rivestimento 15 cm (2)
Type - PredefinedType: STANDARD; Material: Alluminio 0.15 m
Type - Altro - Categoria: Muri; Nome famiglia: Muro di base
Type - Costruzione - Funzione: Esterno; Ripiegatura agli inserti: Non ripiegare; Ripiegatura alle estremità: Nessuno; Larghezza: 0.15 m
Type - Dati identità - Nome del tipo: Rivestimento 15 cm; Nota chiave: Mb/3
Type - Grafica - Colore del retino a dettaglio basso: 0
Type - Proprietà analitiche - Ruvidità: 3; Assorbimento: 0.7; Coefficiente di scambio termico (U): 1533.33; Massa termica: 363285; Resistenza termica (R): 0.000652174
Altro - Famiglia: Muro di base: Rivestimento 15 cm; Famiglia e tipo: Muro di base: Rivestimento 15 cm; ID tipo: Muro di base: Rivestimento 15 cm; Tipo: Muro di base: Rivestimento 15 cm
Dimensioni - Lunghezza: 0.18435 m
Fasi - Fase di creazione: Stato di Fatto
Grafica - Contrassegno centrale visibile: no
Strutturale - Attiva modello analitico: no; Strutturale: no; Utilizzo strutturale: Non portante
Vincoli - Offset base: 0 m; Delimita il locale: yes; Distanza estensione base: 0 m; Distanza estensione superiore: 0 m; La base è associata: no; La parte superiore è associata: no; Offset superiore: 0 m; Relativo a massa: no; Linea di ubicazione: Superficie di finitura: interno
Pset_WallCommon - ExtendToStructure: no; IsExternal: yes; LoadBearing: no; Reference: Rivestimento 15 cm; ThermalTransmittance: 1533.33 kg/K/s3
Name (Muro di base:Rivestimento 15 cm:...) | In | Area (m2) | Volume (m3) | Vincolo di base | Altezza non collegata (m)
204918 | 0 - Piano Terra | 0.866952 | 0.12969 | Livello: 0 - Piano Terra | 4.69 | Vincoli - Vincolo parte superiore: Livello: 1 - Piano Primo
207890 | 1 - Piano Primo | 0.915013 | 0.13688 | Livello: 1 - Piano Primo | 4.95

# IfcWall: Muro di base:Setto CA - 30 cm, Muro di base:Setto CA - 30 cm:204206
In: 1 - Piano Primo
Type - PredefinedType: STANDARD; Material: Default - Calcestruzzo 0.3 m
Type - Altro - Categoria: Muri; Nome famiglia: Muro di base
Type - Costruzione - Funzione: Esterno; Ripiegatura agli inserti: Non ripiegare; Ripiegatura alle estremità: Nessuno; Larghezza: 0.3 m
Type - Dati identità - Nome del tipo: Setto CA - 30 cm; Nota chiave: Mb/3
Type - Grafica - Colore del retino a dettaglio basso: 0
Type - Materiali e finiture - Materiale strutturale: Default - Calcestruzzo
Type - Proprietà analitiche - Ruvidità: 3; Assorbimento: 0.7
Altro - Famiglia: Muro di base: Setto CA - 30 cm; Famiglia e tipo: Muro di base: Setto CA - 30 cm; ID tipo: Muro di base: Setto CA - 30 cm; Tipo: Muro di base: Setto CA - 30 cm
Dimensioni - Area: 11.44 m2; Lunghezza: 3.25 m; Volume: 3.43092 m3
Fasi - Fase di creazione: Stato di Fatto
Strutturale - Attiva modello analitico: yes; Copriferro armatura - Altre superfici: Impostazioni copriferro armatura: Copriferro armatura 1; Copriferro armatura - Superficie esterna: Impostazioni copriferro armatura: Copriferro armatura 1; Copriferro armatura - Superficie interna: Impostazioni copriferro armatura: Copriferro armatura 1; Strutturale: yes; Utilizzo strutturale: Portante
Vincoli - Offset base: 0 m; Delimita il locale: yes; Distanza estensione base: 0 m; Distanza estensione superiore: 0 m; La base è associata: no; Linea di ubicazione: Superficie di finitura: esterno; Offset superiore: 0 m; Relativo a massa: no; La parte superiore è associata: yes; Vincolo di base: Livello: 1 - Piano Primo; Vincolo parte superiore: Livello: 2 - Piano Secondo; Altezza non collegata: 3.92 m
Pset_WallCommon - LoadBearing: yes; IsExternal: yes; ExtendToStructure: yes; Reference: Setto CA - 30 cm

# IfcWall: Muro di base:Setto CA rivestito est 45, Muro di base:Setto CA rivestito est 45:204043
In: 0 - Piano Terra
Type - Altro - Categoria: Muri; Nome famiglia: Muro di base
Type - Costruzione - Funzione: Esterno; Ripiegatura agli inserti: Non ripiegare; Ripiegatura alle estremità: Nessuno; Larghezza: 0.45 m
Type - Dati identità - Nome del tipo: Setto CA rivestito est 45; Nota chiave: Mb/3
Type - Grafica - Colore del retino a dettaglio basso: 0
Type - Materiali e finiture - Materiale strutturale: Default - Calcestruzzo
Type - Proprietà analitiche - Ruvidità: 3; Assorbimento: 0.7; Coefficiente di scambio termico (U): 1533.33; Massa termica: 363285; Resistenza termica (R): 0.000652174
Material: Alluminio, Default - Calcestruzzo
Altro - Famiglia: Muro di base: Setto CA rivestito est 45; Famiglia e tipo: Muro di base: Setto CA rivestito est 45; ID tipo: Muro di base: Setto CA rivestito est 45; Tipo: Muro di base: Setto CA rivestito est 45
Dimensioni - Area: 24.537 m2; Lunghezza: 7.9 m; Volume: 11.0416 m3
Fasi - Fase di creazione: Stato di Fatto
Strutturale - Attiva modello analitico: yes; Copriferro armatura - Altre superfici: Impostazioni copriferro armatura: Copriferro armatura 1; Copriferro armatura - Superficie esterna: Impostazioni copriferro armatura: Copriferro armatura 1; Copriferro armatura - Superficie interna: Impostazioni copriferro armatura: Copriferro armatura 1; Strutturale: yes; Utilizzo strutturale: Portante
Vincoli - Offset base: 0 m; Delimita il locale: yes; Distanza estensione base: 0 m; Distanza estensione superiore: 0 m; La base è associata: no; La parte superiore è associata: no; Linea di ubicazione: Superficie di finitura: esterno; Offset superiore: 0 m; Relativo a massa: no; Vincolo di base: Livello: 0 - Piano Terra; Vincolo parte superiore: Livello: 1 - Piano Primo; Altezza non collegata: 4.69 m
Pset_WallCommon - LoadBearing: yes; ExtendToStructure: no; IsExternal: yes; Reference: Setto CA rivestito est 45; ThermalTransmittance: 1533.33 kg/K/s3

# IfcWall: Muro di base:Setto CA rivestito int - 31 cm, Muro di base:Setto CA rivestito int - 31 cm:204200
In: 1 - Piano Primo
Type - PredefinedType: STANDARD; Material: Default - Calcestruzzo 0.3 m, Intonaco - Bianco 0.01 m
Type - Altro - Categoria: Muri; Nome famiglia: Muro di base
Type - Costruzione - Funzione: Esterno; Ripiegatura agli inserti: Non ripiegare; Ripiegatura alle estremità: Nessuno; Larghezza: 0.31 m
Type - Dati identità - Nome del tipo: Setto CA rivestito int - 31 cm; Nota chiave: Mb/3
Type - Grafica - Colore del retino a dettaglio basso: 0
Type - Materiali e finiture - Materiale strutturale: Default - Calcestruzzo
Type - Proprietà analitiche - Ruvidità: 3; Assorbimento: 0.7
Altro - Famiglia: Muro di base: Setto CA rivestito int - 31 cm; Famiglia e tipo: Muro di base: Setto CA rivestito int - 31 cm; ID tipo: Muro di base: Setto CA rivestito int - 31 cm; Tipo: Muro di base: Setto CA rivestito int - 31 cm
Dimensioni - Area: 27.7072 m2; Lunghezza: 7.52 m; Volume: 8.57701 m3
Fasi - Fase di creazione: Stato di Fatto
Strutturale - Attiva modello analitico: yes; Copriferro armatura - Altre superfici: Impostazioni copriferro armatura: Copriferro armatura 1; Copriferro armatura - Superficie esterna: Impostazioni copriferro armatura: Copriferro armatura 1; Copriferro armatura - Superficie interna: Impostazioni copriferro armatura: Copriferro armatura 1; Strutturale: yes; Utilizzo strutturale: Portante
Vincoli - Delimita il locale: yes; Distanza estensione base: 0 m; Distanza estensione superiore: 0 m; La base è associata: no; La parte superiore è associata: no; Linea di ubicazione: Superficie di finitura: esterno; Offset superiore: 0 m; Relativo a massa: no; Vincolo di base: Livello: 1 - Piano Primo; Vincolo parte superiore: Livello: 2 - Piano Secondo; Altezza non collegata: 4.32 m; Offset base: -0.4 m
Pset_WallCommon - LoadBearing: yes; ExtendToStructure: no; IsExternal: yes; Reference: Setto CA rivestito int - 31 cm

# IfcWall: Muro di base:Setto CA rivestito int-est 47 cm, Muro di base:Setto CA rivestito int-est 47 cm:204178
In: 1 - Piano Primo
Type - PredefinedType: STANDARD; Material: Alluminio 0.15 m, Default - Calcestruzzo 0.3 m, Intonaco - Bianco 0.02 m
Type - Altro - Categoria: Muri; Nome famiglia: Muro di base
Type - Costruzione - Funzione: Esterno; Larghezza: 0.47 m; Ripiegatura agli inserti: Non ripiegare; Ripiegatura alle estremità: Nessuno
Type - Dati identità - Nome del tipo: Setto CA rivestito int-est 47 cm; Nota chiave: Mb/3
Type - Grafica - Colore del retino a dettaglio basso: 0
Type - Materiali e finiture - Materiale strutturale: Default - Calcestruzzo
Type - Proprietà analitiche - Assorbimento: 0.7; Coefficiente di scambio termico (U): 1533.33; Massa termica: 363285; Resistenza termica (R): 0.000652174; Ruvidità: 3
Altro - Famiglia: Muro di base: Setto CA rivestito int-est 47 cm; Famiglia e tipo: Muro di base: Setto CA rivestito int-est 47 cm; ID tipo: Muro di base: Setto CA rivestito int-est 47 cm; Tipo: Muro di base: Setto CA rivestito int-est 47 cm
Dimensioni - Area: 23.4484 m2; Lunghezza: 7.52 m; Volume: 11.0085 m3
Fasi - Fase di creazione: Stato di Fatto
Strutturale - Attiva modello analitico: yes; Copriferro armatura - Altre superfici: Impostazioni copriferro armatura: Copriferro armatura 1; Copriferro armatura - Superficie esterna: Impostazioni copriferro armatura: Copriferro armatura 1; Copriferro armatura - Superficie interna: Impostazioni copriferro armatura: Copriferro armatura 1; Strutturale: yes; Utilizzo strutturale: Portante
Vincoli - Offset base: 0 m; Delimita il locale: yes; Distanza estensione base: 0 m; Distanza estensione superiore: 0 m; La base è associata: no; La parte superiore è associata: no; Linea di ubicazione: Superficie di finitura: esterno; Offset superiore: 0 m; Relativo a massa: no; Altezza non collegata: 3.92 m; Vincolo di base: Livello: 1 - Piano Primo; Vincolo parte superiore: Livello: 2 - Piano Secondo
Pset_WallCommon - Reference: Setto CA rivestito int-est 47 cm; LoadBearing: yes; ExtendToStructure: no; IsExternal: yes; ThermalTransmittance: 1533.33 kg/K/s3

# IfcWall: Setti 2:Setti 2, Setti 2:Setti 2:207472
In: 0 - Piano Terra
Type - Material: Calcestruzzo, gettato in opera
Type - Altro - Categoria: Muri; Nome famiglia: Setti 2
Type - Dati identità - Nome del tipo: Setti 2
Altro - Famiglia: Setti 2: Setti 2; Famiglia e tipo: Setti 2: Setti 2; ID tipo: Setti 2: Setti 2; Tipo: Setti 2: Setti 2
Dimensioni - Area: 2.46322 m2; Volume: 5.46834 m3
Fasi - Fase di creazione: Stato di Fatto
Vincoli - Delimita il locale: yes; Prospetto: 0 m; Sposta con l'oggetto più vicino: no
Pset_WallCommon - LoadBearing: yes; ExtendToStructure: no; IsExternal: no; Reference: Setti 2

# IfcWall: Setti C.a.1:Setti C.a., Setti C.a.1:Setti C.a.:206090
In: 0 - Piano Terra
Type - Material: Calcestruzzo
Type - Altro - Categoria: Muri; Nome famiglia: Setti C.a.1
Type - Dati identità - Nome del tipo: Setti C.a.
Altro - Famiglia: Setti C.a.1: Setti C.a.; Famiglia e tipo: Setti C.a.1: Setti C.a.; ID tipo: Setti C.a.1: Setti C.a.; Tipo: Setti C.a.1: Setti C.a.
Dimensioni - Area: 1.596 m2; Volume: 6.84684 m3
Fasi - Fase di creazione: Stato di Fatto
Vincoli - Delimita il locale: yes; Sposta con l'oggetto più vicino: no
Pset_WallCommon - ExtendToStructure: yes; IsExternal: no; LoadBearing: no; Reference: Setti C.a.

# IfcWall: Setti C.a.2:Setti C.a., Setti C.a.2:Setti C.a.:206114
In: 0 - Piano Terra
Type - Material: Calcestruzzo
Type - Altro - Categoria: Muri; Nome famiglia: Setti C.a.2
Type - Dati identità - Nome del tipo: Setti C.a.
Type - Materiali e finiture - Materiale strutturale: Calcestruzzo - Calcestruzzo gettato in opera
Altro - Famiglia: Setti C.a.2: Setti C.a.; Famiglia e tipo: Setti C.a.2: Setti C.a.; ID tipo: Setti C.a.2: Setti C.a.; Tipo: Setti C.a.2: Setti C.a.
Dimensioni - Area: 1.596 m2; Volume: 6.84684 m3
Fasi - Fase di creazione: Stato di Fatto
Vincoli - Delimita il locale: yes; Prospetto: 0 m; Sposta con l'oggetto più vicino: no
Pset_WallCommon - ExtendToStructure: yes; IsExternal: no; LoadBearing: no; Reference: Setti C.a.

# IfcWall: Setti C.a.3:Setti C.a., Setti C.a.3:Setti C.a.:206126
In: 0 - Piano Terra
Type - Material: Calcestruzzo
Type - Altro - Categoria: Muri; Nome famiglia: Setti C.a.3
Type - Dati identità - Nome del tipo: Setti C.a.
Altro - Famiglia: Setti C.a.3: Setti C.a.; Famiglia e tipo: Setti C.a.3: Setti C.a.; ID tipo: Setti C.a.3: Setti C.a.; Tipo: Setti C.a.3: Setti C.a.
Dimensioni - Area: 1.59544 m2; Volume: 6.84442 m3
Fasi - Fase di creazione: Stato di Fatto
Vincoli - Delimita il locale: yes; Prospetto: 0 m; Sposta con l'oggetto più vicino: no
Pset_WallCommon - ExtendToStructure: yes; IsExternal: no; LoadBearing: no; Reference: Setti C.a.

# IfcWall: Setti C.a.:Setti C.a., Setti C.a.:Setti C.a.:206054
In: 0 - Piano Terra
Type - Material: Calcestruzzo
Type - Altro - Categoria: Muri; Nome famiglia: Setti C.a.
Type - Dati identità - Nome del tipo: Setti C.a.
Altro - Famiglia: Setti C.a.: Setti C.a.; Famiglia e tipo: Setti C.a.: Setti C.a.; ID tipo: Setti C.a.: Setti C.a.; Tipo: Setti C.a.: Setti C.a.
Dimensioni - Area: 1.596 m2; Volume: 6.84684 m3
Fasi - Fase di creazione: Stato di Fatto
Vincoli - Delimita il locale: yes; Sposta con l'oggetto più vicino: no
Pset_WallCommon - ExtendToStructure: yes; IsExternal: no; LoadBearing: no; Reference: Setti C.a.

# IfcWall: Setti-1:Setti-1, Setti-1:Setti-1:207458
In: 0 - Piano Terra
Type - Material: Calcestruzzo, gettato in opera
Type - Altro - Categoria: Muri; Nome famiglia: Setti-1
Type - Dati identità - Nome del tipo: Setti-1
Altro - Famiglia: Setti-1: Setti-1; Famiglia e tipo: Setti-1: Setti-1; ID tipo: Setti-1: Setti-1; Tipo: Setti-1: Setti-1
Dimensioni - Area: 7.06349 m2; Volume: 33.1281 m3
Fasi - Fase di creazione: Stato di Fatto
Vincoli - Delimita il locale: yes; Prospetto: 0 m; Sposta con l'oggetto più vicino: no
Pset_WallCommon - LoadBearing: yes; ExtendToStructure: no; IsExternal: no; Reference: Setti-1

# IfcWall: Setto C.a.10:Setto C.a., Setto C.a.10:Setto C.a.:207202
In: 1 - Piano Primo
Type - Material: Default - Calcestruzzo
Type - Altro - Categoria: Muri; Nome famiglia: Setto C.a.10
Type - Dati identità - Nome del tipo: Setto C.a.
Altro - Famiglia: Setto C.a.10: Setto C.a.; Famiglia e tipo: Setto C.a.10: Setto C.a.; ID tipo: Setto C.a.10: Setto C.a.; Tipo: Setto C.a.10: Setto C.a.
Dimensioni - Area: 2.46 m2; Volume: 8.65914 m3
Fasi - Fase di creazione: Stato di Fatto
Vincoli - Delimita il locale: yes; Prospetto: 0 m; Sposta con l'oggetto più vicino: no
Pset_WallCommon - ExtendToStructure: yes; IsExternal: no; LoadBearing: no; Reference: Setto C.a.

# IfcWall: Setto C.a.11:Setto C.a., Setto C.a.11:Setto C.a.:207214
In: 1 - Piano Primo
Type - Material: Default - Calcestruzzo
Type - Altro - Categoria: Muri; Nome famiglia: Setto C.a.11
Type - Dati identità - Nome del tipo: Setto C.a.
Altro - Famiglia: Setto C.a.11: Setto C.a.; Famiglia e tipo: Setto C.a.11: Setto C.a.; ID tipo: Setto C.a.11: Setto C.a.; Tipo: Setto C.a.11: Setto C.a.
Dimensioni - Area: 2.46 m2; Volume: 8.6592 m3
Fasi - Fase di creazione: Stato di Fatto
Vincoli - Delimita il locale: yes; Prospetto: 0 m; Sposta con l'oggetto più vicino: no
Pset_WallCommon - ExtendToStructure: yes; IsExternal: no; LoadBearing: no; Reference: Setto C.a.

# IfcWall: Setto C.a.12:Setto C.a., Setto C.a.12:Setto C.a.:207226
In: 1 - Piano Primo
Type - Material: Default - Calcestruzzo
Type - Altro - Categoria: Muri; Nome famiglia: Setto C.a.12
Type - Dati identità - Nome del tipo: Setto C.a.
Altro - Famiglia: Setto C.a.12: Setto C.a.; Famiglia e tipo: Setto C.a.12: Setto C.a.; ID tipo: Setto C.a.12: Setto C.a.; Tipo: Setto C.a.12: Setto C.a.
Dimensioni - Area: 2.46 m2; Volume: 8.6592 m3
Fasi - Fase di creazione: Stato di Fatto
Vincoli - Delimita il locale: yes; Prospetto: 0 m; Sposta con l'oggetto più vicino: no
Pset_WallCommon - ExtendToStructure: yes; IsExternal: no; LoadBearing: no; Reference: Setto C.a.

# IfcWall: Setto C.a.13:Setto C.a., Setto C.a.13:Setto C.a.:207238
In: 1 - Piano Primo
Type - Material: Default - Calcestruzzo
Type - Altro - Categoria: Muri; Nome famiglia: Setto C.a.13
Type - Dati identità - Nome del tipo: Setto C.a.
Altro - Famiglia: Setto C.a.13: Setto C.a.; Famiglia e tipo: Setto C.a.13: Setto C.a.; ID tipo: Setto C.a.13: Setto C.a.; Tipo: Setto C.a.13: Setto C.a.
Dimensioni - Area: 2.46 m2; Volume: 8.6592 m3
Fasi - Fase di creazione: Stato di Fatto
Vincoli - Delimita il locale: yes; Prospetto: 0 m; Sposta con l'oggetto più vicino: no
Pset_WallCommon - ExtendToStructure: yes; IsExternal: no; LoadBearing: no; Reference: Setto C.a.

# IfcWall: Setto C.a.14:Setto C.a., Setto C.a.14:Setto C.a.:207250
In: 1 - Piano Primo
Type - Material: Default - Calcestruzzo
Type - Altro - Categoria: Muri; Nome famiglia: Setto C.a.14
Type - Dati identità - Nome del tipo: Setto C.a.
Altro - Famiglia: Setto C.a.14: Setto C.a.; Famiglia e tipo: Setto C.a.14: Setto C.a.; ID tipo: Setto C.a.14: Setto C.a.; Tipo: Setto C.a.14: Setto C.a.
Dimensioni - Area: 1.596 m2; Volume: 5.61792 m3
Fasi - Fase di creazione: Stato di Fatto
Vincoli - Delimita il locale: yes; Prospetto: 0 m; Sposta con l'oggetto più vicino: no
Pset_WallCommon - ExtendToStructure: yes; IsExternal: no; LoadBearing: no; Reference: Setto C.a.

# IfcWall: Setto C.a.15:Setto C.a., Setto C.a.15:Setto C.a.:207262
In: 1 - Piano Primo
Type - Material: Default - Calcestruzzo
Type - Altro - Categoria: Muri; Nome famiglia: Setto C.a.15
Type - Dati identità - Nome del tipo: Setto C.a.
Altro - Famiglia: Setto C.a.15: Setto C.a.; Famiglia e tipo: Setto C.a.15: Setto C.a.; ID tipo: Setto C.a.15: Setto C.a.; Tipo: Setto C.a.15: Setto C.a.
Dimensioni - Area: 1.596 m2; Volume: 5.61792 m3
Fasi - Fase di creazione: Stato di Fatto
Vincoli - Delimita il locale: yes; Prospetto: 0 m; Sposta con l'oggetto più vicino: no
Pset_WallCommon - ExtendToStructure: yes; IsExternal: no; LoadBearing: no; Reference: Setto C.a.

# IfcWall: Setto C.a.16:Setto C.a., Setto C.a.16:Setto C.a.:207274
In: 1 - Piano Primo
Type - Material: Default - Calcestruzzo
Type - Altro - Categoria: Muri; Nome famiglia: Setto C.a.16
Type - Dati identità - Nome del tipo: Setto C.a.
Altro - Famiglia: Setto C.a.16: Setto C.a.; Famiglia e tipo: Setto C.a.16: Setto C.a.; ID tipo: Setto C.a.16: Setto C.a.; Tipo: Setto C.a.16: Setto C.a.
Dimensioni - Area: 1.596 m2; Volume: 5.61792 m3
Fasi - Fase di creazione: Stato di Fatto
Vincoli - Delimita il locale: yes; Prospetto: 0 m; Sposta con l'oggetto più vicino: no
Pset_WallCommon - ExtendToStructure: yes; IsExternal: no; LoadBearing: no; Reference: Setto C.a.

# IfcWall: Setto C.a.17:Setto C.a., Setto C.a.17:Setto C.a.:207286
In: 1 - Piano Primo
Type - Material: Default - Calcestruzzo
Type - Altro - Categoria: Muri; Nome famiglia: Setto C.a.17
Type - Dati identità - Nome del tipo: Setto C.a.
Altro - Famiglia: Setto C.a.17: Setto C.a.; Famiglia e tipo: Setto C.a.17: Setto C.a.; ID tipo: Setto C.a.17: Setto C.a.; Tipo: Setto C.a.17: Setto C.a.
Dimensioni - Area: 1.596 m2; Volume: 5.61328 m3
Fasi - Fase di creazione: Stato di Fatto
Vincoli - Delimita il locale: yes; Prospetto: 0 m; Sposta con l'oggetto più vicino: no
Pset_WallCommon - ExtendToStructure: yes; IsExternal: no; LoadBearing: no; Reference: Setto C.a.

# IfcWall: Setto C.a.18:Setto C.a., Setto C.a.18:Setto C.a.:207298
In: 1 - Piano Primo
Type - Material: Default - Calcestruzzo
Type - Altro - Categoria: Muri; Nome famiglia: Setto C.a.18
Type - Dati identità - Nome del tipo: Setto C.a.
Altro - Famiglia: Setto C.a.18: Setto C.a.; Famiglia e tipo: Setto C.a.18: Setto C.a.; ID tipo: Setto C.a.18: Setto C.a.; Tipo: Setto C.a.18: Setto C.a.
Dimensioni - Area: 1.596 m2; Volume: 5.61792 m3
Fasi - Fase di creazione: Stato di Fatto
Vincoli - Delimita il locale: yes; Prospetto: 0 m; Sposta con l'oggetto più vicino: no
Pset_WallCommon - ExtendToStructure: yes; IsExternal: no; LoadBearing: no; Reference: Setto C.a.

# IfcWall: Setto C.a.19:Setto C.a., Setto C.a.19:Setto C.a.:207310
In: 1 - Piano Primo
Type - Material: Default - Calcestruzzo
Type - Altro - Categoria: Muri; Nome famiglia: Setto C.a.19
Type - Dati identità - Nome del tipo: Setto C.a.
Altro - Famiglia: Setto C.a.19: Setto C.a.; Famiglia e tipo: Setto C.a.19: Setto C.a.; ID tipo: Setto C.a.19: Setto C.a.; Tipo: Setto C.a.19: Setto C.a.
Dimensioni - Area: 1.5954 m2; Volume: 5.6158 m3
Fasi - Fase di creazione: Stato di Fatto
Vincoli - Delimita il locale: yes; Prospetto: 0 m; Sposta con l'oggetto più vicino: no
Pset_WallCommon - ExtendToStructure: yes; IsExternal: no; LoadBearing: no; Reference: Setto C.a.

# IfcWall: Setto C.a.1:Setto C.a., Setto C.a.1:Setto C.a.:206066
In: 0 - Piano Terra
Type - Material: Default - Calcestruzzo
Type - Altro - Categoria: Muri; Nome famiglia: Setto C.a.1
Type - Dati identità - Nome del tipo: Setto C.a.
Altro - Famiglia: Setto C.a.1: Setto C.a.; Famiglia e tipo: Setto C.a.1: Setto C.a.; ID tipo: Setto C.a.1: Setto C.a.; Tipo: Setto C.a.1: Setto C.a.
Dimensioni - Area: 2.46 m2; Volume: 10.5534 m3
Fasi - Fase di creazione: Stato di Fatto
Vincoli - Delimita il locale: yes; Sposta con l'oggetto più vicino: no
Pset_WallCommon - ExtendToStructure: yes; IsExternal: no; LoadBearing: no; Reference: Setto C.a.

# IfcWall: Setto C.a.2:Setto C.a., Setto C.a.2:Setto C.a.:206078
In: 0 - Piano Terra
Type - Material: Default - Calcestruzzo
Type - Altro - Categoria: Muri; Nome famiglia: Setto C.a.2
Type - Dati identità - Nome del tipo: Setto C.a.
Altro - Famiglia: Setto C.a.2: Setto C.a.; Famiglia e tipo: Setto C.a.2: Setto C.a.; ID tipo: Setto C.a.2: Setto C.a.; Tipo: Setto C.a.2: Setto C.a.
Dimensioni - Area: 1.596 m2; Volume: 6.8422 m3
Fasi - Fase di creazione: Stato di Fatto
Vincoli - Delimita il locale: yes; Sposta con l'oggetto più vicino: no
Pset_WallCommon - ExtendToStructure: yes; IsExternal: no; LoadBearing: no; Reference: Setto C.a.

# IfcWall: Setto C.a.3:Setto C.a., Setto C.a.3:Setto C.a.:206102
In: 0 - Piano Terra
Type - Material: Default - Calcestruzzo
Type - Altro - Categoria: Muri; Nome famiglia: Setto C.a.3
Type - Dati identità - Nome del tipo: Setto C.a.
Altro - Famiglia: Setto C.a.3: Setto C.a.; Famiglia e tipo: Setto C.a.3: Setto C.a.; ID tipo: Setto C.a.3: Setto C.a.; Tipo: Setto C.a.3: Setto C.a.
Dimensioni - Area: 2.46 m2; Volume: 10.5534 m3
Fasi - Fase di creazione: Stato di Fatto
Vincoli - Delimita il locale: yes; Prospetto: 0 m; Sposta con l'oggetto più vicino: no
Pset_WallCommon - ExtendToStructure: yes; IsExternal: no; LoadBearing: no; Reference: Setto C.a.

# IfcWall: Setto C.a.4:Setto C.a., Setto C.a.4:Setto C.a.:206138
In: 0 - Piano Terra
Type - Material: Default - Calcestruzzo
Type - Altro - Categoria: Muri; Nome famiglia: Setto C.a.4
Type - Dati identità - Nome del tipo: Setto C.a.
Altro - Famiglia: Setto C.a.4: Setto C.a.; Famiglia e tipo: Setto C.a.4: Setto C.a.; ID tipo: Setto C.a.4: Setto C.a.; Tipo: Setto C.a.4: Setto C.a.
Dimensioni - Area: 2.46 m2; Volume: 10.5534 m3
Fasi - Fase di creazione: Stato di Fatto
Vincoli - Delimita il locale: yes; Sposta con l'oggetto più vicino: no
Pset_WallCommon - ExtendToStructure: yes; IsExternal: no; LoadBearing: no; Reference: Setto C.a.

# IfcWall: Setto C.a.5:Setto C.a., Setto C.a.5:Setto C.a.:206150
In: 0 - Piano Terra
Type - Material: Default - Calcestruzzo
Type - Altro - Categoria: Muri; Nome famiglia: Setto C.a.5
Type - Dati identità - Nome del tipo: Setto C.a.
Altro - Famiglia: Setto C.a.5: Setto C.a.; Famiglia e tipo: Setto C.a.5: Setto C.a.; ID tipo: Setto C.a.5: Setto C.a.; Tipo: Setto C.a.5: Setto C.a.
Dimensioni - Area: 2.46 m2; Volume: 10.5534 m3
Fasi - Fase di creazione: Stato di Fatto
Vincoli - Delimita il locale: yes; Prospetto: 0 m; Sposta con l'oggetto più vicino: no
Pset_WallCommon - ExtendToStructure: yes; IsExternal: no; LoadBearing: no; Reference: Setto C.a.

# IfcWall: Setto C.a.6:Setto C.a., Setto C.a.6:Setto C.a.:206162
In: 0 - Piano Terra
Type - Material: Default - Calcestruzzo
Type - Altro - Categoria: Muri; Nome famiglia: Setto C.a.6
Type - Dati identità - Nome del tipo: Setto C.a.
Altro - Famiglia: Setto C.a.6: Setto C.a.; Famiglia e tipo: Setto C.a.6: Setto C.a.; ID tipo: Setto C.a.6: Setto C.a.; Tipo: Setto C.a.6: Setto C.a.
Dimensioni - Area: 2.46 m2; Volume: 10.5534 m3
Fasi - Fase di creazione: Stato di Fatto
Vincoli - Delimita il locale: yes; Prospetto: 0 m; Sposta con l'oggetto più vicino: no
Pset_WallCommon - ExtendToStructure: yes; IsExternal: no; LoadBearing: no; Reference: Setto C.a.

# IfcWall: Setto C.a.7:Setto C.a., Setto C.a.7:Setto C.a.:206174
In: 0 - Piano Terra
Type - Material: Default - Calcestruzzo
Type - Altro - Categoria: Muri; Nome famiglia: Setto C.a.7
Type - Dati identità - Nome del tipo: Setto C.a.
Altro - Famiglia: Setto C.a.7: Setto C.a.; Famiglia e tipo: Setto C.a.7: Setto C.a.; ID tipo: Setto C.a.7: Setto C.a.; Tipo: Setto C.a.7: Setto C.a.
Dimensioni - Area: 2.46 m2; Volume: 10.5534 m3
Fasi - Fase di creazione: Stato di Fatto
Vincoli - Delimita il locale: yes; Prospetto: 0 m; Sposta con l'oggetto più vicino: no
Pset_WallCommon - ExtendToStructure: yes; IsExternal: no; LoadBearing: no; Reference: Setto C.a.

# IfcWall: Setto C.a.8:Setto C.a., Setto C.a.8:Setto C.a.:207178
In: 1 - Piano Primo
Type - Material: Default - Calcestruzzo
Type - Altro - Categoria: Muri; Nome famiglia: Setto C.a.8
Type - Dati identità - Nome del tipo: Setto C.a.
Altro - Famiglia: Setto C.a.8: Setto C.a.; Famiglia e tipo: Setto C.a.8: Setto C.a.; ID tipo: Setto C.a.8: Setto C.a.; Tipo: Setto C.a.8: Setto C.a.
Dimensioni - Area: 2.46 m2; Volume: 8.6592 m3
Fasi - Fase di creazione: Stato di Fatto
Vincoli - Delimita il locale: yes; Prospetto: 0 m; Sposta con l'oggetto più vicino: no
Pset_WallCommon - ExtendToStructure: yes; IsExternal: no; LoadBearing: no; Reference: Setto C.a.

# IfcWall: Setto C.a.9:Setto C.a., Setto C.a.9:Setto C.a.:207190
In: 1 - Piano Primo
Type - Material: Default - Calcestruzzo
Type - Altro - Categoria: Muri; Nome famiglia: Setto C.a.9
Type - Dati identità - Nome del tipo: Setto C.a.
Altro - Famiglia: Setto C.a.9: Setto C.a.; Famiglia e tipo: Setto C.a.9: Setto C.a.; ID tipo: Setto C.a.9: Setto C.a.; Tipo: Setto C.a.9: Setto C.a.
Dimensioni - Area: 2.46 m2; Volume: 8.6592 m3
Fasi - Fase di creazione: Stato di Fatto
Vincoli - Delimita il locale: yes; Prospetto: 0 m; Sposta con l'oggetto più vicino: no
Pset_WallCommon - ExtendToStructure: yes; IsExternal: no; LoadBearing: no; Reference: Setto C.a.

# IfcWall: Setto C.a.:Setto C.a., Setto C.a.:Setto C.a.:206042
In: 0 - Piano Terra
Type - Material: Default - Calcestruzzo
Type - Altro - Categoria: Muri; Nome famiglia: Setto C.a.
Type - Dati identità - Nome del tipo: Setto C.a.
Altro - Famiglia: Setto C.a.: Setto C.a.; Famiglia e tipo: Setto C.a.: Setto C.a.; ID tipo: Setto C.a.: Setto C.a.; Tipo: Setto C.a.: Setto C.a.
Dimensioni - Area: 1.596 m2; Volume: 6.84684 m3
Fasi - Fase di creazione: Stato di Fatto
Vincoli - Delimita il locale: yes; Sposta con l'oggetto più vicino: no
Pset_WallCommon - ExtendToStructure: yes; IsExternal: no; LoadBearing: no; Reference: Setto C.a.

# IfcWall: Setto Sx1:Setto Sx, Setto Sx1:Setto Sx:207442
In: 0 - Piano Terra
Type - Material: Calcestruzzo, gettato in opera
Type - Altro - Categoria: Muri; Nome famiglia: Setto Sx1
Type - Dati identità - Nome del tipo: Setto Sx
Altro - Famiglia: Setto Sx1: Setto Sx; Famiglia e tipo: Setto Sx1: Setto Sx; ID tipo: Setto Sx1: Setto Sx; Tipo: Setto Sx1: Setto Sx
Dimensioni - Area: 29.8143 m2; Volume: 139.837 m3
Fasi - Fase di creazione: Stato di Fatto
Vincoli - Delimita il locale: yes; Prospetto: 0 m; Sposta con l'oggetto più vicino: no
Pset_WallCommon - LoadBearing: yes; ExtendToStructure: no; IsExternal: no; Reference: Setto Sx

# IfcWall: Setto Sx:Setto Sx, Setto Sx:Setto Sx:207356
In: 1 - Piano Primo
Type - Material: Calcestruzzo, gettato in opera
Type - Altro - Categoria: Muri; Nome famiglia: Setto Sx
Type - Dati identità - Nome del tipo: Setto Sx
Altro - Famiglia: Setto Sx: Setto Sx; Famiglia e tipo: Setto Sx: Setto Sx; ID tipo: Setto Sx: Setto Sx; Tipo: Setto Sx: Setto Sx
Dimensioni - Area: 40.1389 m2; Volume: 141.297 m3
Fasi - Fase di creazione: Stato di Fatto
Vincoli - Delimita il locale: yes; Sposta con l'oggetto più vicino: no
Pset_WallCommon - LoadBearing: yes; ExtendToStructure: yes; IsExternal: no; Reference: Setto Sx

# IfcWall: Setto sx p2:Setto sx p2, Setto sx p2:Setto sx p2:207391
In: 1 - Piano Primo
Type - Material: Calcestruzzo, gettato in opera
Type - Altro - Categoria: Muri; Nome famiglia: Setto sx p2
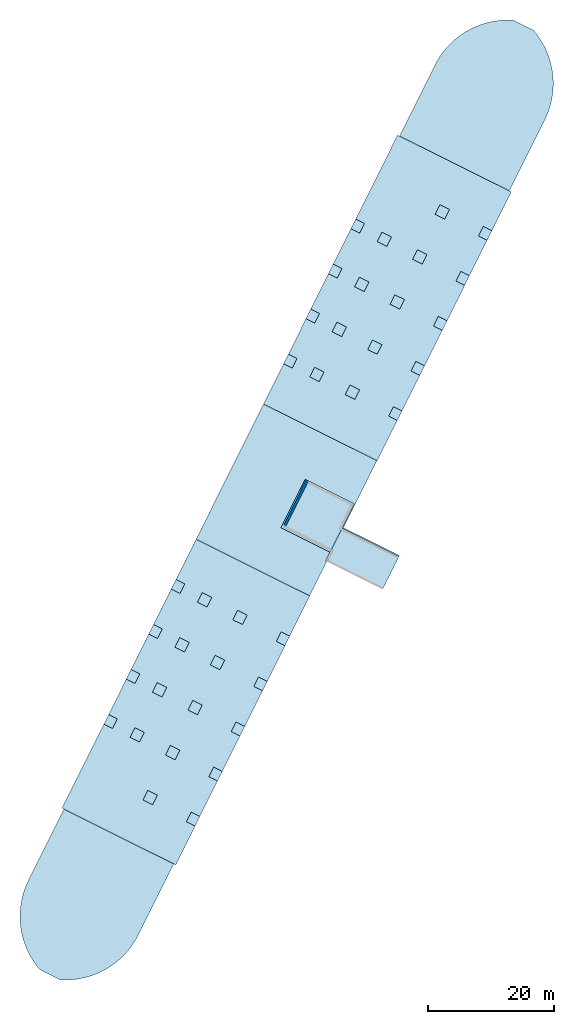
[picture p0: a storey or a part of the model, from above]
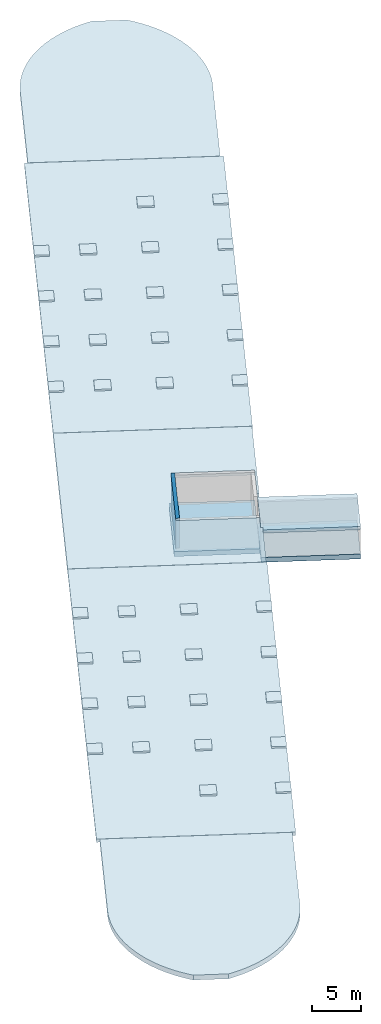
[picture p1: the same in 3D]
Properties of the parts of a building model (IFC2X3), part 6 of 7

# IfcWall: Setto sx p2:Setto sx p2, Setto sx p2:Setto sx p2:207391
Type - Dati identità - Nome del tipo: Setto sx p2
Altro - Famiglia: Setto sx p2: Setto sx p2; Famiglia e tipo: Setto sx p2: Setto sx p2; ID tipo: Setto sx p2: Setto sx p2; Tipo: Setto sx p2: Setto sx p2
Dimensioni - Area: 25.299 m2; Volume: 36.1807 m3
Fasi - Fase di creazione: Stato di Fatto
Vincoli - Delimita il locale: yes; Sposta con l'oggetto più vicino: no
Pset_WallCommon - LoadBearing: yes; ExtendToStructure: no; IsExternal: no; Reference: Setto sx p2

# IfcWallStandardCase: Muro di base:Blocchetti - 20 cm (43)
Type - PredefinedType: STANDARD; Material: Sabbia e Calcestruzzo 0.2 m
Type - Altro - Categoria: Muri; Nome famiglia: Muro di base
Type - Costruzione - Funzione: Esterno; Ripiegatura agli inserti: Non ripiegare; Ripiegatura alle estremità: Nessuno; Larghezza: 0.2 m
Type - Dati identità - Nome del tipo: Blocchetti - 20 cm; Nota chiave: Mb/3
Type - Grafica - Colore del retino a dettaglio basso: 0
Type - Proprietà analitiche - Ruvidità: 3; Assorbimento: 0.7
Altro - Famiglia: Muro di base: Blocchetti - 20 cm; Famiglia e tipo: Muro di base: Blocchetti - 20 cm; ID tipo: Muro di base: Blocchetti - 20 cm; Tipo: Muro di base: Blocchetti - 20 cm
Fasi - Fase di creazione: Stato di Fatto
Vincoli - Delimita il locale: yes; Distanza estensione base: 0 m; Distanza estensione superiore: 0 m; La base è associata: no; Relativo a massa: no
Pset_WallCommon - IsExternal: yes; Reference: Blocchetti - 20 cm
Name (Muro di base:Blocchetti - 20 cm:...) | In | Area (m2) | Lunghezza (m) | Volume (m3) | Attiva modello analitico = Strutturale = LoadBearing | Utilizzo strutturale | Offset base (m) | La parte superiore è associata = ExtendToStructure | Linea di ubicazione | Vincolo di base | Vincolo parte superiore | Altezza non collegata (m) | Offset superiore (m)
204122 | 0 - Piano Terra | 10.7753 | 2.77 | 2.15506 | no | Non portante | 0 | no | Superficie di finitura: esterno | Livello: 0 - Piano Terra | Livello: 1 - Piano Primo | 3.89 | -0.8
204123 | 0 - Piano Terra | 28.5169 | 7.13569 | 5.70339 | no | Non portante | 0 | no | Superficie di finitura: esterno | Livello: 0 - Piano Terra | Livello: 1 - Piano Primo | 4.03 | -0.66
204124 | 0 - Piano Terra | 29.9572 | 7.4931 | 5.99143 | no | Non portante | 0 | no | Superficie di finitura: esterno | Livello: 0 - Piano Terra | Livello: 1 - Piano Primo | 4.03 | -0.66
204125 | 0 - Piano Terra | 29.9473 | 7.50281 | 5.98945 | no | Non portante | 0 | no | Superficie di finitura: esterno | Livello: 0 - Piano Terra | Livello: 1 - Piano Primo | 4.03 | -0.66
204126 | 0 - Piano Terra | 29.8262 | 7.50563 | 5.96522 | no | Non portante | 0 | no | Superficie di finitura: esterno | Livello: 0 - Piano Terra | Livello: 1 - Piano Primo | 4.03 | -0.66
204127 | 0 - Piano Terra | 29.9995 | 7.5036 | 5.9999 | no | Non portante | 0 | no | Superficie di finitura: esterno | Livello: 0 - Piano Terra | Livello: 1 - Piano Primo | 4.03 | -0.66
204128 | 0 - Piano Terra | 29.5991 | 7.40425 | 5.91983 | no | Non portante | 0 | no | Superficie di finitura: esterno | Livello: 0 - Piano Terra | Livello: 1 - Piano Primo | 4.03 | -0.66
204136 | 0 - Piano Terra | 33.0395 | 7.975 | 6.6079 | no | Non portante | 0 | no | Superficie di finitura: esterno | Livello: 0 - Piano Terra | Livello: 1 - Piano Primo | 4.29 | -0.4
204143 | 0 - Piano Terra | 33.0395 | 7.975 | 6.6079 | no | Non portante | 0 | no | Superficie di finitura: esterno | Livello: 0 - Piano Terra | Livello: 1 - Piano Primo | 4.29 | -0.4
204150 | 0 - Piano Terra | 17.0472 | 5.2744 | 3.40944 | no | Non portante | 0 | no | Superficie di finitura: esterno | Livello: 0 - Piano Terra | Livello: 1 - Piano Primo | 4.69 | 0
204151 | 0 - Piano Terra | 25.4235 | 6.15046 | 5.08469 | no | Non portante | 0 | yes | Superficie di finitura: esterno | Livello: 0 - Piano Terra | Livello: 1 - Piano Primo | 4.69 | 0
204152 | 0 - Piano Terra | 3.7322 | 5.75485 | 0.74644 | no | Non portante | 0 | no | Superficie di finitura: esterno | Livello: 0 - Piano Terra |  | 0.66 | 0
204153 | 0 - Piano Terra | 12.6868 | 2.98457 | 2.53736 | no | Non portante | 0 | no | Superficie di finitura: esterno | Livello: 0 - Piano Terra | Livello: 1 - Piano Primo | 4.29 | -0.4
204154 | 0 - Piano Terra | 20.0147 | 4.91544 | 4.00294 | no | Non portante | 0 | no | Superficie di finitura: esterno | Livello: 0 - Piano Terra | Livello: 1 - Piano Primo | 4.29 | -0.4
204155 | 0 - Piano Terra | 2.60633 | 0.857536 | 0.521266 | no | Non portante | 0 | yes | Superficie di finitura: esterno | Livello: 0 - Piano Terra | Livello: 1 - Piano Primo | 4.69 | 0
204156 | 0 - Piano Terra | 2.12618 | 0.395614 | 0.425237 | no | Non portante | 0 | yes | Superficie di finitura: esterno | Livello: 0 - Piano Terra | Livello: 1 - Piano Primo | 4.69 | 0
204157 | 0 - Piano Terra | 21.3923 | 7.89859 | 4.27846 | no | Non portante | 0 | no | Superficie di finitura: esterno | Livello: 0 - Piano Terra | Livello: 1 - Piano Primo | 4.03 | -0.66
204158 | 0 - Piano Terra | 18.8538 | 4.17 | 3.77076 | no | Non portante | 0 | no | Superficie di finitura: esterno | Livello: 0 - Piano Terra | Livello: 1 - Piano Primo | 4.69 | 0
204160 | 0 - Piano Terra | 17.3291 | 5.19001 | 3.46582 | yes | Portante | 0 | no | Superficie di finitura: interno | Livello: 0 - Piano Terra | Livello: 1 - Piano Primo | 3.89 | -0.8 | Strutturale - Copriferro armatura - Altre superfici: Impostazioni copriferro armatura: Copriferro armatura 1; Copriferro armatura - Superficie esterna: Impostazioni copriferro armatura: Copriferro armatura 1; Copriferro armatura - Superficie interna: Impostazioni copriferro armatura: Copriferro armatura 1
204177 | 0 - Piano Terra | 6.83422 | 1.55805 | 1.28408 | no | Non portante | 0 | no | Superficie del nucleo: esterno | Livello: 0 - Piano Terra |  | 4.13 | 0 | Grafica - Contrassegno centrale visibile: no
204219 | 1 - Piano Primo | 14.6328 | 4.17 | 2.92656 | no | Non portante | 0 | yes | Superficie di finitura: esterno | Livello: 1 - Piano Primo | Livello: 2 - Piano Secondo | 3.92 | 0
204856 | 1 - Piano Primo | 6.67961 | 1.55805 | 1.25538 | no | Non portante | -0.16 | no | Superficie del nucleo: esterno | Livello: 1 - Piano Primo |  | 4.02 | 0 | Grafica - Contrassegno centrale visibile: no
204862 | 0 - Piano Terra | 4.0153 | 2.77 | 0.80306 | no | Non portante | 0 | no | Superficie di finitura: interno | Livello: 0 - Piano Terra | Livello: 1 - Piano Primo | 3.89 | -0.8
204869 | 0 - Piano Terra | 6.85305 | 1.56197 | 1.28735 | no | Non portante | 0 | no | Superficie di finitura: interno | Livello: 0 - Piano Terra |  | 4.13 | 0 | Grafica - Contrassegno centrale visibile: no
204870 | 0 - Piano Terra | 13.5991 | 3.88734 | 2.65841 | no | Non portante | 0 | no | Superficie di finitura: interno | Livello: 0 - Piano Terra |  | 4.13 | 0 | Grafica - Contrassegno centrale visibile: no
204871 | 0 - Piano Terra | 15.2223 | 4.2776 | 2.98063 | no | Non portante | 0 | no | Superficie di finitura: interno | Livello: 0 - Piano Terra |  | 4.13 | 0 | Grafica - Contrassegno centrale visibile: no
204872 | 0 - Piano Terra | 5.01356 | 1.11793 | 0.920499 | no | Non portante | 0 | no | Superficie di finitura: interno | Livello: 0 - Piano Terra |  | 4.13 | 0 | Grafica - Contrassegno centrale visibile: no
204875 | 1 - Piano Primo | 6.43033 | 1.65583 | 1.2783 | no | Non portante | 0 | no | Superficie di finitura: interno | Livello: 1 - Piano Primo |  | 3.86 | 0 | Grafica - Contrassegno centrale visibile: no
204876 | 1 - Piano Primo | 15.9155 | 3.88734 | 3.12329 | no | Non portante | -0.16 | no | Superficie di finitura: interno | Livello: 1 - Piano Primo |  | 4.02 | 0 | Grafica - Contrassegno centrale visibile: no
204877 | 1 - Piano Primo | 17.5168 | 4.2776 | 3.44129 | no | Non portante | -0.16 | no | Superficie di finitura: interno | Livello: 1 - Piano Primo |  | 4.02 | 0 | Grafica - Contrassegno centrale visibile: no
204878 | 1 - Piano Primo | 4.88003 | 1.11793 | 0.895982 | no | Non portante | -0.16 | no | Superficie di finitura: interno | Livello: 1 - Piano Primo |  | 4.02 | 0 | Grafica - Contrassegno centrale visibile: no
205052 | 0 - Piano Terra | 3.41264 | 4.71251 | 0.681375 | no | Non portante | 0 | no | Superficie di finitura: interno | Livello: 0 - Piano Terra |  | 1.03 | 0
207357 | 1 - Piano Primo | 16.1928 | 5.19001 | 3.23856 | yes | Portante | 0 | no | Superficie di finitura: interno | Livello: 1 - Piano Primo | Livello: 2 - Piano Secondo | 3.12 | -0.8 | Strutturale - Copriferro armatura - Altre superfici: Impostazioni copriferro armatura: Copriferro armatura 1; Copriferro armatura - Superficie esterna: Impostazioni copriferro armatura: Copriferro armatura 1; Copriferro armatura - Superficie interna: Impostazioni copriferro armatura: Copriferro armatura 1
207490 | 0 - Piano Terra | 13.1197 | 3.76414 | 2.56094 | no | Non portante | 0 | no | Superficie di finitura: esterno | Livello: 0 - Piano Terra |  | 4.13 | 0 | Grafica - Contrassegno centrale visibile: no
207512 | 0 - Piano Terra | 14.7212 | 4.1574 | 2.88132 | no | Non portante | 0 | no | Superficie di finitura: interno | Livello: 0 - Piano Terra |  | 4.13 | 0 | Grafica - Contrassegno centrale visibile: no
207513 | 0 - Piano Terra | 6.37165 | 1.44832 | 1.19349 | no | Non portante | 0 | no | Superficie di finitura: interno | Livello: 0 - Piano Terra |  | 4.13 | 0 | Grafica - Contrassegno centrale visibile: no
207559 | 1 - Piano Primo | 16.921 | 4.1574 | 3.34274 | no | Non portante | -0.16 | no | Superficie di finitura: interno | Livello: 1 - Piano Primo |  | 4.02 | 0 | Grafica - Contrassegno centrale visibile: no
207560 | 1 - Piano Primo | 6.17505 | 1.44496 | 1.1563 | no | Non portante | -0.16 | no | Superficie di finitura: interno | Livello: 1 - Piano Primo |  | 4.02 | 0 | Grafica - Contrassegno centrale visibile: no
208146 | 1 - Piano Primo | 15.449 | 3.76414 | 3.02871 | no | Non portante | -0.16 | no | Superficie di finitura: interno | Livello: 1 - Piano Primo |  | 4.02 | 0 | Grafica - Contrassegno centrale visibile: no
208203 | 0 - Piano Terra | 6.224 | 1.6 | 1.2448 | no | Non portante | 0 | no | Superficie di finitura: interno | Livello: 0 - Piano Terra | Livello: 1 - Piano Primo | 4.13 | -0.56
208219 | 0 - Piano Terra | 19.5278 | 5.02 | 3.90556 | no | Non portante | 0 | no | Superficie di finitura: interno | Livello: 0 - Piano Terra | Livello: 1 - Piano Primo | 3.89 | -0.8
208242 | 1 - Piano Primo | 15.6624 | 5.02 | 3.13248 | no | Non portante | 0 | no | Superficie di finitura: interno | Livello: 1 - Piano Primo | Livello: 2 - Piano Secondo | 3.12 | -0.8
208487 | 0 - Piano Terra | 59.4621 | 15.7986 | 11.8924 | no | Non portante | 0 | no | Superficie di finitura: esterno | Livello: 0 - Piano Terra | Livello: 1 - Piano Primo | 4.03 | -0.66

# IfcWallStandardCase: Muro di base:Blocchetti - 25 cm (12)
In: 0 - Piano Terra
Type - PredefinedType: STANDARD; Material: Sabbia e Calcestruzzo 0.25 m
Type - Altro - Categoria: Muri; Nome famiglia: Muro di base
Type - Costruzione - Funzione: Esterno; Ripiegatura agli inserti: Non ripiegare; Ripiegatura alle estremità: Nessuno; Larghezza: 0.25 m
Type - Dati identità - Nome del tipo: Blocchetti - 25 cm; Nota chiave: Mb/3
Type - Grafica - Colore del retino a dettaglio basso: 0
Type - Proprietà analitiche - Ruvidità: 3; Assorbimento: 0.7
Altro - Famiglia: Muro di base: Blocchetti - 25 cm; Famiglia e tipo: Muro di base: Blocchetti - 25 cm; ID tipo: Muro di base: Blocchetti - 25 cm; Tipo: Muro di base: Blocchetti - 25 cm
Fasi - Fase di creazione: Stato di Fatto
Strutturale - Attiva modello analitico: no; Strutturale: no; Utilizzo strutturale: Non portante
Vincoli - Offset base: 0 m; Delimita il locale: yes; Distanza estensione base: 0 m; Distanza estensione superiore: 0 m; La base è associata: no; La parte superiore è associata: no; Relativo a massa: no; Vincolo di base: Livello: 0 - Piano Terra; Vincolo parte superiore: Livello: 1 - Piano Primo
Pset_WallCommon - ExtendToStructure: no; IsExternal: yes; LoadBearing: no; Reference: Blocchetti - 25 cm
Name (Muro di base:Blocchetti - 25 cm:...) | Area (m2) | Lunghezza (m) | Volume (m3) | Linea di ubicazione | Altezza non collegata (m) | Offset superiore (m)
204137 | 19.3954 | 7.12569 | 4.84886 | Superficie di finitura: esterno | 3.63 | -1.06
204138 | 12.7238 | 7.39425 | 3.18096 | Superficie di finitura: esterno | 3.63 | -1.06
204139 | 16.3989 | 7.4836 | 4.09973 | Superficie di finitura: esterno | 3.63 | -1.06
204140 | 23.8171 | 7.48563 | 5.95427 | Superficie di finitura: esterno | 3.63 | -1.06
204141 | 20.7382 | 7.48281 | 5.18455 | Superficie di finitura: esterno | 3.63 | -1.06
204142 | 18.1732 | 7.4731 | 4.54329 | Superficie di finitura: esterno | 3.63 | -1.06
204144 | 33.0395 | 7.975 | 8.25988 | Linea d'asse del muro | 4.29 | -0.4
204145 | 33.0395 | 7.975 | 8.25988 | Linea d'asse del muro | 4.29 | -0.4
204146 | 33.0395 | 7.975 | 8.25987 | Linea d'asse del muro | 4.29 | -0.4
204147 | 33.0395 | 7.975 | 8.25987 | Linea d'asse del muro | 4.29 | -0.4
204148 | 33.0395 | 7.975 | 8.25987 | Linea d'asse del muro | 4.29 | -0.4
204149 | 22.0899 | 5.085 | 5.52248 | Linea d'asse del muro | 4.69 | 0

# IfcWallStandardCase: Muro di base:Intonaco int 1 cm (4)
Type - PredefinedType: STANDARD; Material: Intonaco - Bianco 0.01 m
Type - Altro - Categoria: Muri; Nome famiglia: Muro di base
Type - Costruzione - Funzione: Esterno; Ripiegatura agli inserti: Non ripiegare; Ripiegatura alle estremità: Nessuno; Larghezza: 0.01 m
Type - Dati identità - Nome del tipo: Intonaco int 1 cm; Nota chiave: Mb/3
Type - Grafica - Colore del retino a dettaglio basso: 0
Type - Proprietà analitiche - Ruvidità: 3; Assorbimento: 0.7
Altro - Famiglia: Muro di base: Intonaco int 1 cm; Famiglia e tipo: Muro di base: Intonaco int 1 cm; ID tipo: Muro di base: Intonaco int 1 cm; Tipo: Muro di base: Intonaco int 1 cm
Fasi - Fase di creazione: Stato di Fatto
Strutturale - Attiva modello analitico: no; Strutturale: no; Utilizzo strutturale: Non portante
Vincoli - Delimita il locale: yes; Distanza estensione base: 0 m; Distanza estensione superiore: 0 m; La base è associata: no; La parte superiore è associata: no; Offset superiore: 0 m; Relativo a massa: no
Pset_WallCommon - ExtendToStructure: no; IsExternal: yes; LoadBearing: no; Reference: Intonaco int 1 cm
Name (Muro di base:Intonaco int 1 cm:...) | In | Area (m2) | Lunghezza (m) | Volume (m3) | Offset base (m) | Vincolo di base | Linea di ubicazione | Altezza non collegata (m)
204163 | 0 - Piano Terra | 16.1778 | 3.4475 | 0.161688 | 0 | Livello: 0 - Piano Terra | Superficie di finitura: interno | 4.69 | Grafica - Contrassegno centrale visibile: no
204164 | 0 - Piano Terra | 16.6334 | 3.53526 | 0.166086 | 0 | Livello: 0 - Piano Terra | Superficie di finitura: interno | 4.69 | Grafica - Contrassegno centrale visibile: no
204237 | 0 - Piano Terra | 1.9637 | 0.797709 | 0.0195554 | 0 | Livello: 0 - Piano Terra | Superficie di finitura: interno | 2.47
204857 | 1 - Piano Primo | 1.38923 | 0.207044 | 0.0137137 | -0.16 | Livello: 1 - Piano Primo | Superficie di finitura: esterno | 4.02

# IfcWallStandardCase: Muro di base:Lamierino (10)
Type - PredefinedType: STANDARD; Material: Alluminio 0.01 m
Type - Altro - Categoria: Muri; Nome famiglia: Muro di base
Type - Costruzione - Funzione: Esterno; Ripiegatura agli inserti: Non ripiegare; Ripiegatura alle estremità: Nessuno; Larghezza: 0.01 m
Type - Dati identità - Nome del tipo: Lamierino; Nota chiave: Mb/3
Type - Grafica - Colore del retino a dettaglio basso: 0
Type - Proprietà analitiche - Ruvidità: 3; Assorbimento: 0.7; Coefficiente di scambio termico (U): 23000; Massa termica: 24219; Resistenza termica (R): 0.0000434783
Altro - Famiglia: Muro di base: Lamierino; Famiglia e tipo: Muro di base: Lamierino; ID tipo: Muro di base: Lamierino; Tipo: Muro di base: Lamierino
Fasi - Fase di creazione: Stato di Fatto
Strutturale - Attiva modello analitico: no; Strutturale: no; Utilizzo strutturale: Non portante
Vincoli - Delimita il locale: yes; Distanza estensione base: 0 m; Distanza estensione superiore: 0 m; La base è associata: no; La parte superiore è associata: no; Offset superiore: 0 m; Relativo a massa: no
Pset_WallCommon - ExtendToStructure: no; IsExternal: yes; LoadBearing: no; Reference: Lamierino; ThermalTransmittance: 23000 kg/K/s3
Name (Muro di base:Lamierino:...) | In | Area (m2) | Lunghezza (m) | Volume (m3) | Offset base (m) | Vincolo di base | Linea di ubicazione | Altezza non collegata (m) | Contrassegno centrale visibile
204234 | 0 - Piano Terra | 0.458226 | 0.10077 | 0.00442745 | 0 | Livello: 0 - Piano Terra | Superficie di finitura: interno | 2.47
204235 | 0 - Piano Terra | 0.482089 | 0.116264 | 0.00478816 | 0 | Livello: 0 - Piano Terra | Superficie di finitura: interno | 2.47
205823 | 0 - Piano Terra | 50.4932 | 1.55509 | 0.499744 | 8.45 | Livello: 0 - Piano Terra | Superficie di finitura: esterno | 32.15 | no
205824 | 0 - Piano Terra | 50.4932 | 1.55509 | 0.500016 | 8.45 | Livello: 0 - Piano Terra | Superficie di finitura: esterno | 32.15 | no
205825 | 2 - Piano Secondo | 50.5011 | 1.55509 | 0.499957 | 0 | Livello: 2 - Piano Secondo | Superficie di finitura: esterno | 32.15 | no
205826 | 2 - Piano Secondo | 50.5011 | 1.55509 | 0.499957 | 0 | Livello: 2 - Piano Secondo | Superficie di finitura: esterno | 32.15 | no
205827 | 0 - Piano Terra | 50.4932 | 1.55509 | 0.499744 | 8.45 | Livello: 0 - Piano Terra | Superficie di finitura: esterno | 32.15 | no
205828 | 0 - Piano Terra | 50.4932 | 1.55509 | 0.500017 | 8.45 | Livello: 0 - Piano Terra | Superficie di finitura: esterno | 32.15 | no
205829 | 0 - Piano Terra | 50.4932 | 1.55509 | 0.499748 | 8.45 | Livello: 0 - Piano Terra | Superficie di finitura: esterno | 32.15 | no
205830 | 0 - Piano Terra | 50.4932 | 1.55509 | 0.500012 | 8.45 | Livello: 0 - Piano Terra | Superficie di finitura: esterno | 32.15 | no

# IfcWallStandardCase: Muro di base:Malta di raccordo (13)
Type - PredefinedType: STANDARD; Material: Sabbia e Calcestruzzo 0.005 m
Type - Altro - Categoria: Muri; Nome famiglia: Muro di base
Type - Costruzione - Funzione: Esterno; Ripiegatura agli inserti: Non ripiegare; Ripiegatura alle estremità: Nessuno; Larghezza: 0.005 m
Type - Dati identità - Nome del tipo: Malta di raccordo; Nota chiave: Mb/3
Type - Grafica - Colore del retino a dettaglio basso: 0
Type - Proprietà analitiche - Ruvidità: 3; Assorbimento: 0.7
Altro - Famiglia: Muro di base: Malta di raccordo; Famiglia e tipo: Muro di base: Malta di raccordo; ID tipo: Muro di base: Malta di raccordo; Tipo: Muro di base: Malta di raccordo
Fasi - Fase di creazione: Stato di Fatto
Strutturale - Attiva modello analitico: no; Strutturale: no; Utilizzo strutturale: Non portante
Vincoli - Delimita il locale: yes; Distanza estensione base: 0 m; Distanza estensione superiore: 0 m; La base è associata: no; La parte superiore è associata: no; Offset superiore: 0 m; Relativo a massa: no
Pset_WallCommon - ExtendToStructure: no; IsExternal: yes; LoadBearing: no; Reference: Malta di raccordo
Name (Muro di base:Malta di raccordo:...) | In | Area (m2) | Lunghezza (m) | Volume (m3) | Offset base (m) | Linea di ubicazione | Vincolo di base | Altezza non collegata (m)
204229 | 0 - Piano Terra | 1.4455 | 0.246517 | 0.0072151 | 0 | Superficie di finitura: esterno | Livello: 0 - Piano Terra | 4.53
204230 | 0 - Piano Terra | 0.573506 | 0.243651 | 0.00284984 | 0 | Superficie di finitura: esterno | Livello: 0 - Piano Terra | 4.13
204231 | 0 - Piano Terra | 1.20289 | 0.152334 | 0.00596658 | 0 | Superficie di finitura: esterno | Livello: 0 - Piano Terra | 4.13
204232 | 0 - Piano Terra | 1.42724 | 0.209289 | 0.00709035 | 0 | Superficie di finitura: esterno | Livello: 0 - Piano Terra | 4.13
204858 | 1 - Piano Primo | 0.0573671 | 0.190356 | 0.00027474 | 0 | Superficie di finitura: interno | Livello: 1 - Piano Primo | 1.03
204873 | 0 - Piano Terra | 0.344811 | 0.195051 | 0.00171199 | 0 | Superficie di finitura: interno | Livello: 0 - Piano Terra | 1.03
204874 | 0 - Piano Terra | 1.53379 | 0.234289 | 0.00762798 | 0 | Superficie di finitura: interno | Livello: 0 - Piano Terra | 4.13
204879 | 1 - Piano Primo | 1.34577 | 0.195051 | 0.00668177 | -0.16 | Superficie di finitura: interno | Livello: 1 - Piano Primo | 4.02
207935 | 1 - Piano Primo | 1.39892 | 0.242708 | 0.00697941 | -0.16 | Superficie di finitura: interno | Livello: 1 - Piano Primo | 4.02
207936 | 1 - Piano Primo | 0.557659 | 0.242641 | 0.00277262 | -0.16 | Superficie di finitura: interno | Livello: 1 - Piano Primo | 4.02
208147 | 1 - Piano Primo | 0.558231 | 0.243651 | 0.00277394 | -0.16 | Superficie di finitura: interno | Livello: 1 - Piano Primo | 4.02
208950 | 0 - Piano Terra | 1.4372 | 0.242641 | 0.00717029 | 0 | Superficie di finitura: interno | Livello: 0 - Piano Terra | 4.13
208951 | 0 - Piano Terra | 1.4372 | 0.242708 | 0.00717039 | 0 | Superficie di finitura: interno | Livello: 0 - Piano Terra | 4.13

# IfcWallStandardCase: Muro di base:Pannelli Pref - 17 cm (10)
Type - PredefinedType: STANDARD; Material: Default - Calcestruzzo 0.17 m
Type - Altro - Categoria: Muri; Nome famiglia: Muro di base
Type - Costruzione - Funzione: Esterno; Ripiegatura agli inserti: Non ripiegare; Ripiegatura alle estremità: Nessuno; Larghezza: 0.17 m
Type - Dati identità - Nome del tipo: Pannelli Pref - 17 cm; Nota chiave: Mb/3
Type - Grafica - Colore del retino a dettaglio basso: 0
Type - Proprietà analitiche - Ruvidità: 3; Assorbimento: 0.7
Altro - Famiglia: Muro di base: Pannelli Pref - 17 cm; Famiglia e tipo: Muro di base: Pannelli Pref - 17 cm; ID tipo: Muro di base: Pannelli Pref - 17 cm; Tipo: Muro di base: Pannelli Pref - 17 cm
Fasi - Fase di creazione: Stato di Fatto
Strutturale - Attiva modello analitico: no; Strutturale: no; Utilizzo strutturale: Non portante
Vincoli - Delimita il locale: yes; Distanza estensione base: 0 m; Distanza estensione superiore: 0 m; La base è associata: no; La parte superiore è associata: no; Relativo a massa: no; Linea di ubicazione: Superficie di finitura: interno; Altezza non collegata: 2.4 m
Pset_WallCommon - ExtendToStructure: no; IsExternal: yes; LoadBearing: no; Reference: Pannelli Pref - 17 cm
Name (Muro di base:Pannelli Pref - 17 cm:...) | In | Area (m2) | Lunghezza (m) | Volume (m3) | Vincolo di base | Offset base (m) | Offset superiore (m)
204222 | 1 - Piano Primo | 114.513 | 48.0237 | 19.4672 | Livello: 1 - Piano Primo | -1.47 | -2.99 | Vincoli - Vincolo parte superiore: Livello: 2 - Piano Secondo
204223 | 1 - Piano Primo | 114.46 | 48.0017 | 19.4582 | Livello: 1 - Piano Primo | -1.47 | -2.99 | Vincoli - Vincolo parte superiore: Livello: 2 - Piano Secondo
204224 | 1 - Piano Primo | 18.2966 | 7.89859 | 3.11042 | Livello: 1 - Piano Primo | -1.47 | -2.99 | Vincoli - Vincolo parte superiore: Livello: 2 - Piano Secondo
204225 | 1 - Piano Primo | 114.42 | 47.675 | 19.4514 | Livello: 1 - Piano Primo | -1.47 | -2.99 | Vincoli - Vincolo parte superiore: Livello: 2 - Piano Secondo
204239 | 2 - Piano Secondo | 114.513 | 48.0237 | 19.4672 | Livello: 2 - Piano Secondo | -1.39 | 0
204240 | 2 - Piano Secondo | 114.052 | 47.5217 | 19.3889 | Livello: 2 - Piano Secondo | -1.39 | 0
204241 | 2 - Piano Secondo | 18.2366 | 7.89859 | 3.10022 | Livello: 2 - Piano Secondo | -1.39 | 0
204242 | 2 - Piano Secondo | 114.384 | 47.66 | 19.4453 | Livello: 2 - Piano Secondo | -1.39 | 0
204243 | 1 - Piano Primo | 114.412 | 47.6717 | 19.4488 | Livello: 1 - Piano Primo | -1.47 | -2.99 | Vincoli - Vincolo parte superiore: Livello: 2 - Piano Secondo
204252 | 2 - Piano Secondo | 114.46 | 48.0017 | 19.4582 | Livello: 2 - Piano Secondo | -1.39 | 0

# IfcWallStandardCase: Muro di base:Pannello coibentato - 6 cm (7)
In: 0 - Piano Terra
Type - PredefinedType: STANDARD; Material: Alluminio 0.01 m, Plastica 0.04 m, Alluminio 0.01 m
Type - Altro - Categoria: Muri; Nome famiglia: Muro di base
Type - Costruzione - Funzione: Esterno; Ripiegatura agli inserti: Non ripiegare; Ripiegatura alle estremità: Nessuno; Larghezza: 0.06 m
Type - Dati identità - Nome del tipo: Pannello coibentato - 6 cm; Nota chiave: Mb/3
Type - Grafica - Colore del retino a dettaglio basso: 0
Type - Materiali e finiture - Materiale strutturale: Alluminio
Type - Proprietà analitiche - Ruvidità: 3; Assorbimento: 0.7; Coefficiente di scambio termico (U): 12.5363; Massa termica: 135876; Resistenza termica (R): 0.0797682
Altro - Famiglia: Muro di base: Pannello coibentato - 6 cm; Famiglia e tipo: Muro di base: Pannello coibentato - 6 cm; ID tipo: Muro di base: Pannello coibentato - 6 cm; Tipo: Muro di base: Pannello coibentato - 6 cm
Fasi - Fase di creazione: Stato di Fatto
Strutturale - Attiva modello analitico: no; Strutturale: no; Utilizzo strutturale: Non portante
Vincoli - Delimita il locale: yes; Distanza estensione base: 0 m; Distanza estensione superiore: 0 m; La base è associata: no; Relativo a massa: no; Vincolo di base: Livello: 0 - Piano Terra
Pset_WallCommon - IsExternal: yes; LoadBearing: no; Reference: Pannello coibentato - 6 cm; ThermalTransmittance: 12.5363 kg/K/s3
Name (Muro di base:Pannello coibentato - 6 cm:...) | Area (m2) | Lunghezza (m) | Volume (m3) | Offset base (m) | La parte superiore è associata = ExtendToStructure | Linea di ubicazione | Vincolo parte superiore | Altezza non collegata (m) | Offset superiore (m)
204133 | 186.985 | 47.1017 | 11.2191 | 0 | no | Superficie di finitura: esterno | Livello: 1 - Piano Primo | 4.03 | -0.66
204134 | 0.25285 | 0.035 | 0.015171 | 0 | no | Superficie di finitura: esterno | Livello: 1 - Piano Primo | 4.03 | -0.66
204135 | 0.25285 | 0.035 | 0.015171 | 0 | no | Superficie di finitura: esterno | Livello: 1 - Piano Primo | 3.89 | -0.8
204159 | 33.4667 | 7.955 | 2.00801 | 0 | yes | Superficie di finitura: esterno | Livello: 1 - Piano Primo | 4.29 | -0.4
205730 | 17.9784 | 7.48 | 1.0787 | 0.09 | yes | Superficie di finitura: interno |  | 1.03 | 0
205731 | 34.6712 | 8.265 | 2.08027 | 0 | yes | Superficie di finitura: interno | Livello: 1 - Piano Primo | 4.69 | 0
205735 | 92.8905 | 32.2554 | 5.57343 | 0.09 | yes | Superficie di finitura: interno |  | 1.03 | 0

# IfcWallStandardCase: Muro di base:Pareti container (5)
In: 2 - Piano Secondo
Type - PredefinedType: STANDARD; Material: Acciaio 0.05 m
Type - Altro - Categoria: Muri; Nome famiglia: Muro di base
Type - Costruzione - Funzione: Esterno; Ripiegatura agli inserti: Non ripiegare; Ripiegatura alle estremità: Nessuno; Larghezza: 0.05 m
Type - Dati identità - Nome del tipo: Pareti container; Nota chiave: Mb/3
Type - Grafica - Colore del retino a dettaglio basso: 0
Type - Proprietà analitiche - Ruvidità: 3; Assorbimento: 0.7; Coefficiente di scambio termico (U): 900; Massa termica: 188400; Resistenza termica (R): 0.00111111
Altro - Famiglia: Muro di base: Pareti container; Famiglia e tipo: Muro di base: Pareti container; ID tipo: Muro di base: Pareti container; Tipo: Muro di base: Pareti container
Fasi - Fase di creazione: Stato di Fatto
Strutturale - Attiva modello analitico: no; Strutturale: no; Utilizzo strutturale: Non portante
Vincoli - Delimita il locale: yes; Distanza estensione base: 0 m; Distanza estensione superiore: 0 m; La base è associata: no; Linea di ubicazione: Superficie di finitura: esterno; Offset superiore: 0 m; Relativo a massa: no; La parte superiore è associata: yes; Vincolo di base: Livello: 2 - Piano Secondo; Offset base: 0.1 m
Pset_WallCommon - IsExternal: yes; ExtendToStructure: yes; LoadBearing: no; Reference: Pareti container; ThermalTransmittance: 900 kg/K/s3
Name (Muro di base:Pareti container:...) | Area (m2) | Lunghezza (m) | Volume (m3) | Altezza non collegata (m)
205894 | 5.84211 | 2.38454 | 0.292106 | 2.55
205895 | 14.5269 | 5.97933 | 0.726343 | 2.55
205902 | 5.84211 | 2.38454 | 0.292106 | 32.15
205907 | 5.41286 | 2.18433 | 0.270643 | 32.15
205908 | 7.1295 | 2.885 | 0.356475 | 32.15

# IfcWallStandardCase: Muro di base:Rivestimento 15 cm (69)
Type - PredefinedType: STANDARD; Material: Alluminio 0.15 m
Type - Altro - Categoria: Muri; Nome famiglia: Muro di base
Type - Costruzione - Funzione: Esterno; Ripiegatura agli inserti: Non ripiegare; Ripiegatura alle estremità: Nessuno; Larghezza: 0.15 m
Type - Dati identità - Nome del tipo: Rivestimento 15 cm; Nota chiave: Mb/3
Type - Grafica - Colore del retino a dettaglio basso: 0
Type - Proprietà analitiche - Ruvidità: 3; Assorbimento: 0.7; Coefficiente di scambio termico (U): 1533.33; Massa termica: 363285; Resistenza termica (R): 0.000652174
Altro - Famiglia: Muro di base: Rivestimento 15 cm; Famiglia e tipo: Muro di base: Rivestimento 15 cm; ID tipo: Muro di base: Rivestimento 15 cm; Tipo: Muro di base: Rivestimento 15 cm
Fasi - Fase di creazione: Stato di Fatto
Strutturale - Attiva modello analitico: no; Strutturale: no; Utilizzo strutturale: Non portante
Vincoli - Delimita il locale: yes; Distanza estensione base: 0 m; Distanza estensione superiore: 0 m; La base è associata: no; La parte superiore è associata: no; Offset superiore: 0 m; Relativo a massa: no
Pset_WallCommon - ExtendToStructure: no; IsExternal: yes; LoadBearing: no; Reference: Rivestimento 15 cm; ThermalTransmittance: 1533.33 kg/K/s3
Name (Muro di base:Rivestimento 15 cm:...) | In | Area (m2) | Lunghezza (m) | Volume (m3) | Offset base (m) | Vincolo di base | Linea di ubicazione | Altezza non collegata (m) | Contrassegno centrale visibile
204162 | 0 - Piano Terra | 36.7511 | 9.71637 | 5.5053 | 0 | Livello: 0 - Piano Terra | Superficie di finitura: interno | 4.69 | Vincoli - Vincolo parte superiore: Livello: 1 - Piano Primo
204172 | 0 - Piano Terra | 14.4075 | 3.05103 | 2.14637 | 0 | Livello: 0 - Piano Terra | Superficie di finitura: interno | 4.69 | Vincoli - Vincolo parte superiore: Livello: 1 - Piano Primo
204173 | 0 - Piano Terra | 25.5424 | 5.3958 | 3.79391 | 0 | Livello: 0 - Piano Terra | Superficie di finitura: interno | 4.69 | no | Vincoli - Vincolo parte superiore: Livello: 1 - Piano Primo
204174 | 0 - Piano Terra | 9.7659 | 2.07425 | 1.45923 | 0 | Livello: 0 - Piano Terra | Superficie di finitura: interno | 4.69 | no | Vincoli - Vincolo parte superiore: Livello: 1 - Piano Primo
204175 | 0 - Piano Terra | 14.0812 | 2.98834 | 2.10226 | 0 | Livello: 0 - Piano Terra | Superficie di finitura: interno | 4.69 | no | Vincoli - Vincolo parte superiore: Livello: 1 - Piano Primo
204176 | 0 - Piano Terra | 8.20247 | 1.74331 | 1.22642 | 0 | Livello: 0 - Piano Terra | Superficie del nucleo: esterno | 4.69 | no | Vincoli - Vincolo parte superiore: Livello: 1 - Piano Primo
204226 | 0 - Piano Terra | 20.9414 | 4.43645 | 3.12117 | 0 | Livello: 0 - Piano Terra | Superficie di finitura: interno | 4.69 | no | Vincoli - Vincolo parte superiore: Livello: 1 - Piano Primo
204227 | 0 - Piano Terra | 12.8719 | 2.73221 | 1.92211 | 0 | Livello: 0 - Piano Terra | Superficie di finitura: interno | 4.69 | no | Vincoli - Vincolo parte superiore: Livello: 1 - Piano Primo
204228 | 0 - Piano Terra | 42.8809 | 9.14296 | 6.43207 | 0 | Livello: 0 - Piano Terra | Superficie di finitura: interno | 4.69 | Vincoli - Vincolo parte superiore: Livello: 1 - Piano Primo
204859 | 0 - Piano Terra | 5.53379 | 2.49125 | 0.829587 | 2.47 | Livello: 0 - Piano Terra | Superficie di finitura: interno | 2.22 | Vincoli - Vincolo parte superiore: Livello: 1 - Piano Primo
204860 | 0 - Piano Terra | 5.6794 | 2.54449 | 0.847316 | 2.47 | Livello: 0 - Piano Terra | Superficie di finitura: interno | 2.22 | no | Vincoli - Vincolo parte superiore: Livello: 1 - Piano Primo
204861 | 1 - Piano Primo | 5.5433 | 3.07 | 0.831495 | -4.69 | Livello: 1 - Piano Primo | Superficie di finitura: interno | 4.69
204915 | 0 - Piano Terra | 5.54341 | 3.06981 | 0.831362 | 0 | Livello: 0 - Piano Terra | Superficie di finitura: interno | 4.69 | Vincoli - Vincolo parte superiore: Livello: 1 - Piano Primo
204916 | 0 - Piano Terra | 31.3213 | 6.67811 | 4.69805 | 0 | Livello: 0 - Piano Terra | Superficie di finitura: interno | 4.69 | Vincoli - Vincolo parte superiore: Livello: 1 - Piano Primo
204917 | 0 - Piano Terra | 12.1436 | 2.57782 | 1.81349 | 0 | Livello: 0 - Piano Terra | Superficie di finitura: interno | 4.69 | no | Vincoli - Vincolo parte superiore: Livello: 1 - Piano Primo
204919 | 0 - Piano Terra | 7.88366 | 1.67342 | 1.17725 | 0 | Livello: 0 - Piano Terra | Superficie di finitura: interno | 4.69 | no | Vincoli - Vincolo parte superiore: Livello: 1 - Piano Primo
204920 | 0 - Piano Terra | 16.2409 | 4.00848 | 2.40678 | 0 | Livello: 0 - Piano Terra | Superficie di finitura: interno | 4.69 | no | Vincoli - Vincolo parte superiore: Livello: 1 - Piano Primo
204921 | 0 - Piano Terra | 14.5592 | 3.0822 | 2.1683 | 0 | Livello: 0 - Piano Terra | Superficie di finitura: interno | 4.69 | Vincoli - Vincolo parte superiore: Livello: 1 - Piano Primo
204922 | 0 - Piano Terra | 18.1181 | 4.40366 | 2.68509 | 0 | Livello: 0 - Piano Terra | Superficie di finitura: interno | 4.69 | no | Vincoli - Vincolo parte superiore: Livello: 1 - Piano Primo
204923 | 0 - Piano Terra | 5.73208 | 1.21806 | 0.856908 | 0 | Livello: 0 - Piano Terra | Superficie di finitura: interno | 4.69 | no | Vincoli - Vincolo parte superiore: Livello: 1 - Piano Primo
204924 | 0 - Piano Terra | 11.8685 | 2.51867 | 1.77188 | 0 | Livello: 0 - Piano Terra | Superficie di finitura: interno | 4.69 | no | Vincoli - Vincolo parte superiore: Livello: 1 - Piano Primo
204925 | 0 - Piano Terra | 8.02734 | 1.6993 | 1.19546 | 0 | Livello: 0 - Piano Terra | Superficie di finitura: interno | 4.69 | no | Vincoli - Vincolo parte superiore: Livello: 1 - Piano Primo
204926 | 0 - Piano Terra | 17.874 | 3.78811 | 2.66494 | 0 | Livello: 0 - Piano Terra | Superficie di finitura: interno | 4.69 | no | Vincoli - Vincolo parte superiore: Livello: 1 - Piano Primo
204927 | 0 - Piano Terra | 8.99561 | 1.91103 | 1.34441 | 0 | Livello: 0 - Piano Terra | Superficie di finitura: interno | 4.69 | no | Vincoli - Vincolo parte superiore: Livello: 1 - Piano Primo
204928 | 0 - Piano Terra | 49.1229 | 12.3568 | 7.36614 | 0 | Livello: 0 - Piano Terra | Superficie di finitura: interno | 4.69 | Vincoli - Vincolo parte superiore: Livello: 1 - Piano Primo
204929 | 0 - Piano Terra | 7.00794 | 2.80159 | 1.0506 | 2.47 | Livello: 0 - Piano Terra | Superficie di finitura: interno | 2.5
204930 | 0 - Piano Terra | 4.32569 | 1.76672 | 0.644749 | 2.47 | Livello: 0 - Piano Terra | Superficie di finitura: interno | 2.43294 | no
204931 | 0 - Piano Terra | 22.5555 | 4.77871 | 3.36183 | 0 | Livello: 0 - Piano Terra | Superficie di finitura: interno | 4.69 | no | Vincoli - Vincolo parte superiore: Livello: 1 - Piano Primo
205809 | 0 - Piano Terra | 236.022 | 28.0052 | 35.4016 | 0 | Livello: 0 - Piano Terra | Superficie di finitura: esterno | 8.45
205810 | 0 - Piano Terra | 149.351 | 17.5989 | 22.4017 | 0 | Livello: 0 - Piano Terra | Superficie di finitura: esterno | 8.45
205811 | 0 - Piano Terra | 1007.52 | 119.233 | 151.128 | 0 | Livello: 0 - Piano Terra | Superficie di finitura: esterno | 8.45
205812 | 0 - Piano Terra | 182.8 | 21.7071 | 27.4187 | 0 | Livello: 0 - Piano Terra | Superficie di finitura: esterno | 8.45
205813 | 0 - Piano Terra | 150.587 | 17.6708 | 22.5879 | 0 | Livello: 0 - Piano Terra | Superficie di finitura: esterno | 8.45
207486 | 1 - Piano Primo | 43.696 | 9.71637 | 6.5544 | 0 | Livello: 1 - Piano Primo | Superficie di finitura: interno | 4.95
207489 | 0 - Piano Terra | 15.6879 | 3.88736 | 2.32198 | 0 | Livello: 0 - Piano Terra | Superficie di finitura: esterno | 4.69 | no | Vincoli - Vincolo parte superiore: Livello: 1 - Piano Primo
207510 | 0 - Piano Terra | 17.5651 | 4.28411 | 2.60097 | 0 | Livello: 0 - Piano Terra | Superficie di finitura: interno | 4.69 | no | Vincoli - Vincolo parte superiore: Livello: 1 - Piano Primo
207511 | 0 - Piano Terra | 6.60872 | 1.4032 | 0.987167 | 0 | Livello: 0 - Piano Terra | Superficie di finitura: interno | 4.69 | no | Vincoli - Vincolo parte superiore: Livello: 1 - Piano Primo
207568 | 1 - Piano Primo | 22.1023 | 4.43645 | 3.2942 | 0 | Livello: 1 - Piano Primo | Superficie di finitura: interno | 4.95 | no
207570 | 1 - Piano Primo | 13.5855 | 2.73221 | 2.02866 | 0 | Livello: 1 - Piano Primo | Superficie di finitura: interno | 4.95 | no
207572 | 1 - Piano Primo | 45.2581 | 9.14296 | 6.78865 | 0 | Livello: 1 - Piano Primo | Superficie di finitura: interno | 4.95
207574 | 1 - Piano Primo | 10.7965 | 3.07 | 1.61947 | 0 | Livello: 1 - Piano Primo | Superficie di finitura: interno | 4.95
207577 | 1 - Piano Primo | 15.2062 | 3.05103 | 2.26536 | 0 | Livello: 1 - Piano Primo | Superficie di finitura: interno | 4.95
207578 | 1 - Piano Primo | 14.8618 | 2.98834 | 2.21881 | 0 | Livello: 1 - Piano Primo | Superficie di finitura: interno | 4.95 | no
207579 | 1 - Piano Primo | 21.4441 | 4.28411 | 3.181 | 0 | Livello: 1 - Piano Primo | Superficie di finitura: interno | 4.95 | no
207580 | 1 - Piano Primo | 6.97509 | 1.4032 | 1.04189 | 0 | Livello: 1 - Piano Primo | Superficie di finitura: interno | 4.95 | no
207581 | 1 - Piano Primo | 26.8831 | 5.3958 | 4.00638 | 0 | Livello: 1 - Piano Primo | Superficie di finitura: interno | 4.95 | no
207582 | 1 - Piano Primo | 10.3073 | 2.07425 | 1.54013 | 0 | Livello: 1 - Piano Primo | Superficie di finitura: interno | 4.95 | no
207583 | 1 - Piano Primo | 8.65719 | 1.74331 | 1.29441 | 0 | Livello: 1 - Piano Primo | Superficie del nucleo: esterno | 4.95 | no
207584 | 1 - Piano Primo | 12.3389 | 2.49125 | 1.84975 | 0 | Livello: 1 - Piano Primo | Superficie di finitura: interno | 4.95
207585 | 1 - Piano Primo | 12.6635 | 2.54449 | 1.88928 | 0 | Livello: 1 - Piano Primo | Superficie di finitura: interno | 4.95 | no
207586 | 1 - Piano Primo | 19.4621 | 3.88736 | 2.88634 | 0 | Livello: 1 - Piano Primo | Superficie di finitura: esterno | 4.95 | no
207871 | 1 - Piano Primo | 56.7775 | 12.3568 | 8.51493 | 0 | Livello: 1 - Piano Primo | Superficie di finitura: interno | 4.95
207873 | 1 - Piano Primo | 9.4943 | 1.91103 | 1.41894 | 0 | Livello: 1 - Piano Primo | Superficie di finitura: interno | 4.95 | no
207875 | 1 - Piano Primo | 18.8649 | 3.78811 | 2.81267 | 0 | Livello: 1 - Piano Primo | Superficie di finitura: interno | 4.95 | no
207877 | 1 - Piano Primo | 8.47235 | 1.6993 | 1.26173 | 0 | Livello: 1 - Piano Primo | Superficie di finitura: interno | 4.95 | no
207879 | 1 - Piano Primo | 6.04985 | 1.21806 | 0.904413 | 0 | Livello: 1 - Piano Primo | Superficie di finitura: interno | 4.95 | no
207881 | 1 - Piano Primo | 22.0272 | 4.40366 | 3.26966 | 0 | Livello: 1 - Piano Primo | Superficie di finitura: interno | 4.95 | no
207883 | 1 - Piano Primo | 15.3663 | 3.0822 | 2.2885 | 0 | Livello: 1 - Piano Primo | Superficie di finitura: interno | 4.95
207885 | 1 - Piano Primo | 18.5754 | 3.7216 | 2.76328 | 0 | Livello: 1 - Piano Primo | Superficie di finitura: interno | 4.95 | no
207887 | 1 - Piano Primo | 1.48556 | 0.286887 | 0.213029 | 0 | Livello: 1 - Piano Primo | Superficie di finitura: interno | 4.95 | no
207888 | 1 - Piano Primo | 8.3207 | 1.67342 | 1.24251 | 0 | Livello: 1 - Piano Primo | Superficie di finitura: interno | 4.95 | no
207892 | 1 - Piano Primo | 12.8168 | 2.57782 | 1.91403 | 0 | Livello: 1 - Piano Primo | Superficie di finitura: interno | 4.95 | no
207894 | 1 - Piano Primo | 23.8059 | 4.77871 | 3.5482 | 0 | Livello: 1 - Piano Primo | Superficie di finitura: interno | 4.95 | no
207896 | 0 - Piano Terra | 8.42232 | 1.76672 | 1.25536 | 4.90294 | Livello: 0 - Piano Terra | Superficie di finitura: interno | 4.73706 | no
207899 | 0 - Piano Terra | 15.0242 | 3.2156 | 2.25252 | 4.97 | Livello: 0 - Piano Terra | Superficie di finitura: interno | 4.67
207902 | 1 - Piano Primo | 10.7966 | 3.06981 | 1.61933 | 0 | Livello: 1 - Piano Primo | Superficie di finitura: interno | 4.95
207904 | 1 - Piano Primo | 33.0577 | 6.67811 | 4.9585 | 0 | Livello: 1 - Piano Primo | Superficie di finitura: interno | 4.95
207906 | 0 - Piano Terra | 1.03502 | 0.414006 | 0.155252 | 2.47 | Livello: 0 - Piano Terra | Superficie di finitura: interno | 2.5
207937 | 1 - Piano Primo | 12.5264 | 2.51867 | 1.87011 | 0 | Livello: 1 - Piano Primo | Superficie di finitura: interno | 4.95 | no

# IfcWallStandardCase: Muro di base:Rivestimento pannelli 5 cm (9)
In: 0 - Piano Terra
Type - PredefinedType: STANDARD; Material: Default - Finestre 0.15 m
Type - Altro - Categoria: Muri; Nome famiglia: Muro di base
Type - Costruzione - Funzione: Esterno; Ripiegatura agli inserti: Non ripiegare; Ripiegatura alle estremità: Nessuno; Larghezza: 0.15 m
Type - Dati identità - Nome del tipo: Rivestimento pannelli 5 cm; Nota chiave: Mb/3
Type - Grafica - Colore del retino a dettaglio basso: 0
Type - Proprietà analitiche - Ruvidità: 3; Assorbimento: 0.7
Altro - Famiglia: Muro di base: Rivestimento pannelli 5 cm; Famiglia e tipo: Muro di base: Rivestimento pannelli 5 cm; ID tipo: Muro di base: Rivestimento pannelli 5 cm; Tipo: Muro di base: Rivestimento pannelli 5 cm
Fasi - Fase di creazione: Stato di Fatto
Strutturale - Attiva modello analitico: no; Strutturale: no; Utilizzo strutturale: Non portante
Vincoli - Offset base: 0 m; Delimita il locale: yes; Distanza estensione base: 0 m; Distanza estensione superiore: 0 m; La base è associata: no; La parte superiore è associata: no; Linea di ubicazione: Superficie di finitura: esterno; Offset superiore: 0 m; Relativo a massa: no; Vincolo di base: Livello: 0 - Piano Terra; Altezza non collegata: 32.15 m
Pset_WallCommon - ExtendToStructure: no; IsExternal: yes; LoadBearing: no; Reference: Rivestimento pannelli 5 cm
Name (Muro di base:Rivestimento pannelli 5 cm:...) | Area (m2) | Lunghezza (m) | Volume (m3)
205814 | 96.4893 | 3.00061 | 14.4704
205815 | 35.7287 | 1.26131 | 5.3593
205816 | 10.8586 | 0.18775 | 1.6288
205817 | 1059.85 | 33.0409 | 158.978
205818 | 2563.16 | 79.725 | 384.474
205819 | 1707.11 | 53.1734 | 256.067
205820 | 9.63501 | 0.149689 | 1.44525
205821 | 38.9883 | 1.25122 | 5.8471
205822 | 91.6275 | 3.00045 | 13.7441

# IfcWallStandardCase: Muro di base:Setto CA - 30 cm (28)
Type - PredefinedType: STANDARD; Material: Default - Calcestruzzo 0.3 m
Type - Altro - Categoria: Muri; Nome famiglia: Muro di base
Type - Costruzione - Funzione: Esterno; Ripiegatura agli inserti: Non ripiegare; Ripiegatura alle estremità: Nessuno; Larghezza: 0.3 m
Type - Dati identità - Nome del tipo: Setto CA - 30 cm; Nota chiave: Mb/3
Type - Grafica - Colore del retino a dettaglio basso: 0
Type - Materiali e finiture - Materiale strutturale: Default - Calcestruzzo
Type - Proprietà analitiche - Ruvidità: 3; Assorbimento: 0.7
Altro - Famiglia: Muro di base: Setto CA - 30 cm; Famiglia e tipo: Muro di base: Setto CA - 30 cm; ID tipo: Muro di base: Setto CA - 30 cm; Tipo: Muro di base: Setto CA - 30 cm
Fasi - Fase di creazione: Stato di Fatto
Vincoli - Delimita il locale: yes; Distanza estensione base: 0 m; Distanza estensione superiore: 0 m; La base è associata: no; Offset superiore: 0 m; Relativo a massa: no
Pset_WallCommon - IsExternal: yes; Reference: Setto CA - 30 cm
Name (Muro di base:Setto CA - 30 cm:...) | In | Area (m2) | Lunghezza (m) | Volume (m3) | Attiva modello analitico = Strutturale = LoadBearing | Copriferro armatura - Altre superfici = Copriferro armatura - Superficie esterna = Copriferro armatura - Superficie interna | Utilizzo strutturale | Offset base (m) | Linea di ubicazione | Vincolo di base | Vincolo parte superiore | La parte superiore è associata = ExtendToStructure | Altezza non collegata (m)
204045 | 0 - Piano Terra | 31.6839 | 8.235 | 9.50517 | yes | Impostazioni copriferro armatura: Copriferro armatura 1 | Portante | 0 | Superficie di finitura: esterno | Livello: 0 - Piano Terra | Livello: 1 - Piano Primo | yes | 4.69
204047 | 0 - Piano Terra | 35.644 | 7.9 | 10.6932 | yes | Impostazioni copriferro armatura: Copriferro armatura 1 | Portante | 0 | Superficie di finitura: esterno | Livello: 0 - Piano Terra | Livello: 1 - Piano Primo | no | 4.69
204049 | 0 - Piano Terra | 37.9464 | 8.235 | 11.3839 | yes | Impostazioni copriferro armatura: Copriferro armatura 1 | Portante | 0 | Superficie di finitura: esterno | Livello: 0 - Piano Terra | Livello: 1 - Piano Primo | no | 4.69
204053 | 0 - Piano Terra | 38.0359 | 8.185 | 11.4108 | yes | Impostazioni copriferro armatura: Copriferro armatura 1 | Portante | 0 | Superficie di finitura: esterno | Livello: 0 - Piano Terra | Livello: 1 - Piano Primo | no | 4.69
204129 | 0 - Piano Terra | 35.0812 | 7.78 | 10.5244 | yes | Impostazioni copriferro armatura: Copriferro armatura 1 | Portante | 0 | Superficie di finitura: esterno | Livello: 0 - Piano Terra | Livello: 1 - Piano Primo | no | 4.69
204204 | 1 - Piano Primo | 19.1112 | 5.085 | 5.73336 | yes | Impostazioni copriferro armatura: Copriferro armatura 1 | Portante | 0 | Superficie di finitura: esterno | Livello: 1 - Piano Primo | Livello: 2 - Piano Secondo | no | 3.92
204208 | 1 - Piano Primo | 29.792 | 7.9 | 8.9376 | yes | Impostazioni copriferro armatura: Copriferro armatura 1 | Portante | 0 | Superficie di finitura: esterno | Livello: 1 - Piano Primo | Livello: 2 - Piano Secondo | no | 3.92
204210 | 1 - Piano Primo | 33.5552 | 8.185 | 10.0666 | yes | Impostazioni copriferro armatura: Copriferro armatura 1 | Portante | 0 | Superficie di finitura: esterno | Livello: 1 - Piano Primo | Livello: 2 - Piano Secondo | no | 3.92
204214 | 1 - Piano Primo | 31.7912 | 8.185 | 9.53736 | yes | Impostazioni copriferro armatura: Copriferro armatura 1 | Portante | 0 | Superficie di finitura: esterno | Livello: 1 - Piano Primo | Livello: 2 - Piano Secondo | no | 3.92
204216 | 1 - Piano Primo | 29.3216 | 7.78 | 8.79648 | yes | Impostazioni copriferro armatura: Copriferro armatura 1 | Portante | 0 | Superficie di finitura: esterno | Livello: 1 - Piano Primo | Livello: 2 - Piano Secondo | no | 3.92
204218 | 2 - Piano Secondo | 5.97698 | 7.9 | 1.75989 | no |  | Non portante | 2.25 | Superficie di finitura: esterno | Livello: 2 - Piano Secondo |  | yes | 0.25
204401 | 2 - Piano Secondo | 5.49577 | 5.67729 | 1.62507 | no |  | Non portante | 0 | Superficie di finitura: interno | Livello: 2 - Piano Secondo |  | no | 1.03
204483 | 2 - Piano Secondo | 14.9961 | 5.085 | 4.49883 | yes | Impostazioni copriferro armatura: Copriferro armatura 1 | Portante | 0 | Superficie di finitura: esterno | Livello: 2 - Piano Secondo |  | yes | 3.92
204485 | 2 - Piano Secondo | 13.0435 | 5.085 | 3.91305 | yes | Impostazioni copriferro armatura: Copriferro armatura 1 | Portante | 0 | Superficie di finitura: esterno | Livello: 2 - Piano Secondo |  | yes | 3.92
204487 | 2 - Piano Secondo | 21.1214 | 7.9 | 6.30321 | yes | Impostazioni copriferro armatura: Copriferro armatura 1 | Portante | 0 | Superficie di finitura: esterno | Livello: 2 - Piano Secondo |  | yes | 3.92
204489 | 2 - Piano Secondo | 21.6303 | 8.185 | 6.48909 | yes | Impostazioni copriferro armatura: Copriferro armatura 1 | Portante | 0 | Superficie di finitura: esterno | Livello: 2 - Piano Secondo |  | yes | 3.92
204493 | 2 - Piano Secondo | 22.1236 | 8.185 | 6.63707 | yes | Impostazioni copriferro armatura: Copriferro armatura 1 | Portante | 0 | Superficie di finitura: esterno | Livello: 2 - Piano Secondo |  | yes | 3.92
204495 | 2 - Piano Secondo | 17.0252 | 7.78 | 5.06706 | yes | Impostazioni copriferro armatura: Copriferro armatura 1 | Portante | 0 | Superficie di finitura: esterno | Livello: 2 - Piano Secondo |  | yes | 3.92
204559 | 2 - Piano Secondo | 1.9 | 7.9 | 0.57 | no |  | Non portante | 0 | Superficie di finitura: esterno | Livello: 2 - Piano Secondo |  | no | 0.25
204560 | 2 - Piano Secondo | 5.37061 | 7.78 | 1.57068 | no |  | Non portante | 2.25 | Superficie di finitura: esterno | Livello: 2 - Piano Secondo |  | yes | 0.25
204561 | 2 - Piano Secondo | 1.87 | 7.78 | 0.561 | no |  | Non portante | 0 | Superficie di finitura: esterno | Livello: 2 - Piano Secondo |  | no | 0.25
204936 | 2 - Piano Secondo | 4.75864 | 4.8 | 1.41916 | no |  | Non portante | 0 | Superficie di finitura: interno | Livello: 2 - Piano Secondo |  | no | 1.03
207311 | 1 - Piano Primo | 19.1112 | 5.085 | 5.73336 | yes | Impostazioni copriferro armatura: Copriferro armatura 1 | Portante | 0 | Superficie di finitura: esterno | Livello: 1 - Piano Primo | Livello: 2 - Piano Secondo | no | 3.92
207313 | 1 - Piano Primo | 11.44 | 3.25 | 3.432 | yes | Impostazioni copriferro armatura: Copriferro armatura 1 | Portante | 0 | Superficie di finitura: esterno | Livello: 1 - Piano Primo | Livello: 2 - Piano Secondo | yes | 3.92
208948 | 0 - Piano Terra | 34.7919 | 8.235 | 10.4376 | yes | Impostazioni copriferro armatura: Copriferro armatura 1 | Portante | 0 | Superficie di finitura: esterno | Livello: 0 - Piano Terra | Livello: 1 - Piano Primo | yes | 4.69
313624 | SF_STR_0100_XY- Fondazioni (-0,40) | 30.27 | 9.94 | 9.081 | yes | Impostazioni copriferro armatura: Copriferro armatura 1 | Portante | -3.7 | Superficie di finitura: interno | Livello: SF_STR_0100_XY- Fondazioni (-0,40) | Livello: SF_STR_0100_XY- Fondazioni (-0,40) | yes | 3.7
313881 | SF_STR_0100_XY- Fondazioni (-0,40) | 5.54997 | 1.99999 | 1.66499 | yes | Impostazioni copriferro armatura: Copriferro armatura 1 | Portante | -3.7 | Superficie di finitura: interno | Livello: SF_STR_0100_XY- Fondazioni (-0,40) | Livello: SF_STR_0100_XY- Fondazioni (-0,40) | yes | 3.7
314812 | SF_STR_0100_XY- Fondazioni (-0,40) | 30.27 | 10.09 | 9.081 | yes | Impostazioni copriferro armatura: Copriferro armatura 1 | Portante | -3.7 | Superficie di finitura: interno | Livello: SF_STR_0100_XY- Fondazioni (-0,40) | Livello: SF_STR_0100_XY- Fondazioni (-0,40) | yes | 3.7

# IfcWallStandardCase: Muro di base:Setto CA - 40 cm (5)
Type - PredefinedType: STANDARD; Material: Default - Calcestruzzo 0.4 m
Type - Altro - Categoria: Muri; Nome famiglia: Muro di base
Type - Costruzione - Funzione: Esterno; Ripiegatura agli inserti: Non ripiegare; Ripiegatura alle estremità: Nessuno; Larghezza: 0.4 m
Type - Dati identità - Nome del tipo: Setto CA - 40 cm; Nota chiave: Mb/3
Type - Grafica - Colore del retino a dettaglio basso: 0
Type - Materiali e finiture - Materiale strutturale: Default - Calcestruzzo
Type - Proprietà analitiche - Ruvidità: 3; Assorbimento: 0.7
Altro - Famiglia: Muro di base: Setto CA - 40 cm; Famiglia e tipo: Muro di base: Setto CA - 40 cm; ID tipo: Muro di base: Setto CA - 40 cm; Tipo: Muro di base: Setto CA - 40 cm
Fasi - Fase di creazione: Stato di Fatto
Vincoli - Delimita il locale: yes; Distanza estensione base: 0 m; Distanza estensione superiore: 0 m; La base è associata: no; La parte superiore è associata: no; Offset superiore: 0 m; Relativo a massa: no; Linea di ubicazione: Superficie di finitura: interno
Pset_WallCommon - ExtendToStructure: no; IsExternal: yes; Reference: Setto CA - 40 cm
Name (Muro di base:Setto CA - 40 cm:...) | In | Area (m2) | Lunghezza (m) | Volume (m3) | Attiva modello analitico = Strutturale = LoadBearing | Utilizzo strutturale | Offset base (m) | Vincolo di base | Altezza non collegata (m) | Copriferro armatura - Altre superfici = Copriferro armatura - Superficie esterna = Copriferro armatura - Superficie interna | Vincolo parte superiore
204400 | 2 - Piano Secondo | 8.89192 | 8.40528 | 3.52835 | no | Non portante | 0 | Livello: 2 - Piano Secondo | 1.03
314266 | SF_STR_0100_XY- Fondazioni (-0,40) | 31.4497 | 8.29993 | 12.5799 | yes | Portante | -3.7 | Livello: SF_STR_0100_XY- Fondazioni (-0,40) | 3.7 | Impostazioni copriferro armatura: Copriferro armatura 1 | Livello: SF_STR_0100_XY- Fondazioni (-0,40)
314387 | SF_STR_0100_XY- Fondazioni (-0,40) | 29.6 | 8.00001 | 11.84 | yes | Portante | -3.7 | Livello: SF_STR_0100_XY- Fondazioni (-0,40) | 3.7 | Impostazioni copriferro armatura: Copriferro armatura 1 | Livello: SF_STR_0100_XY- Fondazioni (-0,40)
314488 | SF_STR_0100_XY- Fondazioni (-0,40) | 29.9697 | 8.09993 | 11.9879 | yes | Portante | -3.7 | Livello: SF_STR_0100_XY- Fondazioni (-0,40) | 3.7 | Impostazioni copriferro armatura: Copriferro armatura 1 | Livello: SF_STR_0100_XY- Fondazioni (-0,40)
314615 | SF_STR_0100_XY- Fondazioni (-0,40) | 15.725 | 4.45 | 6.28999 | yes | Portante | -3.7 | Livello: SF_STR_0100_XY- Fondazioni (-0,40) | 3.7 | Impostazioni copriferro armatura: Copriferro armatura 1 | Livello: SF_STR_0100_XY- Fondazioni (-0,40)

# IfcWallStandardCase: Muro di base:Setto CA intonacato int - 41 cm (75)
Type - PredefinedType: STANDARD; Material: Intonaco - Bianco 0.01 m, Default - Calcestruzzo 0.4 m
Type - Altro - Categoria: Muri; Nome famiglia: Muro di base
Type - Costruzione - Funzione: Esterno; Ripiegatura agli inserti: Non ripiegare; Ripiegatura alle estremità: Nessuno; Larghezza: 0.41 m
Type - Dati identità - Nome del tipo: Setto CA intonacato int - 41 cm; Nota chiave: Mb/3
Type - Grafica - Colore del retino a dettaglio basso: 0
Type - Materiali e finiture - Materiale strutturale: Default - Calcestruzzo
Type - Proprietà analitiche - Ruvidità: 3; Assorbimento: 0.7
Altro - Famiglia: Muro di base: Setto CA intonacato int - 41 cm; Famiglia e tipo: Muro di base: Setto CA intonacato int - 41 cm; ID tipo: Muro di base: Setto CA intonacato int - 41 cm; Tipo: Muro di base: Setto CA intonacato int - 41 cm
Fasi - Fase di creazione: Stato di Fatto
Grafica - Contrassegno centrale visibile: no
Strutturale - Attiva modello analitico: yes; Copriferro armatura - Altre superfici: Impostazioni copriferro armatura: Copriferro armatura 1; Copriferro armatura - Superficie esterna: Impostazioni copriferro armatura: Copriferro armatura 1; Copriferro armatura - Superficie interna: Impostazioni copriferro armatura: Copriferro armatura 1; Strutturale: yes; Utilizzo strutturale: Portante
Vincoli - Delimita il locale: yes; Distanza estensione base: 0 m; Distanza estensione superiore: 0 m; La base è associata: no; Linea di ubicazione: Superficie di finitura: esterno; Offset superiore: 0 m; Relativo a massa: no
Pset_WallCommon - LoadBearing: yes; IsExternal: yes; Reference: Setto CA intonacato int - 41 cm
Name (Muro di base:Setto CA intonacato int - 41 cm:...) | In | Area (m2) | Lunghezza (m) | Volume (m3) | Offset base (m) | La parte superiore è associata = ExtendToStructure | Vincolo di base | Vincolo parte superiore | Altezza non collegata (m)
204055 | 0 - Piano Terra | 9.36813 | 1.90849 | 3.66984 | 0 | no | Livello: 0 - Piano Terra | Livello: 1 - Piano Primo | 4.69
204057 | 0 - Piano Terra | 9.28208 | 1.88136 | 3.61769 | 0 | no | Livello: 0 - Piano Terra | Livello: 1 - Piano Primo | 4.69
204059 | 0 - Piano Terra | 8.95076 | 1.80972 | 3.47993 | 0 | no | Livello: 0 - Piano Terra | Livello: 1 - Piano Primo | 4.69
204061 | 0 - Piano Terra | 15.0628 | 3.0633 | 5.89035 | 0 | no | Livello: 0 - Piano Terra | Livello: 1 - Piano Primo | 4.69
204063 | 0 - Piano Terra | 8.32972 | 1.67774 | 3.22627 | 0 | no | Livello: 0 - Piano Terra | Livello: 1 - Piano Primo | 4.69
204065 | 0 - Piano Terra | 17.0387 | 3.52307 | 6.77411 | 0 | no | Livello: 0 - Piano Terra | Livello: 1 - Piano Primo | 4.69
204067 | 0 - Piano Terra | 9.43614 | 1.93403 | 3.71899 | 0 | no | Livello: 0 - Piano Terra | Livello: 1 - Piano Primo | 4.69
204069 | 0 - Piano Terra | 4.42043 | 0.880014 | 1.69239 | 0 | no | Livello: 0 - Piano Terra | Livello: 1 - Piano Primo | 4.69
204071 | 0 - Piano Terra | 1.94697 | 0.391036 | 0.751904 | 0 | no | Livello: 0 - Piano Terra | Livello: 1 - Piano Primo | 4.69
204073 | 0 - Piano Terra | 8.89882 | 1.80015 | 3.46153 | 0 | no | Livello: 0 - Piano Terra | Livello: 1 - Piano Primo | 4.69
204075 | 0 - Piano Terra | 15.7636 | 3.20199 | 6.1571 | 0 | no | Livello: 0 - Piano Terra | Livello: 1 - Piano Primo | 4.69
204077 | 0 - Piano Terra | 8.01107 | 1.61609 | 3.10766 | 0 | no | Livello: 0 - Piano Terra | Livello: 1 - Piano Primo | 4.69
204079 | 0 - Piano Terra | 18.1896 | 3.7453 | 7.20167 | 0 | no | Livello: 0 - Piano Terra | Livello: 1 - Piano Primo | 4.69
204081 | 0 - Piano Terra | 17.7127 | 3.60036 | 6.92407 | 0 | no | Livello: 0 - Piano Terra | Livello: 1 - Piano Primo | 4.69
204083 | 0 - Piano Terra | 10.8224 | 2.19311 | 4.21711 | 0 | no | Livello: 0 - Piano Terra | Livello: 1 - Piano Primo | 4.69
204085 | 0 - Piano Terra | 8.43353 | 1.7162 | 3.30009 | 0 | no | Livello: 0 - Piano Terra | Livello: 1 - Piano Primo | 4.69
204087 | 0 - Piano Terra | 17.7627 | 3.65857 | 7.03496 | 0 | no | Livello: 0 - Piano Terra | Livello: 1 - Piano Primo | 4.69
204089 | 0 - Piano Terra | 6.64981 | 1.34433 | 2.58504 | 0 | no | Livello: 0 - Piano Terra | Livello: 1 - Piano Primo | 4.69
204091 | 0 - Piano Terra | 14.3395 | 2.9089 | 5.59351 | 0 | no | Livello: 0 - Piano Terra | Livello: 1 - Piano Primo | 4.69
204093 | 0 - Piano Terra | 10.3337 | 2.09226 | 4.0232 | 0 | no | Livello: 0 - Piano Terra | Livello: 1 - Piano Primo | 4.69
204095 | 0 - Piano Terra | 6.66974 | 1.36023 | 2.61562 | 0 | no | Livello: 0 - Piano Terra | Livello: 1 - Piano Primo | 4.69
204097 | 0 - Piano Terra | 11.4819 | 2.39562 | 4.60624 | 0 | no | Livello: 0 - Piano Terra | Livello: 1 - Piano Primo | 4.69
204099 | 0 - Piano Terra | 8.57549 | 1.72757 | 3.3222 | 0 | no | Livello: 0 - Piano Terra | Livello: 1 - Piano Primo | 4.69
204101 | 0 - Piano Terra | 6.35308 | 1.28056 | 2.46241 | 0 | no | Livello: 0 - Piano Terra | Livello: 1 - Piano Primo | 4.69
204262 | 1 - Piano Primo | 7.83008 | 1.90849 | 3.06733 | 0 | no | Livello: 1 - Piano Primo | Livello: 2 - Piano Secondo | 3.92
204264 | 1 - Piano Primo | 7.75815 | 1.88136 | 3.02374 | 0 | no | Livello: 1 - Piano Primo | Livello: 2 - Piano Secondo | 3.92
204266 | 1 - Piano Primo | 7.48123 | 1.80972 | 2.9086 | 0 | no | Livello: 1 - Piano Primo | Livello: 2 - Piano Secondo | 3.92
204268 | 1 - Piano Primo | 11.3051 | 3.0633 | 4.4209 | 0 | yes | Livello: 1 - Piano Primo | Livello: 2 - Piano Secondo | 3.92
204270 | 1 - Piano Primo | 6.25173 | 1.67774 | 2.42142 | 0 | yes | Livello: 1 - Piano Primo | Livello: 2 - Piano Secondo | 3.92
204272 | 1 - Piano Primo | 12.7881 | 3.52307 | 5.0842 | 0 | yes | Livello: 1 - Piano Primo | Livello: 2 - Piano Secondo | 3.92
204274 | 1 - Piano Primo | 7.08214 | 1.93403 | 2.79122 | 0 | yes | Livello: 1 - Piano Primo | Livello: 2 - Piano Secondo | 3.92
204276 | 1 - Piano Primo | 3.31768 | 0.880014 | 1.27019 | 0 | yes | Livello: 1 - Piano Primo | Livello: 2 - Piano Secondo | 3.92
204278 | 1 - Piano Primo | 1.46127 | 0.391036 | 0.564329 | 0 | yes | Livello: 1 - Piano Primo | Livello: 2 - Piano Secondo | 3.92
204280 | 1 - Piano Primo | 6.67886 | 1.80015 | 2.59799 | 0 | yes | Livello: 1 - Piano Primo | Livello: 2 - Piano Secondo | 3.92
204282 | 1 - Piano Primo | 13.1755 | 3.20199 | 5.14624 | 0 | no | Livello: 1 - Piano Primo | Livello: 2 - Piano Secondo | 3.92
204284 | 1 - Piano Primo | 6.69582 | 1.61609 | 2.59745 | 0 | no | Livello: 1 - Piano Primo | Livello: 2 - Piano Secondo | 3.92
204286 | 1 - Piano Primo | 15.2032 | 3.7453 | 6.01931 | 0 | no | Livello: 1 - Piano Primo | Livello: 2 - Piano Secondo | 3.92
204288 | 2 - Piano Secondo | 6.67155 | 1.90849 | 2.61349 | 0 | no | Livello: 2 - Piano Secondo | Livello: 3 - Piano Copertura | 3.34
204290 | 2 - Piano Secondo | 6.61026 | 1.88136 | 2.57635 | 0 | no | Livello: 2 - Piano Secondo | Livello: 3 - Piano Copertura | 3.34
204292 | 2 - Piano Secondo | 6.37431 | 1.80972 | 2.47824 | 0 | no | Livello: 2 - Piano Secondo | Livello: 3 - Piano Copertura | 3.34
204294 | 2 - Piano Secondo | 12.0117 | 3.0633 | 4.69721 | -0.4 | no | Livello: 2 - Piano Secondo | Livello: 3 - Piano Copertura | 3.74
204296 | 2 - Piano Secondo | 6.64246 | 1.67774 | 2.57276 | -0.4 | no | Livello: 2 - Piano Secondo | Livello: 3 - Piano Copertura | 3.74
204298 | 2 - Piano Secondo | 13.5593 | 3.52307 | 5.3907 | -0.4 | no | Livello: 2 - Piano Secondo | Livello: 3 - Piano Copertura | 3.74
204300 | 2 - Piano Secondo | 7.52477 | 1.93403 | 2.96567 | -0.4 | no | Livello: 2 - Piano Secondo | Livello: 3 - Piano Copertura | 3.74
204302 | 2 - Piano Secondo | 3.52503 | 0.880014 | 1.34958 | -0.4 | no | Livello: 2 - Piano Secondo | Livello: 3 - Piano Copertura | 3.74
204304 | 2 - Piano Secondo | 1.5526 | 0.391036 | 0.5996 | -0.4 | no | Livello: 2 - Piano Secondo | Livello: 3 - Piano Copertura | 3.74
204306 | 2 - Piano Secondo | 7.09629 | 1.80015 | 2.76036 | -0.4 | no | Livello: 2 - Piano Secondo | Livello: 3 - Piano Copertura | 3.74
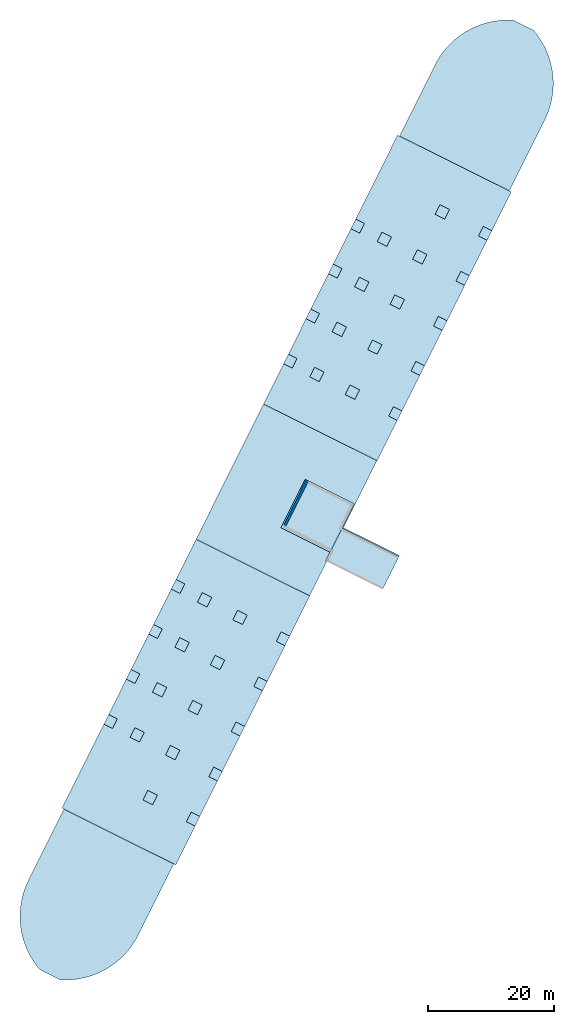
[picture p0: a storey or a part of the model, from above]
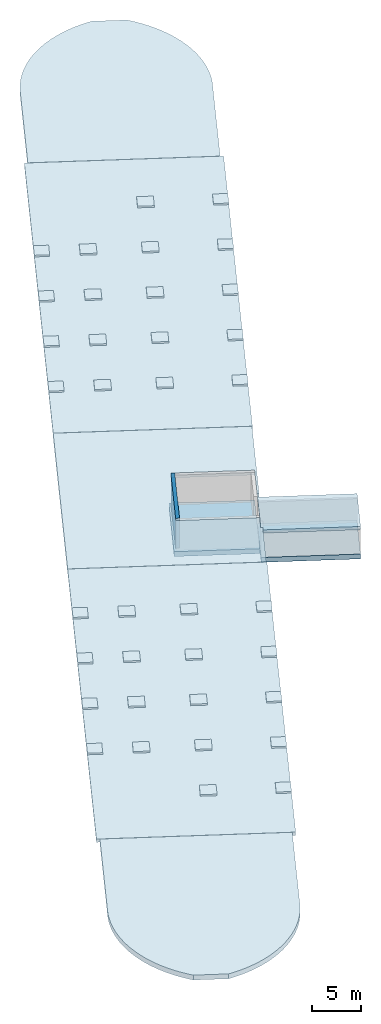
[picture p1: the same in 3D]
Properties of the parts of a building model (IFC2X3), part 7 of 7

# IfcWallStandardCase: Muro di base:Setto CA intonacato int - 41 cm (75)
Name (Muro di base:Setto CA intonacato int - 41 cm:...) | In | Area (m2) | Lunghezza (m) | Volume (m3) | Offset base (m) | La parte superiore è associata = ExtendToStructure | Vincolo di base | Vincolo parte superiore | Altezza non collegata (m)
204308 | 2 - Piano Secondo | 11.2261 | 3.20199 | 4.3848 | 0 | no | Livello: 2 - Piano Secondo | Livello: 3 - Piano Copertura | 3.34
204310 | 2 - Piano Secondo | 5.70511 | 1.61609 | 2.21313 | 0 | no | Livello: 2 - Piano Secondo | Livello: 3 - Piano Copertura | 3.34
204312 | 2 - Piano Secondo | 12.9538 | 3.7453 | 5.1287 | 0 | no | Livello: 2 - Piano Secondo | Livello: 3 - Piano Copertura | 3.34
204314 | 0 - Piano Terra | 15.8227 | 3.20971 | 6.17209 | 0 | no | Livello: 0 - Piano Terra | Livello: 1 - Piano Primo | 4.69
204316 | 1 - Piano Primo | 14.8047 | 3.60036 | 5.78728 | 0 | no | Livello: 1 - Piano Primo | Livello: 2 - Piano Secondo | 3.92
204318 | 1 - Piano Primo | 9.04557 | 2.19311 | 3.52475 | 0 | no | Livello: 1 - Piano Primo | Livello: 2 - Piano Secondo | 3.92
204320 | 1 - Piano Primo | 7.04892 | 1.7162 | 2.75828 | 0 | no | Livello: 1 - Piano Primo | Livello: 2 - Piano Secondo | 3.92
204322 | 1 - Piano Primo | 14.8464 | 3.65857 | 5.87997 | 0 | no | Livello: 1 - Piano Primo | Livello: 2 - Piano Secondo | 3.92
204324 | 1 - Piano Primo | 5.55805 | 1.34433 | 2.16063 | 0 | no | Livello: 1 - Piano Primo | Livello: 2 - Piano Secondo | 3.92
204326 | 1 - Piano Primo | 11.9853 | 2.9089 | 4.67517 | 0 | no | Livello: 1 - Piano Primo | Livello: 2 - Piano Secondo | 3.92
204328 | 1 - Piano Primo | 8.63713 | 2.09226 | 3.36267 | 0 | no | Livello: 1 - Piano Primo | Livello: 2 - Piano Secondo | 3.92
204330 | 1 - Piano Primo | 5.57471 | 1.36023 | 2.18619 | 0 | no | Livello: 1 - Piano Primo | Livello: 2 - Piano Secondo | 3.92
204332 | 1 - Piano Primo | 9.59682 | 2.39562 | 3.84999 | 0 | no | Livello: 1 - Piano Primo | Livello: 2 - Piano Secondo | 3.92
204334 | 1 - Piano Primo | 7.16757 | 1.72757 | 2.77676 | 0 | no | Livello: 1 - Piano Primo | Livello: 2 - Piano Secondo | 3.92
204336 | 1 - Piano Primo | 5.31004 | 1.28056 | 2.05813 | 0 | no | Livello: 1 - Piano Primo | Livello: 2 - Piano Secondo | 3.92
204338 | 1 - Piano Primo | 13.2249 | 3.20971 | 5.15876 | 0 | no | Livello: 1 - Piano Primo | Livello: 2 - Piano Secondo | 3.92
204340 | 2 - Piano Secondo | 12.6142 | 3.60036 | 4.931 | 0 | no | Livello: 2 - Piano Secondo | Livello: 3 - Piano Copertura | 3.34
204342 | 2 - Piano Secondo | 7.70719 | 2.19311 | 3.00323 | 0 | no | Livello: 2 - Piano Secondo | Livello: 3 - Piano Copertura | 3.34
204344 | 2 - Piano Secondo | 6.00597 | 1.7162 | 2.35017 | 0 | no | Livello: 2 - Piano Secondo | Livello: 3 - Piano Copertura | 3.34
204346 | 2 - Piano Secondo | 12.6498 | 3.65857 | 5.00997 | 0 | no | Livello: 2 - Piano Secondo | Livello: 3 - Piano Copertura | 3.34
204348 | 2 - Piano Secondo | 4.73569 | 1.34433 | 1.84095 | 0 | no | Livello: 2 - Piano Secondo | Livello: 3 - Piano Copertura | 3.34
204350 | 2 - Piano Secondo | 10.212 | 2.9089 | 3.98344 | 0 | no | Livello: 2 - Piano Secondo | Livello: 3 - Piano Copertura | 3.34
204352 | 2 - Piano Secondo | 7.35919 | 2.09226 | 2.86514 | 0 | no | Livello: 2 - Piano Secondo | Livello: 3 - Piano Copertura | 3.34
204354 | 2 - Piano Secondo | 4.71697 | 1.36023 | 1.84975 | 0 | no | Livello: 2 - Piano Secondo | Livello: 3 - Piano Copertura | 3.34
204356 | 2 - Piano Secondo | 8.17688 | 2.39562 | 3.28035 | 0 | no | Livello: 2 - Piano Secondo | Livello: 3 - Piano Copertura | 3.34
204358 | 2 - Piano Secondo | 6.10706 | 1.72757 | 2.36592 | 0 | no | Livello: 2 - Piano Secondo | Livello: 3 - Piano Copertura | 3.34
204360 | 2 - Piano Secondo | 4.52437 | 1.28056 | 1.75361 | 0 | no | Livello: 2 - Piano Secondo | Livello: 3 - Piano Copertura | 3.34
204362 | 2 - Piano Secondo | 11.2682 | 3.20971 | 4.39547 | 0 | no | Livello: 2 - Piano Secondo | Livello: 3 - Piano Copertura | 3.34

# IfcWallStandardCase: Muro di base:Setto CA rivestito est 45 (5)
Type - Altro - Categoria: Muri; Nome famiglia: Muro di base
Type - Costruzione - Funzione: Esterno; Ripiegatura agli inserti: Non ripiegare; Ripiegatura alle estremità: Nessuno; Larghezza: 0.45 m
Type - Dati identità - Nome del tipo: Setto CA rivestito est 45; Nota chiave: Mb/3
Type - Grafica - Colore del retino a dettaglio basso: 0
Type - Materiali e finiture - Materiale strutturale: Default - Calcestruzzo
Type - Proprietà analitiche - Ruvidità: 3; Assorbimento: 0.7; Coefficiente di scambio termico (U): 1533.33; Massa termica: 363285; Resistenza termica (R): 0.000652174
Material: Alluminio 0.15 m, Default - Calcestruzzo 0.3 m
Altro - Famiglia: Muro di base: Setto CA rivestito est 45; Famiglia e tipo: Muro di base: Setto CA rivestito est 45; ID tipo: Muro di base: Setto CA rivestito est 45; Tipo: Muro di base: Setto CA rivestito est 45
Fasi - Fase di creazione: Stato di Fatto
Strutturale - Attiva modello analitico: yes; Copriferro armatura - Altre superfici: Impostazioni copriferro armatura: Copriferro armatura 1; Copriferro armatura - Superficie esterna: Impostazioni copriferro armatura: Copriferro armatura 1; Copriferro armatura - Superficie interna: Impostazioni copriferro armatura: Copriferro armatura 1; Strutturale: yes; Utilizzo strutturale: Portante
Vincoli - Offset base: 0 m; Delimita il locale: yes; Distanza estensione base: 0 m; Distanza estensione superiore: 0 m; La base è associata: no; Linea di ubicazione: Superficie di finitura: esterno; Offset superiore: 0 m; Relativo a massa: no
Pset_WallCommon - LoadBearing: yes; IsExternal: yes; Reference: Setto CA rivestito est 45; ThermalTransmittance: 1533.33 kg/K/s3
Name (Muro di base:Setto CA rivestito est 45:...) | In | Area (m2) | Lunghezza (m) | Volume (m3) | La parte superiore è associata = ExtendToStructure | Vincolo di base | Vincolo parte superiore | Altezza non collegata (m)
204051 | 0 - Piano Terra | 28.0672 | 7.78 | 12.6302 | no | Livello: 0 - Piano Terra | Livello: 1 - Piano Primo | 4.69
204202 | 1 - Piano Primo | 24.605 | 7.9 | 11.0722 | no | Livello: 1 - Piano Primo | Livello: 2 - Piano Secondo | 3.92
204212 | 1 - Piano Primo | 22.9586 | 7.78 | 10.3314 | no | Livello: 1 - Piano Primo | Livello: 2 - Piano Secondo | 3.92
204481 | 2 - Piano Secondo | 26.8974 | 7.9 | 12.0232 | yes | Livello: 2 - Piano Secondo |  | 3.92
204491 | 2 - Piano Secondo | 25.4408 | 7.78 | 11.3536 | yes | Livello: 2 - Piano Secondo |  | 3.92

# IfcWallStandardCase: Muro di base:Setto CA rivestito int - 31 cm (26)
Type - PredefinedType: STANDARD; Material: Default - Calcestruzzo 0.3 m, Intonaco - Bianco 0.01 m
Type - Altro - Categoria: Muri; Nome famiglia: Muro di base
Type - Costruzione - Funzione: Esterno; Ripiegatura agli inserti: Non ripiegare; Ripiegatura alle estremità: Nessuno; Larghezza: 0.31 m
Type - Dati identità - Nome del tipo: Setto CA rivestito int - 31 cm; Nota chiave: Mb/3
Type - Grafica - Colore del retino a dettaglio basso: 0
Type - Materiali e finiture - Materiale strutturale: Default - Calcestruzzo
Type - Proprietà analitiche - Ruvidità: 3; Assorbimento: 0.7
Altro - Famiglia: Muro di base: Setto CA rivestito int - 31 cm; Famiglia e tipo: Muro di base: Setto CA rivestito int - 31 cm; ID tipo: Muro di base: Setto CA rivestito int - 31 cm; Tipo: Muro di base: Setto CA rivestito int - 31 cm
Fasi - Fase di creazione: Stato di Fatto
Strutturale - Attiva modello analitico: yes; Copriferro armatura - Altre superfici: Impostazioni copriferro armatura: Copriferro armatura 1; Copriferro armatura - Superficie esterna: Impostazioni copriferro armatura: Copriferro armatura 1; Copriferro armatura - Superficie interna: Impostazioni copriferro armatura: Copriferro armatura 1; Strutturale: yes; Utilizzo strutturale: Portante
Vincoli - Offset base: 0 m; Delimita il locale: yes; Distanza estensione base: 0 m; Distanza estensione superiore: 0 m; La base è associata: no; Linea di ubicazione: Superficie di finitura: esterno; Offset superiore: 0 m; Relativo a massa: no
Pset_WallCommon - LoadBearing: yes; IsExternal: yes; Reference: Setto CA rivestito int - 31 cm
Name (Muro di base:Setto CA rivestito int - 31 cm:...) | In | Area (m2) | Lunghezza (m) | Volume (m3) | La parte superiore è associata = ExtendToStructure | Vincolo di base | Vincolo parte superiore | Altezza non collegata (m)
204019 | 0 - Piano Terra | 26.5454 | 5.27 | 8.22907 | no | Livello: 0 - Piano Terra | Livello: 1 - Piano Primo | 4.69
204021 | 0 - Piano Terra | 24.3411 | 5.27 | 7.54574 | no | Livello: 0 - Piano Terra | Livello: 1 - Piano Primo | 4.69
204023 | 0 - Piano Terra | 30.3967 | 7.52 | 9.41114 | no | Livello: 0 - Piano Terra | Livello: 1 - Piano Primo | 4.69
204025 | 0 - Piano Terra | 26.5454 | 5.27 | 8.22907 | no | Livello: 0 - Piano Terra | Livello: 1 - Piano Primo | 4.69
204027 | 0 - Piano Terra | 26.5454 | 5.27 | 8.22907 | no | Livello: 0 - Piano Terra | Livello: 1 - Piano Primo | 4.69
204029 | 0 - Piano Terra | 32.601 | 7.99 | 10.0945 | no | Livello: 0 - Piano Terra | Livello: 1 - Piano Primo | 4.69
204035 | 0 - Piano Terra | 24.3411 | 5.27 | 7.54574 | yes | Livello: 0 - Piano Terra | Livello: 1 - Piano Primo | 4.69
204037 | 0 - Piano Terra | 24.3411 | 5.27 | 7.54574 | yes | Livello: 0 - Piano Terra | Livello: 1 - Piano Primo | 4.69
204039 | 0 - Piano Terra | 27.5127 | 7.52 | 8.5171 | yes | Livello: 0 - Piano Terra | Livello: 1 - Piano Primo | 4.69
204108 | 2 - Piano Secondo | 18.9044 | 5.27 | 5.86036 | no | Livello: 2 - Piano Secondo | Livello: 3 - Piano Copertura | 3.34
204110 | 2 - Piano Secondo | 17.3346 | 5.27 | 5.37373 | no | Livello: 2 - Piano Secondo | Livello: 3 - Piano Copertura | 3.34
204112 | 2 - Piano Secondo | 20.6414 | 7.52 | 6.39883 | no | Livello: 2 - Piano Secondo | Livello: 3 - Piano Copertura | 3.34
204116 | 2 - Piano Secondo | 17.3346 | 5.27 | 5.37373 | no | Livello: 2 - Piano Secondo | Livello: 3 - Piano Copertura | 3.34
204118 | 2 - Piano Secondo | 17.3346 | 5.27 | 5.37373 | no | Livello: 2 - Piano Secondo | Livello: 3 - Piano Copertura | 3.34
204120 | 2 - Piano Secondo | 20.6414 | 7.52 | 6.39883 | no | Livello: 2 - Piano Secondo | Livello: 3 - Piano Copertura | 3.34
204180 | 1 - Piano Primo | 22.1872 | 5.27 | 6.87803 | no | Livello: 1 - Piano Primo | Livello: 2 - Piano Secondo | 3.92
204182 | 1 - Piano Primo | 20.3448 | 5.27 | 6.30689 | no | Livello: 1 - Piano Primo | Livello: 2 - Piano Secondo | 3.92
204184 | 1 - Piano Primo | 24.8232 | 7.52 | 7.69519 | no | Livello: 1 - Piano Primo | Livello: 2 - Piano Secondo | 3.92
204186 | 1 - Piano Primo | 22.1872 | 5.27 | 6.87803 | no | Livello: 1 - Piano Primo | Livello: 2 - Piano Secondo | 3.92
204188 | 1 - Piano Primo | 22.1872 | 5.27 | 6.87803 | no | Livello: 1 - Piano Primo | Livello: 2 - Piano Secondo | 3.92
204190 | 1 - Piano Primo | 26.6656 | 7.99 | 8.26634 | no | Livello: 1 - Piano Primo | Livello: 2 - Piano Secondo | 3.92
204196 | 1 - Piano Primo | 20.3448 | 5.27 | 6.30689 | no | Livello: 1 - Piano Primo | Livello: 2 - Piano Secondo | 3.92
204198 | 1 - Piano Primo | 20.3448 | 5.27 | 6.30689 | no | Livello: 1 - Piano Primo | Livello: 2 - Piano Secondo | 3.92
204244 | 2 - Piano Secondo | 18.9044 | 5.27 | 5.86036 | no | Livello: 2 - Piano Secondo | Livello: 3 - Piano Copertura | 3.34
204246 | 2 - Piano Secondo | 18.9044 | 5.27 | 5.86036 | no | Livello: 2 - Piano Secondo | Livello: 3 - Piano Copertura | 3.34
204248 | 2 - Piano Secondo | 22.2112 | 7.99 | 6.88547 | no | Livello: 2 - Piano Secondo | Livello: 3 - Piano Copertura | 3.34

# IfcWallStandardCase: Muro di base:Setto CA rivestito int - est 32 cm (5)
Type - PredefinedType: STANDARD; Material: Intonaco - Bianco 0.01 m, Default - Calcestruzzo 0.3 m, Intonaco - Bianco 0.01 m
Type - Altro - Categoria: Muri; Nome famiglia: Muro di base
Type - Costruzione - Funzione: Esterno; Ripiegatura agli inserti: Non ripiegare; Ripiegatura alle estremità: Nessuno; Larghezza: 0.32 m
Type - Dati identità - Nome del tipo: Setto CA rivestito int - est 32 cm; Nota chiave: Mb/3
Type - Grafica - Colore del retino a dettaglio basso: 0
Type - Materiali e finiture - Materiale strutturale: Default - Calcestruzzo
Type - Proprietà analitiche - Ruvidità: 3; Assorbimento: 0.7
Altro - Famiglia: Muro di base: Setto CA rivestito int - est 32 cm; Famiglia e tipo: Muro di base: Setto CA rivestito int - est 32 cm; ID tipo: Muro di base: Setto CA rivestito int - est 32 cm; Tipo: Muro di base: Setto CA rivestito int - est 32 cm
Dimensioni - Lunghezza: 3.8 m
Fasi - Fase di creazione: Stato di Fatto
Strutturale - Attiva modello analitico: no; Strutturale: no; Utilizzo strutturale: Non portante
Vincoli - Offset base: 0 m; Delimita il locale: yes; Distanza estensione base: 0 m; Distanza estensione superiore: 0 m; La base è associata: no; Relativo a massa: no; Linea di ubicazione: Superficie di finitura: interno
Pset_WallCommon - IsExternal: yes; LoadBearing: no; Reference: Setto CA rivestito int - est 32 cm
Name (Muro di base:Setto CA rivestito int - est 32 cm:...) | In | Area (m2) | Volume (m3) | La parte superiore è associata = ExtendToStructure | Vincolo di base | Vincolo parte superiore | Altezza non collegata (m) | Offset superiore (m)
204578 | 0 - Piano Terra | 15.309 | 4.89888 | no | Livello: 0 - Piano Terra | Livello: 1 - Piano Primo | 4.2 | -0.49
205112 | 0 - Piano Terra | 15.309 | 4.89888 | yes | Livello: 0 - Piano Terra | Livello: 1 - Piano Primo | 4.69 | 0
205259 | 1 - Piano Primo | 12.7939 | 4.09406 | yes | Livello: 1 - Piano Primo | Livello: 2 - Piano Secondo | 2.99089 | -0.929111
205401 | 1 - Piano Primo | 12.794 | 4.09406 | yes | Livello: 1 - Piano Primo | Livello: 2 - Piano Secondo | 3.92 | 0
205532 | 0 - Piano Terra | 15.309 | 4.89888 | yes | Livello: 0 - Piano Terra | Livello: 1 - Piano Primo | 4.69 | 0

# IfcWallStandardCase: Muro di base:Setto CA rivestito int-est 47 cm (8)
Type - PredefinedType: STANDARD; Material: Alluminio 0.15 m, Default - Calcestruzzo 0.3 m, Intonaco - Bianco 0.02 m
Type - Altro - Categoria: Muri; Nome famiglia: Muro di base
Type - Costruzione - Funzione: Esterno; Larghezza: 0.47 m; Ripiegatura agli inserti: Non ripiegare; Ripiegatura alle estremità: Nessuno
Type - Dati identità - Nome del tipo: Setto CA rivestito int-est 47 cm; Nota chiave: Mb/3
Type - Grafica - Colore del retino a dettaglio basso: 0
Type - Materiali e finiture - Materiale strutturale: Default - Calcestruzzo
Type - Proprietà analitiche - Assorbimento: 0.7; Coefficiente di scambio termico (U): 1533.33; Massa termica: 363285; Resistenza termica (R): 0.000652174; Ruvidità: 3
Altro - Famiglia: Muro di base: Setto CA rivestito int-est 47 cm; Famiglia e tipo: Muro di base: Setto CA rivestito int-est 47 cm; ID tipo: Muro di base: Setto CA rivestito int-est 47 cm; Tipo: Muro di base: Setto CA rivestito int-est 47 cm
Fasi - Fase di creazione: Stato di Fatto
Strutturale - Attiva modello analitico: yes; Copriferro armatura - Altre superfici: Impostazioni copriferro armatura: Copriferro armatura 1; Copriferro armatura - Superficie esterna: Impostazioni copriferro armatura: Copriferro armatura 1; Copriferro armatura - Superficie interna: Impostazioni copriferro armatura: Copriferro armatura 1; Strutturale: yes; Utilizzo strutturale: Portante
Vincoli - Offset base: 0 m; Delimita il locale: yes; Distanza estensione base: 0 m; Distanza estensione superiore: 0 m; La base è associata: no; Linea di ubicazione: Superficie di finitura: esterno; Offset superiore: 0 m; Relativo a massa: no
Pset_WallCommon - Reference: Setto CA rivestito int-est 47 cm; LoadBearing: yes; IsExternal: yes; ThermalTransmittance: 1533.33 kg/K/s3
Name (Muro di base:Setto CA rivestito int-est 47 cm:...) | In | Area (m2) | Lunghezza (m) | Volume (m3) | Altezza non collegata (m) | La parte superiore è associata = ExtendToStructure | Vincolo di base | Vincolo parte superiore
204017 | 0 - Piano Terra | 31.8506 | 7.52 | 14.9579 | 4.69 | no | Livello: 0 - Piano Terra | Livello: 1 - Piano Primo
204031 | 0 - Piano Terra | 32.601 | 7.99 | 15.3106 | 4.69 | no | Livello: 0 - Piano Terra | Livello: 1 - Piano Primo
204033 | 0 - Piano Terra | 33.3045 | 7.52 | 15.6413 | 4.69 | yes | Livello: 0 - Piano Terra | Livello: 1 - Piano Primo
204106 | 2 - Piano Secondo | 20.6708 | 7.52 | 9.71528 | 3.34 | no | Livello: 2 - Piano Secondo | Livello: 3 - Piano Copertura
204114 | 2 - Piano Secondo | 21.7062 | 7.52 | 10.2019 | 3.34 | no | Livello: 2 - Piano Secondo | Livello: 3 - Piano Copertura
204192 | 1 - Piano Primo | 22.4006 | 7.99 | 10.5283 | 3.92 | no | Livello: 1 - Piano Primo | Livello: 2 - Piano Secondo
204194 | 1 - Piano Primo | 24.6636 | 7.52 | 11.5919 | 3.92 | no | Livello: 1 - Piano Primo | Livello: 2 - Piano Secondo
204250 | 2 - Piano Secondo | 19.9702 | 7.99 | 9.38599 | 3.34 | no | Livello: 2 - Piano Secondo | Livello: 3 - Piano Copertura
